VERSION 5.7 ;
BUSBITCHARS "[]" ;
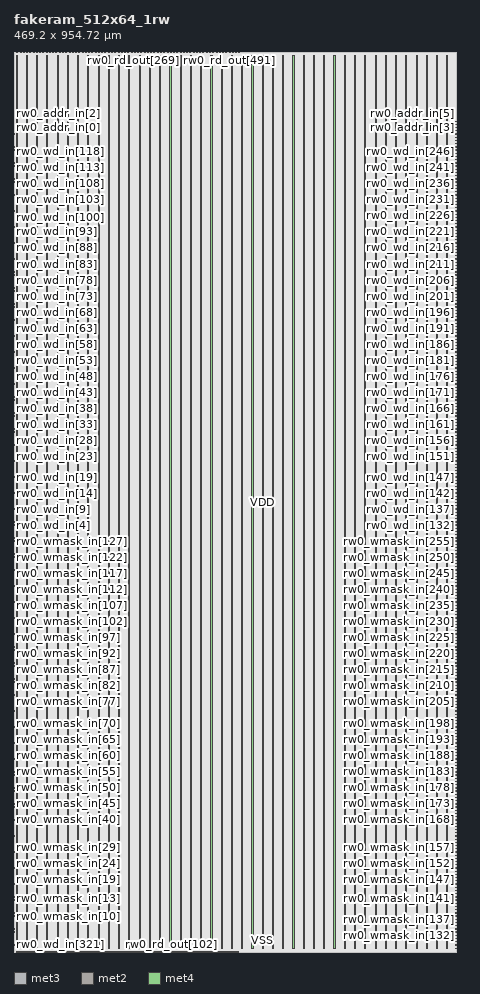
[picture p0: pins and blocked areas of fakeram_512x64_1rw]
MACRO fakeram_512x64_1rw
  FOREIGN fakeram_512x64_1rw 0 0 ;
  SYMMETRY X Y R90 ;
  SIZE 469.200 BY 954.720 ;
  CLASS BLOCK ;
  PIN rw0_wmask_in[0]
    DIRECTION INPUT ;
    USE SIGNAL ;
    SHAPE ABUTMENT ;
    PORT
      LAYER met3 ;
      RECT 0.000 3.930 0.900 4.230 ;
    END
  END rw0_wmask_in[0]
  PIN rw0_wmask_in[1]
    DIRECTION INPUT ;
    USE SIGNAL ;
    SHAPE ABUTMENT ;
    PORT
      LAYER met3 ;
      RECT 0.000 7.330 0.900 7.630 ;
    END
  END rw0_wmask_in[1]
  PIN rw0_wmask_in[2]
    DIRECTION INPUT ;
    USE SIGNAL ;
    SHAPE ABUTMENT ;
    PORT
      LAYER met3 ;
      RECT 0.000 10.730 0.900 11.030 ;
    END
  END rw0_wmask_in[2]
  PIN rw0_wmask_in[3]
    DIRECTION INPUT ;
    USE SIGNAL ;
    SHAPE ABUTMENT ;
    PORT
      LAYER met3 ;
      RECT 0.000 14.130 0.900 14.430 ;
    END
  END rw0_wmask_in[3]
  PIN rw0_wmask_in[4]
    DIRECTION INPUT ;
    USE SIGNAL ;
    SHAPE ABUTMENT ;
    PORT
      LAYER met3 ;
      RECT 0.000 17.530 0.900 17.830 ;
    END
  END rw0_wmask_in[4]
  PIN rw0_wmask_in[5]
    DIRECTION INPUT ;
    USE SIGNAL ;
    SHAPE ABUTMENT ;
    PORT
      LAYER met3 ;
      RECT 0.000 20.930 0.900 21.230 ;
    END
  END rw0_wmask_in[5]
  PIN rw0_wmask_in[6]
    DIRECTION INPUT ;
    USE SIGNAL ;
    SHAPE ABUTMENT ;
    PORT
      LAYER met3 ;
      RECT 0.000 24.330 0.900 24.630 ;
    END
  END rw0_wmask_in[6]
  PIN rw0_wmask_in[7]
    DIRECTION INPUT ;
    USE SIGNAL ;
    SHAPE ABUTMENT ;
    PORT
      LAYER met3 ;
      RECT 0.000 27.730 0.900 28.030 ;
    END
  END rw0_wmask_in[7]
  PIN rw0_wmask_in[8]
    DIRECTION INPUT ;
    USE SIGNAL ;
    SHAPE ABUTMENT ;
    PORT
      LAYER met3 ;
      RECT 0.000 31.130 0.900 31.430 ;
    END
  END rw0_wmask_in[8]
  PIN rw0_wmask_in[9]
    DIRECTION INPUT ;
    USE SIGNAL ;
    SHAPE ABUTMENT ;
    PORT
      LAYER met3 ;
      RECT 0.000 34.530 0.900 34.830 ;
    END
  END rw0_wmask_in[9]
  PIN rw0_wmask_in[10]
    DIRECTION INPUT ;
    USE SIGNAL ;
    SHAPE ABUTMENT ;
    PORT
      LAYER met3 ;
      RECT 0.000 37.930 0.900 38.230 ;
    END
  END rw0_wmask_in[10]
  PIN rw0_wmask_in[11]
    DIRECTION INPUT ;
    USE SIGNAL ;
    SHAPE ABUTMENT ;
    PORT
      LAYER met3 ;
      RECT 0.000 41.330 0.900 41.630 ;
    END
  END rw0_wmask_in[11]
  PIN rw0_wmask_in[12]
    DIRECTION INPUT ;
    USE SIGNAL ;
    SHAPE ABUTMENT ;
    PORT
      LAYER met3 ;
      RECT 0.000 44.730 0.900 45.030 ;
    END
  END rw0_wmask_in[12]
  PIN rw0_wmask_in[13]
    DIRECTION INPUT ;
    USE SIGNAL ;
    SHAPE ABUTMENT ;
    PORT
      LAYER met3 ;
      RECT 0.000 48.130 0.900 48.430 ;
    END
  END rw0_wmask_in[13]
  PIN rw0_wmask_in[14]
    DIRECTION INPUT ;
    USE SIGNAL ;
    SHAPE ABUTMENT ;
    PORT
      LAYER met3 ;
      RECT 0.000 51.530 0.900 51.830 ;
    END
  END rw0_wmask_in[14]
  PIN rw0_wmask_in[15]
    DIRECTION INPUT ;
    USE SIGNAL ;
    SHAPE ABUTMENT ;
    PORT
      LAYER met3 ;
      RECT 0.000 54.930 0.900 55.230 ;
    END
  END rw0_wmask_in[15]
  PIN rw0_wmask_in[16]
    DIRECTION INPUT ;
    USE SIGNAL ;
    SHAPE ABUTMENT ;
    PORT
      LAYER met3 ;
      RECT 0.000 58.330 0.900 58.630 ;
    END
  END rw0_wmask_in[16]
  PIN rw0_wmask_in[17]
    DIRECTION INPUT ;
    USE SIGNAL ;
    SHAPE ABUTMENT ;
    PORT
      LAYER met3 ;
      RECT 0.000 61.730 0.900 62.030 ;
    END
  END rw0_wmask_in[17]
  PIN rw0_wmask_in[18]
    DIRECTION INPUT ;
    USE SIGNAL ;
    SHAPE ABUTMENT ;
    PORT
      LAYER met3 ;
      RECT 0.000 65.130 0.900 65.430 ;
    END
  END rw0_wmask_in[18]
  PIN rw0_wmask_in[19]
    DIRECTION INPUT ;
    USE SIGNAL ;
    SHAPE ABUTMENT ;
    PORT
      LAYER met3 ;
      RECT 0.000 68.530 0.900 68.830 ;
    END
  END rw0_wmask_in[19]
  PIN rw0_wmask_in[20]
    DIRECTION INPUT ;
    USE SIGNAL ;
    SHAPE ABUTMENT ;
    PORT
      LAYER met3 ;
      RECT 0.000 71.930 0.900 72.230 ;
    END
  END rw0_wmask_in[20]
  PIN rw0_wmask_in[21]
    DIRECTION INPUT ;
    USE SIGNAL ;
    SHAPE ABUTMENT ;
    PORT
      LAYER met3 ;
      RECT 0.000 75.330 0.900 75.630 ;
    END
  END rw0_wmask_in[21]
  PIN rw0_wmask_in[22]
    DIRECTION INPUT ;
    USE SIGNAL ;
    SHAPE ABUTMENT ;
    PORT
      LAYER met3 ;
      RECT 0.000 78.730 0.900 79.030 ;
    END
  END rw0_wmask_in[22]
  PIN rw0_wmask_in[23]
    DIRECTION INPUT ;
    USE SIGNAL ;
    SHAPE ABUTMENT ;
    PORT
      LAYER met3 ;
      RECT 0.000 82.130 0.900 82.430 ;
    END
  END rw0_wmask_in[23]
  PIN rw0_wmask_in[24]
    DIRECTION INPUT ;
    USE SIGNAL ;
    SHAPE ABUTMENT ;
    PORT
      LAYER met3 ;
      RECT 0.000 85.530 0.900 85.830 ;
    END
  END rw0_wmask_in[24]
  PIN rw0_wmask_in[25]
    DIRECTION INPUT ;
    USE SIGNAL ;
    SHAPE ABUTMENT ;
    PORT
      LAYER met3 ;
      RECT 0.000 88.930 0.900 89.230 ;
    END
  END rw0_wmask_in[25]
  PIN rw0_wmask_in[26]
    DIRECTION INPUT ;
    USE SIGNAL ;
    SHAPE ABUTMENT ;
    PORT
      LAYER met3 ;
      RECT 0.000 92.330 0.900 92.630 ;
    END
  END rw0_wmask_in[26]
  PIN rw0_wmask_in[27]
    DIRECTION INPUT ;
    USE SIGNAL ;
    SHAPE ABUTMENT ;
    PORT
      LAYER met3 ;
      RECT 0.000 95.730 0.900 96.030 ;
    END
  END rw0_wmask_in[27]
  PIN rw0_wmask_in[28]
    DIRECTION INPUT ;
    USE SIGNAL ;
    SHAPE ABUTMENT ;
    PORT
      LAYER met3 ;
      RECT 0.000 99.130 0.900 99.430 ;
    END
  END rw0_wmask_in[28]
  PIN rw0_wmask_in[29]
    DIRECTION INPUT ;
    USE SIGNAL ;
    SHAPE ABUTMENT ;
    PORT
      LAYER met3 ;
      RECT 0.000 102.530 0.900 102.830 ;
    END
  END rw0_wmask_in[29]
  PIN rw0_wmask_in[30]
    DIRECTION INPUT ;
    USE SIGNAL ;
    SHAPE ABUTMENT ;
    PORT
      LAYER met3 ;
      RECT 0.000 105.930 0.900 106.230 ;
    END
  END rw0_wmask_in[30]
  PIN rw0_wmask_in[31]
    DIRECTION INPUT ;
    USE SIGNAL ;
    SHAPE ABUTMENT ;
    PORT
      LAYER met3 ;
      RECT 0.000 109.330 0.900 109.630 ;
    END
  END rw0_wmask_in[31]
  PIN rw0_wmask_in[32]
    DIRECTION INPUT ;
    USE SIGNAL ;
    SHAPE ABUTMENT ;
    PORT
      LAYER met3 ;
      RECT 0.000 112.730 0.900 113.030 ;
    END
  END rw0_wmask_in[32]
  PIN rw0_wmask_in[33]
    DIRECTION INPUT ;
    USE SIGNAL ;
    SHAPE ABUTMENT ;
    PORT
      LAYER met3 ;
      RECT 0.000 116.130 0.900 116.430 ;
    END
  END rw0_wmask_in[33]
  PIN rw0_wmask_in[34]
    DIRECTION INPUT ;
    USE SIGNAL ;
    SHAPE ABUTMENT ;
    PORT
      LAYER met3 ;
      RECT 0.000 119.530 0.900 119.830 ;
    END
  END rw0_wmask_in[34]
  PIN rw0_wmask_in[35]
    DIRECTION INPUT ;
    USE SIGNAL ;
    SHAPE ABUTMENT ;
    PORT
      LAYER met3 ;
      RECT 0.000 122.930 0.900 123.230 ;
    END
  END rw0_wmask_in[35]
  PIN rw0_wmask_in[36]
    DIRECTION INPUT ;
    USE SIGNAL ;
    SHAPE ABUTMENT ;
    PORT
      LAYER met3 ;
      RECT 0.000 126.330 0.900 126.630 ;
    END
  END rw0_wmask_in[36]
  PIN rw0_wmask_in[37]
    DIRECTION INPUT ;
    USE SIGNAL ;
    SHAPE ABUTMENT ;
    PORT
      LAYER met3 ;
      RECT 0.000 129.730 0.900 130.030 ;
    END
  END rw0_wmask_in[37]
  PIN rw0_wmask_in[38]
    DIRECTION INPUT ;
    USE SIGNAL ;
    SHAPE ABUTMENT ;
    PORT
      LAYER met3 ;
      RECT 0.000 133.130 0.900 133.430 ;
    END
  END rw0_wmask_in[38]
  PIN rw0_wmask_in[39]
    DIRECTION INPUT ;
    USE SIGNAL ;
    SHAPE ABUTMENT ;
    PORT
      LAYER met3 ;
      RECT 0.000 136.530 0.900 136.830 ;
    END
  END rw0_wmask_in[39]
  PIN rw0_wmask_in[40]
    DIRECTION INPUT ;
    USE SIGNAL ;
    SHAPE ABUTMENT ;
    PORT
      LAYER met3 ;
      RECT 0.000 139.930 0.900 140.230 ;
    END
  END rw0_wmask_in[40]
  PIN rw0_wmask_in[41]
    DIRECTION INPUT ;
    USE SIGNAL ;
    SHAPE ABUTMENT ;
    PORT
      LAYER met3 ;
      RECT 0.000 143.330 0.900 143.630 ;
    END
  END rw0_wmask_in[41]
  PIN rw0_wmask_in[42]
    DIRECTION INPUT ;
    USE SIGNAL ;
    SHAPE ABUTMENT ;
    PORT
      LAYER met3 ;
      RECT 0.000 146.730 0.900 147.030 ;
    END
  END rw0_wmask_in[42]
  PIN rw0_wmask_in[43]
    DIRECTION INPUT ;
    USE SIGNAL ;
    SHAPE ABUTMENT ;
    PORT
      LAYER met3 ;
      RECT 0.000 150.130 0.900 150.430 ;
    END
  END rw0_wmask_in[43]
  PIN rw0_wmask_in[44]
    DIRECTION INPUT ;
    USE SIGNAL ;
    SHAPE ABUTMENT ;
    PORT
      LAYER met3 ;
      RECT 0.000 153.530 0.900 153.830 ;
    END
  END rw0_wmask_in[44]
  PIN rw0_wmask_in[45]
    DIRECTION INPUT ;
    USE SIGNAL ;
    SHAPE ABUTMENT ;
    PORT
      LAYER met3 ;
      RECT 0.000 156.930 0.900 157.230 ;
    END
  END rw0_wmask_in[45]
  PIN rw0_wmask_in[46]
    DIRECTION INPUT ;
    USE SIGNAL ;
    SHAPE ABUTMENT ;
    PORT
      LAYER met3 ;
      RECT 0.000 160.330 0.900 160.630 ;
    END
  END rw0_wmask_in[46]
  PIN rw0_wmask_in[47]
    DIRECTION INPUT ;
    USE SIGNAL ;
    SHAPE ABUTMENT ;
    PORT
      LAYER met3 ;
      RECT 0.000 163.730 0.900 164.030 ;
    END
  END rw0_wmask_in[47]
  PIN rw0_wmask_in[48]
    DIRECTION INPUT ;
    USE SIGNAL ;
    SHAPE ABUTMENT ;
    PORT
      LAYER met3 ;
      RECT 0.000 167.130 0.900 167.430 ;
    END
  END rw0_wmask_in[48]
  PIN rw0_wmask_in[49]
    DIRECTION INPUT ;
    USE SIGNAL ;
    SHAPE ABUTMENT ;
    PORT
      LAYER met3 ;
      RECT 0.000 170.530 0.900 170.830 ;
    END
  END rw0_wmask_in[49]
  PIN rw0_wmask_in[50]
    DIRECTION INPUT ;
    USE SIGNAL ;
    SHAPE ABUTMENT ;
    PORT
      LAYER met3 ;
      RECT 0.000 173.930 0.900 174.230 ;
    END
  END rw0_wmask_in[50]
  PIN rw0_wmask_in[51]
    DIRECTION INPUT ;
    USE SIGNAL ;
    SHAPE ABUTMENT ;
    PORT
      LAYER met3 ;
      RECT 0.000 177.330 0.900 177.630 ;
    END
  END rw0_wmask_in[51]
  PIN rw0_wmask_in[52]
    DIRECTION INPUT ;
    USE SIGNAL ;
    SHAPE ABUTMENT ;
    PORT
      LAYER met3 ;
      RECT 0.000 180.730 0.900 181.030 ;
    END
  END rw0_wmask_in[52]
  PIN rw0_wmask_in[53]
    DIRECTION INPUT ;
    USE SIGNAL ;
    SHAPE ABUTMENT ;
    PORT
      LAYER met3 ;
      RECT 0.000 184.130 0.900 184.430 ;
    END
  END rw0_wmask_in[53]
  PIN rw0_wmask_in[54]
    DIRECTION INPUT ;
    USE SIGNAL ;
    SHAPE ABUTMENT ;
    PORT
      LAYER met3 ;
      RECT 0.000 187.530 0.900 187.830 ;
    END
  END rw0_wmask_in[54]
  PIN rw0_wmask_in[55]
    DIRECTION INPUT ;
    USE SIGNAL ;
    SHAPE ABUTMENT ;
    PORT
      LAYER met3 ;
      RECT 0.000 190.930 0.900 191.230 ;
    END
  END rw0_wmask_in[55]
  PIN rw0_wmask_in[56]
    DIRECTION INPUT ;
    USE SIGNAL ;
    SHAPE ABUTMENT ;
    PORT
      LAYER met3 ;
      RECT 0.000 194.330 0.900 194.630 ;
    END
  END rw0_wmask_in[56]
  PIN rw0_wmask_in[57]
    DIRECTION INPUT ;
    USE SIGNAL ;
    SHAPE ABUTMENT ;
    PORT
      LAYER met3 ;
      RECT 0.000 197.730 0.900 198.030 ;
    END
  END rw0_wmask_in[57]
  PIN rw0_wmask_in[58]
    DIRECTION INPUT ;
    USE SIGNAL ;
    SHAPE ABUTMENT ;
    PORT
      LAYER met3 ;
      RECT 0.000 201.130 0.900 201.430 ;
    END
  END rw0_wmask_in[58]
  PIN rw0_wmask_in[59]
    DIRECTION INPUT ;
    USE SIGNAL ;
    SHAPE ABUTMENT ;
    PORT
      LAYER met3 ;
      RECT 0.000 204.530 0.900 204.830 ;
    END
  END rw0_wmask_in[59]
  PIN rw0_wmask_in[60]
    DIRECTION INPUT ;
    USE SIGNAL ;
    SHAPE ABUTMENT ;
    PORT
      LAYER met3 ;
      RECT 0.000 207.930 0.900 208.230 ;
    END
  END rw0_wmask_in[60]
  PIN rw0_wmask_in[61]
    DIRECTION INPUT ;
    USE SIGNAL ;
    SHAPE ABUTMENT ;
    PORT
      LAYER met3 ;
      RECT 0.000 211.330 0.900 211.630 ;
    END
  END rw0_wmask_in[61]
  PIN rw0_wmask_in[62]
    DIRECTION INPUT ;
    USE SIGNAL ;
    SHAPE ABUTMENT ;
    PORT
      LAYER met3 ;
      RECT 0.000 214.730 0.900 215.030 ;
    END
  END rw0_wmask_in[62]
  PIN rw0_wmask_in[63]
    DIRECTION INPUT ;
    USE SIGNAL ;
    SHAPE ABUTMENT ;
    PORT
      LAYER met3 ;
      RECT 0.000 218.130 0.900 218.430 ;
    END
  END rw0_wmask_in[63]
  PIN rw0_wmask_in[64]
    DIRECTION INPUT ;
    USE SIGNAL ;
    SHAPE ABUTMENT ;
    PORT
      LAYER met3 ;
      RECT 0.000 221.530 0.900 221.830 ;
    END
  END rw0_wmask_in[64]
  PIN rw0_wmask_in[65]
    DIRECTION INPUT ;
    USE SIGNAL ;
    SHAPE ABUTMENT ;
    PORT
      LAYER met3 ;
      RECT 0.000 224.930 0.900 225.230 ;
    END
  END rw0_wmask_in[65]
  PIN rw0_wmask_in[66]
    DIRECTION INPUT ;
    USE SIGNAL ;
    SHAPE ABUTMENT ;
    PORT
      LAYER met3 ;
      RECT 0.000 228.330 0.900 228.630 ;
    END
  END rw0_wmask_in[66]
  PIN rw0_wmask_in[67]
    DIRECTION INPUT ;
    USE SIGNAL ;
    SHAPE ABUTMENT ;
    PORT
      LAYER met3 ;
      RECT 0.000 231.730 0.900 232.030 ;
    END
  END rw0_wmask_in[67]
  PIN rw0_wmask_in[68]
    DIRECTION INPUT ;
    USE SIGNAL ;
    SHAPE ABUTMENT ;
    PORT
      LAYER met3 ;
      RECT 0.000 235.130 0.900 235.430 ;
    END
  END rw0_wmask_in[68]
  PIN rw0_wmask_in[69]
    DIRECTION INPUT ;
    USE SIGNAL ;
    SHAPE ABUTMENT ;
    PORT
      LAYER met3 ;
      RECT 0.000 238.530 0.900 238.830 ;
    END
  END rw0_wmask_in[69]
  PIN rw0_wmask_in[70]
    DIRECTION INPUT ;
    USE SIGNAL ;
    SHAPE ABUTMENT ;
    PORT
      LAYER met3 ;
      RECT 0.000 241.930 0.900 242.230 ;
    END
  END rw0_wmask_in[70]
  PIN rw0_wmask_in[71]
    DIRECTION INPUT ;
    USE SIGNAL ;
    SHAPE ABUTMENT ;
    PORT
      LAYER met3 ;
      RECT 0.000 245.330 0.900 245.630 ;
    END
  END rw0_wmask_in[71]
  PIN rw0_wmask_in[72]
    DIRECTION INPUT ;
    USE SIGNAL ;
    SHAPE ABUTMENT ;
    PORT
      LAYER met3 ;
      RECT 0.000 248.730 0.900 249.030 ;
    END
  END rw0_wmask_in[72]
  PIN rw0_wmask_in[73]
    DIRECTION INPUT ;
    USE SIGNAL ;
    SHAPE ABUTMENT ;
    PORT
      LAYER met3 ;
      RECT 0.000 252.130 0.900 252.430 ;
    END
  END rw0_wmask_in[73]
  PIN rw0_wmask_in[74]
    DIRECTION INPUT ;
    USE SIGNAL ;
    SHAPE ABUTMENT ;
    PORT
      LAYER met3 ;
      RECT 0.000 255.530 0.900 255.830 ;
    END
  END rw0_wmask_in[74]
  PIN rw0_wmask_in[75]
    DIRECTION INPUT ;
    USE SIGNAL ;
    SHAPE ABUTMENT ;
    PORT
      LAYER met3 ;
      RECT 0.000 258.930 0.900 259.230 ;
    END
  END rw0_wmask_in[75]
  PIN rw0_wmask_in[76]
    DIRECTION INPUT ;
    USE SIGNAL ;
    SHAPE ABUTMENT ;
    PORT
      LAYER met3 ;
      RECT 0.000 262.330 0.900 262.630 ;
    END
  END rw0_wmask_in[76]
  PIN rw0_wmask_in[77]
    DIRECTION INPUT ;
    USE SIGNAL ;
    SHAPE ABUTMENT ;
    PORT
      LAYER met3 ;
      RECT 0.000 265.730 0.900 266.030 ;
    END
  END rw0_wmask_in[77]
  PIN rw0_wmask_in[78]
    DIRECTION INPUT ;
    USE SIGNAL ;
    SHAPE ABUTMENT ;
    PORT
      LAYER met3 ;
      RECT 0.000 269.130 0.900 269.430 ;
    END
  END rw0_wmask_in[78]
  PIN rw0_wmask_in[79]
    DIRECTION INPUT ;
    USE SIGNAL ;
    SHAPE ABUTMENT ;
    PORT
      LAYER met3 ;
      RECT 0.000 272.530 0.900 272.830 ;
    END
  END rw0_wmask_in[79]
  PIN rw0_wmask_in[80]
    DIRECTION INPUT ;
    USE SIGNAL ;
    SHAPE ABUTMENT ;
    PORT
      LAYER met3 ;
      RECT 0.000 275.930 0.900 276.230 ;
    END
  END rw0_wmask_in[80]
  PIN rw0_wmask_in[81]
    DIRECTION INPUT ;
    USE SIGNAL ;
    SHAPE ABUTMENT ;
    PORT
      LAYER met3 ;
      RECT 0.000 279.330 0.900 279.630 ;
    END
  END rw0_wmask_in[81]
  PIN rw0_wmask_in[82]
    DIRECTION INPUT ;
    USE SIGNAL ;
    SHAPE ABUTMENT ;
    PORT
      LAYER met3 ;
      RECT 0.000 282.730 0.900 283.030 ;
    END
  END rw0_wmask_in[82]
  PIN rw0_wmask_in[83]
    DIRECTION INPUT ;
    USE SIGNAL ;
    SHAPE ABUTMENT ;
    PORT
      LAYER met3 ;
      RECT 0.000 286.130 0.900 286.430 ;
    END
  END rw0_wmask_in[83]
  PIN rw0_wmask_in[84]
    DIRECTION INPUT ;
    USE SIGNAL ;
    SHAPE ABUTMENT ;
    PORT
      LAYER met3 ;
      RECT 0.000 289.530 0.900 289.830 ;
    END
  END rw0_wmask_in[84]
  PIN rw0_wmask_in[85]
    DIRECTION INPUT ;
    USE SIGNAL ;
    SHAPE ABUTMENT ;
    PORT
      LAYER met3 ;
      RECT 0.000 292.930 0.900 293.230 ;
    END
  END rw0_wmask_in[85]
  PIN rw0_wmask_in[86]
    DIRECTION INPUT ;
    USE SIGNAL ;
    SHAPE ABUTMENT ;
    PORT
      LAYER met3 ;
      RECT 0.000 296.330 0.900 296.630 ;
    END
  END rw0_wmask_in[86]
  PIN rw0_wmask_in[87]
    DIRECTION INPUT ;
    USE SIGNAL ;
    SHAPE ABUTMENT ;
    PORT
      LAYER met3 ;
      RECT 0.000 299.730 0.900 300.030 ;
    END
  END rw0_wmask_in[87]
  PIN rw0_wmask_in[88]
    DIRECTION INPUT ;
    USE SIGNAL ;
    SHAPE ABUTMENT ;
    PORT
      LAYER met3 ;
      RECT 0.000 303.130 0.900 303.430 ;
    END
  END rw0_wmask_in[88]
  PIN rw0_wmask_in[89]
    DIRECTION INPUT ;
    USE SIGNAL ;
    SHAPE ABUTMENT ;
    PORT
      LAYER met3 ;
      RECT 0.000 306.530 0.900 306.830 ;
    END
  END rw0_wmask_in[89]
  PIN rw0_wmask_in[90]
    DIRECTION INPUT ;
    USE SIGNAL ;
    SHAPE ABUTMENT ;
    PORT
      LAYER met3 ;
      RECT 0.000 309.930 0.900 310.230 ;
    END
  END rw0_wmask_in[90]
  PIN rw0_wmask_in[91]
    DIRECTION INPUT ;
    USE SIGNAL ;
    SHAPE ABUTMENT ;
    PORT
      LAYER met3 ;
      RECT 0.000 313.330 0.900 313.630 ;
    END
  END rw0_wmask_in[91]
  PIN rw0_wmask_in[92]
    DIRECTION INPUT ;
    USE SIGNAL ;
    SHAPE ABUTMENT ;
    PORT
      LAYER met3 ;
      RECT 0.000 316.730 0.900 317.030 ;
    END
  END rw0_wmask_in[92]
  PIN rw0_wmask_in[93]
    DIRECTION INPUT ;
    USE SIGNAL ;
    SHAPE ABUTMENT ;
    PORT
      LAYER met3 ;
      RECT 0.000 320.130 0.900 320.430 ;
    END
  END rw0_wmask_in[93]
  PIN rw0_wmask_in[94]
    DIRECTION INPUT ;
    USE SIGNAL ;
    SHAPE ABUTMENT ;
    PORT
      LAYER met3 ;
      RECT 0.000 323.530 0.900 323.830 ;
    END
  END rw0_wmask_in[94]
  PIN rw0_wmask_in[95]
    DIRECTION INPUT ;
    USE SIGNAL ;
    SHAPE ABUTMENT ;
    PORT
      LAYER met3 ;
      RECT 0.000 326.930 0.900 327.230 ;
    END
  END rw0_wmask_in[95]
  PIN rw0_wmask_in[96]
    DIRECTION INPUT ;
    USE SIGNAL ;
    SHAPE ABUTMENT ;
    PORT
      LAYER met3 ;
      RECT 0.000 330.330 0.900 330.630 ;
    END
  END rw0_wmask_in[96]
  PIN rw0_wmask_in[97]
    DIRECTION INPUT ;
    USE SIGNAL ;
    SHAPE ABUTMENT ;
    PORT
      LAYER met3 ;
      RECT 0.000 333.730 0.900 334.030 ;
    END
  END rw0_wmask_in[97]
  PIN rw0_wmask_in[98]
    DIRECTION INPUT ;
    USE SIGNAL ;
    SHAPE ABUTMENT ;
    PORT
      LAYER met3 ;
      RECT 0.000 337.130 0.900 337.430 ;
    END
  END rw0_wmask_in[98]
  PIN rw0_wmask_in[99]
    DIRECTION INPUT ;
    USE SIGNAL ;
    SHAPE ABUTMENT ;
    PORT
      LAYER met3 ;
      RECT 0.000 340.530 0.900 340.830 ;
    END
  END rw0_wmask_in[99]
  PIN rw0_wmask_in[100]
    DIRECTION INPUT ;
    USE SIGNAL ;
    SHAPE ABUTMENT ;
    PORT
      LAYER met3 ;
      RECT 0.000 343.930 0.900 344.230 ;
    END
  END rw0_wmask_in[100]
  PIN rw0_wmask_in[101]
    DIRECTION INPUT ;
    USE SIGNAL ;
    SHAPE ABUTMENT ;
    PORT
      LAYER met3 ;
      RECT 0.000 347.330 0.900 347.630 ;
    END
  END rw0_wmask_in[101]
  PIN rw0_wmask_in[102]
    DIRECTION INPUT ;
    USE SIGNAL ;
    SHAPE ABUTMENT ;
    PORT
      LAYER met3 ;
      RECT 0.000 350.730 0.900 351.030 ;
    END
  END rw0_wmask_in[102]
  PIN rw0_wmask_in[103]
    DIRECTION INPUT ;
    USE SIGNAL ;
    SHAPE ABUTMENT ;
    PORT
      LAYER met3 ;
      RECT 0.000 354.130 0.900 354.430 ;
    END
  END rw0_wmask_in[103]
  PIN rw0_wmask_in[104]
    DIRECTION INPUT ;
    USE SIGNAL ;
    SHAPE ABUTMENT ;
    PORT
      LAYER met3 ;
      RECT 0.000 357.530 0.900 357.830 ;
    END
  END rw0_wmask_in[104]
  PIN rw0_wmask_in[105]
    DIRECTION INPUT ;
    USE SIGNAL ;
    SHAPE ABUTMENT ;
    PORT
      LAYER met3 ;
      RECT 0.000 360.930 0.900 361.230 ;
    END
  END rw0_wmask_in[105]
  PIN rw0_wmask_in[106]
    DIRECTION INPUT ;
    USE SIGNAL ;
    SHAPE ABUTMENT ;
    PORT
      LAYER met3 ;
      RECT 0.000 364.330 0.900 364.630 ;
    END
  END rw0_wmask_in[106]
  PIN rw0_wmask_in[107]
    DIRECTION INPUT ;
    USE SIGNAL ;
    SHAPE ABUTMENT ;
    PORT
      LAYER met3 ;
      RECT 0.000 367.730 0.900 368.030 ;
    END
  END rw0_wmask_in[107]
  PIN rw0_wmask_in[108]
    DIRECTION INPUT ;
    USE SIGNAL ;
    SHAPE ABUTMENT ;
    PORT
      LAYER met3 ;
      RECT 0.000 371.130 0.900 371.430 ;
    END
  END rw0_wmask_in[108]
  PIN rw0_wmask_in[109]
    DIRECTION INPUT ;
    USE SIGNAL ;
    SHAPE ABUTMENT ;
    PORT
      LAYER met3 ;
      RECT 0.000 374.530 0.900 374.830 ;
    END
  END rw0_wmask_in[109]
  PIN rw0_wmask_in[110]
    DIRECTION INPUT ;
    USE SIGNAL ;
    SHAPE ABUTMENT ;
    PORT
      LAYER met3 ;
      RECT 0.000 377.930 0.900 378.230 ;
    END
  END rw0_wmask_in[110]
  PIN rw0_wmask_in[111]
    DIRECTION INPUT ;
    USE SIGNAL ;
    SHAPE ABUTMENT ;
    PORT
      LAYER met3 ;
      RECT 0.000 381.330 0.900 381.630 ;
    END
  END rw0_wmask_in[111]
  PIN rw0_wmask_in[112]
    DIRECTION INPUT ;
    USE SIGNAL ;
    SHAPE ABUTMENT ;
    PORT
      LAYER met3 ;
      RECT 0.000 384.730 0.900 385.030 ;
    END
  END rw0_wmask_in[112]
  PIN rw0_wmask_in[113]
    DIRECTION INPUT ;
    USE SIGNAL ;
    SHAPE ABUTMENT ;
    PORT
      LAYER met3 ;
      RECT 0.000 388.130 0.900 388.430 ;
    END
  END rw0_wmask_in[113]
  PIN rw0_wmask_in[114]
    DIRECTION INPUT ;
    USE SIGNAL ;
    SHAPE ABUTMENT ;
    PORT
      LAYER met3 ;
      RECT 0.000 391.530 0.900 391.830 ;
    END
  END rw0_wmask_in[114]
  PIN rw0_wmask_in[115]
    DIRECTION INPUT ;
    USE SIGNAL ;
    SHAPE ABUTMENT ;
    PORT
      LAYER met3 ;
      RECT 0.000 394.930 0.900 395.230 ;
    END
  END rw0_wmask_in[115]
  PIN rw0_wmask_in[116]
    DIRECTION INPUT ;
    USE SIGNAL ;
    SHAPE ABUTMENT ;
    PORT
      LAYER met3 ;
      RECT 0.000 398.330 0.900 398.630 ;
    END
  END rw0_wmask_in[116]
  PIN rw0_wmask_in[117]
    DIRECTION INPUT ;
    USE SIGNAL ;
    SHAPE ABUTMENT ;
    PORT
      LAYER met3 ;
      RECT 0.000 401.730 0.900 402.030 ;
    END
  END rw0_wmask_in[117]
  PIN rw0_wmask_in[118]
    DIRECTION INPUT ;
    USE SIGNAL ;
    SHAPE ABUTMENT ;
    PORT
      LAYER met3 ;
      RECT 0.000 405.130 0.900 405.430 ;
    END
  END rw0_wmask_in[118]
  PIN rw0_wmask_in[119]
    DIRECTION INPUT ;
    USE SIGNAL ;
    SHAPE ABUTMENT ;
    PORT
      LAYER met3 ;
      RECT 0.000 408.530 0.900 408.830 ;
    END
  END rw0_wmask_in[119]
  PIN rw0_wmask_in[120]
    DIRECTION INPUT ;
    USE SIGNAL ;
    SHAPE ABUTMENT ;
    PORT
      LAYER met3 ;
      RECT 0.000 411.930 0.900 412.230 ;
    END
  END rw0_wmask_in[120]
  PIN rw0_wmask_in[121]
    DIRECTION INPUT ;
    USE SIGNAL ;
    SHAPE ABUTMENT ;
    PORT
      LAYER met3 ;
      RECT 0.000 415.330 0.900 415.630 ;
    END
  END rw0_wmask_in[121]
  PIN rw0_wmask_in[122]
    DIRECTION INPUT ;
    USE SIGNAL ;
    SHAPE ABUTMENT ;
    PORT
      LAYER met3 ;
      RECT 0.000 418.730 0.900 419.030 ;
    END
  END rw0_wmask_in[122]
  PIN rw0_wmask_in[123]
    DIRECTION INPUT ;
    USE SIGNAL ;
    SHAPE ABUTMENT ;
    PORT
      LAYER met3 ;
      RECT 0.000 422.130 0.900 422.430 ;
    END
  END rw0_wmask_in[123]
  PIN rw0_wmask_in[124]
    DIRECTION INPUT ;
    USE SIGNAL ;
    SHAPE ABUTMENT ;
    PORT
      LAYER met3 ;
      RECT 0.000 425.530 0.900 425.830 ;
    END
  END rw0_wmask_in[124]
  PIN rw0_wmask_in[125]
    DIRECTION INPUT ;
    USE SIGNAL ;
    SHAPE ABUTMENT ;
    PORT
      LAYER met3 ;
      RECT 0.000 428.930 0.900 429.230 ;
    END
  END rw0_wmask_in[125]
  PIN rw0_wmask_in[126]
    DIRECTION INPUT ;
    USE SIGNAL ;
    SHAPE ABUTMENT ;
    PORT
      LAYER met3 ;
      RECT 0.000 432.330 0.900 432.630 ;
    END
  END rw0_wmask_in[126]
  PIN rw0_wmask_in[127]
    DIRECTION INPUT ;
    USE SIGNAL ;
    SHAPE ABUTMENT ;
    PORT
      LAYER met3 ;
      RECT 0.000 435.730 0.900 436.030 ;
    END
  END rw0_wmask_in[127]
  PIN rw0_wmask_in[128]
    DIRECTION INPUT ;
    USE SIGNAL ;
    SHAPE ABUTMENT ;
    PORT
      LAYER met3 ;
      RECT 468.300 3.930 469.200 4.230 ;
    END
  END rw0_wmask_in[128]
  PIN rw0_wmask_in[129]
    DIRECTION INPUT ;
    USE SIGNAL ;
    SHAPE ABUTMENT ;
    PORT
      LAYER met3 ;
      RECT 468.300 7.330 469.200 7.630 ;
    END
  END rw0_wmask_in[129]
  PIN rw0_wmask_in[130]
    DIRECTION INPUT ;
    USE SIGNAL ;
    SHAPE ABUTMENT ;
    PORT
      LAYER met3 ;
      RECT 468.300 10.730 469.200 11.030 ;
    END
  END rw0_wmask_in[130]
  PIN rw0_wmask_in[131]
    DIRECTION INPUT ;
    USE SIGNAL ;
    SHAPE ABUTMENT ;
    PORT
      LAYER met3 ;
      RECT 468.300 14.130 469.200 14.430 ;
    END
  END rw0_wmask_in[131]
  PIN rw0_wmask_in[132]
    DIRECTION INPUT ;
    USE SIGNAL ;
    SHAPE ABUTMENT ;
    PORT
      LAYER met3 ;
      RECT 468.300 17.530 469.200 17.830 ;
    END
  END rw0_wmask_in[132]
  PIN rw0_wmask_in[133]
    DIRECTION INPUT ;
    USE SIGNAL ;
    SHAPE ABUTMENT ;
    PORT
      LAYER met3 ;
      RECT 468.300 20.930 469.200 21.230 ;
    END
  END rw0_wmask_in[133]
  PIN rw0_wmask_in[134]
    DIRECTION INPUT ;
    USE SIGNAL ;
    SHAPE ABUTMENT ;
    PORT
      LAYER met3 ;
      RECT 468.300 24.330 469.200 24.630 ;
    END
  END rw0_wmask_in[134]
  PIN rw0_wmask_in[135]
    DIRECTION INPUT ;
    USE SIGNAL ;
    SHAPE ABUTMENT ;
    PORT
      LAYER met3 ;
      RECT 468.300 27.730 469.200 28.030 ;
    END
  END rw0_wmask_in[135]
  PIN rw0_wmask_in[136]
    DIRECTION INPUT ;
    USE SIGNAL ;
    SHAPE ABUTMENT ;
    PORT
      LAYER met3 ;
      RECT 468.300 31.130 469.200 31.430 ;
    END
  END rw0_wmask_in[136]
  PIN rw0_wmask_in[137]
    DIRECTION INPUT ;
    USE SIGNAL ;
    SHAPE ABUTMENT ;
    PORT
      LAYER met3 ;
      RECT 468.300 34.530 469.200 34.830 ;
    END
  END rw0_wmask_in[137]
  PIN rw0_wmask_in[138]
    DIRECTION INPUT ;
    USE SIGNAL ;
    SHAPE ABUTMENT ;
    PORT
      LAYER met3 ;
      RECT 468.300 37.930 469.200 38.230 ;
    END
  END rw0_wmask_in[138]
  PIN rw0_wmask_in[139]
    DIRECTION INPUT ;
    USE SIGNAL ;
    SHAPE ABUTMENT ;
    PORT
      LAYER met3 ;
      RECT 468.300 41.330 469.200 41.630 ;
    END
  END rw0_wmask_in[139]
  PIN rw0_wmask_in[140]
    DIRECTION INPUT ;
    USE SIGNAL ;
    SHAPE ABUTMENT ;
    PORT
      LAYER met3 ;
      RECT 468.300 44.730 469.200 45.030 ;
    END
  END rw0_wmask_in[140]
  PIN rw0_wmask_in[141]
    DIRECTION INPUT ;
    USE SIGNAL ;
    SHAPE ABUTMENT ;
    PORT
      LAYER met3 ;
      RECT 468.300 48.130 469.200 48.430 ;
    END
  END rw0_wmask_in[141]
  PIN rw0_wmask_in[142]
    DIRECTION INPUT ;
    USE SIGNAL ;
    SHAPE ABUTMENT ;
    PORT
      LAYER met3 ;
      RECT 468.300 51.530 469.200 51.830 ;
    END
  END rw0_wmask_in[142]
  PIN rw0_wmask_in[143]
    DIRECTION INPUT ;
    USE SIGNAL ;
    SHAPE ABUTMENT ;
    PORT
      LAYER met3 ;
      RECT 468.300 54.930 469.200 55.230 ;
    END
  END rw0_wmask_in[143]
  PIN rw0_wmask_in[144]
    DIRECTION INPUT ;
    USE SIGNAL ;
    SHAPE ABUTMENT ;
    PORT
      LAYER met3 ;
      RECT 468.300 58.330 469.200 58.630 ;
    END
  END rw0_wmask_in[144]
  PIN rw0_wmask_in[145]
    DIRECTION INPUT ;
    USE SIGNAL ;
    SHAPE ABUTMENT ;
    PORT
      LAYER met3 ;
      RECT 468.300 61.730 469.200 62.030 ;
    END
  END rw0_wmask_in[145]
  PIN rw0_wmask_in[146]
    DIRECTION INPUT ;
    USE SIGNAL ;
    SHAPE ABUTMENT ;
    PORT
      LAYER met3 ;
      RECT 468.300 65.130 469.200 65.430 ;
    END
  END rw0_wmask_in[146]
  PIN rw0_wmask_in[147]
    DIRECTION INPUT ;
    USE SIGNAL ;
    SHAPE ABUTMENT ;
    PORT
      LAYER met3 ;
      RECT 468.300 68.530 469.200 68.830 ;
    END
  END rw0_wmask_in[147]
  PIN rw0_wmask_in[148]
    DIRECTION INPUT ;
    USE SIGNAL ;
    SHAPE ABUTMENT ;
    PORT
      LAYER met3 ;
      RECT 468.300 71.930 469.200 72.230 ;
    END
  END rw0_wmask_in[148]
  PIN rw0_wmask_in[149]
    DIRECTION INPUT ;
    USE SIGNAL ;
    SHAPE ABUTMENT ;
    PORT
      LAYER met3 ;
      RECT 468.300 75.330 469.200 75.630 ;
    END
  END rw0_wmask_in[149]
  PIN rw0_wmask_in[150]
    DIRECTION INPUT ;
    USE SIGNAL ;
    SHAPE ABUTMENT ;
    PORT
      LAYER met3 ;
      RECT 468.300 78.730 469.200 79.030 ;
    END
  END rw0_wmask_in[150]
  PIN rw0_wmask_in[151]
    DIRECTION INPUT ;
    USE SIGNAL ;
    SHAPE ABUTMENT ;
    PORT
      LAYER met3 ;
      RECT 468.300 82.130 469.200 82.430 ;
    END
  END rw0_wmask_in[151]
  PIN rw0_wmask_in[152]
    DIRECTION INPUT ;
    USE SIGNAL ;
    SHAPE ABUTMENT ;
    PORT
      LAYER met3 ;
      RECT 468.300 85.530 469.200 85.830 ;
    END
  END rw0_wmask_in[152]
  PIN rw0_wmask_in[153]
    DIRECTION INPUT ;
    USE SIGNAL ;
    SHAPE ABUTMENT ;
    PORT
      LAYER met3 ;
      RECT 468.300 88.930 469.200 89.230 ;
    END
  END rw0_wmask_in[153]
  PIN rw0_wmask_in[154]
    DIRECTION INPUT ;
    USE SIGNAL ;
    SHAPE ABUTMENT ;
    PORT
      LAYER met3 ;
      RECT 468.300 92.330 469.200 92.630 ;
    END
  END rw0_wmask_in[154]
  PIN rw0_wmask_in[155]
    DIRECTION INPUT ;
    USE SIGNAL ;
    SHAPE ABUTMENT ;
    PORT
      LAYER met3 ;
      RECT 468.300 95.730 469.200 96.030 ;
    END
  END rw0_wmask_in[155]
  PIN rw0_wmask_in[156]
    DIRECTION INPUT ;
    USE SIGNAL ;
    SHAPE ABUTMENT ;
    PORT
      LAYER met3 ;
      RECT 468.300 99.130 469.200 99.430 ;
    END
  END rw0_wmask_in[156]
  PIN rw0_wmask_in[157]
    DIRECTION INPUT ;
    USE SIGNAL ;
    SHAPE ABUTMENT ;
    PORT
      LAYER met3 ;
      RECT 468.300 102.530 469.200 102.830 ;
    END
  END rw0_wmask_in[157]
  PIN rw0_wmask_in[158]
    DIRECTION INPUT ;
    USE SIGNAL ;
    SHAPE ABUTMENT ;
    PORT
      LAYER met3 ;
      RECT 468.300 105.930 469.200 106.230 ;
    END
  END rw0_wmask_in[158]
  PIN rw0_wmask_in[159]
    DIRECTION INPUT ;
    USE SIGNAL ;
    SHAPE ABUTMENT ;
    PORT
      LAYER met3 ;
      RECT 468.300 109.330 469.200 109.630 ;
    END
  END rw0_wmask_in[159]
  PIN rw0_wmask_in[160]
    DIRECTION INPUT ;
    USE SIGNAL ;
    SHAPE ABUTMENT ;
    PORT
      LAYER met3 ;
      RECT 468.300 112.730 469.200 113.030 ;
    END
  END rw0_wmask_in[160]
  PIN rw0_wmask_in[161]
    DIRECTION INPUT ;
    USE SIGNAL ;
    SHAPE ABUTMENT ;
    PORT
      LAYER met3 ;
      RECT 468.300 116.130 469.200 116.430 ;
    END
  END rw0_wmask_in[161]
  PIN rw0_wmask_in[162]
    DIRECTION INPUT ;
    USE SIGNAL ;
    SHAPE ABUTMENT ;
    PORT
      LAYER met3 ;
      RECT 468.300 119.530 469.200 119.830 ;
    END
  END rw0_wmask_in[162]
  PIN rw0_wmask_in[163]
    DIRECTION INPUT ;
    USE SIGNAL ;
    SHAPE ABUTMENT ;
    PORT
      LAYER met3 ;
      RECT 468.300 122.930 469.200 123.230 ;
    END
  END rw0_wmask_in[163]
  PIN rw0_wmask_in[164]
    DIRECTION INPUT ;
    USE SIGNAL ;
    SHAPE ABUTMENT ;
    PORT
      LAYER met3 ;
      RECT 468.300 126.330 469.200 126.630 ;
    END
  END rw0_wmask_in[164]
  PIN rw0_wmask_in[165]
    DIRECTION INPUT ;
    USE SIGNAL ;
    SHAPE ABUTMENT ;
    PORT
      LAYER met3 ;
      RECT 468.300 129.730 469.200 130.030 ;
    END
  END rw0_wmask_in[165]
  PIN rw0_wmask_in[166]
    DIRECTION INPUT ;
    USE SIGNAL ;
    SHAPE ABUTMENT ;
    PORT
      LAYER met3 ;
      RECT 468.300 133.130 469.200 133.430 ;
    END
  END rw0_wmask_in[166]
  PIN rw0_wmask_in[167]
    DIRECTION INPUT ;
    USE SIGNAL ;
    SHAPE ABUTMENT ;
    PORT
      LAYER met3 ;
      RECT 468.300 136.530 469.200 136.830 ;
    END
  END rw0_wmask_in[167]
  PIN rw0_wmask_in[168]
    DIRECTION INPUT ;
    USE SIGNAL ;
    SHAPE ABUTMENT ;
    PORT
      LAYER met3 ;
      RECT 468.300 139.930 469.200 140.230 ;
    END
  END rw0_wmask_in[168]
  PIN rw0_wmask_in[169]
    DIRECTION INPUT ;
    USE SIGNAL ;
    SHAPE ABUTMENT ;
    PORT
      LAYER met3 ;
      RECT 468.300 143.330 469.200 143.630 ;
    END
  END rw0_wmask_in[169]
  PIN rw0_wmask_in[170]
    DIRECTION INPUT ;
    USE SIGNAL ;
    SHAPE ABUTMENT ;
    PORT
      LAYER met3 ;
      RECT 468.300 146.730 469.200 147.030 ;
    END
  END rw0_wmask_in[170]
  PIN rw0_wmask_in[171]
    DIRECTION INPUT ;
    USE SIGNAL ;
    SHAPE ABUTMENT ;
    PORT
      LAYER met3 ;
      RECT 468.300 150.130 469.200 150.430 ;
    END
  END rw0_wmask_in[171]
  PIN rw0_wmask_in[172]
    DIRECTION INPUT ;
    USE SIGNAL ;
    SHAPE ABUTMENT ;
    PORT
      LAYER met3 ;
      RECT 468.300 153.530 469.200 153.830 ;
    END
  END rw0_wmask_in[172]
  PIN rw0_wmask_in[173]
    DIRECTION INPUT ;
    USE SIGNAL ;
    SHAPE ABUTMENT ;
    PORT
      LAYER met3 ;
      RECT 468.300 156.930 469.200 157.230 ;
    END
  END rw0_wmask_in[173]
  PIN rw0_wmask_in[174]
    DIRECTION INPUT ;
    USE SIGNAL ;
    SHAPE ABUTMENT ;
    PORT
      LAYER met3 ;
      RECT 468.300 160.330 469.200 160.630 ;
    END
  END rw0_wmask_in[174]
  PIN rw0_wmask_in[175]
    DIRECTION INPUT ;
    USE SIGNAL ;
    SHAPE ABUTMENT ;
    PORT
      LAYER met3 ;
      RECT 468.300 163.730 469.200 164.030 ;
    END
  END rw0_wmask_in[175]
  PIN rw0_wmask_in[176]
    DIRECTION INPUT ;
    USE SIGNAL ;
    SHAPE ABUTMENT ;
    PORT
      LAYER met3 ;
      RECT 468.300 167.130 469.200 167.430 ;
    END
  END rw0_wmask_in[176]
  PIN rw0_wmask_in[177]
    DIRECTION INPUT ;
    USE SIGNAL ;
    SHAPE ABUTMENT ;
    PORT
      LAYER met3 ;
      RECT 468.300 170.530 469.200 170.830 ;
    END
  END rw0_wmask_in[177]
  PIN rw0_wmask_in[178]
    DIRECTION INPUT ;
    USE SIGNAL ;
    SHAPE ABUTMENT ;
    PORT
      LAYER met3 ;
      RECT 468.300 173.930 469.200 174.230 ;
    END
  END rw0_wmask_in[178]
  PIN rw0_wmask_in[179]
    DIRECTION INPUT ;
    USE SIGNAL ;
    SHAPE ABUTMENT ;
    PORT
      LAYER met3 ;
      RECT 468.300 177.330 469.200 177.630 ;
    END
  END rw0_wmask_in[179]
  PIN rw0_wmask_in[180]
    DIRECTION INPUT ;
    USE SIGNAL ;
    SHAPE ABUTMENT ;
    PORT
      LAYER met3 ;
      RECT 468.300 180.730 469.200 181.030 ;
    END
  END rw0_wmask_in[180]
  PIN rw0_wmask_in[181]
    DIRECTION INPUT ;
    USE SIGNAL ;
    SHAPE ABUTMENT ;
    PORT
      LAYER met3 ;
      RECT 468.300 184.130 469.200 184.430 ;
    END
  END rw0_wmask_in[181]
  PIN rw0_wmask_in[182]
    DIRECTION INPUT ;
    USE SIGNAL ;
    SHAPE ABUTMENT ;
    PORT
      LAYER met3 ;
      RECT 468.300 187.530 469.200 187.830 ;
    END
  END rw0_wmask_in[182]
  PIN rw0_wmask_in[183]
    DIRECTION INPUT ;
    USE SIGNAL ;
    SHAPE ABUTMENT ;
    PORT
      LAYER met3 ;
      RECT 468.300 190.930 469.200 191.230 ;
    END
  END rw0_wmask_in[183]
  PIN rw0_wmask_in[184]
    DIRECTION INPUT ;
    USE SIGNAL ;
    SHAPE ABUTMENT ;
    PORT
      LAYER met3 ;
      RECT 468.300 194.330 469.200 194.630 ;
    END
  END rw0_wmask_in[184]
  PIN rw0_wmask_in[185]
    DIRECTION INPUT ;
    USE SIGNAL ;
    SHAPE ABUTMENT ;
    PORT
      LAYER met3 ;
      RECT 468.300 197.730 469.200 198.030 ;
    END
  END rw0_wmask_in[185]
  PIN rw0_wmask_in[186]
    DIRECTION INPUT ;
    USE SIGNAL ;
    SHAPE ABUTMENT ;
    PORT
      LAYER met3 ;
      RECT 468.300 201.130 469.200 201.430 ;
    END
  END rw0_wmask_in[186]
  PIN rw0_wmask_in[187]
    DIRECTION INPUT ;
    USE SIGNAL ;
    SHAPE ABUTMENT ;
    PORT
      LAYER met3 ;
      RECT 468.300 204.530 469.200 204.830 ;
    END
  END rw0_wmask_in[187]
  PIN rw0_wmask_in[188]
    DIRECTION INPUT ;
    USE SIGNAL ;
    SHAPE ABUTMENT ;
    PORT
      LAYER met3 ;
      RECT 468.300 207.930 469.200 208.230 ;
    END
  END rw0_wmask_in[188]
  PIN rw0_wmask_in[189]
    DIRECTION INPUT ;
    USE SIGNAL ;
    SHAPE ABUTMENT ;
    PORT
      LAYER met3 ;
      RECT 468.300 211.330 469.200 211.630 ;
    END
  END rw0_wmask_in[189]
  PIN rw0_wmask_in[190]
    DIRECTION INPUT ;
    USE SIGNAL ;
    SHAPE ABUTMENT ;
    PORT
      LAYER met3 ;
      RECT 468.300 214.730 469.200 215.030 ;
    END
  END rw0_wmask_in[190]
  PIN rw0_wmask_in[191]
    DIRECTION INPUT ;
    USE SIGNAL ;
    SHAPE ABUTMENT ;
    PORT
      LAYER met3 ;
      RECT 468.300 218.130 469.200 218.430 ;
    END
  END rw0_wmask_in[191]
  PIN rw0_wmask_in[192]
    DIRECTION INPUT ;
    USE SIGNAL ;
    SHAPE ABUTMENT ;
    PORT
      LAYER met3 ;
      RECT 468.300 221.530 469.200 221.830 ;
    END
  END rw0_wmask_in[192]
  PIN rw0_wmask_in[193]
    DIRECTION INPUT ;
    USE SIGNAL ;
    SHAPE ABUTMENT ;
    PORT
      LAYER met3 ;
      RECT 468.300 224.930 469.200 225.230 ;
    END
  END rw0_wmask_in[193]
  PIN rw0_wmask_in[194]
    DIRECTION INPUT ;
    USE SIGNAL ;
    SHAPE ABUTMENT ;
    PORT
      LAYER met3 ;
      RECT 468.300 228.330 469.200 228.630 ;
    END
  END rw0_wmask_in[194]
  PIN rw0_wmask_in[195]
    DIRECTION INPUT ;
    USE SIGNAL ;
    SHAPE ABUTMENT ;
    PORT
      LAYER met3 ;
      RECT 468.300 231.730 469.200 232.030 ;
    END
  END rw0_wmask_in[195]
  PIN rw0_wmask_in[196]
    DIRECTION INPUT ;
    USE SIGNAL ;
    SHAPE ABUTMENT ;
    PORT
      LAYER met3 ;
      RECT 468.300 235.130 469.200 235.430 ;
    END
  END rw0_wmask_in[196]
  PIN rw0_wmask_in[197]
    DIRECTION INPUT ;
    USE SIGNAL ;
    SHAPE ABUTMENT ;
    PORT
      LAYER met3 ;
      RECT 468.300 238.530 469.200 238.830 ;
    END
  END rw0_wmask_in[197]
  PIN rw0_wmask_in[198]
    DIRECTION INPUT ;
    USE SIGNAL ;
    SHAPE ABUTMENT ;
    PORT
      LAYER met3 ;
      RECT 468.300 241.930 469.200 242.230 ;
    END
  END rw0_wmask_in[198]
  PIN rw0_wmask_in[199]
    DIRECTION INPUT ;
    USE SIGNAL ;
    SHAPE ABUTMENT ;
    PORT
      LAYER met3 ;
      RECT 468.300 245.330 469.200 245.630 ;
    END
  END rw0_wmask_in[199]
  PIN rw0_wmask_in[200]
    DIRECTION INPUT ;
    USE SIGNAL ;
    SHAPE ABUTMENT ;
    PORT
      LAYER met3 ;
      RECT 468.300 248.730 469.200 249.030 ;
    END
  END rw0_wmask_in[200]
  PIN rw0_wmask_in[201]
    DIRECTION INPUT ;
    USE SIGNAL ;
    SHAPE ABUTMENT ;
    PORT
      LAYER met3 ;
      RECT 468.300 252.130 469.200 252.430 ;
    END
  END rw0_wmask_in[201]
  PIN rw0_wmask_in[202]
    DIRECTION INPUT ;
    USE SIGNAL ;
    SHAPE ABUTMENT ;
    PORT
      LAYER met3 ;
      RECT 468.300 255.530 469.200 255.830 ;
    END
  END rw0_wmask_in[202]
  PIN rw0_wmask_in[203]
    DIRECTION INPUT ;
    USE SIGNAL ;
    SHAPE ABUTMENT ;
    PORT
      LAYER met3 ;
      RECT 468.300 258.930 469.200 259.230 ;
    END
  END rw0_wmask_in[203]
  PIN rw0_wmask_in[204]
    DIRECTION INPUT ;
    USE SIGNAL ;
    SHAPE ABUTMENT ;
    PORT
      LAYER met3 ;
      RECT 468.300 262.330 469.200 262.630 ;
    END
  END rw0_wmask_in[204]
  PIN rw0_wmask_in[205]
    DIRECTION INPUT ;
    USE SIGNAL ;
    SHAPE ABUTMENT ;
    PORT
      LAYER met3 ;
      RECT 468.300 265.730 469.200 266.030 ;
    END
  END rw0_wmask_in[205]
  PIN rw0_wmask_in[206]
    DIRECTION INPUT ;
    USE SIGNAL ;
    SHAPE ABUTMENT ;
    PORT
      LAYER met3 ;
      RECT 468.300 269.130 469.200 269.430 ;
    END
  END rw0_wmask_in[206]
  PIN rw0_wmask_in[207]
    DIRECTION INPUT ;
    USE SIGNAL ;
    SHAPE ABUTMENT ;
    PORT
      LAYER met3 ;
      RECT 468.300 272.530 469.200 272.830 ;
    END
  END rw0_wmask_in[207]
  PIN rw0_wmask_in[208]
    DIRECTION INPUT ;
    USE SIGNAL ;
    SHAPE ABUTMENT ;
    PORT
      LAYER met3 ;
      RECT 468.300 275.930 469.200 276.230 ;
    END
  END rw0_wmask_in[208]
  PIN rw0_wmask_in[209]
    DIRECTION INPUT ;
    USE SIGNAL ;
    SHAPE ABUTMENT ;
    PORT
      LAYER met3 ;
      RECT 468.300 279.330 469.200 279.630 ;
    END
  END rw0_wmask_in[209]
  PIN rw0_wmask_in[210]
    DIRECTION INPUT ;
    USE SIGNAL ;
    SHAPE ABUTMENT ;
    PORT
      LAYER met3 ;
      RECT 468.300 282.730 469.200 283.030 ;
    END
  END rw0_wmask_in[210]
  PIN rw0_wmask_in[211]
    DIRECTION INPUT ;
    USE SIGNAL ;
    SHAPE ABUTMENT ;
    PORT
      LAYER met3 ;
      RECT 468.300 286.130 469.200 286.430 ;
    END
  END rw0_wmask_in[211]
  PIN rw0_wmask_in[212]
    DIRECTION INPUT ;
    USE SIGNAL ;
    SHAPE ABUTMENT ;
    PORT
      LAYER met3 ;
      RECT 468.300 289.530 469.200 289.830 ;
    END
  END rw0_wmask_in[212]
  PIN rw0_wmask_in[213]
    DIRECTION INPUT ;
    USE SIGNAL ;
    SHAPE ABUTMENT ;
    PORT
      LAYER met3 ;
      RECT 468.300 292.930 469.200 293.230 ;
    END
  END rw0_wmask_in[213]
  PIN rw0_wmask_in[214]
    DIRECTION INPUT ;
    USE SIGNAL ;
    SHAPE ABUTMENT ;
    PORT
      LAYER met3 ;
      RECT 468.300 296.330 469.200 296.630 ;
    END
  END rw0_wmask_in[214]
  PIN rw0_wmask_in[215]
    DIRECTION INPUT ;
    USE SIGNAL ;
    SHAPE ABUTMENT ;
    PORT
      LAYER met3 ;
      RECT 468.300 299.730 469.200 300.030 ;
    END
  END rw0_wmask_in[215]
  PIN rw0_wmask_in[216]
    DIRECTION INPUT ;
    USE SIGNAL ;
    SHAPE ABUTMENT ;
    PORT
      LAYER met3 ;
      RECT 468.300 303.130 469.200 303.430 ;
    END
  END rw0_wmask_in[216]
  PIN rw0_wmask_in[217]
    DIRECTION INPUT ;
    USE SIGNAL ;
    SHAPE ABUTMENT ;
    PORT
      LAYER met3 ;
      RECT 468.300 306.530 469.200 306.830 ;
    END
  END rw0_wmask_in[217]
  PIN rw0_wmask_in[218]
    DIRECTION INPUT ;
    USE SIGNAL ;
    SHAPE ABUTMENT ;
    PORT
      LAYER met3 ;
      RECT 468.300 309.930 469.200 310.230 ;
    END
  END rw0_wmask_in[218]
  PIN rw0_wmask_in[219]
    DIRECTION INPUT ;
    USE SIGNAL ;
    SHAPE ABUTMENT ;
    PORT
      LAYER met3 ;
      RECT 468.300 313.330 469.200 313.630 ;
    END
  END rw0_wmask_in[219]
  PIN rw0_wmask_in[220]
    DIRECTION INPUT ;
    USE SIGNAL ;
    SHAPE ABUTMENT ;
    PORT
      LAYER met3 ;
      RECT 468.300 316.730 469.200 317.030 ;
    END
  END rw0_wmask_in[220]
  PIN rw0_wmask_in[221]
    DIRECTION INPUT ;
    USE SIGNAL ;
    SHAPE ABUTMENT ;
    PORT
      LAYER met3 ;
      RECT 468.300 320.130 469.200 320.430 ;
    END
  END rw0_wmask_in[221]
  PIN rw0_wmask_in[222]
    DIRECTION INPUT ;
    USE SIGNAL ;
    SHAPE ABUTMENT ;
    PORT
      LAYER met3 ;
      RECT 468.300 323.530 469.200 323.830 ;
    END
  END rw0_wmask_in[222]
  PIN rw0_wmask_in[223]
    DIRECTION INPUT ;
    USE SIGNAL ;
    SHAPE ABUTMENT ;
    PORT
      LAYER met3 ;
      RECT 468.300 326.930 469.200 327.230 ;
    END
  END rw0_wmask_in[223]
  PIN rw0_wmask_in[224]
    DIRECTION INPUT ;
    USE SIGNAL ;
    SHAPE ABUTMENT ;
    PORT
      LAYER met3 ;
      RECT 468.300 330.330 469.200 330.630 ;
    END
  END rw0_wmask_in[224]
  PIN rw0_wmask_in[225]
    DIRECTION INPUT ;
    USE SIGNAL ;
    SHAPE ABUTMENT ;
    PORT
      LAYER met3 ;
      RECT 468.300 333.730 469.200 334.030 ;
    END
  END rw0_wmask_in[225]
  PIN rw0_wmask_in[226]
    DIRECTION INPUT ;
    USE SIGNAL ;
    SHAPE ABUTMENT ;
    PORT
      LAYER met3 ;
      RECT 468.300 337.130 469.200 337.430 ;
    END
  END rw0_wmask_in[226]
  PIN rw0_wmask_in[227]
    DIRECTION INPUT ;
    USE SIGNAL ;
    SHAPE ABUTMENT ;
    PORT
      LAYER met3 ;
      RECT 468.300 340.530 469.200 340.830 ;
    END
  END rw0_wmask_in[227]
  PIN rw0_wmask_in[228]
    DIRECTION INPUT ;
    USE SIGNAL ;
    SHAPE ABUTMENT ;
    PORT
      LAYER met3 ;
      RECT 468.300 343.930 469.200 344.230 ;
    END
  END rw0_wmask_in[228]
  PIN rw0_wmask_in[229]
    DIRECTION INPUT ;
    USE SIGNAL ;
    SHAPE ABUTMENT ;
    PORT
      LAYER met3 ;
      RECT 468.300 347.330 469.200 347.630 ;
    END
  END rw0_wmask_in[229]
  PIN rw0_wmask_in[230]
    DIRECTION INPUT ;
    USE SIGNAL ;
    SHAPE ABUTMENT ;
    PORT
      LAYER met3 ;
      RECT 468.300 350.730 469.200 351.030 ;
    END
  END rw0_wmask_in[230]
  PIN rw0_wmask_in[231]
    DIRECTION INPUT ;
    USE SIGNAL ;
    SHAPE ABUTMENT ;
    PORT
      LAYER met3 ;
      RECT 468.300 354.130 469.200 354.430 ;
    END
  END rw0_wmask_in[231]
  PIN rw0_wmask_in[232]
    DIRECTION INPUT ;
    USE SIGNAL ;
    SHAPE ABUTMENT ;
    PORT
      LAYER met3 ;
      RECT 468.300 357.530 469.200 357.830 ;
    END
  END rw0_wmask_in[232]
  PIN rw0_wmask_in[233]
    DIRECTION INPUT ;
    USE SIGNAL ;
    SHAPE ABUTMENT ;
    PORT
      LAYER met3 ;
      RECT 468.300 360.930 469.200 361.230 ;
    END
  END rw0_wmask_in[233]
  PIN rw0_wmask_in[234]
    DIRECTION INPUT ;
    USE SIGNAL ;
    SHAPE ABUTMENT ;
    PORT
      LAYER met3 ;
      RECT 468.300 364.330 469.200 364.630 ;
    END
  END rw0_wmask_in[234]
  PIN rw0_wmask_in[235]
    DIRECTION INPUT ;
    USE SIGNAL ;
    SHAPE ABUTMENT ;
    PORT
      LAYER met3 ;
      RECT 468.300 367.730 469.200 368.030 ;
    END
  END rw0_wmask_in[235]
  PIN rw0_wmask_in[236]
    DIRECTION INPUT ;
    USE SIGNAL ;
    SHAPE ABUTMENT ;
    PORT
      LAYER met3 ;
      RECT 468.300 371.130 469.200 371.430 ;
    END
  END rw0_wmask_in[236]
  PIN rw0_wmask_in[237]
    DIRECTION INPUT ;
    USE SIGNAL ;
    SHAPE ABUTMENT ;
    PORT
      LAYER met3 ;
      RECT 468.300 374.530 469.200 374.830 ;
    END
  END rw0_wmask_in[237]
  PIN rw0_wmask_in[238]
    DIRECTION INPUT ;
    USE SIGNAL ;
    SHAPE ABUTMENT ;
    PORT
      LAYER met3 ;
      RECT 468.300 377.930 469.200 378.230 ;
    END
  END rw0_wmask_in[238]
  PIN rw0_wmask_in[239]
    DIRECTION INPUT ;
    USE SIGNAL ;
    SHAPE ABUTMENT ;
    PORT
      LAYER met3 ;
      RECT 468.300 381.330 469.200 381.630 ;
    END
  END rw0_wmask_in[239]
  PIN rw0_wmask_in[240]
    DIRECTION INPUT ;
    USE SIGNAL ;
    SHAPE ABUTMENT ;
    PORT
      LAYER met3 ;
      RECT 468.300 384.730 469.200 385.030 ;
    END
  END rw0_wmask_in[240]
  PIN rw0_wmask_in[241]
    DIRECTION INPUT ;
    USE SIGNAL ;
    SHAPE ABUTMENT ;
    PORT
      LAYER met3 ;
      RECT 468.300 388.130 469.200 388.430 ;
    END
  END rw0_wmask_in[241]
  PIN rw0_wmask_in[242]
    DIRECTION INPUT ;
    USE SIGNAL ;
    SHAPE ABUTMENT ;
    PORT
      LAYER met3 ;
      RECT 468.300 391.530 469.200 391.830 ;
    END
  END rw0_wmask_in[242]
  PIN rw0_wmask_in[243]
    DIRECTION INPUT ;
    USE SIGNAL ;
    SHAPE ABUTMENT ;
    PORT
      LAYER met3 ;
      RECT 468.300 394.930 469.200 395.230 ;
    END
  END rw0_wmask_in[243]
  PIN rw0_wmask_in[244]
    DIRECTION INPUT ;
    USE SIGNAL ;
    SHAPE ABUTMENT ;
    PORT
      LAYER met3 ;
      RECT 468.300 398.330 469.200 398.630 ;
    END
  END rw0_wmask_in[244]
  PIN rw0_wmask_in[245]
    DIRECTION INPUT ;
    USE SIGNAL ;
    SHAPE ABUTMENT ;
    PORT
      LAYER met3 ;
      RECT 468.300 401.730 469.200 402.030 ;
    END
  END rw0_wmask_in[245]
  PIN rw0_wmask_in[246]
    DIRECTION INPUT ;
    USE SIGNAL ;
    SHAPE ABUTMENT ;
    PORT
      LAYER met3 ;
      RECT 468.300 405.130 469.200 405.430 ;
    END
  END rw0_wmask_in[246]
  PIN rw0_wmask_in[247]
    DIRECTION INPUT ;
    USE SIGNAL ;
    SHAPE ABUTMENT ;
    PORT
      LAYER met3 ;
      RECT 468.300 408.530 469.200 408.830 ;
    END
  END rw0_wmask_in[247]
  PIN rw0_wmask_in[248]
    DIRECTION INPUT ;
    USE SIGNAL ;
    SHAPE ABUTMENT ;
    PORT
      LAYER met3 ;
      RECT 468.300 411.930 469.200 412.230 ;
    END
  END rw0_wmask_in[248]
  PIN rw0_wmask_in[249]
    DIRECTION INPUT ;
    USE SIGNAL ;
    SHAPE ABUTMENT ;
    PORT
      LAYER met3 ;
      RECT 468.300 415.330 469.200 415.630 ;
    END
  END rw0_wmask_in[249]
  PIN rw0_wmask_in[250]
    DIRECTION INPUT ;
    USE SIGNAL ;
    SHAPE ABUTMENT ;
    PORT
      LAYER met3 ;
      RECT 468.300 418.730 469.200 419.030 ;
    END
  END rw0_wmask_in[250]
  PIN rw0_wmask_in[251]
    DIRECTION INPUT ;
    USE SIGNAL ;
    SHAPE ABUTMENT ;
    PORT
      LAYER met3 ;
      RECT 468.300 422.130 469.200 422.430 ;
    END
  END rw0_wmask_in[251]
  PIN rw0_wmask_in[252]
    DIRECTION INPUT ;
    USE SIGNAL ;
    SHAPE ABUTMENT ;
    PORT
      LAYER met3 ;
      RECT 468.300 425.530 469.200 425.830 ;
    END
  END rw0_wmask_in[252]
  PIN rw0_wmask_in[253]
    DIRECTION INPUT ;
    USE SIGNAL ;
    SHAPE ABUTMENT ;
    PORT
      LAYER met3 ;
      RECT 468.300 428.930 469.200 429.230 ;
    END
  END rw0_wmask_in[253]
  PIN rw0_wmask_in[254]
    DIRECTION INPUT ;
    USE SIGNAL ;
    SHAPE ABUTMENT ;
    PORT
      LAYER met3 ;
      RECT 468.300 432.330 469.200 432.630 ;
    END
  END rw0_wmask_in[254]
  PIN rw0_wmask_in[255]
    DIRECTION INPUT ;
    USE SIGNAL ;
    SHAPE ABUTMENT ;
    PORT
      LAYER met3 ;
      RECT 468.300 435.730 469.200 436.030 ;
    END
  END rw0_wmask_in[255]
  PIN rw0_wmask_in[256]
    DIRECTION INPUT ;
    USE SIGNAL ;
    SHAPE ABUTMENT ;
    PORT
      LAYER met2 ;
      RECT 2.690 954.300 2.830 954.720 ;
    END
  END rw0_wmask_in[256]
  PIN rw0_wmask_in[257]
    DIRECTION INPUT ;
    USE SIGNAL ;
    SHAPE ABUTMENT ;
    PORT
      LAYER met2 ;
      RECT 3.150 954.300 3.290 954.720 ;
    END
  END rw0_wmask_in[257]
  PIN rw0_wmask_in[258]
    DIRECTION INPUT ;
    USE SIGNAL ;
    SHAPE ABUTMENT ;
    PORT
      LAYER met2 ;
      RECT 3.610 954.300 3.750 954.720 ;
    END
  END rw0_wmask_in[258]
  PIN rw0_wmask_in[259]
    DIRECTION INPUT ;
    USE SIGNAL ;
    SHAPE ABUTMENT ;
    PORT
      LAYER met2 ;
      RECT 4.070 954.300 4.210 954.720 ;
    END
  END rw0_wmask_in[259]
  PIN rw0_wmask_in[260]
    DIRECTION INPUT ;
    USE SIGNAL ;
    SHAPE ABUTMENT ;
    PORT
      LAYER met2 ;
      RECT 4.530 954.300 4.670 954.720 ;
    END
  END rw0_wmask_in[260]
  PIN rw0_wmask_in[261]
    DIRECTION INPUT ;
    USE SIGNAL ;
    SHAPE ABUTMENT ;
    PORT
      LAYER met2 ;
      RECT 4.990 954.300 5.130 954.720 ;
    END
  END rw0_wmask_in[261]
  PIN rw0_wmask_in[262]
    DIRECTION INPUT ;
    USE SIGNAL ;
    SHAPE ABUTMENT ;
    PORT
      LAYER met2 ;
      RECT 5.450 954.300 5.590 954.720 ;
    END
  END rw0_wmask_in[262]
  PIN rw0_wmask_in[263]
    DIRECTION INPUT ;
    USE SIGNAL ;
    SHAPE ABUTMENT ;
    PORT
      LAYER met2 ;
      RECT 5.910 954.300 6.050 954.720 ;
    END
  END rw0_wmask_in[263]
  PIN rw0_wmask_in[264]
    DIRECTION INPUT ;
    USE SIGNAL ;
    SHAPE ABUTMENT ;
    PORT
      LAYER met2 ;
      RECT 6.370 954.300 6.510 954.720 ;
    END
  END rw0_wmask_in[264]
  PIN rw0_wmask_in[265]
    DIRECTION INPUT ;
    USE SIGNAL ;
    SHAPE ABUTMENT ;
    PORT
      LAYER met2 ;
      RECT 6.830 954.300 6.970 954.720 ;
    END
  END rw0_wmask_in[265]
  PIN rw0_wmask_in[266]
    DIRECTION INPUT ;
    USE SIGNAL ;
    SHAPE ABUTMENT ;
    PORT
      LAYER met2 ;
      RECT 7.290 954.300 7.430 954.720 ;
    END
  END rw0_wmask_in[266]
  PIN rw0_wmask_in[267]
    DIRECTION INPUT ;
    USE SIGNAL ;
    SHAPE ABUTMENT ;
    PORT
      LAYER met2 ;
      RECT 7.750 954.300 7.890 954.720 ;
    END
  END rw0_wmask_in[267]
  PIN rw0_wmask_in[268]
    DIRECTION INPUT ;
    USE SIGNAL ;
    SHAPE ABUTMENT ;
    PORT
      LAYER met2 ;
      RECT 8.210 954.300 8.350 954.720 ;
    END
  END rw0_wmask_in[268]
  PIN rw0_wmask_in[269]
    DIRECTION INPUT ;
    USE SIGNAL ;
    SHAPE ABUTMENT ;
    PORT
      LAYER met2 ;
      RECT 8.670 954.300 8.810 954.720 ;
    END
  END rw0_wmask_in[269]
  PIN rw0_wmask_in[270]
    DIRECTION INPUT ;
    USE SIGNAL ;
    SHAPE ABUTMENT ;
    PORT
      LAYER met2 ;
      RECT 9.130 954.300 9.270 954.720 ;
    END
  END rw0_wmask_in[270]
  PIN rw0_wmask_in[271]
    DIRECTION INPUT ;
    USE SIGNAL ;
    SHAPE ABUTMENT ;
    PORT
      LAYER met2 ;
      RECT 9.590 954.300 9.730 954.720 ;
    END
  END rw0_wmask_in[271]
  PIN rw0_wmask_in[272]
    DIRECTION INPUT ;
    USE SIGNAL ;
    SHAPE ABUTMENT ;
    PORT
      LAYER met2 ;
      RECT 10.050 954.300 10.190 954.720 ;
    END
  END rw0_wmask_in[272]
  PIN rw0_wmask_in[273]
    DIRECTION INPUT ;
    USE SIGNAL ;
    SHAPE ABUTMENT ;
    PORT
      LAYER met2 ;
      RECT 10.510 954.300 10.650 954.720 ;
    END
  END rw0_wmask_in[273]
  PIN rw0_wmask_in[274]
    DIRECTION INPUT ;
    USE SIGNAL ;
    SHAPE ABUTMENT ;
    PORT
      LAYER met2 ;
      RECT 10.970 954.300 11.110 954.720 ;
    END
  END rw0_wmask_in[274]
  PIN rw0_wmask_in[275]
    DIRECTION INPUT ;
    USE SIGNAL ;
    SHAPE ABUTMENT ;
    PORT
      LAYER met2 ;
      RECT 11.430 954.300 11.570 954.720 ;
    END
  END rw0_wmask_in[275]
  PIN rw0_wmask_in[276]
    DIRECTION INPUT ;
    USE SIGNAL ;
    SHAPE ABUTMENT ;
    PORT
      LAYER met2 ;
      RECT 11.890 954.300 12.030 954.720 ;
    END
  END rw0_wmask_in[276]
  PIN rw0_wmask_in[277]
    DIRECTION INPUT ;
    USE SIGNAL ;
    SHAPE ABUTMENT ;
    PORT
      LAYER met2 ;
      RECT 12.350 954.300 12.490 954.720 ;
    END
  END rw0_wmask_in[277]
  PIN rw0_wmask_in[278]
    DIRECTION INPUT ;
    USE SIGNAL ;
    SHAPE ABUTMENT ;
    PORT
      LAYER met2 ;
      RECT 12.810 954.300 12.950 954.720 ;
    END
  END rw0_wmask_in[278]
  PIN rw0_wmask_in[279]
    DIRECTION INPUT ;
    USE SIGNAL ;
    SHAPE ABUTMENT ;
    PORT
      LAYER met2 ;
      RECT 13.270 954.300 13.410 954.720 ;
    END
  END rw0_wmask_in[279]
  PIN rw0_wmask_in[280]
    DIRECTION INPUT ;
    USE SIGNAL ;
    SHAPE ABUTMENT ;
    PORT
      LAYER met2 ;
      RECT 13.730 954.300 13.870 954.720 ;
    END
  END rw0_wmask_in[280]
  PIN rw0_wmask_in[281]
    DIRECTION INPUT ;
    USE SIGNAL ;
    SHAPE ABUTMENT ;
    PORT
      LAYER met2 ;
      RECT 14.190 954.300 14.330 954.720 ;
    END
  END rw0_wmask_in[281]
  PIN rw0_wmask_in[282]
    DIRECTION INPUT ;
    USE SIGNAL ;
    SHAPE ABUTMENT ;
    PORT
      LAYER met2 ;
      RECT 14.650 954.300 14.790 954.720 ;
    END
  END rw0_wmask_in[282]
  PIN rw0_wmask_in[283]
    DIRECTION INPUT ;
    USE SIGNAL ;
    SHAPE ABUTMENT ;
    PORT
      LAYER met2 ;
      RECT 15.110 954.300 15.250 954.720 ;
    END
  END rw0_wmask_in[283]
  PIN rw0_wmask_in[284]
    DIRECTION INPUT ;
    USE SIGNAL ;
    SHAPE ABUTMENT ;
    PORT
      LAYER met2 ;
      RECT 15.570 954.300 15.710 954.720 ;
    END
  END rw0_wmask_in[284]
  PIN rw0_wmask_in[285]
    DIRECTION INPUT ;
    USE SIGNAL ;
    SHAPE ABUTMENT ;
    PORT
      LAYER met2 ;
      RECT 16.030 954.300 16.170 954.720 ;
    END
  END rw0_wmask_in[285]
  PIN rw0_wmask_in[286]
    DIRECTION INPUT ;
    USE SIGNAL ;
    SHAPE ABUTMENT ;
    PORT
      LAYER met2 ;
      RECT 16.490 954.300 16.630 954.720 ;
    END
  END rw0_wmask_in[286]
  PIN rw0_wmask_in[287]
    DIRECTION INPUT ;
    USE SIGNAL ;
    SHAPE ABUTMENT ;
    PORT
      LAYER met2 ;
      RECT 16.950 954.300 17.090 954.720 ;
    END
  END rw0_wmask_in[287]
  PIN rw0_wmask_in[288]
    DIRECTION INPUT ;
    USE SIGNAL ;
    SHAPE ABUTMENT ;
    PORT
      LAYER met2 ;
      RECT 17.410 954.300 17.550 954.720 ;
    END
  END rw0_wmask_in[288]
  PIN rw0_wmask_in[289]
    DIRECTION INPUT ;
    USE SIGNAL ;
    SHAPE ABUTMENT ;
    PORT
      LAYER met2 ;
      RECT 17.870 954.300 18.010 954.720 ;
    END
  END rw0_wmask_in[289]
  PIN rw0_wmask_in[290]
    DIRECTION INPUT ;
    USE SIGNAL ;
    SHAPE ABUTMENT ;
    PORT
      LAYER met2 ;
      RECT 18.330 954.300 18.470 954.720 ;
    END
  END rw0_wmask_in[290]
  PIN rw0_wmask_in[291]
    DIRECTION INPUT ;
    USE SIGNAL ;
    SHAPE ABUTMENT ;
    PORT
      LAYER met2 ;
      RECT 18.790 954.300 18.930 954.720 ;
    END
  END rw0_wmask_in[291]
  PIN rw0_wmask_in[292]
    DIRECTION INPUT ;
    USE SIGNAL ;
    SHAPE ABUTMENT ;
    PORT
      LAYER met2 ;
      RECT 19.250 954.300 19.390 954.720 ;
    END
  END rw0_wmask_in[292]
  PIN rw0_wmask_in[293]
    DIRECTION INPUT ;
    USE SIGNAL ;
    SHAPE ABUTMENT ;
    PORT
      LAYER met2 ;
      RECT 19.710 954.300 19.850 954.720 ;
    END
  END rw0_wmask_in[293]
  PIN rw0_wmask_in[294]
    DIRECTION INPUT ;
    USE SIGNAL ;
    SHAPE ABUTMENT ;
    PORT
      LAYER met2 ;
      RECT 20.170 954.300 20.310 954.720 ;
    END
  END rw0_wmask_in[294]
  PIN rw0_wmask_in[295]
    DIRECTION INPUT ;
    USE SIGNAL ;
    SHAPE ABUTMENT ;
    PORT
      LAYER met2 ;
      RECT 20.630 954.300 20.770 954.720 ;
    END
  END rw0_wmask_in[295]
  PIN rw0_wmask_in[296]
    DIRECTION INPUT ;
    USE SIGNAL ;
    SHAPE ABUTMENT ;
    PORT
      LAYER met2 ;
      RECT 21.090 954.300 21.230 954.720 ;
    END
  END rw0_wmask_in[296]
  PIN rw0_wmask_in[297]
    DIRECTION INPUT ;
    USE SIGNAL ;
    SHAPE ABUTMENT ;
    PORT
      LAYER met2 ;
      RECT 21.550 954.300 21.690 954.720 ;
    END
  END rw0_wmask_in[297]
  PIN rw0_wmask_in[298]
    DIRECTION INPUT ;
    USE SIGNAL ;
    SHAPE ABUTMENT ;
    PORT
      LAYER met2 ;
      RECT 22.010 954.300 22.150 954.720 ;
    END
  END rw0_wmask_in[298]
  PIN rw0_wmask_in[299]
    DIRECTION INPUT ;
    USE SIGNAL ;
    SHAPE ABUTMENT ;
    PORT
      LAYER met2 ;
      RECT 22.470 954.300 22.610 954.720 ;
    END
  END rw0_wmask_in[299]
  PIN rw0_wmask_in[300]
    DIRECTION INPUT ;
    USE SIGNAL ;
    SHAPE ABUTMENT ;
    PORT
      LAYER met2 ;
      RECT 22.930 954.300 23.070 954.720 ;
    END
  END rw0_wmask_in[300]
  PIN rw0_wmask_in[301]
    DIRECTION INPUT ;
    USE SIGNAL ;
    SHAPE ABUTMENT ;
    PORT
      LAYER met2 ;
      RECT 23.390 954.300 23.530 954.720 ;
    END
  END rw0_wmask_in[301]
  PIN rw0_wmask_in[302]
    DIRECTION INPUT ;
    USE SIGNAL ;
    SHAPE ABUTMENT ;
    PORT
      LAYER met2 ;
      RECT 23.850 954.300 23.990 954.720 ;
    END
  END rw0_wmask_in[302]
  PIN rw0_wmask_in[303]
    DIRECTION INPUT ;
    USE SIGNAL ;
    SHAPE ABUTMENT ;
    PORT
      LAYER met2 ;
      RECT 24.310 954.300 24.450 954.720 ;
    END
  END rw0_wmask_in[303]
  PIN rw0_wmask_in[304]
    DIRECTION INPUT ;
    USE SIGNAL ;
    SHAPE ABUTMENT ;
    PORT
      LAYER met2 ;
      RECT 24.770 954.300 24.910 954.720 ;
    END
  END rw0_wmask_in[304]
  PIN rw0_wmask_in[305]
    DIRECTION INPUT ;
    USE SIGNAL ;
    SHAPE ABUTMENT ;
    PORT
      LAYER met2 ;
      RECT 25.230 954.300 25.370 954.720 ;
    END
  END rw0_wmask_in[305]
  PIN rw0_wmask_in[306]
    DIRECTION INPUT ;
    USE SIGNAL ;
    SHAPE ABUTMENT ;
    PORT
      LAYER met2 ;
      RECT 25.690 954.300 25.830 954.720 ;
    END
  END rw0_wmask_in[306]
  PIN rw0_wmask_in[307]
    DIRECTION INPUT ;
    USE SIGNAL ;
    SHAPE ABUTMENT ;
    PORT
      LAYER met2 ;
      RECT 26.150 954.300 26.290 954.720 ;
    END
  END rw0_wmask_in[307]
  PIN rw0_wmask_in[308]
    DIRECTION INPUT ;
    USE SIGNAL ;
    SHAPE ABUTMENT ;
    PORT
      LAYER met2 ;
      RECT 26.610 954.300 26.750 954.720 ;
    END
  END rw0_wmask_in[308]
  PIN rw0_wmask_in[309]
    DIRECTION INPUT ;
    USE SIGNAL ;
    SHAPE ABUTMENT ;
    PORT
      LAYER met2 ;
      RECT 27.070 954.300 27.210 954.720 ;
    END
  END rw0_wmask_in[309]
  PIN rw0_wmask_in[310]
    DIRECTION INPUT ;
    USE SIGNAL ;
    SHAPE ABUTMENT ;
    PORT
      LAYER met2 ;
      RECT 27.530 954.300 27.670 954.720 ;
    END
  END rw0_wmask_in[310]
  PIN rw0_wmask_in[311]
    DIRECTION INPUT ;
    USE SIGNAL ;
    SHAPE ABUTMENT ;
    PORT
      LAYER met2 ;
      RECT 27.990 954.300 28.130 954.720 ;
    END
  END rw0_wmask_in[311]
  PIN rw0_wmask_in[312]
    DIRECTION INPUT ;
    USE SIGNAL ;
    SHAPE ABUTMENT ;
    PORT
      LAYER met2 ;
      RECT 28.450 954.300 28.590 954.720 ;
    END
  END rw0_wmask_in[312]
  PIN rw0_wmask_in[313]
    DIRECTION INPUT ;
    USE SIGNAL ;
    SHAPE ABUTMENT ;
    PORT
      LAYER met2 ;
      RECT 28.910 954.300 29.050 954.720 ;
    END
  END rw0_wmask_in[313]
  PIN rw0_wmask_in[314]
    DIRECTION INPUT ;
    USE SIGNAL ;
    SHAPE ABUTMENT ;
    PORT
      LAYER met2 ;
      RECT 29.370 954.300 29.510 954.720 ;
    END
  END rw0_wmask_in[314]
  PIN rw0_wmask_in[315]
    DIRECTION INPUT ;
    USE SIGNAL ;
    SHAPE ABUTMENT ;
    PORT
      LAYER met2 ;
      RECT 29.830 954.300 29.970 954.720 ;
    END
  END rw0_wmask_in[315]
  PIN rw0_wmask_in[316]
    DIRECTION INPUT ;
    USE SIGNAL ;
    SHAPE ABUTMENT ;
    PORT
      LAYER met2 ;
      RECT 30.290 954.300 30.430 954.720 ;
    END
  END rw0_wmask_in[316]
  PIN rw0_wmask_in[317]
    DIRECTION INPUT ;
    USE SIGNAL ;
    SHAPE ABUTMENT ;
    PORT
      LAYER met2 ;
      RECT 30.750 954.300 30.890 954.720 ;
    END
  END rw0_wmask_in[317]
  PIN rw0_wmask_in[318]
    DIRECTION INPUT ;
    USE SIGNAL ;
    SHAPE ABUTMENT ;
    PORT
      LAYER met2 ;
      RECT 31.210 954.300 31.350 954.720 ;
    END
  END rw0_wmask_in[318]
  PIN rw0_wmask_in[319]
    DIRECTION INPUT ;
    USE SIGNAL ;
    SHAPE ABUTMENT ;
    PORT
      LAYER met2 ;
      RECT 31.670 954.300 31.810 954.720 ;
    END
  END rw0_wmask_in[319]
  PIN rw0_wmask_in[320]
    DIRECTION INPUT ;
    USE SIGNAL ;
    SHAPE ABUTMENT ;
    PORT
      LAYER met2 ;
      RECT 32.130 954.300 32.270 954.720 ;
    END
  END rw0_wmask_in[320]
  PIN rw0_wmask_in[321]
    DIRECTION INPUT ;
    USE SIGNAL ;
    SHAPE ABUTMENT ;
    PORT
      LAYER met2 ;
      RECT 32.590 954.300 32.730 954.720 ;
    END
  END rw0_wmask_in[321]
  PIN rw0_wmask_in[322]
    DIRECTION INPUT ;
    USE SIGNAL ;
    SHAPE ABUTMENT ;
    PORT
      LAYER met2 ;
      RECT 33.050 954.300 33.190 954.720 ;
    END
  END rw0_wmask_in[322]
  PIN rw0_wmask_in[323]
    DIRECTION INPUT ;
    USE SIGNAL ;
    SHAPE ABUTMENT ;
    PORT
      LAYER met2 ;
      RECT 33.510 954.300 33.650 954.720 ;
    END
  END rw0_wmask_in[323]
  PIN rw0_wmask_in[324]
    DIRECTION INPUT ;
    USE SIGNAL ;
    SHAPE ABUTMENT ;
    PORT
      LAYER met2 ;
      RECT 33.970 954.300 34.110 954.720 ;
    END
  END rw0_wmask_in[324]
  PIN rw0_wmask_in[325]
    DIRECTION INPUT ;
    USE SIGNAL ;
    SHAPE ABUTMENT ;
    PORT
      LAYER met2 ;
      RECT 34.430 954.300 34.570 954.720 ;
    END
  END rw0_wmask_in[325]
  PIN rw0_wmask_in[326]
    DIRECTION INPUT ;
    USE SIGNAL ;
    SHAPE ABUTMENT ;
    PORT
      LAYER met2 ;
      RECT 34.890 954.300 35.030 954.720 ;
    END
  END rw0_wmask_in[326]
  PIN rw0_wmask_in[327]
    DIRECTION INPUT ;
    USE SIGNAL ;
    SHAPE ABUTMENT ;
    PORT
      LAYER met2 ;
      RECT 35.350 954.300 35.490 954.720 ;
    END
  END rw0_wmask_in[327]
  PIN rw0_wmask_in[328]
    DIRECTION INPUT ;
    USE SIGNAL ;
    SHAPE ABUTMENT ;
    PORT
      LAYER met2 ;
      RECT 35.810 954.300 35.950 954.720 ;
    END
  END rw0_wmask_in[328]
  PIN rw0_wmask_in[329]
    DIRECTION INPUT ;
    USE SIGNAL ;
    SHAPE ABUTMENT ;
    PORT
      LAYER met2 ;
      RECT 36.270 954.300 36.410 954.720 ;
    END
  END rw0_wmask_in[329]
  PIN rw0_wmask_in[330]
    DIRECTION INPUT ;
    USE SIGNAL ;
    SHAPE ABUTMENT ;
    PORT
      LAYER met2 ;
      RECT 36.730 954.300 36.870 954.720 ;
    END
  END rw0_wmask_in[330]
  PIN rw0_wmask_in[331]
    DIRECTION INPUT ;
    USE SIGNAL ;
    SHAPE ABUTMENT ;
    PORT
      LAYER met2 ;
      RECT 37.190 954.300 37.330 954.720 ;
    END
  END rw0_wmask_in[331]
  PIN rw0_wmask_in[332]
    DIRECTION INPUT ;
    USE SIGNAL ;
    SHAPE ABUTMENT ;
    PORT
      LAYER met2 ;
      RECT 37.650 954.300 37.790 954.720 ;
    END
  END rw0_wmask_in[332]
  PIN rw0_wmask_in[333]
    DIRECTION INPUT ;
    USE SIGNAL ;
    SHAPE ABUTMENT ;
    PORT
      LAYER met2 ;
      RECT 38.110 954.300 38.250 954.720 ;
    END
  END rw0_wmask_in[333]
  PIN rw0_wmask_in[334]
    DIRECTION INPUT ;
    USE SIGNAL ;
    SHAPE ABUTMENT ;
    PORT
      LAYER met2 ;
      RECT 38.570 954.300 38.710 954.720 ;
    END
  END rw0_wmask_in[334]
  PIN rw0_wmask_in[335]
    DIRECTION INPUT ;
    USE SIGNAL ;
    SHAPE ABUTMENT ;
    PORT
      LAYER met2 ;
      RECT 39.030 954.300 39.170 954.720 ;
    END
  END rw0_wmask_in[335]
  PIN rw0_wmask_in[336]
    DIRECTION INPUT ;
    USE SIGNAL ;
    SHAPE ABUTMENT ;
    PORT
      LAYER met2 ;
      RECT 39.490 954.300 39.630 954.720 ;
    END
  END rw0_wmask_in[336]
  PIN rw0_wmask_in[337]
    DIRECTION INPUT ;
    USE SIGNAL ;
    SHAPE ABUTMENT ;
    PORT
      LAYER met2 ;
      RECT 39.950 954.300 40.090 954.720 ;
    END
  END rw0_wmask_in[337]
  PIN rw0_wmask_in[338]
    DIRECTION INPUT ;
    USE SIGNAL ;
    SHAPE ABUTMENT ;
    PORT
      LAYER met2 ;
      RECT 40.410 954.300 40.550 954.720 ;
    END
  END rw0_wmask_in[338]
  PIN rw0_wmask_in[339]
    DIRECTION INPUT ;
    USE SIGNAL ;
    SHAPE ABUTMENT ;
    PORT
      LAYER met2 ;
      RECT 40.870 954.300 41.010 954.720 ;
    END
  END rw0_wmask_in[339]
  PIN rw0_wmask_in[340]
    DIRECTION INPUT ;
    USE SIGNAL ;
    SHAPE ABUTMENT ;
    PORT
      LAYER met2 ;
      RECT 41.330 954.300 41.470 954.720 ;
    END
  END rw0_wmask_in[340]
  PIN rw0_wmask_in[341]
    DIRECTION INPUT ;
    USE SIGNAL ;
    SHAPE ABUTMENT ;
    PORT
      LAYER met2 ;
      RECT 41.790 954.300 41.930 954.720 ;
    END
  END rw0_wmask_in[341]
  PIN rw0_wmask_in[342]
    DIRECTION INPUT ;
    USE SIGNAL ;
    SHAPE ABUTMENT ;
    PORT
      LAYER met2 ;
      RECT 42.250 954.300 42.390 954.720 ;
    END
  END rw0_wmask_in[342]
  PIN rw0_wmask_in[343]
    DIRECTION INPUT ;
    USE SIGNAL ;
    SHAPE ABUTMENT ;
    PORT
      LAYER met2 ;
      RECT 42.710 954.300 42.850 954.720 ;
    END
  END rw0_wmask_in[343]
  PIN rw0_wmask_in[344]
    DIRECTION INPUT ;
    USE SIGNAL ;
    SHAPE ABUTMENT ;
    PORT
      LAYER met2 ;
      RECT 43.170 954.300 43.310 954.720 ;
    END
  END rw0_wmask_in[344]
  PIN rw0_wmask_in[345]
    DIRECTION INPUT ;
    USE SIGNAL ;
    SHAPE ABUTMENT ;
    PORT
      LAYER met2 ;
      RECT 43.630 954.300 43.770 954.720 ;
    END
  END rw0_wmask_in[345]
  PIN rw0_wmask_in[346]
    DIRECTION INPUT ;
    USE SIGNAL ;
    SHAPE ABUTMENT ;
    PORT
      LAYER met2 ;
      RECT 44.090 954.300 44.230 954.720 ;
    END
  END rw0_wmask_in[346]
  PIN rw0_wmask_in[347]
    DIRECTION INPUT ;
    USE SIGNAL ;
    SHAPE ABUTMENT ;
    PORT
      LAYER met2 ;
      RECT 44.550 954.300 44.690 954.720 ;
    END
  END rw0_wmask_in[347]
  PIN rw0_wmask_in[348]
    DIRECTION INPUT ;
    USE SIGNAL ;
    SHAPE ABUTMENT ;
    PORT
      LAYER met2 ;
      RECT 45.010 954.300 45.150 954.720 ;
    END
  END rw0_wmask_in[348]
  PIN rw0_wmask_in[349]
    DIRECTION INPUT ;
    USE SIGNAL ;
    SHAPE ABUTMENT ;
    PORT
      LAYER met2 ;
      RECT 45.470 954.300 45.610 954.720 ;
    END
  END rw0_wmask_in[349]
  PIN rw0_wmask_in[350]
    DIRECTION INPUT ;
    USE SIGNAL ;
    SHAPE ABUTMENT ;
    PORT
      LAYER met2 ;
      RECT 45.930 954.300 46.070 954.720 ;
    END
  END rw0_wmask_in[350]
  PIN rw0_wmask_in[351]
    DIRECTION INPUT ;
    USE SIGNAL ;
    SHAPE ABUTMENT ;
    PORT
      LAYER met2 ;
      RECT 46.390 954.300 46.530 954.720 ;
    END
  END rw0_wmask_in[351]
  PIN rw0_wmask_in[352]
    DIRECTION INPUT ;
    USE SIGNAL ;
    SHAPE ABUTMENT ;
    PORT
      LAYER met2 ;
      RECT 46.850 954.300 46.990 954.720 ;
    END
  END rw0_wmask_in[352]
  PIN rw0_wmask_in[353]
    DIRECTION INPUT ;
    USE SIGNAL ;
    SHAPE ABUTMENT ;
    PORT
      LAYER met2 ;
      RECT 47.310 954.300 47.450 954.720 ;
    END
  END rw0_wmask_in[353]
  PIN rw0_wmask_in[354]
    DIRECTION INPUT ;
    USE SIGNAL ;
    SHAPE ABUTMENT ;
    PORT
      LAYER met2 ;
      RECT 47.770 954.300 47.910 954.720 ;
    END
  END rw0_wmask_in[354]
  PIN rw0_wmask_in[355]
    DIRECTION INPUT ;
    USE SIGNAL ;
    SHAPE ABUTMENT ;
    PORT
      LAYER met2 ;
      RECT 48.230 954.300 48.370 954.720 ;
    END
  END rw0_wmask_in[355]
  PIN rw0_wmask_in[356]
    DIRECTION INPUT ;
    USE SIGNAL ;
    SHAPE ABUTMENT ;
    PORT
      LAYER met2 ;
      RECT 48.690 954.300 48.830 954.720 ;
    END
  END rw0_wmask_in[356]
  PIN rw0_wmask_in[357]
    DIRECTION INPUT ;
    USE SIGNAL ;
    SHAPE ABUTMENT ;
    PORT
      LAYER met2 ;
      RECT 49.150 954.300 49.290 954.720 ;
    END
  END rw0_wmask_in[357]
  PIN rw0_wmask_in[358]
    DIRECTION INPUT ;
    USE SIGNAL ;
    SHAPE ABUTMENT ;
    PORT
      LAYER met2 ;
      RECT 49.610 954.300 49.750 954.720 ;
    END
  END rw0_wmask_in[358]
  PIN rw0_wmask_in[359]
    DIRECTION INPUT ;
    USE SIGNAL ;
    SHAPE ABUTMENT ;
    PORT
      LAYER met2 ;
      RECT 50.070 954.300 50.210 954.720 ;
    END
  END rw0_wmask_in[359]
  PIN rw0_wmask_in[360]
    DIRECTION INPUT ;
    USE SIGNAL ;
    SHAPE ABUTMENT ;
    PORT
      LAYER met2 ;
      RECT 50.530 954.300 50.670 954.720 ;
    END
  END rw0_wmask_in[360]
  PIN rw0_wmask_in[361]
    DIRECTION INPUT ;
    USE SIGNAL ;
    SHAPE ABUTMENT ;
    PORT
      LAYER met2 ;
      RECT 50.990 954.300 51.130 954.720 ;
    END
  END rw0_wmask_in[361]
  PIN rw0_wmask_in[362]
    DIRECTION INPUT ;
    USE SIGNAL ;
    SHAPE ABUTMENT ;
    PORT
      LAYER met2 ;
      RECT 51.450 954.300 51.590 954.720 ;
    END
  END rw0_wmask_in[362]
  PIN rw0_wmask_in[363]
    DIRECTION INPUT ;
    USE SIGNAL ;
    SHAPE ABUTMENT ;
    PORT
      LAYER met2 ;
      RECT 51.910 954.300 52.050 954.720 ;
    END
  END rw0_wmask_in[363]
  PIN rw0_wmask_in[364]
    DIRECTION INPUT ;
    USE SIGNAL ;
    SHAPE ABUTMENT ;
    PORT
      LAYER met2 ;
      RECT 52.370 954.300 52.510 954.720 ;
    END
  END rw0_wmask_in[364]
  PIN rw0_wmask_in[365]
    DIRECTION INPUT ;
    USE SIGNAL ;
    SHAPE ABUTMENT ;
    PORT
      LAYER met2 ;
      RECT 52.830 954.300 52.970 954.720 ;
    END
  END rw0_wmask_in[365]
  PIN rw0_wmask_in[366]
    DIRECTION INPUT ;
    USE SIGNAL ;
    SHAPE ABUTMENT ;
    PORT
      LAYER met2 ;
      RECT 53.290 954.300 53.430 954.720 ;
    END
  END rw0_wmask_in[366]
  PIN rw0_wmask_in[367]
    DIRECTION INPUT ;
    USE SIGNAL ;
    SHAPE ABUTMENT ;
    PORT
      LAYER met2 ;
      RECT 53.750 954.300 53.890 954.720 ;
    END
  END rw0_wmask_in[367]
  PIN rw0_wmask_in[368]
    DIRECTION INPUT ;
    USE SIGNAL ;
    SHAPE ABUTMENT ;
    PORT
      LAYER met2 ;
      RECT 54.210 954.300 54.350 954.720 ;
    END
  END rw0_wmask_in[368]
  PIN rw0_wmask_in[369]
    DIRECTION INPUT ;
    USE SIGNAL ;
    SHAPE ABUTMENT ;
    PORT
      LAYER met2 ;
      RECT 54.670 954.300 54.810 954.720 ;
    END
  END rw0_wmask_in[369]
  PIN rw0_wmask_in[370]
    DIRECTION INPUT ;
    USE SIGNAL ;
    SHAPE ABUTMENT ;
    PORT
      LAYER met2 ;
      RECT 55.130 954.300 55.270 954.720 ;
    END
  END rw0_wmask_in[370]
  PIN rw0_wmask_in[371]
    DIRECTION INPUT ;
    USE SIGNAL ;
    SHAPE ABUTMENT ;
    PORT
      LAYER met2 ;
      RECT 55.590 954.300 55.730 954.720 ;
    END
  END rw0_wmask_in[371]
  PIN rw0_wmask_in[372]
    DIRECTION INPUT ;
    USE SIGNAL ;
    SHAPE ABUTMENT ;
    PORT
      LAYER met2 ;
      RECT 56.050 954.300 56.190 954.720 ;
    END
  END rw0_wmask_in[372]
  PIN rw0_wmask_in[373]
    DIRECTION INPUT ;
    USE SIGNAL ;
    SHAPE ABUTMENT ;
    PORT
      LAYER met2 ;
      RECT 56.510 954.300 56.650 954.720 ;
    END
  END rw0_wmask_in[373]
  PIN rw0_wmask_in[374]
    DIRECTION INPUT ;
    USE SIGNAL ;
    SHAPE ABUTMENT ;
    PORT
      LAYER met2 ;
      RECT 56.970 954.300 57.110 954.720 ;
    END
  END rw0_wmask_in[374]
  PIN rw0_wmask_in[375]
    DIRECTION INPUT ;
    USE SIGNAL ;
    SHAPE ABUTMENT ;
    PORT
      LAYER met2 ;
      RECT 57.430 954.300 57.570 954.720 ;
    END
  END rw0_wmask_in[375]
  PIN rw0_wmask_in[376]
    DIRECTION INPUT ;
    USE SIGNAL ;
    SHAPE ABUTMENT ;
    PORT
      LAYER met2 ;
      RECT 57.890 954.300 58.030 954.720 ;
    END
  END rw0_wmask_in[376]
  PIN rw0_wmask_in[377]
    DIRECTION INPUT ;
    USE SIGNAL ;
    SHAPE ABUTMENT ;
    PORT
      LAYER met2 ;
      RECT 58.350 954.300 58.490 954.720 ;
    END
  END rw0_wmask_in[377]
  PIN rw0_wmask_in[378]
    DIRECTION INPUT ;
    USE SIGNAL ;
    SHAPE ABUTMENT ;
    PORT
      LAYER met2 ;
      RECT 58.810 954.300 58.950 954.720 ;
    END
  END rw0_wmask_in[378]
  PIN rw0_wmask_in[379]
    DIRECTION INPUT ;
    USE SIGNAL ;
    SHAPE ABUTMENT ;
    PORT
      LAYER met2 ;
      RECT 59.270 954.300 59.410 954.720 ;
    END
  END rw0_wmask_in[379]
  PIN rw0_wmask_in[380]
    DIRECTION INPUT ;
    USE SIGNAL ;
    SHAPE ABUTMENT ;
    PORT
      LAYER met2 ;
      RECT 59.730 954.300 59.870 954.720 ;
    END
  END rw0_wmask_in[380]
  PIN rw0_wmask_in[381]
    DIRECTION INPUT ;
    USE SIGNAL ;
    SHAPE ABUTMENT ;
    PORT
      LAYER met2 ;
      RECT 60.190 954.300 60.330 954.720 ;
    END
  END rw0_wmask_in[381]
  PIN rw0_wmask_in[382]
    DIRECTION INPUT ;
    USE SIGNAL ;
    SHAPE ABUTMENT ;
    PORT
      LAYER met2 ;
      RECT 60.650 954.300 60.790 954.720 ;
    END
  END rw0_wmask_in[382]
  PIN rw0_wmask_in[383]
    DIRECTION INPUT ;
    USE SIGNAL ;
    SHAPE ABUTMENT ;
    PORT
      LAYER met2 ;
      RECT 61.110 954.300 61.250 954.720 ;
    END
  END rw0_wmask_in[383]
  PIN rw0_wmask_in[384]
    DIRECTION INPUT ;
    USE SIGNAL ;
    SHAPE ABUTMENT ;
    PORT
      LAYER met2 ;
      RECT 61.570 954.300 61.710 954.720 ;
    END
  END rw0_wmask_in[384]
  PIN rw0_wmask_in[385]
    DIRECTION INPUT ;
    USE SIGNAL ;
    SHAPE ABUTMENT ;
    PORT
      LAYER met2 ;
      RECT 62.030 954.300 62.170 954.720 ;
    END
  END rw0_wmask_in[385]
  PIN rw0_wmask_in[386]
    DIRECTION INPUT ;
    USE SIGNAL ;
    SHAPE ABUTMENT ;
    PORT
      LAYER met2 ;
      RECT 62.490 954.300 62.630 954.720 ;
    END
  END rw0_wmask_in[386]
  PIN rw0_wmask_in[387]
    DIRECTION INPUT ;
    USE SIGNAL ;
    SHAPE ABUTMENT ;
    PORT
      LAYER met2 ;
      RECT 62.950 954.300 63.090 954.720 ;
    END
  END rw0_wmask_in[387]
  PIN rw0_wmask_in[388]
    DIRECTION INPUT ;
    USE SIGNAL ;
    SHAPE ABUTMENT ;
    PORT
      LAYER met2 ;
      RECT 63.410 954.300 63.550 954.720 ;
    END
  END rw0_wmask_in[388]
  PIN rw0_wmask_in[389]
    DIRECTION INPUT ;
    USE SIGNAL ;
    SHAPE ABUTMENT ;
    PORT
      LAYER met2 ;
      RECT 63.870 954.300 64.010 954.720 ;
    END
  END rw0_wmask_in[389]
  PIN rw0_wmask_in[390]
    DIRECTION INPUT ;
    USE SIGNAL ;
    SHAPE ABUTMENT ;
    PORT
      LAYER met2 ;
      RECT 64.330 954.300 64.470 954.720 ;
    END
  END rw0_wmask_in[390]
  PIN rw0_wmask_in[391]
    DIRECTION INPUT ;
    USE SIGNAL ;
    SHAPE ABUTMENT ;
    PORT
      LAYER met2 ;
      RECT 64.790 954.300 64.930 954.720 ;
    END
  END rw0_wmask_in[391]
  PIN rw0_wmask_in[392]
    DIRECTION INPUT ;
    USE SIGNAL ;
    SHAPE ABUTMENT ;
    PORT
      LAYER met2 ;
      RECT 65.250 954.300 65.390 954.720 ;
    END
  END rw0_wmask_in[392]
  PIN rw0_wmask_in[393]
    DIRECTION INPUT ;
    USE SIGNAL ;
    SHAPE ABUTMENT ;
    PORT
      LAYER met2 ;
      RECT 65.710 954.300 65.850 954.720 ;
    END
  END rw0_wmask_in[393]
  PIN rw0_wmask_in[394]
    DIRECTION INPUT ;
    USE SIGNAL ;
    SHAPE ABUTMENT ;
    PORT
      LAYER met2 ;
      RECT 66.170 954.300 66.310 954.720 ;
    END
  END rw0_wmask_in[394]
  PIN rw0_wmask_in[395]
    DIRECTION INPUT ;
    USE SIGNAL ;
    SHAPE ABUTMENT ;
    PORT
      LAYER met2 ;
      RECT 66.630 954.300 66.770 954.720 ;
    END
  END rw0_wmask_in[395]
  PIN rw0_wmask_in[396]
    DIRECTION INPUT ;
    USE SIGNAL ;
    SHAPE ABUTMENT ;
    PORT
      LAYER met2 ;
      RECT 67.090 954.300 67.230 954.720 ;
    END
  END rw0_wmask_in[396]
  PIN rw0_wmask_in[397]
    DIRECTION INPUT ;
    USE SIGNAL ;
    SHAPE ABUTMENT ;
    PORT
      LAYER met2 ;
      RECT 67.550 954.300 67.690 954.720 ;
    END
  END rw0_wmask_in[397]
  PIN rw0_wmask_in[398]
    DIRECTION INPUT ;
    USE SIGNAL ;
    SHAPE ABUTMENT ;
    PORT
      LAYER met2 ;
      RECT 68.010 954.300 68.150 954.720 ;
    END
  END rw0_wmask_in[398]
  PIN rw0_wmask_in[399]
    DIRECTION INPUT ;
    USE SIGNAL ;
    SHAPE ABUTMENT ;
    PORT
      LAYER met2 ;
      RECT 68.470 954.300 68.610 954.720 ;
    END
  END rw0_wmask_in[399]
  PIN rw0_wmask_in[400]
    DIRECTION INPUT ;
    USE SIGNAL ;
    SHAPE ABUTMENT ;
    PORT
      LAYER met2 ;
      RECT 68.930 954.300 69.070 954.720 ;
    END
  END rw0_wmask_in[400]
  PIN rw0_wmask_in[401]
    DIRECTION INPUT ;
    USE SIGNAL ;
    SHAPE ABUTMENT ;
    PORT
      LAYER met2 ;
      RECT 69.390 954.300 69.530 954.720 ;
    END
  END rw0_wmask_in[401]
  PIN rw0_wmask_in[402]
    DIRECTION INPUT ;
    USE SIGNAL ;
    SHAPE ABUTMENT ;
    PORT
      LAYER met2 ;
      RECT 69.850 954.300 69.990 954.720 ;
    END
  END rw0_wmask_in[402]
  PIN rw0_wmask_in[403]
    DIRECTION INPUT ;
    USE SIGNAL ;
    SHAPE ABUTMENT ;
    PORT
      LAYER met2 ;
      RECT 70.310 954.300 70.450 954.720 ;
    END
  END rw0_wmask_in[403]
  PIN rw0_wmask_in[404]
    DIRECTION INPUT ;
    USE SIGNAL ;
    SHAPE ABUTMENT ;
    PORT
      LAYER met2 ;
      RECT 70.770 954.300 70.910 954.720 ;
    END
  END rw0_wmask_in[404]
  PIN rw0_wmask_in[405]
    DIRECTION INPUT ;
    USE SIGNAL ;
    SHAPE ABUTMENT ;
    PORT
      LAYER met2 ;
      RECT 71.230 954.300 71.370 954.720 ;
    END
  END rw0_wmask_in[405]
  PIN rw0_wmask_in[406]
    DIRECTION INPUT ;
    USE SIGNAL ;
    SHAPE ABUTMENT ;
    PORT
      LAYER met2 ;
      RECT 71.690 954.300 71.830 954.720 ;
    END
  END rw0_wmask_in[406]
  PIN rw0_wmask_in[407]
    DIRECTION INPUT ;
    USE SIGNAL ;
    SHAPE ABUTMENT ;
    PORT
      LAYER met2 ;
      RECT 72.150 954.300 72.290 954.720 ;
    END
  END rw0_wmask_in[407]
  PIN rw0_wmask_in[408]
    DIRECTION INPUT ;
    USE SIGNAL ;
    SHAPE ABUTMENT ;
    PORT
      LAYER met2 ;
      RECT 72.610 954.300 72.750 954.720 ;
    END
  END rw0_wmask_in[408]
  PIN rw0_wmask_in[409]
    DIRECTION INPUT ;
    USE SIGNAL ;
    SHAPE ABUTMENT ;
    PORT
      LAYER met2 ;
      RECT 73.070 954.300 73.210 954.720 ;
    END
  END rw0_wmask_in[409]
  PIN rw0_wmask_in[410]
    DIRECTION INPUT ;
    USE SIGNAL ;
    SHAPE ABUTMENT ;
    PORT
      LAYER met2 ;
      RECT 73.530 954.300 73.670 954.720 ;
    END
  END rw0_wmask_in[410]
  PIN rw0_wmask_in[411]
    DIRECTION INPUT ;
    USE SIGNAL ;
    SHAPE ABUTMENT ;
    PORT
      LAYER met2 ;
      RECT 73.990 954.300 74.130 954.720 ;
    END
  END rw0_wmask_in[411]
  PIN rw0_wmask_in[412]
    DIRECTION INPUT ;
    USE SIGNAL ;
    SHAPE ABUTMENT ;
    PORT
      LAYER met2 ;
      RECT 74.450 954.300 74.590 954.720 ;
    END
  END rw0_wmask_in[412]
  PIN rw0_wmask_in[413]
    DIRECTION INPUT ;
    USE SIGNAL ;
    SHAPE ABUTMENT ;
    PORT
      LAYER met2 ;
      RECT 74.910 954.300 75.050 954.720 ;
    END
  END rw0_wmask_in[413]
  PIN rw0_wmask_in[414]
    DIRECTION INPUT ;
    USE SIGNAL ;
    SHAPE ABUTMENT ;
    PORT
      LAYER met2 ;
      RECT 75.370 954.300 75.510 954.720 ;
    END
  END rw0_wmask_in[414]
  PIN rw0_wmask_in[415]
    DIRECTION INPUT ;
    USE SIGNAL ;
    SHAPE ABUTMENT ;
    PORT
      LAYER met2 ;
      RECT 75.830 954.300 75.970 954.720 ;
    END
  END rw0_wmask_in[415]
  PIN rw0_wmask_in[416]
    DIRECTION INPUT ;
    USE SIGNAL ;
    SHAPE ABUTMENT ;
    PORT
      LAYER met2 ;
      RECT 76.290 954.300 76.430 954.720 ;
    END
  END rw0_wmask_in[416]
  PIN rw0_wmask_in[417]
    DIRECTION INPUT ;
    USE SIGNAL ;
    SHAPE ABUTMENT ;
    PORT
      LAYER met2 ;
      RECT 76.750 954.300 76.890 954.720 ;
    END
  END rw0_wmask_in[417]
  PIN rw0_wmask_in[418]
    DIRECTION INPUT ;
    USE SIGNAL ;
    SHAPE ABUTMENT ;
    PORT
      LAYER met2 ;
      RECT 77.210 954.300 77.350 954.720 ;
    END
  END rw0_wmask_in[418]
  PIN rw0_wmask_in[419]
    DIRECTION INPUT ;
    USE SIGNAL ;
    SHAPE ABUTMENT ;
    PORT
      LAYER met2 ;
      RECT 77.670 954.300 77.810 954.720 ;
    END
  END rw0_wmask_in[419]
  PIN rw0_wmask_in[420]
    DIRECTION INPUT ;
    USE SIGNAL ;
    SHAPE ABUTMENT ;
    PORT
      LAYER met2 ;
      RECT 78.130 954.300 78.270 954.720 ;
    END
  END rw0_wmask_in[420]
  PIN rw0_wmask_in[421]
    DIRECTION INPUT ;
    USE SIGNAL ;
    SHAPE ABUTMENT ;
    PORT
      LAYER met2 ;
      RECT 78.590 954.300 78.730 954.720 ;
    END
  END rw0_wmask_in[421]
  PIN rw0_wmask_in[422]
    DIRECTION INPUT ;
    USE SIGNAL ;
    SHAPE ABUTMENT ;
    PORT
      LAYER met2 ;
      RECT 79.050 954.300 79.190 954.720 ;
    END
  END rw0_wmask_in[422]
  PIN rw0_wmask_in[423]
    DIRECTION INPUT ;
    USE SIGNAL ;
    SHAPE ABUTMENT ;
    PORT
      LAYER met2 ;
      RECT 79.510 954.300 79.650 954.720 ;
    END
  END rw0_wmask_in[423]
  PIN rw0_wmask_in[424]
    DIRECTION INPUT ;
    USE SIGNAL ;
    SHAPE ABUTMENT ;
    PORT
      LAYER met2 ;
      RECT 79.970 954.300 80.110 954.720 ;
    END
  END rw0_wmask_in[424]
  PIN rw0_wmask_in[425]
    DIRECTION INPUT ;
    USE SIGNAL ;
    SHAPE ABUTMENT ;
    PORT
      LAYER met2 ;
      RECT 80.430 954.300 80.570 954.720 ;
    END
  END rw0_wmask_in[425]
  PIN rw0_wmask_in[426]
    DIRECTION INPUT ;
    USE SIGNAL ;
    SHAPE ABUTMENT ;
    PORT
      LAYER met2 ;
      RECT 80.890 954.300 81.030 954.720 ;
    END
  END rw0_wmask_in[426]
  PIN rw0_wmask_in[427]
    DIRECTION INPUT ;
    USE SIGNAL ;
    SHAPE ABUTMENT ;
    PORT
      LAYER met2 ;
      RECT 81.350 954.300 81.490 954.720 ;
    END
  END rw0_wmask_in[427]
  PIN rw0_wmask_in[428]
    DIRECTION INPUT ;
    USE SIGNAL ;
    SHAPE ABUTMENT ;
    PORT
      LAYER met2 ;
      RECT 81.810 954.300 81.950 954.720 ;
    END
  END rw0_wmask_in[428]
  PIN rw0_wmask_in[429]
    DIRECTION INPUT ;
    USE SIGNAL ;
    SHAPE ABUTMENT ;
    PORT
      LAYER met2 ;
      RECT 82.270 954.300 82.410 954.720 ;
    END
  END rw0_wmask_in[429]
  PIN rw0_wmask_in[430]
    DIRECTION INPUT ;
    USE SIGNAL ;
    SHAPE ABUTMENT ;
    PORT
      LAYER met2 ;
      RECT 82.730 954.300 82.870 954.720 ;
    END
  END rw0_wmask_in[430]
  PIN rw0_wmask_in[431]
    DIRECTION INPUT ;
    USE SIGNAL ;
    SHAPE ABUTMENT ;
    PORT
      LAYER met2 ;
      RECT 83.190 954.300 83.330 954.720 ;
    END
  END rw0_wmask_in[431]
  PIN rw0_wmask_in[432]
    DIRECTION INPUT ;
    USE SIGNAL ;
    SHAPE ABUTMENT ;
    PORT
      LAYER met2 ;
      RECT 83.650 954.300 83.790 954.720 ;
    END
  END rw0_wmask_in[432]
  PIN rw0_wmask_in[433]
    DIRECTION INPUT ;
    USE SIGNAL ;
    SHAPE ABUTMENT ;
    PORT
      LAYER met2 ;
      RECT 84.110 954.300 84.250 954.720 ;
    END
  END rw0_wmask_in[433]
  PIN rw0_wmask_in[434]
    DIRECTION INPUT ;
    USE SIGNAL ;
    SHAPE ABUTMENT ;
    PORT
      LAYER met2 ;
      RECT 84.570 954.300 84.710 954.720 ;
    END
  END rw0_wmask_in[434]
  PIN rw0_wmask_in[435]
    DIRECTION INPUT ;
    USE SIGNAL ;
    SHAPE ABUTMENT ;
    PORT
      LAYER met2 ;
      RECT 85.030 954.300 85.170 954.720 ;
    END
  END rw0_wmask_in[435]
  PIN rw0_wmask_in[436]
    DIRECTION INPUT ;
    USE SIGNAL ;
    SHAPE ABUTMENT ;
    PORT
      LAYER met2 ;
      RECT 85.490 954.300 85.630 954.720 ;
    END
  END rw0_wmask_in[436]
  PIN rw0_wmask_in[437]
    DIRECTION INPUT ;
    USE SIGNAL ;
    SHAPE ABUTMENT ;
    PORT
      LAYER met2 ;
      RECT 85.950 954.300 86.090 954.720 ;
    END
  END rw0_wmask_in[437]
  PIN rw0_wmask_in[438]
    DIRECTION INPUT ;
    USE SIGNAL ;
    SHAPE ABUTMENT ;
    PORT
      LAYER met2 ;
      RECT 86.410 954.300 86.550 954.720 ;
    END
  END rw0_wmask_in[438]
  PIN rw0_wmask_in[439]
    DIRECTION INPUT ;
    USE SIGNAL ;
    SHAPE ABUTMENT ;
    PORT
      LAYER met2 ;
      RECT 86.870 954.300 87.010 954.720 ;
    END
  END rw0_wmask_in[439]
  PIN rw0_wmask_in[440]
    DIRECTION INPUT ;
    USE SIGNAL ;
    SHAPE ABUTMENT ;
    PORT
      LAYER met2 ;
      RECT 87.330 954.300 87.470 954.720 ;
    END
  END rw0_wmask_in[440]
  PIN rw0_wmask_in[441]
    DIRECTION INPUT ;
    USE SIGNAL ;
    SHAPE ABUTMENT ;
    PORT
      LAYER met2 ;
      RECT 87.790 954.300 87.930 954.720 ;
    END
  END rw0_wmask_in[441]
  PIN rw0_wmask_in[442]
    DIRECTION INPUT ;
    USE SIGNAL ;
    SHAPE ABUTMENT ;
    PORT
      LAYER met2 ;
      RECT 88.250 954.300 88.390 954.720 ;
    END
  END rw0_wmask_in[442]
  PIN rw0_wmask_in[443]
    DIRECTION INPUT ;
    USE SIGNAL ;
    SHAPE ABUTMENT ;
    PORT
      LAYER met2 ;
      RECT 88.710 954.300 88.850 954.720 ;
    END
  END rw0_wmask_in[443]
  PIN rw0_wmask_in[444]
    DIRECTION INPUT ;
    USE SIGNAL ;
    SHAPE ABUTMENT ;
    PORT
      LAYER met2 ;
      RECT 89.170 954.300 89.310 954.720 ;
    END
  END rw0_wmask_in[444]
  PIN rw0_wmask_in[445]
    DIRECTION INPUT ;
    USE SIGNAL ;
    SHAPE ABUTMENT ;
    PORT
      LAYER met2 ;
      RECT 89.630 954.300 89.770 954.720 ;
    END
  END rw0_wmask_in[445]
  PIN rw0_wmask_in[446]
    DIRECTION INPUT ;
    USE SIGNAL ;
    SHAPE ABUTMENT ;
    PORT
      LAYER met2 ;
      RECT 90.090 954.300 90.230 954.720 ;
    END
  END rw0_wmask_in[446]
  PIN rw0_wmask_in[447]
    DIRECTION INPUT ;
    USE SIGNAL ;
    SHAPE ABUTMENT ;
    PORT
      LAYER met2 ;
      RECT 90.550 954.300 90.690 954.720 ;
    END
  END rw0_wmask_in[447]
  PIN rw0_wmask_in[448]
    DIRECTION INPUT ;
    USE SIGNAL ;
    SHAPE ABUTMENT ;
    PORT
      LAYER met2 ;
      RECT 91.010 954.300 91.150 954.720 ;
    END
  END rw0_wmask_in[448]
  PIN rw0_wmask_in[449]
    DIRECTION INPUT ;
    USE SIGNAL ;
    SHAPE ABUTMENT ;
    PORT
      LAYER met2 ;
      RECT 91.470 954.300 91.610 954.720 ;
    END
  END rw0_wmask_in[449]
  PIN rw0_wmask_in[450]
    DIRECTION INPUT ;
    USE SIGNAL ;
    SHAPE ABUTMENT ;
    PORT
      LAYER met2 ;
      RECT 91.930 954.300 92.070 954.720 ;
    END
  END rw0_wmask_in[450]
  PIN rw0_wmask_in[451]
    DIRECTION INPUT ;
    USE SIGNAL ;
    SHAPE ABUTMENT ;
    PORT
      LAYER met2 ;
      RECT 92.390 954.300 92.530 954.720 ;
    END
  END rw0_wmask_in[451]
  PIN rw0_wmask_in[452]
    DIRECTION INPUT ;
    USE SIGNAL ;
    SHAPE ABUTMENT ;
    PORT
      LAYER met2 ;
      RECT 92.850 954.300 92.990 954.720 ;
    END
  END rw0_wmask_in[452]
  PIN rw0_wmask_in[453]
    DIRECTION INPUT ;
    USE SIGNAL ;
    SHAPE ABUTMENT ;
    PORT
      LAYER met2 ;
      RECT 93.310 954.300 93.450 954.720 ;
    END
  END rw0_wmask_in[453]
  PIN rw0_wmask_in[454]
    DIRECTION INPUT ;
    USE SIGNAL ;
    SHAPE ABUTMENT ;
    PORT
      LAYER met2 ;
      RECT 93.770 954.300 93.910 954.720 ;
    END
  END rw0_wmask_in[454]
  PIN rw0_wmask_in[455]
    DIRECTION INPUT ;
    USE SIGNAL ;
    SHAPE ABUTMENT ;
    PORT
      LAYER met2 ;
      RECT 94.230 954.300 94.370 954.720 ;
    END
  END rw0_wmask_in[455]
  PIN rw0_wmask_in[456]
    DIRECTION INPUT ;
    USE SIGNAL ;
    SHAPE ABUTMENT ;
    PORT
      LAYER met2 ;
      RECT 94.690 954.300 94.830 954.720 ;
    END
  END rw0_wmask_in[456]
  PIN rw0_wmask_in[457]
    DIRECTION INPUT ;
    USE SIGNAL ;
    SHAPE ABUTMENT ;
    PORT
      LAYER met2 ;
      RECT 95.150 954.300 95.290 954.720 ;
    END
  END rw0_wmask_in[457]
  PIN rw0_wmask_in[458]
    DIRECTION INPUT ;
    USE SIGNAL ;
    SHAPE ABUTMENT ;
    PORT
      LAYER met2 ;
      RECT 95.610 954.300 95.750 954.720 ;
    END
  END rw0_wmask_in[458]
  PIN rw0_wmask_in[459]
    DIRECTION INPUT ;
    USE SIGNAL ;
    SHAPE ABUTMENT ;
    PORT
      LAYER met2 ;
      RECT 96.070 954.300 96.210 954.720 ;
    END
  END rw0_wmask_in[459]
  PIN rw0_wmask_in[460]
    DIRECTION INPUT ;
    USE SIGNAL ;
    SHAPE ABUTMENT ;
    PORT
      LAYER met2 ;
      RECT 96.530 954.300 96.670 954.720 ;
    END
  END rw0_wmask_in[460]
  PIN rw0_wmask_in[461]
    DIRECTION INPUT ;
    USE SIGNAL ;
    SHAPE ABUTMENT ;
    PORT
      LAYER met2 ;
      RECT 96.990 954.300 97.130 954.720 ;
    END
  END rw0_wmask_in[461]
  PIN rw0_wmask_in[462]
    DIRECTION INPUT ;
    USE SIGNAL ;
    SHAPE ABUTMENT ;
    PORT
      LAYER met2 ;
      RECT 97.450 954.300 97.590 954.720 ;
    END
  END rw0_wmask_in[462]
  PIN rw0_wmask_in[463]
    DIRECTION INPUT ;
    USE SIGNAL ;
    SHAPE ABUTMENT ;
    PORT
      LAYER met2 ;
      RECT 97.910 954.300 98.050 954.720 ;
    END
  END rw0_wmask_in[463]
  PIN rw0_wmask_in[464]
    DIRECTION INPUT ;
    USE SIGNAL ;
    SHAPE ABUTMENT ;
    PORT
      LAYER met2 ;
      RECT 98.370 954.300 98.510 954.720 ;
    END
  END rw0_wmask_in[464]
  PIN rw0_wmask_in[465]
    DIRECTION INPUT ;
    USE SIGNAL ;
    SHAPE ABUTMENT ;
    PORT
      LAYER met2 ;
      RECT 98.830 954.300 98.970 954.720 ;
    END
  END rw0_wmask_in[465]
  PIN rw0_wmask_in[466]
    DIRECTION INPUT ;
    USE SIGNAL ;
    SHAPE ABUTMENT ;
    PORT
      LAYER met2 ;
      RECT 99.290 954.300 99.430 954.720 ;
    END
  END rw0_wmask_in[466]
  PIN rw0_wmask_in[467]
    DIRECTION INPUT ;
    USE SIGNAL ;
    SHAPE ABUTMENT ;
    PORT
      LAYER met2 ;
      RECT 99.750 954.300 99.890 954.720 ;
    END
  END rw0_wmask_in[467]
  PIN rw0_wmask_in[468]
    DIRECTION INPUT ;
    USE SIGNAL ;
    SHAPE ABUTMENT ;
    PORT
      LAYER met2 ;
      RECT 100.210 954.300 100.350 954.720 ;
    END
  END rw0_wmask_in[468]
  PIN rw0_wmask_in[469]
    DIRECTION INPUT ;
    USE SIGNAL ;
    SHAPE ABUTMENT ;
    PORT
      LAYER met2 ;
      RECT 100.670 954.300 100.810 954.720 ;
    END
  END rw0_wmask_in[469]
  PIN rw0_wmask_in[470]
    DIRECTION INPUT ;
    USE SIGNAL ;
    SHAPE ABUTMENT ;
    PORT
      LAYER met2 ;
      RECT 101.130 954.300 101.270 954.720 ;
    END
  END rw0_wmask_in[470]
  PIN rw0_wmask_in[471]
    DIRECTION INPUT ;
    USE SIGNAL ;
    SHAPE ABUTMENT ;
    PORT
      LAYER met2 ;
      RECT 101.590 954.300 101.730 954.720 ;
    END
  END rw0_wmask_in[471]
  PIN rw0_wmask_in[472]
    DIRECTION INPUT ;
    USE SIGNAL ;
    SHAPE ABUTMENT ;
    PORT
      LAYER met2 ;
      RECT 102.050 954.300 102.190 954.720 ;
    END
  END rw0_wmask_in[472]
  PIN rw0_wmask_in[473]
    DIRECTION INPUT ;
    USE SIGNAL ;
    SHAPE ABUTMENT ;
    PORT
      LAYER met2 ;
      RECT 102.510 954.300 102.650 954.720 ;
    END
  END rw0_wmask_in[473]
  PIN rw0_wmask_in[474]
    DIRECTION INPUT ;
    USE SIGNAL ;
    SHAPE ABUTMENT ;
    PORT
      LAYER met2 ;
      RECT 102.970 954.300 103.110 954.720 ;
    END
  END rw0_wmask_in[474]
  PIN rw0_wmask_in[475]
    DIRECTION INPUT ;
    USE SIGNAL ;
    SHAPE ABUTMENT ;
    PORT
      LAYER met2 ;
      RECT 103.430 954.300 103.570 954.720 ;
    END
  END rw0_wmask_in[475]
  PIN rw0_wmask_in[476]
    DIRECTION INPUT ;
    USE SIGNAL ;
    SHAPE ABUTMENT ;
    PORT
      LAYER met2 ;
      RECT 103.890 954.300 104.030 954.720 ;
    END
  END rw0_wmask_in[476]
  PIN rw0_wmask_in[477]
    DIRECTION INPUT ;
    USE SIGNAL ;
    SHAPE ABUTMENT ;
    PORT
      LAYER met2 ;
      RECT 104.350 954.300 104.490 954.720 ;
    END
  END rw0_wmask_in[477]
  PIN rw0_wmask_in[478]
    DIRECTION INPUT ;
    USE SIGNAL ;
    SHAPE ABUTMENT ;
    PORT
      LAYER met2 ;
      RECT 104.810 954.300 104.950 954.720 ;
    END
  END rw0_wmask_in[478]
  PIN rw0_wmask_in[479]
    DIRECTION INPUT ;
    USE SIGNAL ;
    SHAPE ABUTMENT ;
    PORT
      LAYER met2 ;
      RECT 105.270 954.300 105.410 954.720 ;
    END
  END rw0_wmask_in[479]
  PIN rw0_wmask_in[480]
    DIRECTION INPUT ;
    USE SIGNAL ;
    SHAPE ABUTMENT ;
    PORT
      LAYER met2 ;
      RECT 105.730 954.300 105.870 954.720 ;
    END
  END rw0_wmask_in[480]
  PIN rw0_wmask_in[481]
    DIRECTION INPUT ;
    USE SIGNAL ;
    SHAPE ABUTMENT ;
    PORT
      LAYER met2 ;
      RECT 106.190 954.300 106.330 954.720 ;
    END
  END rw0_wmask_in[481]
  PIN rw0_wmask_in[482]
    DIRECTION INPUT ;
    USE SIGNAL ;
    SHAPE ABUTMENT ;
    PORT
      LAYER met2 ;
      RECT 106.650 954.300 106.790 954.720 ;
    END
  END rw0_wmask_in[482]
  PIN rw0_wmask_in[483]
    DIRECTION INPUT ;
    USE SIGNAL ;
    SHAPE ABUTMENT ;
    PORT
      LAYER met2 ;
      RECT 107.110 954.300 107.250 954.720 ;
    END
  END rw0_wmask_in[483]
  PIN rw0_wmask_in[484]
    DIRECTION INPUT ;
    USE SIGNAL ;
    SHAPE ABUTMENT ;
    PORT
      LAYER met2 ;
      RECT 107.570 954.300 107.710 954.720 ;
    END
  END rw0_wmask_in[484]
  PIN rw0_wmask_in[485]
    DIRECTION INPUT ;
    USE SIGNAL ;
    SHAPE ABUTMENT ;
    PORT
      LAYER met2 ;
      RECT 108.030 954.300 108.170 954.720 ;
    END
  END rw0_wmask_in[485]
  PIN rw0_wmask_in[486]
    DIRECTION INPUT ;
    USE SIGNAL ;
    SHAPE ABUTMENT ;
    PORT
      LAYER met2 ;
      RECT 108.490 954.300 108.630 954.720 ;
    END
  END rw0_wmask_in[486]
  PIN rw0_wmask_in[487]
    DIRECTION INPUT ;
    USE SIGNAL ;
    SHAPE ABUTMENT ;
    PORT
      LAYER met2 ;
      RECT 108.950 954.300 109.090 954.720 ;
    END
  END rw0_wmask_in[487]
  PIN rw0_wmask_in[488]
    DIRECTION INPUT ;
    USE SIGNAL ;
    SHAPE ABUTMENT ;
    PORT
      LAYER met2 ;
      RECT 109.410 954.300 109.550 954.720 ;
    END
  END rw0_wmask_in[488]
  PIN rw0_wmask_in[489]
    DIRECTION INPUT ;
    USE SIGNAL ;
    SHAPE ABUTMENT ;
    PORT
      LAYER met2 ;
      RECT 109.870 954.300 110.010 954.720 ;
    END
  END rw0_wmask_in[489]
  PIN rw0_wmask_in[490]
    DIRECTION INPUT ;
    USE SIGNAL ;
    SHAPE ABUTMENT ;
    PORT
      LAYER met2 ;
      RECT 110.330 954.300 110.470 954.720 ;
    END
  END rw0_wmask_in[490]
  PIN rw0_wmask_in[491]
    DIRECTION INPUT ;
    USE SIGNAL ;
    SHAPE ABUTMENT ;
    PORT
      LAYER met2 ;
      RECT 110.790 954.300 110.930 954.720 ;
    END
  END rw0_wmask_in[491]
  PIN rw0_wmask_in[492]
    DIRECTION INPUT ;
    USE SIGNAL ;
    SHAPE ABUTMENT ;
    PORT
      LAYER met2 ;
      RECT 111.250 954.300 111.390 954.720 ;
    END
  END rw0_wmask_in[492]
  PIN rw0_wmask_in[493]
    DIRECTION INPUT ;
    USE SIGNAL ;
    SHAPE ABUTMENT ;
    PORT
      LAYER met2 ;
      RECT 111.710 954.300 111.850 954.720 ;
    END
  END rw0_wmask_in[493]
  PIN rw0_wmask_in[494]
    DIRECTION INPUT ;
    USE SIGNAL ;
    SHAPE ABUTMENT ;
    PORT
      LAYER met2 ;
      RECT 112.170 954.300 112.310 954.720 ;
    END
  END rw0_wmask_in[494]
  PIN rw0_wmask_in[495]
    DIRECTION INPUT ;
    USE SIGNAL ;
    SHAPE ABUTMENT ;
    PORT
      LAYER met2 ;
      RECT 112.630 954.300 112.770 954.720 ;
    END
  END rw0_wmask_in[495]
  PIN rw0_wmask_in[496]
    DIRECTION INPUT ;
    USE SIGNAL ;
    SHAPE ABUTMENT ;
    PORT
      LAYER met2 ;
      RECT 113.090 954.300 113.230 954.720 ;
    END
  END rw0_wmask_in[496]
  PIN rw0_wmask_in[497]
    DIRECTION INPUT ;
    USE SIGNAL ;
    SHAPE ABUTMENT ;
    PORT
      LAYER met2 ;
      RECT 113.550 954.300 113.690 954.720 ;
    END
  END rw0_wmask_in[497]
  PIN rw0_wmask_in[498]
    DIRECTION INPUT ;
    USE SIGNAL ;
    SHAPE ABUTMENT ;
    PORT
      LAYER met2 ;
      RECT 114.010 954.300 114.150 954.720 ;
    END
  END rw0_wmask_in[498]
  PIN rw0_wmask_in[499]
    DIRECTION INPUT ;
    USE SIGNAL ;
    SHAPE ABUTMENT ;
    PORT
      LAYER met2 ;
      RECT 114.470 954.300 114.610 954.720 ;
    END
  END rw0_wmask_in[499]
  PIN rw0_wmask_in[500]
    DIRECTION INPUT ;
    USE SIGNAL ;
    SHAPE ABUTMENT ;
    PORT
      LAYER met2 ;
      RECT 114.930 954.300 115.070 954.720 ;
    END
  END rw0_wmask_in[500]
  PIN rw0_wmask_in[501]
    DIRECTION INPUT ;
    USE SIGNAL ;
    SHAPE ABUTMENT ;
    PORT
      LAYER met2 ;
      RECT 115.390 954.300 115.530 954.720 ;
    END
  END rw0_wmask_in[501]
  PIN rw0_wmask_in[502]
    DIRECTION INPUT ;
    USE SIGNAL ;
    SHAPE ABUTMENT ;
    PORT
      LAYER met2 ;
      RECT 115.850 954.300 115.990 954.720 ;
    END
  END rw0_wmask_in[502]
  PIN rw0_wmask_in[503]
    DIRECTION INPUT ;
    USE SIGNAL ;
    SHAPE ABUTMENT ;
    PORT
      LAYER met2 ;
      RECT 116.310 954.300 116.450 954.720 ;
    END
  END rw0_wmask_in[503]
  PIN rw0_wmask_in[504]
    DIRECTION INPUT ;
    USE SIGNAL ;
    SHAPE ABUTMENT ;
    PORT
      LAYER met2 ;
      RECT 116.770 954.300 116.910 954.720 ;
    END
  END rw0_wmask_in[504]
  PIN rw0_wmask_in[505]
    DIRECTION INPUT ;
    USE SIGNAL ;
    SHAPE ABUTMENT ;
    PORT
      LAYER met2 ;
      RECT 117.230 954.300 117.370 954.720 ;
    END
  END rw0_wmask_in[505]
  PIN rw0_wmask_in[506]
    DIRECTION INPUT ;
    USE SIGNAL ;
    SHAPE ABUTMENT ;
    PORT
      LAYER met2 ;
      RECT 117.690 954.300 117.830 954.720 ;
    END
  END rw0_wmask_in[506]
  PIN rw0_wmask_in[507]
    DIRECTION INPUT ;
    USE SIGNAL ;
    SHAPE ABUTMENT ;
    PORT
      LAYER met2 ;
      RECT 118.150 954.300 118.290 954.720 ;
    END
  END rw0_wmask_in[507]
  PIN rw0_wmask_in[508]
    DIRECTION INPUT ;
    USE SIGNAL ;
    SHAPE ABUTMENT ;
    PORT
      LAYER met2 ;
      RECT 118.610 954.300 118.750 954.720 ;
    END
  END rw0_wmask_in[508]
  PIN rw0_wmask_in[509]
    DIRECTION INPUT ;
    USE SIGNAL ;
    SHAPE ABUTMENT ;
    PORT
      LAYER met2 ;
      RECT 119.070 954.300 119.210 954.720 ;
    END
  END rw0_wmask_in[509]
  PIN rw0_wmask_in[510]
    DIRECTION INPUT ;
    USE SIGNAL ;
    SHAPE ABUTMENT ;
    PORT
      LAYER met2 ;
      RECT 119.530 954.300 119.670 954.720 ;
    END
  END rw0_wmask_in[510]
  PIN rw0_wmask_in[511]
    DIRECTION INPUT ;
    USE SIGNAL ;
    SHAPE ABUTMENT ;
    PORT
      LAYER met2 ;
      RECT 119.990 954.300 120.130 954.720 ;
    END
  END rw0_wmask_in[511]
  PIN rw0_wd_in[0]
    DIRECTION INPUT ;
    USE SIGNAL ;
    SHAPE ABUTMENT ;
    PORT
      LAYER met3 ;
      RECT 0.000 439.130 0.900 439.430 ;
    END
  END rw0_wd_in[0]
  PIN rw0_wd_in[1]
    DIRECTION INPUT ;
    USE SIGNAL ;
    SHAPE ABUTMENT ;
    PORT
      LAYER met3 ;
      RECT 0.000 442.530 0.900 442.830 ;
    END
  END rw0_wd_in[1]
  PIN rw0_wd_in[2]
    DIRECTION INPUT ;
    USE SIGNAL ;
    SHAPE ABUTMENT ;
    PORT
      LAYER met3 ;
      RECT 0.000 445.930 0.900 446.230 ;
    END
  END rw0_wd_in[2]
  PIN rw0_wd_in[3]
    DIRECTION INPUT ;
    USE SIGNAL ;
    SHAPE ABUTMENT ;
    PORT
      LAYER met3 ;
      RECT 0.000 449.330 0.900 449.630 ;
    END
  END rw0_wd_in[3]
  PIN rw0_wd_in[4]
    DIRECTION INPUT ;
    USE SIGNAL ;
    SHAPE ABUTMENT ;
    PORT
      LAYER met3 ;
      RECT 0.000 452.730 0.900 453.030 ;
    END
  END rw0_wd_in[4]
  PIN rw0_wd_in[5]
    DIRECTION INPUT ;
    USE SIGNAL ;
    SHAPE ABUTMENT ;
    PORT
      LAYER met3 ;
      RECT 0.000 456.130 0.900 456.430 ;
    END
  END rw0_wd_in[5]
  PIN rw0_wd_in[6]
    DIRECTION INPUT ;
    USE SIGNAL ;
    SHAPE ABUTMENT ;
    PORT
      LAYER met3 ;
      RECT 0.000 459.530 0.900 459.830 ;
    END
  END rw0_wd_in[6]
  PIN rw0_wd_in[7]
    DIRECTION INPUT ;
    USE SIGNAL ;
    SHAPE ABUTMENT ;
    PORT
      LAYER met3 ;
      RECT 0.000 462.930 0.900 463.230 ;
    END
  END rw0_wd_in[7]
  PIN rw0_wd_in[8]
    DIRECTION INPUT ;
    USE SIGNAL ;
    SHAPE ABUTMENT ;
    PORT
      LAYER met3 ;
      RECT 0.000 466.330 0.900 466.630 ;
    END
  END rw0_wd_in[8]
  PIN rw0_wd_in[9]
    DIRECTION INPUT ;
    USE SIGNAL ;
    SHAPE ABUTMENT ;
    PORT
      LAYER met3 ;
      RECT 0.000 469.730 0.900 470.030 ;
    END
  END rw0_wd_in[9]
  PIN rw0_wd_in[10]
    DIRECTION INPUT ;
    USE SIGNAL ;
    SHAPE ABUTMENT ;
    PORT
      LAYER met3 ;
      RECT 0.000 473.130 0.900 473.430 ;
    END
  END rw0_wd_in[10]
  PIN rw0_wd_in[11]
    DIRECTION INPUT ;
    USE SIGNAL ;
    SHAPE ABUTMENT ;
    PORT
      LAYER met3 ;
      RECT 0.000 476.530 0.900 476.830 ;
    END
  END rw0_wd_in[11]
  PIN rw0_wd_in[12]
    DIRECTION INPUT ;
    USE SIGNAL ;
    SHAPE ABUTMENT ;
    PORT
      LAYER met3 ;
      RECT 0.000 479.930 0.900 480.230 ;
    END
  END rw0_wd_in[12]
  PIN rw0_wd_in[13]
    DIRECTION INPUT ;
    USE SIGNAL ;
    SHAPE ABUTMENT ;
    PORT
      LAYER met3 ;
      RECT 0.000 483.330 0.900 483.630 ;
    END
  END rw0_wd_in[13]
  PIN rw0_wd_in[14]
    DIRECTION INPUT ;
    USE SIGNAL ;
    SHAPE ABUTMENT ;
    PORT
      LAYER met3 ;
      RECT 0.000 486.730 0.900 487.030 ;
    END
  END rw0_wd_in[14]
  PIN rw0_wd_in[15]
    DIRECTION INPUT ;
    USE SIGNAL ;
    SHAPE ABUTMENT ;
    PORT
      LAYER met3 ;
      RECT 0.000 490.130 0.900 490.430 ;
    END
  END rw0_wd_in[15]
  PIN rw0_wd_in[16]
    DIRECTION INPUT ;
    USE SIGNAL ;
    SHAPE ABUTMENT ;
    PORT
      LAYER met3 ;
      RECT 0.000 493.530 0.900 493.830 ;
    END
  END rw0_wd_in[16]
  PIN rw0_wd_in[17]
    DIRECTION INPUT ;
    USE SIGNAL ;
    SHAPE ABUTMENT ;
    PORT
      LAYER met3 ;
      RECT 0.000 496.930 0.900 497.230 ;
    END
  END rw0_wd_in[17]
  PIN rw0_wd_in[18]
    DIRECTION INPUT ;
    USE SIGNAL ;
    SHAPE ABUTMENT ;
    PORT
      LAYER met3 ;
      RECT 0.000 500.330 0.900 500.630 ;
    END
  END rw0_wd_in[18]
  PIN rw0_wd_in[19]
    DIRECTION INPUT ;
    USE SIGNAL ;
    SHAPE ABUTMENT ;
    PORT
      LAYER met3 ;
      RECT 0.000 503.730 0.900 504.030 ;
    END
  END rw0_wd_in[19]
  PIN rw0_wd_in[20]
    DIRECTION INPUT ;
    USE SIGNAL ;
    SHAPE ABUTMENT ;
    PORT
      LAYER met3 ;
      RECT 0.000 507.130 0.900 507.430 ;
    END
  END rw0_wd_in[20]
  PIN rw0_wd_in[21]
    DIRECTION INPUT ;
    USE SIGNAL ;
    SHAPE ABUTMENT ;
    PORT
      LAYER met3 ;
      RECT 0.000 510.530 0.900 510.830 ;
    END
  END rw0_wd_in[21]
  PIN rw0_wd_in[22]
    DIRECTION INPUT ;
    USE SIGNAL ;
    SHAPE ABUTMENT ;
    PORT
      LAYER met3 ;
      RECT 0.000 513.930 0.900 514.230 ;
    END
  END rw0_wd_in[22]
  PIN rw0_wd_in[23]
    DIRECTION INPUT ;
    USE SIGNAL ;
    SHAPE ABUTMENT ;
    PORT
      LAYER met3 ;
      RECT 0.000 517.330 0.900 517.630 ;
    END
  END rw0_wd_in[23]
  PIN rw0_wd_in[24]
    DIRECTION INPUT ;
    USE SIGNAL ;
    SHAPE ABUTMENT ;
    PORT
      LAYER met3 ;
      RECT 0.000 520.730 0.900 521.030 ;
    END
  END rw0_wd_in[24]
  PIN rw0_wd_in[25]
    DIRECTION INPUT ;
    USE SIGNAL ;
    SHAPE ABUTMENT ;
    PORT
      LAYER met3 ;
      RECT 0.000 524.130 0.900 524.430 ;
    END
  END rw0_wd_in[25]
  PIN rw0_wd_in[26]
    DIRECTION INPUT ;
    USE SIGNAL ;
    SHAPE ABUTMENT ;
    PORT
      LAYER met3 ;
      RECT 0.000 527.530 0.900 527.830 ;
    END
  END rw0_wd_in[26]
  PIN rw0_wd_in[27]
    DIRECTION INPUT ;
    USE SIGNAL ;
    SHAPE ABUTMENT ;
    PORT
      LAYER met3 ;
      RECT 0.000 530.930 0.900 531.230 ;
    END
  END rw0_wd_in[27]
  PIN rw0_wd_in[28]
    DIRECTION INPUT ;
    USE SIGNAL ;
    SHAPE ABUTMENT ;
    PORT
      LAYER met3 ;
      RECT 0.000 534.330 0.900 534.630 ;
    END
  END rw0_wd_in[28]
  PIN rw0_wd_in[29]
    DIRECTION INPUT ;
    USE SIGNAL ;
    SHAPE ABUTMENT ;
    PORT
      LAYER met3 ;
      RECT 0.000 537.730 0.900 538.030 ;
    END
  END rw0_wd_in[29]
  PIN rw0_wd_in[30]
    DIRECTION INPUT ;
    USE SIGNAL ;
    SHAPE ABUTMENT ;
    PORT
      LAYER met3 ;
      RECT 0.000 541.130 0.900 541.430 ;
    END
  END rw0_wd_in[30]
  PIN rw0_wd_in[31]
    DIRECTION INPUT ;
    USE SIGNAL ;
    SHAPE ABUTMENT ;
    PORT
      LAYER met3 ;
      RECT 0.000 544.530 0.900 544.830 ;
    END
  END rw0_wd_in[31]
  PIN rw0_wd_in[32]
    DIRECTION INPUT ;
    USE SIGNAL ;
    SHAPE ABUTMENT ;
    PORT
      LAYER met3 ;
      RECT 0.000 547.930 0.900 548.230 ;
    END
  END rw0_wd_in[32]
  PIN rw0_wd_in[33]
    DIRECTION INPUT ;
    USE SIGNAL ;
    SHAPE ABUTMENT ;
    PORT
      LAYER met3 ;
      RECT 0.000 551.330 0.900 551.630 ;
    END
  END rw0_wd_in[33]
  PIN rw0_wd_in[34]
    DIRECTION INPUT ;
    USE SIGNAL ;
    SHAPE ABUTMENT ;
    PORT
      LAYER met3 ;
      RECT 0.000 554.730 0.900 555.030 ;
    END
  END rw0_wd_in[34]
  PIN rw0_wd_in[35]
    DIRECTION INPUT ;
    USE SIGNAL ;
    SHAPE ABUTMENT ;
    PORT
      LAYER met3 ;
      RECT 0.000 558.130 0.900 558.430 ;
    END
  END rw0_wd_in[35]
  PIN rw0_wd_in[36]
    DIRECTION INPUT ;
    USE SIGNAL ;
    SHAPE ABUTMENT ;
    PORT
      LAYER met3 ;
      RECT 0.000 561.530 0.900 561.830 ;
    END
  END rw0_wd_in[36]
  PIN rw0_wd_in[37]
    DIRECTION INPUT ;
    USE SIGNAL ;
    SHAPE ABUTMENT ;
    PORT
      LAYER met3 ;
      RECT 0.000 564.930 0.900 565.230 ;
    END
  END rw0_wd_in[37]
  PIN rw0_wd_in[38]
    DIRECTION INPUT ;
    USE SIGNAL ;
    SHAPE ABUTMENT ;
    PORT
      LAYER met3 ;
      RECT 0.000 568.330 0.900 568.630 ;
    END
  END rw0_wd_in[38]
  PIN rw0_wd_in[39]
    DIRECTION INPUT ;
    USE SIGNAL ;
    SHAPE ABUTMENT ;
    PORT
      LAYER met3 ;
      RECT 0.000 571.730 0.900 572.030 ;
    END
  END rw0_wd_in[39]
  PIN rw0_wd_in[40]
    DIRECTION INPUT ;
    USE SIGNAL ;
    SHAPE ABUTMENT ;
    PORT
      LAYER met3 ;
      RECT 0.000 575.130 0.900 575.430 ;
    END
  END rw0_wd_in[40]
  PIN rw0_wd_in[41]
    DIRECTION INPUT ;
    USE SIGNAL ;
    SHAPE ABUTMENT ;
    PORT
      LAYER met3 ;
      RECT 0.000 578.530 0.900 578.830 ;
    END
  END rw0_wd_in[41]
  PIN rw0_wd_in[42]
    DIRECTION INPUT ;
    USE SIGNAL ;
    SHAPE ABUTMENT ;
    PORT
      LAYER met3 ;
      RECT 0.000 581.930 0.900 582.230 ;
    END
  END rw0_wd_in[42]
  PIN rw0_wd_in[43]
    DIRECTION INPUT ;
    USE SIGNAL ;
    SHAPE ABUTMENT ;
    PORT
      LAYER met3 ;
      RECT 0.000 585.330 0.900 585.630 ;
    END
  END rw0_wd_in[43]
  PIN rw0_wd_in[44]
    DIRECTION INPUT ;
    USE SIGNAL ;
    SHAPE ABUTMENT ;
    PORT
      LAYER met3 ;
      RECT 0.000 588.730 0.900 589.030 ;
    END
  END rw0_wd_in[44]
  PIN rw0_wd_in[45]
    DIRECTION INPUT ;
    USE SIGNAL ;
    SHAPE ABUTMENT ;
    PORT
      LAYER met3 ;
      RECT 0.000 592.130 0.900 592.430 ;
    END
  END rw0_wd_in[45]
  PIN rw0_wd_in[46]
    DIRECTION INPUT ;
    USE SIGNAL ;
    SHAPE ABUTMENT ;
    PORT
      LAYER met3 ;
      RECT 0.000 595.530 0.900 595.830 ;
    END
  END rw0_wd_in[46]
  PIN rw0_wd_in[47]
    DIRECTION INPUT ;
    USE SIGNAL ;
    SHAPE ABUTMENT ;
    PORT
      LAYER met3 ;
      RECT 0.000 598.930 0.900 599.230 ;
    END
  END rw0_wd_in[47]
  PIN rw0_wd_in[48]
    DIRECTION INPUT ;
    USE SIGNAL ;
    SHAPE ABUTMENT ;
    PORT
      LAYER met3 ;
      RECT 0.000 602.330 0.900 602.630 ;
    END
  END rw0_wd_in[48]
  PIN rw0_wd_in[49]
    DIRECTION INPUT ;
    USE SIGNAL ;
    SHAPE ABUTMENT ;
    PORT
      LAYER met3 ;
      RECT 0.000 605.730 0.900 606.030 ;
    END
  END rw0_wd_in[49]
  PIN rw0_wd_in[50]
    DIRECTION INPUT ;
    USE SIGNAL ;
    SHAPE ABUTMENT ;
    PORT
      LAYER met3 ;
      RECT 0.000 609.130 0.900 609.430 ;
    END
  END rw0_wd_in[50]
  PIN rw0_wd_in[51]
    DIRECTION INPUT ;
    USE SIGNAL ;
    SHAPE ABUTMENT ;
    PORT
      LAYER met3 ;
      RECT 0.000 612.530 0.900 612.830 ;
    END
  END rw0_wd_in[51]
  PIN rw0_wd_in[52]
    DIRECTION INPUT ;
    USE SIGNAL ;
    SHAPE ABUTMENT ;
    PORT
      LAYER met3 ;
      RECT 0.000 615.930 0.900 616.230 ;
    END
  END rw0_wd_in[52]
  PIN rw0_wd_in[53]
    DIRECTION INPUT ;
    USE SIGNAL ;
    SHAPE ABUTMENT ;
    PORT
      LAYER met3 ;
      RECT 0.000 619.330 0.900 619.630 ;
    END
  END rw0_wd_in[53]
  PIN rw0_wd_in[54]
    DIRECTION INPUT ;
    USE SIGNAL ;
    SHAPE ABUTMENT ;
    PORT
      LAYER met3 ;
      RECT 0.000 622.730 0.900 623.030 ;
    END
  END rw0_wd_in[54]
  PIN rw0_wd_in[55]
    DIRECTION INPUT ;
    USE SIGNAL ;
    SHAPE ABUTMENT ;
    PORT
      LAYER met3 ;
      RECT 0.000 626.130 0.900 626.430 ;
    END
  END rw0_wd_in[55]
  PIN rw0_wd_in[56]
    DIRECTION INPUT ;
    USE SIGNAL ;
    SHAPE ABUTMENT ;
    PORT
      LAYER met3 ;
      RECT 0.000 629.530 0.900 629.830 ;
    END
  END rw0_wd_in[56]
  PIN rw0_wd_in[57]
    DIRECTION INPUT ;
    USE SIGNAL ;
    SHAPE ABUTMENT ;
    PORT
      LAYER met3 ;
      RECT 0.000 632.930 0.900 633.230 ;
    END
  END rw0_wd_in[57]
  PIN rw0_wd_in[58]
    DIRECTION INPUT ;
    USE SIGNAL ;
    SHAPE ABUTMENT ;
    PORT
      LAYER met3 ;
      RECT 0.000 636.330 0.900 636.630 ;
    END
  END rw0_wd_in[58]
  PIN rw0_wd_in[59]
    DIRECTION INPUT ;
    USE SIGNAL ;
    SHAPE ABUTMENT ;
    PORT
      LAYER met3 ;
      RECT 0.000 639.730 0.900 640.030 ;
    END
  END rw0_wd_in[59]
  PIN rw0_wd_in[60]
    DIRECTION INPUT ;
    USE SIGNAL ;
    SHAPE ABUTMENT ;
    PORT
      LAYER met3 ;
      RECT 0.000 643.130 0.900 643.430 ;
    END
  END rw0_wd_in[60]
  PIN rw0_wd_in[61]
    DIRECTION INPUT ;
    USE SIGNAL ;
    SHAPE ABUTMENT ;
    PORT
      LAYER met3 ;
      RECT 0.000 646.530 0.900 646.830 ;
    END
  END rw0_wd_in[61]
  PIN rw0_wd_in[62]
    DIRECTION INPUT ;
    USE SIGNAL ;
    SHAPE ABUTMENT ;
    PORT
      LAYER met3 ;
      RECT 0.000 649.930 0.900 650.230 ;
    END
  END rw0_wd_in[62]
  PIN rw0_wd_in[63]
    DIRECTION INPUT ;
    USE SIGNAL ;
    SHAPE ABUTMENT ;
    PORT
      LAYER met3 ;
      RECT 0.000 653.330 0.900 653.630 ;
    END
  END rw0_wd_in[63]
  PIN rw0_wd_in[64]
    DIRECTION INPUT ;
    USE SIGNAL ;
    SHAPE ABUTMENT ;
    PORT
      LAYER met3 ;
      RECT 0.000 656.730 0.900 657.030 ;
    END
  END rw0_wd_in[64]
  PIN rw0_wd_in[65]
    DIRECTION INPUT ;
    USE SIGNAL ;
    SHAPE ABUTMENT ;
    PORT
      LAYER met3 ;
      RECT 0.000 660.130 0.900 660.430 ;
    END
  END rw0_wd_in[65]
  PIN rw0_wd_in[66]
    DIRECTION INPUT ;
    USE SIGNAL ;
    SHAPE ABUTMENT ;
    PORT
      LAYER met3 ;
      RECT 0.000 663.530 0.900 663.830 ;
    END
  END rw0_wd_in[66]
  PIN rw0_wd_in[67]
    DIRECTION INPUT ;
    USE SIGNAL ;
    SHAPE ABUTMENT ;
    PORT
      LAYER met3 ;
      RECT 0.000 666.930 0.900 667.230 ;
    END
  END rw0_wd_in[67]
  PIN rw0_wd_in[68]
    DIRECTION INPUT ;
    USE SIGNAL ;
    SHAPE ABUTMENT ;
    PORT
      LAYER met3 ;
      RECT 0.000 670.330 0.900 670.630 ;
    END
  END rw0_wd_in[68]
  PIN rw0_wd_in[69]
    DIRECTION INPUT ;
    USE SIGNAL ;
    SHAPE ABUTMENT ;
    PORT
      LAYER met3 ;
      RECT 0.000 673.730 0.900 674.030 ;
    END
  END rw0_wd_in[69]
  PIN rw0_wd_in[70]
    DIRECTION INPUT ;
    USE SIGNAL ;
    SHAPE ABUTMENT ;
    PORT
      LAYER met3 ;
      RECT 0.000 677.130 0.900 677.430 ;
    END
  END rw0_wd_in[70]
  PIN rw0_wd_in[71]
    DIRECTION INPUT ;
    USE SIGNAL ;
    SHAPE ABUTMENT ;
    PORT
      LAYER met3 ;
      RECT 0.000 680.530 0.900 680.830 ;
    END
  END rw0_wd_in[71]
  PIN rw0_wd_in[72]
    DIRECTION INPUT ;
    USE SIGNAL ;
    SHAPE ABUTMENT ;
    PORT
      LAYER met3 ;
      RECT 0.000 683.930 0.900 684.230 ;
    END
  END rw0_wd_in[72]
  PIN rw0_wd_in[73]
    DIRECTION INPUT ;
    USE SIGNAL ;
    SHAPE ABUTMENT ;
    PORT
      LAYER met3 ;
      RECT 0.000 687.330 0.900 687.630 ;
    END
  END rw0_wd_in[73]
  PIN rw0_wd_in[74]
    DIRECTION INPUT ;
    USE SIGNAL ;
    SHAPE ABUTMENT ;
    PORT
      LAYER met3 ;
      RECT 0.000 690.730 0.900 691.030 ;
    END
  END rw0_wd_in[74]
  PIN rw0_wd_in[75]
    DIRECTION INPUT ;
    USE SIGNAL ;
    SHAPE ABUTMENT ;
    PORT
      LAYER met3 ;
      RECT 0.000 694.130 0.900 694.430 ;
    END
  END rw0_wd_in[75]
  PIN rw0_wd_in[76]
    DIRECTION INPUT ;
    USE SIGNAL ;
    SHAPE ABUTMENT ;
    PORT
      LAYER met3 ;
      RECT 0.000 697.530 0.900 697.830 ;
    END
  END rw0_wd_in[76]
  PIN rw0_wd_in[77]
    DIRECTION INPUT ;
    USE SIGNAL ;
    SHAPE ABUTMENT ;
    PORT
      LAYER met3 ;
      RECT 0.000 700.930 0.900 701.230 ;
    END
  END rw0_wd_in[77]
  PIN rw0_wd_in[78]
    DIRECTION INPUT ;
    USE SIGNAL ;
    SHAPE ABUTMENT ;
    PORT
      LAYER met3 ;
      RECT 0.000 704.330 0.900 704.630 ;
    END
  END rw0_wd_in[78]
  PIN rw0_wd_in[79]
    DIRECTION INPUT ;
    USE SIGNAL ;
    SHAPE ABUTMENT ;
    PORT
      LAYER met3 ;
      RECT 0.000 707.730 0.900 708.030 ;
    END
  END rw0_wd_in[79]
  PIN rw0_wd_in[80]
    DIRECTION INPUT ;
    USE SIGNAL ;
    SHAPE ABUTMENT ;
    PORT
      LAYER met3 ;
      RECT 0.000 711.130 0.900 711.430 ;
    END
  END rw0_wd_in[80]
  PIN rw0_wd_in[81]
    DIRECTION INPUT ;
    USE SIGNAL ;
    SHAPE ABUTMENT ;
    PORT
      LAYER met3 ;
      RECT 0.000 714.530 0.900 714.830 ;
    END
  END rw0_wd_in[81]
  PIN rw0_wd_in[82]
    DIRECTION INPUT ;
    USE SIGNAL ;
    SHAPE ABUTMENT ;
    PORT
      LAYER met3 ;
      RECT 0.000 717.930 0.900 718.230 ;
    END
  END rw0_wd_in[82]
  PIN rw0_wd_in[83]
    DIRECTION INPUT ;
    USE SIGNAL ;
    SHAPE ABUTMENT ;
    PORT
      LAYER met3 ;
      RECT 0.000 721.330 0.900 721.630 ;
    END
  END rw0_wd_in[83]
  PIN rw0_wd_in[84]
    DIRECTION INPUT ;
    USE SIGNAL ;
    SHAPE ABUTMENT ;
    PORT
      LAYER met3 ;
      RECT 0.000 724.730 0.900 725.030 ;
    END
  END rw0_wd_in[84]
  PIN rw0_wd_in[85]
    DIRECTION INPUT ;
    USE SIGNAL ;
    SHAPE ABUTMENT ;
    PORT
      LAYER met3 ;
      RECT 0.000 728.130 0.900 728.430 ;
    END
  END rw0_wd_in[85]
  PIN rw0_wd_in[86]
    DIRECTION INPUT ;
    USE SIGNAL ;
    SHAPE ABUTMENT ;
    PORT
      LAYER met3 ;
      RECT 0.000 731.530 0.900 731.830 ;
    END
  END rw0_wd_in[86]
  PIN rw0_wd_in[87]
    DIRECTION INPUT ;
    USE SIGNAL ;
    SHAPE ABUTMENT ;
    PORT
      LAYER met3 ;
      RECT 0.000 734.930 0.900 735.230 ;
    END
  END rw0_wd_in[87]
  PIN rw0_wd_in[88]
    DIRECTION INPUT ;
    USE SIGNAL ;
    SHAPE ABUTMENT ;
    PORT
      LAYER met3 ;
      RECT 0.000 738.330 0.900 738.630 ;
    END
  END rw0_wd_in[88]
  PIN rw0_wd_in[89]
    DIRECTION INPUT ;
    USE SIGNAL ;
    SHAPE ABUTMENT ;
    PORT
      LAYER met3 ;
      RECT 0.000 741.730 0.900 742.030 ;
    END
  END rw0_wd_in[89]
  PIN rw0_wd_in[90]
    DIRECTION INPUT ;
    USE SIGNAL ;
    SHAPE ABUTMENT ;
    PORT
      LAYER met3 ;
      RECT 0.000 745.130 0.900 745.430 ;
    END
  END rw0_wd_in[90]
  PIN rw0_wd_in[91]
    DIRECTION INPUT ;
    USE SIGNAL ;
    SHAPE ABUTMENT ;
    PORT
      LAYER met3 ;
      RECT 0.000 748.530 0.900 748.830 ;
    END
  END rw0_wd_in[91]
  PIN rw0_wd_in[92]
    DIRECTION INPUT ;
    USE SIGNAL ;
    SHAPE ABUTMENT ;
    PORT
      LAYER met3 ;
      RECT 0.000 751.930 0.900 752.230 ;
    END
  END rw0_wd_in[92]
  PIN rw0_wd_in[93]
    DIRECTION INPUT ;
    USE SIGNAL ;
    SHAPE ABUTMENT ;
    PORT
      LAYER met3 ;
      RECT 0.000 755.330 0.900 755.630 ;
    END
  END rw0_wd_in[93]
  PIN rw0_wd_in[94]
    DIRECTION INPUT ;
    USE SIGNAL ;
    SHAPE ABUTMENT ;
    PORT
      LAYER met3 ;
      RECT 0.000 758.730 0.900 759.030 ;
    END
  END rw0_wd_in[94]
  PIN rw0_wd_in[95]
    DIRECTION INPUT ;
    USE SIGNAL ;
    SHAPE ABUTMENT ;
    PORT
      LAYER met3 ;
      RECT 0.000 762.130 0.900 762.430 ;
    END
  END rw0_wd_in[95]
  PIN rw0_wd_in[96]
    DIRECTION INPUT ;
    USE SIGNAL ;
    SHAPE ABUTMENT ;
    PORT
      LAYER met3 ;
      RECT 0.000 765.530 0.900 765.830 ;
    END
  END rw0_wd_in[96]
  PIN rw0_wd_in[97]
    DIRECTION INPUT ;
    USE SIGNAL ;
    SHAPE ABUTMENT ;
    PORT
      LAYER met3 ;
      RECT 0.000 768.930 0.900 769.230 ;
    END
  END rw0_wd_in[97]
  PIN rw0_wd_in[98]
    DIRECTION INPUT ;
    USE SIGNAL ;
    SHAPE ABUTMENT ;
    PORT
      LAYER met3 ;
      RECT 0.000 772.330 0.900 772.630 ;
    END
  END rw0_wd_in[98]
  PIN rw0_wd_in[99]
    DIRECTION INPUT ;
    USE SIGNAL ;
    SHAPE ABUTMENT ;
    PORT
      LAYER met3 ;
      RECT 0.000 775.730 0.900 776.030 ;
    END
  END rw0_wd_in[99]
  PIN rw0_wd_in[100]
    DIRECTION INPUT ;
    USE SIGNAL ;
    SHAPE ABUTMENT ;
    PORT
      LAYER met3 ;
      RECT 0.000 779.130 0.900 779.430 ;
    END
  END rw0_wd_in[100]
  PIN rw0_wd_in[101]
    DIRECTION INPUT ;
    USE SIGNAL ;
    SHAPE ABUTMENT ;
    PORT
      LAYER met3 ;
      RECT 0.000 782.530 0.900 782.830 ;
    END
  END rw0_wd_in[101]
  PIN rw0_wd_in[102]
    DIRECTION INPUT ;
    USE SIGNAL ;
    SHAPE ABUTMENT ;
    PORT
      LAYER met3 ;
      RECT 0.000 785.930 0.900 786.230 ;
    END
  END rw0_wd_in[102]
  PIN rw0_wd_in[103]
    DIRECTION INPUT ;
    USE SIGNAL ;
    SHAPE ABUTMENT ;
    PORT
      LAYER met3 ;
      RECT 0.000 789.330 0.900 789.630 ;
    END
  END rw0_wd_in[103]
  PIN rw0_wd_in[104]
    DIRECTION INPUT ;
    USE SIGNAL ;
    SHAPE ABUTMENT ;
    PORT
      LAYER met3 ;
      RECT 0.000 792.730 0.900 793.030 ;
    END
  END rw0_wd_in[104]
  PIN rw0_wd_in[105]
    DIRECTION INPUT ;
    USE SIGNAL ;
    SHAPE ABUTMENT ;
    PORT
      LAYER met3 ;
      RECT 0.000 796.130 0.900 796.430 ;
    END
  END rw0_wd_in[105]
  PIN rw0_wd_in[106]
    DIRECTION INPUT ;
    USE SIGNAL ;
    SHAPE ABUTMENT ;
    PORT
      LAYER met3 ;
      RECT 0.000 799.530 0.900 799.830 ;
    END
  END rw0_wd_in[106]
  PIN rw0_wd_in[107]
    DIRECTION INPUT ;
    USE SIGNAL ;
    SHAPE ABUTMENT ;
    PORT
      LAYER met3 ;
      RECT 0.000 802.930 0.900 803.230 ;
    END
  END rw0_wd_in[107]
  PIN rw0_wd_in[108]
    DIRECTION INPUT ;
    USE SIGNAL ;
    SHAPE ABUTMENT ;
    PORT
      LAYER met3 ;
      RECT 0.000 806.330 0.900 806.630 ;
    END
  END rw0_wd_in[108]
  PIN rw0_wd_in[109]
    DIRECTION INPUT ;
    USE SIGNAL ;
    SHAPE ABUTMENT ;
    PORT
      LAYER met3 ;
      RECT 0.000 809.730 0.900 810.030 ;
    END
  END rw0_wd_in[109]
  PIN rw0_wd_in[110]
    DIRECTION INPUT ;
    USE SIGNAL ;
    SHAPE ABUTMENT ;
    PORT
      LAYER met3 ;
      RECT 0.000 813.130 0.900 813.430 ;
    END
  END rw0_wd_in[110]
  PIN rw0_wd_in[111]
    DIRECTION INPUT ;
    USE SIGNAL ;
    SHAPE ABUTMENT ;
    PORT
      LAYER met3 ;
      RECT 0.000 816.530 0.900 816.830 ;
    END
  END rw0_wd_in[111]
  PIN rw0_wd_in[112]
    DIRECTION INPUT ;
    USE SIGNAL ;
    SHAPE ABUTMENT ;
    PORT
      LAYER met3 ;
      RECT 0.000 819.930 0.900 820.230 ;
    END
  END rw0_wd_in[112]
  PIN rw0_wd_in[113]
    DIRECTION INPUT ;
    USE SIGNAL ;
    SHAPE ABUTMENT ;
    PORT
      LAYER met3 ;
      RECT 0.000 823.330 0.900 823.630 ;
    END
  END rw0_wd_in[113]
  PIN rw0_wd_in[114]
    DIRECTION INPUT ;
    USE SIGNAL ;
    SHAPE ABUTMENT ;
    PORT
      LAYER met3 ;
      RECT 0.000 826.730 0.900 827.030 ;
    END
  END rw0_wd_in[114]
  PIN rw0_wd_in[115]
    DIRECTION INPUT ;
    USE SIGNAL ;
    SHAPE ABUTMENT ;
    PORT
      LAYER met3 ;
      RECT 0.000 830.130 0.900 830.430 ;
    END
  END rw0_wd_in[115]
  PIN rw0_wd_in[116]
    DIRECTION INPUT ;
    USE SIGNAL ;
    SHAPE ABUTMENT ;
    PORT
      LAYER met3 ;
      RECT 0.000 833.530 0.900 833.830 ;
    END
  END rw0_wd_in[116]
  PIN rw0_wd_in[117]
    DIRECTION INPUT ;
    USE SIGNAL ;
    SHAPE ABUTMENT ;
    PORT
      LAYER met3 ;
      RECT 0.000 836.930 0.900 837.230 ;
    END
  END rw0_wd_in[117]
  PIN rw0_wd_in[118]
    DIRECTION INPUT ;
    USE SIGNAL ;
    SHAPE ABUTMENT ;
    PORT
      LAYER met3 ;
      RECT 0.000 840.330 0.900 840.630 ;
    END
  END rw0_wd_in[118]
  PIN rw0_wd_in[119]
    DIRECTION INPUT ;
    USE SIGNAL ;
    SHAPE ABUTMENT ;
    PORT
      LAYER met3 ;
      RECT 0.000 843.730 0.900 844.030 ;
    END
  END rw0_wd_in[119]
  PIN rw0_wd_in[120]
    DIRECTION INPUT ;
    USE SIGNAL ;
    SHAPE ABUTMENT ;
    PORT
      LAYER met3 ;
      RECT 0.000 847.130 0.900 847.430 ;
    END
  END rw0_wd_in[120]
  PIN rw0_wd_in[121]
    DIRECTION INPUT ;
    USE SIGNAL ;
    SHAPE ABUTMENT ;
    PORT
      LAYER met3 ;
      RECT 0.000 850.530 0.900 850.830 ;
    END
  END rw0_wd_in[121]
  PIN rw0_wd_in[122]
    DIRECTION INPUT ;
    USE SIGNAL ;
    SHAPE ABUTMENT ;
    PORT
      LAYER met3 ;
      RECT 0.000 853.930 0.900 854.230 ;
    END
  END rw0_wd_in[122]
  PIN rw0_wd_in[123]
    DIRECTION INPUT ;
    USE SIGNAL ;
    SHAPE ABUTMENT ;
    PORT
      LAYER met3 ;
      RECT 0.000 857.330 0.900 857.630 ;
    END
  END rw0_wd_in[123]
  PIN rw0_wd_in[124]
    DIRECTION INPUT ;
    USE SIGNAL ;
    SHAPE ABUTMENT ;
    PORT
      LAYER met3 ;
      RECT 0.000 860.730 0.900 861.030 ;
    END
  END rw0_wd_in[124]
  PIN rw0_wd_in[125]
    DIRECTION INPUT ;
    USE SIGNAL ;
    SHAPE ABUTMENT ;
    PORT
      LAYER met3 ;
      RECT 0.000 864.130 0.900 864.430 ;
    END
  END rw0_wd_in[125]
  PIN rw0_wd_in[126]
    DIRECTION INPUT ;
    USE SIGNAL ;
    SHAPE ABUTMENT ;
    PORT
      LAYER met3 ;
      RECT 0.000 867.530 0.900 867.830 ;
    END
  END rw0_wd_in[126]
  PIN rw0_wd_in[127]
    DIRECTION INPUT ;
    USE SIGNAL ;
    SHAPE ABUTMENT ;
    PORT
      LAYER met3 ;
      RECT 0.000 870.930 0.900 871.230 ;
    END
  END rw0_wd_in[127]
  PIN rw0_wd_in[128]
    DIRECTION INPUT ;
    USE SIGNAL ;
    SHAPE ABUTMENT ;
    PORT
      LAYER met3 ;
      RECT 468.300 439.130 469.200 439.430 ;
    END
  END rw0_wd_in[128]
  PIN rw0_wd_in[129]
    DIRECTION INPUT ;
    USE SIGNAL ;
    SHAPE ABUTMENT ;
    PORT
      LAYER met3 ;
      RECT 468.300 442.530 469.200 442.830 ;
    END
  END rw0_wd_in[129]
  PIN rw0_wd_in[130]
    DIRECTION INPUT ;
    USE SIGNAL ;
    SHAPE ABUTMENT ;
    PORT
      LAYER met3 ;
      RECT 468.300 445.930 469.200 446.230 ;
    END
  END rw0_wd_in[130]
  PIN rw0_wd_in[131]
    DIRECTION INPUT ;
    USE SIGNAL ;
    SHAPE ABUTMENT ;
    PORT
      LAYER met3 ;
      RECT 468.300 449.330 469.200 449.630 ;
    END
  END rw0_wd_in[131]
  PIN rw0_wd_in[132]
    DIRECTION INPUT ;
    USE SIGNAL ;
    SHAPE ABUTMENT ;
    PORT
      LAYER met3 ;
      RECT 468.300 452.730 469.200 453.030 ;
    END
  END rw0_wd_in[132]
  PIN rw0_wd_in[133]
    DIRECTION INPUT ;
    USE SIGNAL ;
    SHAPE ABUTMENT ;
    PORT
      LAYER met3 ;
      RECT 468.300 456.130 469.200 456.430 ;
    END
  END rw0_wd_in[133]
  PIN rw0_wd_in[134]
    DIRECTION INPUT ;
    USE SIGNAL ;
    SHAPE ABUTMENT ;
    PORT
      LAYER met3 ;
      RECT 468.300 459.530 469.200 459.830 ;
    END
  END rw0_wd_in[134]
  PIN rw0_wd_in[135]
    DIRECTION INPUT ;
    USE SIGNAL ;
    SHAPE ABUTMENT ;
    PORT
      LAYER met3 ;
      RECT 468.300 462.930 469.200 463.230 ;
    END
  END rw0_wd_in[135]
  PIN rw0_wd_in[136]
    DIRECTION INPUT ;
    USE SIGNAL ;
    SHAPE ABUTMENT ;
    PORT
      LAYER met3 ;
      RECT 468.300 466.330 469.200 466.630 ;
    END
  END rw0_wd_in[136]
  PIN rw0_wd_in[137]
    DIRECTION INPUT ;
    USE SIGNAL ;
    SHAPE ABUTMENT ;
    PORT
      LAYER met3 ;
      RECT 468.300 469.730 469.200 470.030 ;
    END
  END rw0_wd_in[137]
  PIN rw0_wd_in[138]
    DIRECTION INPUT ;
    USE SIGNAL ;
    SHAPE ABUTMENT ;
    PORT
      LAYER met3 ;
      RECT 468.300 473.130 469.200 473.430 ;
    END
  END rw0_wd_in[138]
  PIN rw0_wd_in[139]
    DIRECTION INPUT ;
    USE SIGNAL ;
    SHAPE ABUTMENT ;
    PORT
      LAYER met3 ;
      RECT 468.300 476.530 469.200 476.830 ;
    END
  END rw0_wd_in[139]
  PIN rw0_wd_in[140]
    DIRECTION INPUT ;
    USE SIGNAL ;
    SHAPE ABUTMENT ;
    PORT
      LAYER met3 ;
      RECT 468.300 479.930 469.200 480.230 ;
    END
  END rw0_wd_in[140]
  PIN rw0_wd_in[141]
    DIRECTION INPUT ;
    USE SIGNAL ;
    SHAPE ABUTMENT ;
    PORT
      LAYER met3 ;
      RECT 468.300 483.330 469.200 483.630 ;
    END
  END rw0_wd_in[141]
  PIN rw0_wd_in[142]
    DIRECTION INPUT ;
    USE SIGNAL ;
    SHAPE ABUTMENT ;
    PORT
      LAYER met3 ;
      RECT 468.300 486.730 469.200 487.030 ;
    END
  END rw0_wd_in[142]
  PIN rw0_wd_in[143]
    DIRECTION INPUT ;
    USE SIGNAL ;
    SHAPE ABUTMENT ;
    PORT
      LAYER met3 ;
      RECT 468.300 490.130 469.200 490.430 ;
    END
  END rw0_wd_in[143]
  PIN rw0_wd_in[144]
    DIRECTION INPUT ;
    USE SIGNAL ;
    SHAPE ABUTMENT ;
    PORT
      LAYER met3 ;
      RECT 468.300 493.530 469.200 493.830 ;
    END
  END rw0_wd_in[144]
  PIN rw0_wd_in[145]
    DIRECTION INPUT ;
    USE SIGNAL ;
    SHAPE ABUTMENT ;
    PORT
      LAYER met3 ;
      RECT 468.300 496.930 469.200 497.230 ;
    END
  END rw0_wd_in[145]
  PIN rw0_wd_in[146]
    DIRECTION INPUT ;
    USE SIGNAL ;
    SHAPE ABUTMENT ;
    PORT
      LAYER met3 ;
      RECT 468.300 500.330 469.200 500.630 ;
    END
  END rw0_wd_in[146]
  PIN rw0_wd_in[147]
    DIRECTION INPUT ;
    USE SIGNAL ;
    SHAPE ABUTMENT ;
    PORT
      LAYER met3 ;
      RECT 468.300 503.730 469.200 504.030 ;
    END
  END rw0_wd_in[147]
  PIN rw0_wd_in[148]
    DIRECTION INPUT ;
    USE SIGNAL ;
    SHAPE ABUTMENT ;
    PORT
      LAYER met3 ;
      RECT 468.300 507.130 469.200 507.430 ;
    END
  END rw0_wd_in[148]
  PIN rw0_wd_in[149]
    DIRECTION INPUT ;
    USE SIGNAL ;
    SHAPE ABUTMENT ;
    PORT
      LAYER met3 ;
      RECT 468.300 510.530 469.200 510.830 ;
    END
  END rw0_wd_in[149]
  PIN rw0_wd_in[150]
    DIRECTION INPUT ;
    USE SIGNAL ;
    SHAPE ABUTMENT ;
    PORT
      LAYER met3 ;
      RECT 468.300 513.930 469.200 514.230 ;
    END
  END rw0_wd_in[150]
  PIN rw0_wd_in[151]
    DIRECTION INPUT ;
    USE SIGNAL ;
    SHAPE ABUTMENT ;
    PORT
      LAYER met3 ;
      RECT 468.300 517.330 469.200 517.630 ;
    END
  END rw0_wd_in[151]
  PIN rw0_wd_in[152]
    DIRECTION INPUT ;
    USE SIGNAL ;
    SHAPE ABUTMENT ;
    PORT
      LAYER met3 ;
      RECT 468.300 520.730 469.200 521.030 ;
    END
  END rw0_wd_in[152]
  PIN rw0_wd_in[153]
    DIRECTION INPUT ;
    USE SIGNAL ;
    SHAPE ABUTMENT ;
    PORT
      LAYER met3 ;
      RECT 468.300 524.130 469.200 524.430 ;
    END
  END rw0_wd_in[153]
  PIN rw0_wd_in[154]
    DIRECTION INPUT ;
    USE SIGNAL ;
    SHAPE ABUTMENT ;
    PORT
      LAYER met3 ;
      RECT 468.300 527.530 469.200 527.830 ;
    END
  END rw0_wd_in[154]
  PIN rw0_wd_in[155]
    DIRECTION INPUT ;
    USE SIGNAL ;
    SHAPE ABUTMENT ;
    PORT
      LAYER met3 ;
      RECT 468.300 530.930 469.200 531.230 ;
    END
  END rw0_wd_in[155]
  PIN rw0_wd_in[156]
    DIRECTION INPUT ;
    USE SIGNAL ;
    SHAPE ABUTMENT ;
    PORT
      LAYER met3 ;
      RECT 468.300 534.330 469.200 534.630 ;
    END
  END rw0_wd_in[156]
  PIN rw0_wd_in[157]
    DIRECTION INPUT ;
    USE SIGNAL ;
    SHAPE ABUTMENT ;
    PORT
      LAYER met3 ;
      RECT 468.300 537.730 469.200 538.030 ;
    END
  END rw0_wd_in[157]
  PIN rw0_wd_in[158]
    DIRECTION INPUT ;
    USE SIGNAL ;
    SHAPE ABUTMENT ;
    PORT
      LAYER met3 ;
      RECT 468.300 541.130 469.200 541.430 ;
    END
  END rw0_wd_in[158]
  PIN rw0_wd_in[159]
    DIRECTION INPUT ;
    USE SIGNAL ;
    SHAPE ABUTMENT ;
    PORT
      LAYER met3 ;
      RECT 468.300 544.530 469.200 544.830 ;
    END
  END rw0_wd_in[159]
  PIN rw0_wd_in[160]
    DIRECTION INPUT ;
    USE SIGNAL ;
    SHAPE ABUTMENT ;
    PORT
      LAYER met3 ;
      RECT 468.300 547.930 469.200 548.230 ;
    END
  END rw0_wd_in[160]
  PIN rw0_wd_in[161]
    DIRECTION INPUT ;
    USE SIGNAL ;
    SHAPE ABUTMENT ;
    PORT
      LAYER met3 ;
      RECT 468.300 551.330 469.200 551.630 ;
    END
  END rw0_wd_in[161]
  PIN rw0_wd_in[162]
    DIRECTION INPUT ;
    USE SIGNAL ;
    SHAPE ABUTMENT ;
    PORT
      LAYER met3 ;
      RECT 468.300 554.730 469.200 555.030 ;
    END
  END rw0_wd_in[162]
  PIN rw0_wd_in[163]
    DIRECTION INPUT ;
    USE SIGNAL ;
    SHAPE ABUTMENT ;
    PORT
      LAYER met3 ;
      RECT 468.300 558.130 469.200 558.430 ;
    END
  END rw0_wd_in[163]
  PIN rw0_wd_in[164]
    DIRECTION INPUT ;
    USE SIGNAL ;
    SHAPE ABUTMENT ;
    PORT
      LAYER met3 ;
      RECT 468.300 561.530 469.200 561.830 ;
    END
  END rw0_wd_in[164]
  PIN rw0_wd_in[165]
    DIRECTION INPUT ;
    USE SIGNAL ;
    SHAPE ABUTMENT ;
    PORT
      LAYER met3 ;
      RECT 468.300 564.930 469.200 565.230 ;
    END
  END rw0_wd_in[165]
  PIN rw0_wd_in[166]
    DIRECTION INPUT ;
    USE SIGNAL ;
    SHAPE ABUTMENT ;
    PORT
      LAYER met3 ;
      RECT 468.300 568.330 469.200 568.630 ;
    END
  END rw0_wd_in[166]
  PIN rw0_wd_in[167]
    DIRECTION INPUT ;
    USE SIGNAL ;
    SHAPE ABUTMENT ;
    PORT
      LAYER met3 ;
      RECT 468.300 571.730 469.200 572.030 ;
    END
  END rw0_wd_in[167]
  PIN rw0_wd_in[168]
    DIRECTION INPUT ;
    USE SIGNAL ;
    SHAPE ABUTMENT ;
    PORT
      LAYER met3 ;
      RECT 468.300 575.130 469.200 575.430 ;
    END
  END rw0_wd_in[168]
  PIN rw0_wd_in[169]
    DIRECTION INPUT ;
    USE SIGNAL ;
    SHAPE ABUTMENT ;
    PORT
      LAYER met3 ;
      RECT 468.300 578.530 469.200 578.830 ;
    END
  END rw0_wd_in[169]
  PIN rw0_wd_in[170]
    DIRECTION INPUT ;
    USE SIGNAL ;
    SHAPE ABUTMENT ;
    PORT
      LAYER met3 ;
      RECT 468.300 581.930 469.200 582.230 ;
    END
  END rw0_wd_in[170]
  PIN rw0_wd_in[171]
    DIRECTION INPUT ;
    USE SIGNAL ;
    SHAPE ABUTMENT ;
    PORT
      LAYER met3 ;
      RECT 468.300 585.330 469.200 585.630 ;
    END
  END rw0_wd_in[171]
  PIN rw0_wd_in[172]
    DIRECTION INPUT ;
    USE SIGNAL ;
    SHAPE ABUTMENT ;
    PORT
      LAYER met3 ;
      RECT 468.300 588.730 469.200 589.030 ;
    END
  END rw0_wd_in[172]
  PIN rw0_wd_in[173]
    DIRECTION INPUT ;
    USE SIGNAL ;
    SHAPE ABUTMENT ;
    PORT
      LAYER met3 ;
      RECT 468.300 592.130 469.200 592.430 ;
    END
  END rw0_wd_in[173]
  PIN rw0_wd_in[174]
    DIRECTION INPUT ;
    USE SIGNAL ;
    SHAPE ABUTMENT ;
    PORT
      LAYER met3 ;
      RECT 468.300 595.530 469.200 595.830 ;
    END
  END rw0_wd_in[174]
  PIN rw0_wd_in[175]
    DIRECTION INPUT ;
    USE SIGNAL ;
    SHAPE ABUTMENT ;
    PORT
      LAYER met3 ;
      RECT 468.300 598.930 469.200 599.230 ;
    END
  END rw0_wd_in[175]
  PIN rw0_wd_in[176]
    DIRECTION INPUT ;
    USE SIGNAL ;
    SHAPE ABUTMENT ;
    PORT
      LAYER met3 ;
      RECT 468.300 602.330 469.200 602.630 ;
    END
  END rw0_wd_in[176]
  PIN rw0_wd_in[177]
    DIRECTION INPUT ;
    USE SIGNAL ;
    SHAPE ABUTMENT ;
    PORT
      LAYER met3 ;
      RECT 468.300 605.730 469.200 606.030 ;
    END
  END rw0_wd_in[177]
  PIN rw0_wd_in[178]
    DIRECTION INPUT ;
    USE SIGNAL ;
    SHAPE ABUTMENT ;
    PORT
      LAYER met3 ;
      RECT 468.300 609.130 469.200 609.430 ;
    END
  END rw0_wd_in[178]
  PIN rw0_wd_in[179]
    DIRECTION INPUT ;
    USE SIGNAL ;
    SHAPE ABUTMENT ;
    PORT
      LAYER met3 ;
      RECT 468.300 612.530 469.200 612.830 ;
    END
  END rw0_wd_in[179]
  PIN rw0_wd_in[180]
    DIRECTION INPUT ;
    USE SIGNAL ;
    SHAPE ABUTMENT ;
    PORT
      LAYER met3 ;
      RECT 468.300 615.930 469.200 616.230 ;
    END
  END rw0_wd_in[180]
  PIN rw0_wd_in[181]
    DIRECTION INPUT ;
    USE SIGNAL ;
    SHAPE ABUTMENT ;
    PORT
      LAYER met3 ;
      RECT 468.300 619.330 469.200 619.630 ;
    END
  END rw0_wd_in[181]
  PIN rw0_wd_in[182]
    DIRECTION INPUT ;
    USE SIGNAL ;
    SHAPE ABUTMENT ;
    PORT
      LAYER met3 ;
      RECT 468.300 622.730 469.200 623.030 ;
    END
  END rw0_wd_in[182]
  PIN rw0_wd_in[183]
    DIRECTION INPUT ;
    USE SIGNAL ;
    SHAPE ABUTMENT ;
    PORT
      LAYER met3 ;
      RECT 468.300 626.130 469.200 626.430 ;
    END
  END rw0_wd_in[183]
  PIN rw0_wd_in[184]
    DIRECTION INPUT ;
    USE SIGNAL ;
    SHAPE ABUTMENT ;
    PORT
      LAYER met3 ;
      RECT 468.300 629.530 469.200 629.830 ;
    END
  END rw0_wd_in[184]
  PIN rw0_wd_in[185]
    DIRECTION INPUT ;
    USE SIGNAL ;
    SHAPE ABUTMENT ;
    PORT
      LAYER met3 ;
      RECT 468.300 632.930 469.200 633.230 ;
    END
  END rw0_wd_in[185]
  PIN rw0_wd_in[186]
    DIRECTION INPUT ;
    USE SIGNAL ;
    SHAPE ABUTMENT ;
    PORT
      LAYER met3 ;
      RECT 468.300 636.330 469.200 636.630 ;
    END
  END rw0_wd_in[186]
  PIN rw0_wd_in[187]
    DIRECTION INPUT ;
    USE SIGNAL ;
    SHAPE ABUTMENT ;
    PORT
      LAYER met3 ;
      RECT 468.300 639.730 469.200 640.030 ;
    END
  END rw0_wd_in[187]
  PIN rw0_wd_in[188]
    DIRECTION INPUT ;
    USE SIGNAL ;
    SHAPE ABUTMENT ;
    PORT
      LAYER met3 ;
      RECT 468.300 643.130 469.200 643.430 ;
    END
  END rw0_wd_in[188]
  PIN rw0_wd_in[189]
    DIRECTION INPUT ;
    USE SIGNAL ;
    SHAPE ABUTMENT ;
    PORT
      LAYER met3 ;
      RECT 468.300 646.530 469.200 646.830 ;
    END
  END rw0_wd_in[189]
  PIN rw0_wd_in[190]
    DIRECTION INPUT ;
    USE SIGNAL ;
    SHAPE ABUTMENT ;
    PORT
      LAYER met3 ;
      RECT 468.300 649.930 469.200 650.230 ;
    END
  END rw0_wd_in[190]
  PIN rw0_wd_in[191]
    DIRECTION INPUT ;
    USE SIGNAL ;
    SHAPE ABUTMENT ;
    PORT
      LAYER met3 ;
      RECT 468.300 653.330 469.200 653.630 ;
    END
  END rw0_wd_in[191]
  PIN rw0_wd_in[192]
    DIRECTION INPUT ;
    USE SIGNAL ;
    SHAPE ABUTMENT ;
    PORT
      LAYER met3 ;
      RECT 468.300 656.730 469.200 657.030 ;
    END
  END rw0_wd_in[192]
  PIN rw0_wd_in[193]
    DIRECTION INPUT ;
    USE SIGNAL ;
    SHAPE ABUTMENT ;
    PORT
      LAYER met3 ;
      RECT 468.300 660.130 469.200 660.430 ;
    END
  END rw0_wd_in[193]
  PIN rw0_wd_in[194]
    DIRECTION INPUT ;
    USE SIGNAL ;
    SHAPE ABUTMENT ;
    PORT
      LAYER met3 ;
      RECT 468.300 663.530 469.200 663.830 ;
    END
  END rw0_wd_in[194]
  PIN rw0_wd_in[195]
    DIRECTION INPUT ;
    USE SIGNAL ;
    SHAPE ABUTMENT ;
    PORT
      LAYER met3 ;
      RECT 468.300 666.930 469.200 667.230 ;
    END
  END rw0_wd_in[195]
  PIN rw0_wd_in[196]
    DIRECTION INPUT ;
    USE SIGNAL ;
    SHAPE ABUTMENT ;
    PORT
      LAYER met3 ;
      RECT 468.300 670.330 469.200 670.630 ;
    END
  END rw0_wd_in[196]
  PIN rw0_wd_in[197]
    DIRECTION INPUT ;
    USE SIGNAL ;
    SHAPE ABUTMENT ;
    PORT
      LAYER met3 ;
      RECT 468.300 673.730 469.200 674.030 ;
    END
  END rw0_wd_in[197]
  PIN rw0_wd_in[198]
    DIRECTION INPUT ;
    USE SIGNAL ;
    SHAPE ABUTMENT ;
    PORT
      LAYER met3 ;
      RECT 468.300 677.130 469.200 677.430 ;
    END
  END rw0_wd_in[198]
  PIN rw0_wd_in[199]
    DIRECTION INPUT ;
    USE SIGNAL ;
    SHAPE ABUTMENT ;
    PORT
      LAYER met3 ;
      RECT 468.300 680.530 469.200 680.830 ;
    END
  END rw0_wd_in[199]
  PIN rw0_wd_in[200]
    DIRECTION INPUT ;
    USE SIGNAL ;
    SHAPE ABUTMENT ;
    PORT
      LAYER met3 ;
      RECT 468.300 683.930 469.200 684.230 ;
    END
  END rw0_wd_in[200]
  PIN rw0_wd_in[201]
    DIRECTION INPUT ;
    USE SIGNAL ;
    SHAPE ABUTMENT ;
    PORT
      LAYER met3 ;
      RECT 468.300 687.330 469.200 687.630 ;
    END
  END rw0_wd_in[201]
  PIN rw0_wd_in[202]
    DIRECTION INPUT ;
    USE SIGNAL ;
    SHAPE ABUTMENT ;
    PORT
      LAYER met3 ;
      RECT 468.300 690.730 469.200 691.030 ;
    END
  END rw0_wd_in[202]
  PIN rw0_wd_in[203]
    DIRECTION INPUT ;
    USE SIGNAL ;
    SHAPE ABUTMENT ;
    PORT
      LAYER met3 ;
      RECT 468.300 694.130 469.200 694.430 ;
    END
  END rw0_wd_in[203]
  PIN rw0_wd_in[204]
    DIRECTION INPUT ;
    USE SIGNAL ;
    SHAPE ABUTMENT ;
    PORT
      LAYER met3 ;
      RECT 468.300 697.530 469.200 697.830 ;
    END
  END rw0_wd_in[204]
  PIN rw0_wd_in[205]
    DIRECTION INPUT ;
    USE SIGNAL ;
    SHAPE ABUTMENT ;
    PORT
      LAYER met3 ;
      RECT 468.300 700.930 469.200 701.230 ;
    END
  END rw0_wd_in[205]
  PIN rw0_wd_in[206]
    DIRECTION INPUT ;
    USE SIGNAL ;
    SHAPE ABUTMENT ;
    PORT
      LAYER met3 ;
      RECT 468.300 704.330 469.200 704.630 ;
    END
  END rw0_wd_in[206]
  PIN rw0_wd_in[207]
    DIRECTION INPUT ;
    USE SIGNAL ;
    SHAPE ABUTMENT ;
    PORT
      LAYER met3 ;
      RECT 468.300 707.730 469.200 708.030 ;
    END
  END rw0_wd_in[207]
  PIN rw0_wd_in[208]
    DIRECTION INPUT ;
    USE SIGNAL ;
    SHAPE ABUTMENT ;
    PORT
      LAYER met3 ;
      RECT 468.300 711.130 469.200 711.430 ;
    END
  END rw0_wd_in[208]
  PIN rw0_wd_in[209]
    DIRECTION INPUT ;
    USE SIGNAL ;
    SHAPE ABUTMENT ;
    PORT
      LAYER met3 ;
      RECT 468.300 714.530 469.200 714.830 ;
    END
  END rw0_wd_in[209]
  PIN rw0_wd_in[210]
    DIRECTION INPUT ;
    USE SIGNAL ;
    SHAPE ABUTMENT ;
    PORT
      LAYER met3 ;
      RECT 468.300 717.930 469.200 718.230 ;
    END
  END rw0_wd_in[210]
  PIN rw0_wd_in[211]
    DIRECTION INPUT ;
    USE SIGNAL ;
    SHAPE ABUTMENT ;
    PORT
      LAYER met3 ;
      RECT 468.300 721.330 469.200 721.630 ;
    END
  END rw0_wd_in[211]
  PIN rw0_wd_in[212]
    DIRECTION INPUT ;
    USE SIGNAL ;
    SHAPE ABUTMENT ;
    PORT
      LAYER met3 ;
      RECT 468.300 724.730 469.200 725.030 ;
    END
  END rw0_wd_in[212]
  PIN rw0_wd_in[213]
    DIRECTION INPUT ;
    USE SIGNAL ;
    SHAPE ABUTMENT ;
    PORT
      LAYER met3 ;
      RECT 468.300 728.130 469.200 728.430 ;
    END
  END rw0_wd_in[213]
  PIN rw0_wd_in[214]
    DIRECTION INPUT ;
    USE SIGNAL ;
    SHAPE ABUTMENT ;
    PORT
      LAYER met3 ;
      RECT 468.300 731.530 469.200 731.830 ;
    END
  END rw0_wd_in[214]
  PIN rw0_wd_in[215]
    DIRECTION INPUT ;
    USE SIGNAL ;
    SHAPE ABUTMENT ;
    PORT
      LAYER met3 ;
      RECT 468.300 734.930 469.200 735.230 ;
    END
  END rw0_wd_in[215]
  PIN rw0_wd_in[216]
    DIRECTION INPUT ;
    USE SIGNAL ;
    SHAPE ABUTMENT ;
    PORT
      LAYER met3 ;
      RECT 468.300 738.330 469.200 738.630 ;
    END
  END rw0_wd_in[216]
  PIN rw0_wd_in[217]
    DIRECTION INPUT ;
    USE SIGNAL ;
    SHAPE ABUTMENT ;
    PORT
      LAYER met3 ;
      RECT 468.300 741.730 469.200 742.030 ;
    END
  END rw0_wd_in[217]
  PIN rw0_wd_in[218]
    DIRECTION INPUT ;
    USE SIGNAL ;
    SHAPE ABUTMENT ;
    PORT
      LAYER met3 ;
      RECT 468.300 745.130 469.200 745.430 ;
    END
  END rw0_wd_in[218]
  PIN rw0_wd_in[219]
    DIRECTION INPUT ;
    USE SIGNAL ;
    SHAPE ABUTMENT ;
    PORT
      LAYER met3 ;
      RECT 468.300 748.530 469.200 748.830 ;
    END
  END rw0_wd_in[219]
  PIN rw0_wd_in[220]
    DIRECTION INPUT ;
    USE SIGNAL ;
    SHAPE ABUTMENT ;
    PORT
      LAYER met3 ;
      RECT 468.300 751.930 469.200 752.230 ;
    END
  END rw0_wd_in[220]
  PIN rw0_wd_in[221]
    DIRECTION INPUT ;
    USE SIGNAL ;
    SHAPE ABUTMENT ;
    PORT
      LAYER met3 ;
      RECT 468.300 755.330 469.200 755.630 ;
    END
  END rw0_wd_in[221]
  PIN rw0_wd_in[222]
    DIRECTION INPUT ;
    USE SIGNAL ;
    SHAPE ABUTMENT ;
    PORT
      LAYER met3 ;
      RECT 468.300 758.730 469.200 759.030 ;
    END
  END rw0_wd_in[222]
  PIN rw0_wd_in[223]
    DIRECTION INPUT ;
    USE SIGNAL ;
    SHAPE ABUTMENT ;
    PORT
      LAYER met3 ;
      RECT 468.300 762.130 469.200 762.430 ;
    END
  END rw0_wd_in[223]
  PIN rw0_wd_in[224]
    DIRECTION INPUT ;
    USE SIGNAL ;
    SHAPE ABUTMENT ;
    PORT
      LAYER met3 ;
      RECT 468.300 765.530 469.200 765.830 ;
    END
  END rw0_wd_in[224]
  PIN rw0_wd_in[225]
    DIRECTION INPUT ;
    USE SIGNAL ;
    SHAPE ABUTMENT ;
    PORT
      LAYER met3 ;
      RECT 468.300 768.930 469.200 769.230 ;
    END
  END rw0_wd_in[225]
  PIN rw0_wd_in[226]
    DIRECTION INPUT ;
    USE SIGNAL ;
    SHAPE ABUTMENT ;
    PORT
      LAYER met3 ;
      RECT 468.300 772.330 469.200 772.630 ;
    END
  END rw0_wd_in[226]
  PIN rw0_wd_in[227]
    DIRECTION INPUT ;
    USE SIGNAL ;
    SHAPE ABUTMENT ;
    PORT
      LAYER met3 ;
      RECT 468.300 775.730 469.200 776.030 ;
    END
  END rw0_wd_in[227]
  PIN rw0_wd_in[228]
    DIRECTION INPUT ;
    USE SIGNAL ;
    SHAPE ABUTMENT ;
    PORT
      LAYER met3 ;
      RECT 468.300 779.130 469.200 779.430 ;
    END
  END rw0_wd_in[228]
  PIN rw0_wd_in[229]
    DIRECTION INPUT ;
    USE SIGNAL ;
    SHAPE ABUTMENT ;
    PORT
      LAYER met3 ;
      RECT 468.300 782.530 469.200 782.830 ;
    END
  END rw0_wd_in[229]
  PIN rw0_wd_in[230]
    DIRECTION INPUT ;
    USE SIGNAL ;
    SHAPE ABUTMENT ;
    PORT
      LAYER met3 ;
      RECT 468.300 785.930 469.200 786.230 ;
    END
  END rw0_wd_in[230]
  PIN rw0_wd_in[231]
    DIRECTION INPUT ;
    USE SIGNAL ;
    SHAPE ABUTMENT ;
    PORT
      LAYER met3 ;
      RECT 468.300 789.330 469.200 789.630 ;
    END
  END rw0_wd_in[231]
  PIN rw0_wd_in[232]
    DIRECTION INPUT ;
    USE SIGNAL ;
    SHAPE ABUTMENT ;
    PORT
      LAYER met3 ;
      RECT 468.300 792.730 469.200 793.030 ;
    END
  END rw0_wd_in[232]
  PIN rw0_wd_in[233]
    DIRECTION INPUT ;
    USE SIGNAL ;
    SHAPE ABUTMENT ;
    PORT
      LAYER met3 ;
      RECT 468.300 796.130 469.200 796.430 ;
    END
  END rw0_wd_in[233]
  PIN rw0_wd_in[234]
    DIRECTION INPUT ;
    USE SIGNAL ;
    SHAPE ABUTMENT ;
    PORT
      LAYER met3 ;
      RECT 468.300 799.530 469.200 799.830 ;
    END
  END rw0_wd_in[234]
  PIN rw0_wd_in[235]
    DIRECTION INPUT ;
    USE SIGNAL ;
    SHAPE ABUTMENT ;
    PORT
      LAYER met3 ;
      RECT 468.300 802.930 469.200 803.230 ;
    END
  END rw0_wd_in[235]
  PIN rw0_wd_in[236]
    DIRECTION INPUT ;
    USE SIGNAL ;
    SHAPE ABUTMENT ;
    PORT
      LAYER met3 ;
      RECT 468.300 806.330 469.200 806.630 ;
    END
  END rw0_wd_in[236]
  PIN rw0_wd_in[237]
    DIRECTION INPUT ;
    USE SIGNAL ;
    SHAPE ABUTMENT ;
    PORT
      LAYER met3 ;
      RECT 468.300 809.730 469.200 810.030 ;
    END
  END rw0_wd_in[237]
  PIN rw0_wd_in[238]
    DIRECTION INPUT ;
    USE SIGNAL ;
    SHAPE ABUTMENT ;
    PORT
      LAYER met3 ;
      RECT 468.300 813.130 469.200 813.430 ;
    END
  END rw0_wd_in[238]
  PIN rw0_wd_in[239]
    DIRECTION INPUT ;
    USE SIGNAL ;
    SHAPE ABUTMENT ;
    PORT
      LAYER met3 ;
      RECT 468.300 816.530 469.200 816.830 ;
    END
  END rw0_wd_in[239]
  PIN rw0_wd_in[240]
    DIRECTION INPUT ;
    USE SIGNAL ;
    SHAPE ABUTMENT ;
    PORT
      LAYER met3 ;
      RECT 468.300 819.930 469.200 820.230 ;
    END
  END rw0_wd_in[240]
  PIN rw0_wd_in[241]
    DIRECTION INPUT ;
    USE SIGNAL ;
    SHAPE ABUTMENT ;
    PORT
      LAYER met3 ;
      RECT 468.300 823.330 469.200 823.630 ;
    END
  END rw0_wd_in[241]
  PIN rw0_wd_in[242]
    DIRECTION INPUT ;
    USE SIGNAL ;
    SHAPE ABUTMENT ;
    PORT
      LAYER met3 ;
      RECT 468.300 826.730 469.200 827.030 ;
    END
  END rw0_wd_in[242]
  PIN rw0_wd_in[243]
    DIRECTION INPUT ;
    USE SIGNAL ;
    SHAPE ABUTMENT ;
    PORT
      LAYER met3 ;
      RECT 468.300 830.130 469.200 830.430 ;
    END
  END rw0_wd_in[243]
  PIN rw0_wd_in[244]
    DIRECTION INPUT ;
    USE SIGNAL ;
    SHAPE ABUTMENT ;
    PORT
      LAYER met3 ;
      RECT 468.300 833.530 469.200 833.830 ;
    END
  END rw0_wd_in[244]
  PIN rw0_wd_in[245]
    DIRECTION INPUT ;
    USE SIGNAL ;
    SHAPE ABUTMENT ;
    PORT
      LAYER met3 ;
      RECT 468.300 836.930 469.200 837.230 ;
    END
  END rw0_wd_in[245]
  PIN rw0_wd_in[246]
    DIRECTION INPUT ;
    USE SIGNAL ;
    SHAPE ABUTMENT ;
    PORT
      LAYER met3 ;
      RECT 468.300 840.330 469.200 840.630 ;
    END
  END rw0_wd_in[246]
  PIN rw0_wd_in[247]
    DIRECTION INPUT ;
    USE SIGNAL ;
    SHAPE ABUTMENT ;
    PORT
      LAYER met3 ;
      RECT 468.300 843.730 469.200 844.030 ;
    END
  END rw0_wd_in[247]
  PIN rw0_wd_in[248]
    DIRECTION INPUT ;
    USE SIGNAL ;
    SHAPE ABUTMENT ;
    PORT
      LAYER met3 ;
      RECT 468.300 847.130 469.200 847.430 ;
    END
  END rw0_wd_in[248]
  PIN rw0_wd_in[249]
    DIRECTION INPUT ;
    USE SIGNAL ;
    SHAPE ABUTMENT ;
    PORT
      LAYER met3 ;
      RECT 468.300 850.530 469.200 850.830 ;
    END
  END rw0_wd_in[249]
  PIN rw0_wd_in[250]
    DIRECTION INPUT ;
    USE SIGNAL ;
    SHAPE ABUTMENT ;
    PORT
      LAYER met3 ;
      RECT 468.300 853.930 469.200 854.230 ;
    END
  END rw0_wd_in[250]
  PIN rw0_wd_in[251]
    DIRECTION INPUT ;
    USE SIGNAL ;
    SHAPE ABUTMENT ;
    PORT
      LAYER met3 ;
      RECT 468.300 857.330 469.200 857.630 ;
    END
  END rw0_wd_in[251]
  PIN rw0_wd_in[252]
    DIRECTION INPUT ;
    USE SIGNAL ;
    SHAPE ABUTMENT ;
    PORT
      LAYER met3 ;
      RECT 468.300 860.730 469.200 861.030 ;
    END
  END rw0_wd_in[252]
  PIN rw0_wd_in[253]
    DIRECTION INPUT ;
    USE SIGNAL ;
    SHAPE ABUTMENT ;
    PORT
      LAYER met3 ;
      RECT 468.300 864.130 469.200 864.430 ;
    END
  END rw0_wd_in[253]
  PIN rw0_wd_in[254]
    DIRECTION INPUT ;
    USE SIGNAL ;
    SHAPE ABUTMENT ;
    PORT
      LAYER met3 ;
      RECT 468.300 867.530 469.200 867.830 ;
    END
  END rw0_wd_in[254]
  PIN rw0_wd_in[255]
    DIRECTION INPUT ;
    USE SIGNAL ;
    SHAPE ABUTMENT ;
    PORT
      LAYER met3 ;
      RECT 468.300 870.930 469.200 871.230 ;
    END
  END rw0_wd_in[255]
  PIN rw0_wd_in[256]
    DIRECTION OUTPUT ;
    USE SIGNAL ;
    SHAPE ABUTMENT ;
    PORT
      LAYER met2 ;
      RECT 2.690 0.000 2.830 0.420 ;
    END
  END rw0_wd_in[256]
  PIN rw0_wd_in[257]
    DIRECTION OUTPUT ;
    USE SIGNAL ;
    SHAPE ABUTMENT ;
    PORT
      LAYER met2 ;
      RECT 3.150 0.000 3.290 0.420 ;
    END
  END rw0_wd_in[257]
  PIN rw0_wd_in[258]
    DIRECTION OUTPUT ;
    USE SIGNAL ;
    SHAPE ABUTMENT ;
    PORT
      LAYER met2 ;
      RECT 3.610 0.000 3.750 0.420 ;
    END
  END rw0_wd_in[258]
  PIN rw0_wd_in[259]
    DIRECTION OUTPUT ;
    USE SIGNAL ;
    SHAPE ABUTMENT ;
    PORT
      LAYER met2 ;
      RECT 4.070 0.000 4.210 0.420 ;
    END
  END rw0_wd_in[259]
  PIN rw0_wd_in[260]
    DIRECTION OUTPUT ;
    USE SIGNAL ;
    SHAPE ABUTMENT ;
    PORT
      LAYER met2 ;
      RECT 4.530 0.000 4.670 0.420 ;
    END
  END rw0_wd_in[260]
  PIN rw0_wd_in[261]
    DIRECTION OUTPUT ;
    USE SIGNAL ;
    SHAPE ABUTMENT ;
    PORT
      LAYER met2 ;
      RECT 4.990 0.000 5.130 0.420 ;
    END
  END rw0_wd_in[261]
  PIN rw0_wd_in[262]
    DIRECTION OUTPUT ;
    USE SIGNAL ;
    SHAPE ABUTMENT ;
    PORT
      LAYER met2 ;
      RECT 5.450 0.000 5.590 0.420 ;
    END
  END rw0_wd_in[262]
  PIN rw0_wd_in[263]
    DIRECTION OUTPUT ;
    USE SIGNAL ;
    SHAPE ABUTMENT ;
    PORT
      LAYER met2 ;
      RECT 5.910 0.000 6.050 0.420 ;
    END
  END rw0_wd_in[263]
  PIN rw0_wd_in[264]
    DIRECTION OUTPUT ;
    USE SIGNAL ;
    SHAPE ABUTMENT ;
    PORT
      LAYER met2 ;
      RECT 6.370 0.000 6.510 0.420 ;
    END
  END rw0_wd_in[264]
  PIN rw0_wd_in[265]
    DIRECTION OUTPUT ;
    USE SIGNAL ;
    SHAPE ABUTMENT ;
    PORT
      LAYER met2 ;
      RECT 6.830 0.000 6.970 0.420 ;
    END
  END rw0_wd_in[265]
  PIN rw0_wd_in[266]
    DIRECTION OUTPUT ;
    USE SIGNAL ;
    SHAPE ABUTMENT ;
    PORT
      LAYER met2 ;
      RECT 7.290 0.000 7.430 0.420 ;
    END
  END rw0_wd_in[266]
  PIN rw0_wd_in[267]
    DIRECTION OUTPUT ;
    USE SIGNAL ;
    SHAPE ABUTMENT ;
    PORT
      LAYER met2 ;
      RECT 7.750 0.000 7.890 0.420 ;
    END
  END rw0_wd_in[267]
  PIN rw0_wd_in[268]
    DIRECTION OUTPUT ;
    USE SIGNAL ;
    SHAPE ABUTMENT ;
    PORT
      LAYER met2 ;
      RECT 8.210 0.000 8.350 0.420 ;
    END
  END rw0_wd_in[268]
  PIN rw0_wd_in[269]
    DIRECTION OUTPUT ;
    USE SIGNAL ;
    SHAPE ABUTMENT ;
    PORT
      LAYER met2 ;
      RECT 8.670 0.000 8.810 0.420 ;
    END
  END rw0_wd_in[269]
  PIN rw0_wd_in[270]
    DIRECTION OUTPUT ;
    USE SIGNAL ;
    SHAPE ABUTMENT ;
    PORT
      LAYER met2 ;
      RECT 9.130 0.000 9.270 0.420 ;
    END
  END rw0_wd_in[270]
  PIN rw0_wd_in[271]
    DIRECTION OUTPUT ;
    USE SIGNAL ;
    SHAPE ABUTMENT ;
    PORT
      LAYER met2 ;
      RECT 9.590 0.000 9.730 0.420 ;
    END
  END rw0_wd_in[271]
  PIN rw0_wd_in[272]
    DIRECTION OUTPUT ;
    USE SIGNAL ;
    SHAPE ABUTMENT ;
    PORT
      LAYER met2 ;
      RECT 10.050 0.000 10.190 0.420 ;
    END
  END rw0_wd_in[272]
  PIN rw0_wd_in[273]
    DIRECTION OUTPUT ;
    USE SIGNAL ;
    SHAPE ABUTMENT ;
    PORT
      LAYER met2 ;
      RECT 10.510 0.000 10.650 0.420 ;
    END
  END rw0_wd_in[273]
  PIN rw0_wd_in[274]
    DIRECTION OUTPUT ;
    USE SIGNAL ;
    SHAPE ABUTMENT ;
    PORT
      LAYER met2 ;
      RECT 10.970 0.000 11.110 0.420 ;
    END
  END rw0_wd_in[274]
  PIN rw0_wd_in[275]
    DIRECTION OUTPUT ;
    USE SIGNAL ;
    SHAPE ABUTMENT ;
    PORT
      LAYER met2 ;
      RECT 11.430 0.000 11.570 0.420 ;
    END
  END rw0_wd_in[275]
  PIN rw0_wd_in[276]
    DIRECTION OUTPUT ;
    USE SIGNAL ;
    SHAPE ABUTMENT ;
    PORT
      LAYER met2 ;
      RECT 11.890 0.000 12.030 0.420 ;
    END
  END rw0_wd_in[276]
  PIN rw0_wd_in[277]
    DIRECTION OUTPUT ;
    USE SIGNAL ;
    SHAPE ABUTMENT ;
    PORT
      LAYER met2 ;
      RECT 12.350 0.000 12.490 0.420 ;
    END
  END rw0_wd_in[277]
  PIN rw0_wd_in[278]
    DIRECTION OUTPUT ;
    USE SIGNAL ;
    SHAPE ABUTMENT ;
    PORT
      LAYER met2 ;
      RECT 12.810 0.000 12.950 0.420 ;
    END
  END rw0_wd_in[278]
  PIN rw0_wd_in[279]
    DIRECTION OUTPUT ;
    USE SIGNAL ;
    SHAPE ABUTMENT ;
    PORT
      LAYER met2 ;
      RECT 13.270 0.000 13.410 0.420 ;
    END
  END rw0_wd_in[279]
  PIN rw0_wd_in[280]
    DIRECTION OUTPUT ;
    USE SIGNAL ;
    SHAPE ABUTMENT ;
    PORT
      LAYER met2 ;
      RECT 13.730 0.000 13.870 0.420 ;
    END
  END rw0_wd_in[280]
  PIN rw0_wd_in[281]
    DIRECTION OUTPUT ;
    USE SIGNAL ;
    SHAPE ABUTMENT ;
    PORT
      LAYER met2 ;
      RECT 14.190 0.000 14.330 0.420 ;
    END
  END rw0_wd_in[281]
  PIN rw0_wd_in[282]
    DIRECTION OUTPUT ;
    USE SIGNAL ;
    SHAPE ABUTMENT ;
    PORT
      LAYER met2 ;
      RECT 14.650 0.000 14.790 0.420 ;
    END
  END rw0_wd_in[282]
  PIN rw0_wd_in[283]
    DIRECTION OUTPUT ;
    USE SIGNAL ;
    SHAPE ABUTMENT ;
    PORT
      LAYER met2 ;
      RECT 15.110 0.000 15.250 0.420 ;
    END
  END rw0_wd_in[283]
  PIN rw0_wd_in[284]
    DIRECTION OUTPUT ;
    USE SIGNAL ;
    SHAPE ABUTMENT ;
    PORT
      LAYER met2 ;
      RECT 15.570 0.000 15.710 0.420 ;
    END
  END rw0_wd_in[284]
  PIN rw0_wd_in[285]
    DIRECTION OUTPUT ;
    USE SIGNAL ;
    SHAPE ABUTMENT ;
    PORT
      LAYER met2 ;
      RECT 16.030 0.000 16.170 0.420 ;
    END
  END rw0_wd_in[285]
  PIN rw0_wd_in[286]
    DIRECTION OUTPUT ;
    USE SIGNAL ;
    SHAPE ABUTMENT ;
    PORT
      LAYER met2 ;
      RECT 16.490 0.000 16.630 0.420 ;
    END
  END rw0_wd_in[286]
  PIN rw0_wd_in[287]
    DIRECTION OUTPUT ;
    USE SIGNAL ;
    SHAPE ABUTMENT ;
    PORT
      LAYER met2 ;
      RECT 16.950 0.000 17.090 0.420 ;
    END
  END rw0_wd_in[287]
  PIN rw0_wd_in[288]
    DIRECTION OUTPUT ;
    USE SIGNAL ;
    SHAPE ABUTMENT ;
    PORT
      LAYER met2 ;
      RECT 17.410 0.000 17.550 0.420 ;
    END
  END rw0_wd_in[288]
  PIN rw0_wd_in[289]
    DIRECTION OUTPUT ;
    USE SIGNAL ;
    SHAPE ABUTMENT ;
    PORT
      LAYER met2 ;
      RECT 17.870 0.000 18.010 0.420 ;
    END
  END rw0_wd_in[289]
  PIN rw0_wd_in[290]
    DIRECTION OUTPUT ;
    USE SIGNAL ;
    SHAPE ABUTMENT ;
    PORT
      LAYER met2 ;
      RECT 18.330 0.000 18.470 0.420 ;
    END
  END rw0_wd_in[290]
  PIN rw0_wd_in[291]
    DIRECTION OUTPUT ;
    USE SIGNAL ;
    SHAPE ABUTMENT ;
    PORT
      LAYER met2 ;
      RECT 18.790 0.000 18.930 0.420 ;
    END
  END rw0_wd_in[291]
  PIN rw0_wd_in[292]
    DIRECTION OUTPUT ;
    USE SIGNAL ;
    SHAPE ABUTMENT ;
    PORT
      LAYER met2 ;
      RECT 19.250 0.000 19.390 0.420 ;
    END
  END rw0_wd_in[292]
  PIN rw0_wd_in[293]
    DIRECTION OUTPUT ;
    USE SIGNAL ;
    SHAPE ABUTMENT ;
    PORT
      LAYER met2 ;
      RECT 19.710 0.000 19.850 0.420 ;
    END
  END rw0_wd_in[293]
  PIN rw0_wd_in[294]
    DIRECTION OUTPUT ;
    USE SIGNAL ;
    SHAPE ABUTMENT ;
    PORT
      LAYER met2 ;
      RECT 20.170 0.000 20.310 0.420 ;
    END
  END rw0_wd_in[294]
  PIN rw0_wd_in[295]
    DIRECTION OUTPUT ;
    USE SIGNAL ;
    SHAPE ABUTMENT ;
    PORT
      LAYER met2 ;
      RECT 20.630 0.000 20.770 0.420 ;
    END
  END rw0_wd_in[295]
  PIN rw0_wd_in[296]
    DIRECTION OUTPUT ;
    USE SIGNAL ;
    SHAPE ABUTMENT ;
    PORT
      LAYER met2 ;
      RECT 21.090 0.000 21.230 0.420 ;
    END
  END rw0_wd_in[296]
  PIN rw0_wd_in[297]
    DIRECTION OUTPUT ;
    USE SIGNAL ;
    SHAPE ABUTMENT ;
    PORT
      LAYER met2 ;
      RECT 21.550 0.000 21.690 0.420 ;
    END
  END rw0_wd_in[297]
  PIN rw0_wd_in[298]
    DIRECTION OUTPUT ;
    USE SIGNAL ;
    SHAPE ABUTMENT ;
    PORT
      LAYER met2 ;
      RECT 22.010 0.000 22.150 0.420 ;
    END
  END rw0_wd_in[298]
  PIN rw0_wd_in[299]
    DIRECTION OUTPUT ;
    USE SIGNAL ;
    SHAPE ABUTMENT ;
    PORT
      LAYER met2 ;
      RECT 22.470 0.000 22.610 0.420 ;
    END
  END rw0_wd_in[299]
  PIN rw0_wd_in[300]
    DIRECTION OUTPUT ;
    USE SIGNAL ;
    SHAPE ABUTMENT ;
    PORT
      LAYER met2 ;
      RECT 22.930 0.000 23.070 0.420 ;
    END
  END rw0_wd_in[300]
  PIN rw0_wd_in[301]
    DIRECTION OUTPUT ;
    USE SIGNAL ;
    SHAPE ABUTMENT ;
    PORT
      LAYER met2 ;
      RECT 23.390 0.000 23.530 0.420 ;
    END
  END rw0_wd_in[301]
  PIN rw0_wd_in[302]
    DIRECTION OUTPUT ;
    USE SIGNAL ;
    SHAPE ABUTMENT ;
    PORT
      LAYER met2 ;
      RECT 23.850 0.000 23.990 0.420 ;
    END
  END rw0_wd_in[302]
  PIN rw0_wd_in[303]
    DIRECTION OUTPUT ;
    USE SIGNAL ;
    SHAPE ABUTMENT ;
    PORT
      LAYER met2 ;
      RECT 24.310 0.000 24.450 0.420 ;
    END
  END rw0_wd_in[303]
  PIN rw0_wd_in[304]
    DIRECTION OUTPUT ;
    USE SIGNAL ;
    SHAPE ABUTMENT ;
    PORT
      LAYER met2 ;
      RECT 24.770 0.000 24.910 0.420 ;
    END
  END rw0_wd_in[304]
  PIN rw0_wd_in[305]
    DIRECTION OUTPUT ;
    USE SIGNAL ;
    SHAPE ABUTMENT ;
    PORT
      LAYER met2 ;
      RECT 25.230 0.000 25.370 0.420 ;
    END
  END rw0_wd_in[305]
  PIN rw0_wd_in[306]
    DIRECTION OUTPUT ;
    USE SIGNAL ;
    SHAPE ABUTMENT ;
    PORT
      LAYER met2 ;
      RECT 25.690 0.000 25.830 0.420 ;
    END
  END rw0_wd_in[306]
  PIN rw0_wd_in[307]
    DIRECTION OUTPUT ;
    USE SIGNAL ;
    SHAPE ABUTMENT ;
    PORT
      LAYER met2 ;
      RECT 26.150 0.000 26.290 0.420 ;
    END
  END rw0_wd_in[307]
  PIN rw0_wd_in[308]
    DIRECTION OUTPUT ;
    USE SIGNAL ;
    SHAPE ABUTMENT ;
    PORT
      LAYER met2 ;
      RECT 26.610 0.000 26.750 0.420 ;
    END
  END rw0_wd_in[308]
  PIN rw0_wd_in[309]
    DIRECTION OUTPUT ;
    USE SIGNAL ;
    SHAPE ABUTMENT ;
    PORT
      LAYER met2 ;
      RECT 27.070 0.000 27.210 0.420 ;
    END
  END rw0_wd_in[309]
  PIN rw0_wd_in[310]
    DIRECTION OUTPUT ;
    USE SIGNAL ;
    SHAPE ABUTMENT ;
    PORT
      LAYER met2 ;
      RECT 27.530 0.000 27.670 0.420 ;
    END
  END rw0_wd_in[310]
  PIN rw0_wd_in[311]
    DIRECTION OUTPUT ;
    USE SIGNAL ;
    SHAPE ABUTMENT ;
    PORT
      LAYER met2 ;
      RECT 27.990 0.000 28.130 0.420 ;
    END
  END rw0_wd_in[311]
  PIN rw0_wd_in[312]
    DIRECTION OUTPUT ;
    USE SIGNAL ;
    SHAPE ABUTMENT ;
    PORT
      LAYER met2 ;
      RECT 28.450 0.000 28.590 0.420 ;
    END
  END rw0_wd_in[312]
  PIN rw0_wd_in[313]
    DIRECTION OUTPUT ;
    USE SIGNAL ;
    SHAPE ABUTMENT ;
    PORT
      LAYER met2 ;
      RECT 28.910 0.000 29.050 0.420 ;
    END
  END rw0_wd_in[313]
  PIN rw0_wd_in[314]
    DIRECTION OUTPUT ;
    USE SIGNAL ;
    SHAPE ABUTMENT ;
    PORT
      LAYER met2 ;
      RECT 29.370 0.000 29.510 0.420 ;
    END
  END rw0_wd_in[314]
  PIN rw0_wd_in[315]
    DIRECTION OUTPUT ;
    USE SIGNAL ;
    SHAPE ABUTMENT ;
    PORT
      LAYER met2 ;
      RECT 29.830 0.000 29.970 0.420 ;
    END
  END rw0_wd_in[315]
  PIN rw0_wd_in[316]
    DIRECTION OUTPUT ;
    USE SIGNAL ;
    SHAPE ABUTMENT ;
    PORT
      LAYER met2 ;
      RECT 30.290 0.000 30.430 0.420 ;
    END
  END rw0_wd_in[316]
  PIN rw0_wd_in[317]
    DIRECTION OUTPUT ;
    USE SIGNAL ;
    SHAPE ABUTMENT ;
    PORT
      LAYER met2 ;
      RECT 30.750 0.000 30.890 0.420 ;
    END
  END rw0_wd_in[317]
  PIN rw0_wd_in[318]
    DIRECTION OUTPUT ;
    USE SIGNAL ;
    SHAPE ABUTMENT ;
    PORT
      LAYER met2 ;
      RECT 31.210 0.000 31.350 0.420 ;
    END
  END rw0_wd_in[318]
  PIN rw0_wd_in[319]
    DIRECTION OUTPUT ;
    USE SIGNAL ;
    SHAPE ABUTMENT ;
    PORT
      LAYER met2 ;
      RECT 31.670 0.000 31.810 0.420 ;
    END
  END rw0_wd_in[319]
  PIN rw0_wd_in[320]
    DIRECTION OUTPUT ;
    USE SIGNAL ;
    SHAPE ABUTMENT ;
    PORT
      LAYER met2 ;
      RECT 32.130 0.000 32.270 0.420 ;
    END
  END rw0_wd_in[320]
  PIN rw0_wd_in[321]
    DIRECTION OUTPUT ;
    USE SIGNAL ;
    SHAPE ABUTMENT ;
    PORT
      LAYER met2 ;
      RECT 32.590 0.000 32.730 0.420 ;
    END
  END rw0_wd_in[321]
  PIN rw0_wd_in[322]
    DIRECTION OUTPUT ;
    USE SIGNAL ;
    SHAPE ABUTMENT ;
    PORT
      LAYER met2 ;
      RECT 33.050 0.000 33.190 0.420 ;
    END
  END rw0_wd_in[322]
  PIN rw0_wd_in[323]
    DIRECTION OUTPUT ;
    USE SIGNAL ;
    SHAPE ABUTMENT ;
    PORT
      LAYER met2 ;
      RECT 33.510 0.000 33.650 0.420 ;
    END
  END rw0_wd_in[323]
  PIN rw0_wd_in[324]
    DIRECTION OUTPUT ;
    USE SIGNAL ;
    SHAPE ABUTMENT ;
    PORT
      LAYER met2 ;
      RECT 33.970 0.000 34.110 0.420 ;
    END
  END rw0_wd_in[324]
  PIN rw0_wd_in[325]
    DIRECTION OUTPUT ;
    USE SIGNAL ;
    SHAPE ABUTMENT ;
    PORT
      LAYER met2 ;
      RECT 34.430 0.000 34.570 0.420 ;
    END
  END rw0_wd_in[325]
  PIN rw0_wd_in[326]
    DIRECTION OUTPUT ;
    USE SIGNAL ;
    SHAPE ABUTMENT ;
    PORT
      LAYER met2 ;
      RECT 34.890 0.000 35.030 0.420 ;
    END
  END rw0_wd_in[326]
  PIN rw0_wd_in[327]
    DIRECTION OUTPUT ;
    USE SIGNAL ;
    SHAPE ABUTMENT ;
    PORT
      LAYER met2 ;
      RECT 35.350 0.000 35.490 0.420 ;
    END
  END rw0_wd_in[327]
  PIN rw0_wd_in[328]
    DIRECTION OUTPUT ;
    USE SIGNAL ;
    SHAPE ABUTMENT ;
    PORT
      LAYER met2 ;
      RECT 35.810 0.000 35.950 0.420 ;
    END
  END rw0_wd_in[328]
  PIN rw0_wd_in[329]
    DIRECTION OUTPUT ;
    USE SIGNAL ;
    SHAPE ABUTMENT ;
    PORT
      LAYER met2 ;
      RECT 36.270 0.000 36.410 0.420 ;
    END
  END rw0_wd_in[329]
  PIN rw0_wd_in[330]
    DIRECTION OUTPUT ;
    USE SIGNAL ;
    SHAPE ABUTMENT ;
    PORT
      LAYER met2 ;
      RECT 36.730 0.000 36.870 0.420 ;
    END
  END rw0_wd_in[330]
  PIN rw0_wd_in[331]
    DIRECTION OUTPUT ;
    USE SIGNAL ;
    SHAPE ABUTMENT ;
    PORT
      LAYER met2 ;
      RECT 37.190 0.000 37.330 0.420 ;
    END
  END rw0_wd_in[331]
  PIN rw0_wd_in[332]
    DIRECTION OUTPUT ;
    USE SIGNAL ;
    SHAPE ABUTMENT ;
    PORT
      LAYER met2 ;
      RECT 37.650 0.000 37.790 0.420 ;
    END
  END rw0_wd_in[332]
  PIN rw0_wd_in[333]
    DIRECTION OUTPUT ;
    USE SIGNAL ;
    SHAPE ABUTMENT ;
    PORT
      LAYER met2 ;
      RECT 38.110 0.000 38.250 0.420 ;
    END
  END rw0_wd_in[333]
  PIN rw0_wd_in[334]
    DIRECTION OUTPUT ;
    USE SIGNAL ;
    SHAPE ABUTMENT ;
    PORT
      LAYER met2 ;
      RECT 38.570 0.000 38.710 0.420 ;
    END
  END rw0_wd_in[334]
  PIN rw0_wd_in[335]
    DIRECTION OUTPUT ;
    USE SIGNAL ;
    SHAPE ABUTMENT ;
    PORT
      LAYER met2 ;
      RECT 39.030 0.000 39.170 0.420 ;
    END
  END rw0_wd_in[335]
  PIN rw0_wd_in[336]
    DIRECTION OUTPUT ;
    USE SIGNAL ;
    SHAPE ABUTMENT ;
    PORT
      LAYER met2 ;
      RECT 39.490 0.000 39.630 0.420 ;
    END
  END rw0_wd_in[336]
  PIN rw0_wd_in[337]
    DIRECTION OUTPUT ;
    USE SIGNAL ;
    SHAPE ABUTMENT ;
    PORT
      LAYER met2 ;
      RECT 39.950 0.000 40.090 0.420 ;
    END
  END rw0_wd_in[337]
  PIN rw0_wd_in[338]
    DIRECTION OUTPUT ;
    USE SIGNAL ;
    SHAPE ABUTMENT ;
    PORT
      LAYER met2 ;
      RECT 40.410 0.000 40.550 0.420 ;
    END
  END rw0_wd_in[338]
  PIN rw0_wd_in[339]
    DIRECTION OUTPUT ;
    USE SIGNAL ;
    SHAPE ABUTMENT ;
    PORT
      LAYER met2 ;
      RECT 40.870 0.000 41.010 0.420 ;
    END
  END rw0_wd_in[339]
  PIN rw0_wd_in[340]
    DIRECTION OUTPUT ;
    USE SIGNAL ;
    SHAPE ABUTMENT ;
    PORT
      LAYER met2 ;
      RECT 41.330 0.000 41.470 0.420 ;
    END
  END rw0_wd_in[340]
  PIN rw0_wd_in[341]
    DIRECTION OUTPUT ;
    USE SIGNAL ;
    SHAPE ABUTMENT ;
    PORT
      LAYER met2 ;
      RECT 41.790 0.000 41.930 0.420 ;
    END
  END rw0_wd_in[341]
  PIN rw0_wd_in[342]
    DIRECTION OUTPUT ;
    USE SIGNAL ;
    SHAPE ABUTMENT ;
    PORT
      LAYER met2 ;
      RECT 42.250 0.000 42.390 0.420 ;
    END
  END rw0_wd_in[342]
  PIN rw0_wd_in[343]
    DIRECTION OUTPUT ;
    USE SIGNAL ;
    SHAPE ABUTMENT ;
    PORT
      LAYER met2 ;
      RECT 42.710 0.000 42.850 0.420 ;
    END
  END rw0_wd_in[343]
  PIN rw0_wd_in[344]
    DIRECTION OUTPUT ;
    USE SIGNAL ;
    SHAPE ABUTMENT ;
    PORT
      LAYER met2 ;
      RECT 43.170 0.000 43.310 0.420 ;
    END
  END rw0_wd_in[344]
  PIN rw0_wd_in[345]
    DIRECTION OUTPUT ;
    USE SIGNAL ;
    SHAPE ABUTMENT ;
    PORT
      LAYER met2 ;
      RECT 43.630 0.000 43.770 0.420 ;
    END
  END rw0_wd_in[345]
  PIN rw0_wd_in[346]
    DIRECTION OUTPUT ;
    USE SIGNAL ;
    SHAPE ABUTMENT ;
    PORT
      LAYER met2 ;
      RECT 44.090 0.000 44.230 0.420 ;
    END
  END rw0_wd_in[346]
  PIN rw0_wd_in[347]
    DIRECTION OUTPUT ;
    USE SIGNAL ;
    SHAPE ABUTMENT ;
    PORT
      LAYER met2 ;
      RECT 44.550 0.000 44.690 0.420 ;
    END
  END rw0_wd_in[347]
  PIN rw0_wd_in[348]
    DIRECTION OUTPUT ;
    USE SIGNAL ;
    SHAPE ABUTMENT ;
    PORT
      LAYER met2 ;
      RECT 45.010 0.000 45.150 0.420 ;
    END
  END rw0_wd_in[348]
  PIN rw0_wd_in[349]
    DIRECTION OUTPUT ;
    USE SIGNAL ;
    SHAPE ABUTMENT ;
    PORT
      LAYER met2 ;
      RECT 45.470 0.000 45.610 0.420 ;
    END
  END rw0_wd_in[349]
  PIN rw0_wd_in[350]
    DIRECTION OUTPUT ;
    USE SIGNAL ;
    SHAPE ABUTMENT ;
    PORT
      LAYER met2 ;
      RECT 45.930 0.000 46.070 0.420 ;
    END
  END rw0_wd_in[350]
  PIN rw0_wd_in[351]
    DIRECTION OUTPUT ;
    USE SIGNAL ;
    SHAPE ABUTMENT ;
    PORT
      LAYER met2 ;
      RECT 46.390 0.000 46.530 0.420 ;
    END
  END rw0_wd_in[351]
  PIN rw0_wd_in[352]
    DIRECTION OUTPUT ;
    USE SIGNAL ;
    SHAPE ABUTMENT ;
    PORT
      LAYER met2 ;
      RECT 46.850 0.000 46.990 0.420 ;
    END
  END rw0_wd_in[352]
  PIN rw0_wd_in[353]
    DIRECTION OUTPUT ;
    USE SIGNAL ;
    SHAPE ABUTMENT ;
    PORT
      LAYER met2 ;
      RECT 47.310 0.000 47.450 0.420 ;
    END
  END rw0_wd_in[353]
  PIN rw0_wd_in[354]
    DIRECTION OUTPUT ;
    USE SIGNAL ;
    SHAPE ABUTMENT ;
    PORT
      LAYER met2 ;
      RECT 47.770 0.000 47.910 0.420 ;
    END
  END rw0_wd_in[354]
  PIN rw0_wd_in[355]
    DIRECTION OUTPUT ;
    USE SIGNAL ;
    SHAPE ABUTMENT ;
    PORT
      LAYER met2 ;
      RECT 48.230 0.000 48.370 0.420 ;
    END
  END rw0_wd_in[355]
  PIN rw0_wd_in[356]
    DIRECTION OUTPUT ;
    USE SIGNAL ;
    SHAPE ABUTMENT ;
    PORT
      LAYER met2 ;
      RECT 48.690 0.000 48.830 0.420 ;
    END
  END rw0_wd_in[356]
  PIN rw0_wd_in[357]
    DIRECTION OUTPUT ;
    USE SIGNAL ;
    SHAPE ABUTMENT ;
    PORT
      LAYER met2 ;
      RECT 49.150 0.000 49.290 0.420 ;
    END
  END rw0_wd_in[357]
  PIN rw0_wd_in[358]
    DIRECTION OUTPUT ;
    USE SIGNAL ;
    SHAPE ABUTMENT ;
    PORT
      LAYER met2 ;
      RECT 49.610 0.000 49.750 0.420 ;
    END
  END rw0_wd_in[358]
  PIN rw0_wd_in[359]
    DIRECTION OUTPUT ;
    USE SIGNAL ;
    SHAPE ABUTMENT ;
    PORT
      LAYER met2 ;
      RECT 50.070 0.000 50.210 0.420 ;
    END
  END rw0_wd_in[359]
  PIN rw0_wd_in[360]
    DIRECTION OUTPUT ;
    USE SIGNAL ;
    SHAPE ABUTMENT ;
    PORT
      LAYER met2 ;
      RECT 50.530 0.000 50.670 0.420 ;
    END
  END rw0_wd_in[360]
  PIN rw0_wd_in[361]
    DIRECTION OUTPUT ;
    USE SIGNAL ;
    SHAPE ABUTMENT ;
    PORT
      LAYER met2 ;
      RECT 50.990 0.000 51.130 0.420 ;
    END
  END rw0_wd_in[361]
  PIN rw0_wd_in[362]
    DIRECTION OUTPUT ;
    USE SIGNAL ;
    SHAPE ABUTMENT ;
    PORT
      LAYER met2 ;
      RECT 51.450 0.000 51.590 0.420 ;
    END
  END rw0_wd_in[362]
  PIN rw0_wd_in[363]
    DIRECTION OUTPUT ;
    USE SIGNAL ;
    SHAPE ABUTMENT ;
    PORT
      LAYER met2 ;
      RECT 51.910 0.000 52.050 0.420 ;
    END
  END rw0_wd_in[363]
  PIN rw0_wd_in[364]
    DIRECTION OUTPUT ;
    USE SIGNAL ;
    SHAPE ABUTMENT ;
    PORT
      LAYER met2 ;
      RECT 52.370 0.000 52.510 0.420 ;
    END
  END rw0_wd_in[364]
  PIN rw0_wd_in[365]
    DIRECTION OUTPUT ;
    USE SIGNAL ;
    SHAPE ABUTMENT ;
    PORT
      LAYER met2 ;
      RECT 52.830 0.000 52.970 0.420 ;
    END
  END rw0_wd_in[365]
  PIN rw0_wd_in[366]
    DIRECTION OUTPUT ;
    USE SIGNAL ;
    SHAPE ABUTMENT ;
    PORT
      LAYER met2 ;
      RECT 53.290 0.000 53.430 0.420 ;
    END
  END rw0_wd_in[366]
  PIN rw0_wd_in[367]
    DIRECTION OUTPUT ;
    USE SIGNAL ;
    SHAPE ABUTMENT ;
    PORT
      LAYER met2 ;
      RECT 53.750 0.000 53.890 0.420 ;
    END
  END rw0_wd_in[367]
  PIN rw0_wd_in[368]
    DIRECTION OUTPUT ;
    USE SIGNAL ;
    SHAPE ABUTMENT ;
    PORT
      LAYER met2 ;
      RECT 54.210 0.000 54.350 0.420 ;
    END
  END rw0_wd_in[368]
  PIN rw0_wd_in[369]
    DIRECTION OUTPUT ;
    USE SIGNAL ;
    SHAPE ABUTMENT ;
    PORT
      LAYER met2 ;
      RECT 54.670 0.000 54.810 0.420 ;
    END
  END rw0_wd_in[369]
  PIN rw0_wd_in[370]
    DIRECTION OUTPUT ;
    USE SIGNAL ;
    SHAPE ABUTMENT ;
    PORT
      LAYER met2 ;
      RECT 55.130 0.000 55.270 0.420 ;
    END
  END rw0_wd_in[370]
  PIN rw0_wd_in[371]
    DIRECTION OUTPUT ;
    USE SIGNAL ;
    SHAPE ABUTMENT ;
    PORT
      LAYER met2 ;
      RECT 55.590 0.000 55.730 0.420 ;
    END
  END rw0_wd_in[371]
  PIN rw0_wd_in[372]
    DIRECTION OUTPUT ;
    USE SIGNAL ;
    SHAPE ABUTMENT ;
    PORT
      LAYER met2 ;
      RECT 56.050 0.000 56.190 0.420 ;
    END
  END rw0_wd_in[372]
  PIN rw0_wd_in[373]
    DIRECTION OUTPUT ;
    USE SIGNAL ;
    SHAPE ABUTMENT ;
    PORT
      LAYER met2 ;
      RECT 56.510 0.000 56.650 0.420 ;
    END
  END rw0_wd_in[373]
  PIN rw0_wd_in[374]
    DIRECTION OUTPUT ;
    USE SIGNAL ;
    SHAPE ABUTMENT ;
    PORT
      LAYER met2 ;
      RECT 56.970 0.000 57.110 0.420 ;
    END
  END rw0_wd_in[374]
  PIN rw0_wd_in[375]
    DIRECTION OUTPUT ;
    USE SIGNAL ;
    SHAPE ABUTMENT ;
    PORT
      LAYER met2 ;
      RECT 57.430 0.000 57.570 0.420 ;
    END
  END rw0_wd_in[375]
  PIN rw0_wd_in[376]
    DIRECTION OUTPUT ;
    USE SIGNAL ;
    SHAPE ABUTMENT ;
    PORT
      LAYER met2 ;
      RECT 57.890 0.000 58.030 0.420 ;
    END
  END rw0_wd_in[376]
  PIN rw0_wd_in[377]
    DIRECTION OUTPUT ;
    USE SIGNAL ;
    SHAPE ABUTMENT ;
    PORT
      LAYER met2 ;
      RECT 58.350 0.000 58.490 0.420 ;
    END
  END rw0_wd_in[377]
  PIN rw0_wd_in[378]
    DIRECTION OUTPUT ;
    USE SIGNAL ;
    SHAPE ABUTMENT ;
    PORT
      LAYER met2 ;
      RECT 58.810 0.000 58.950 0.420 ;
    END
  END rw0_wd_in[378]
  PIN rw0_wd_in[379]
    DIRECTION OUTPUT ;
    USE SIGNAL ;
    SHAPE ABUTMENT ;
    PORT
      LAYER met2 ;
      RECT 59.270 0.000 59.410 0.420 ;
    END
  END rw0_wd_in[379]
  PIN rw0_wd_in[380]
    DIRECTION OUTPUT ;
    USE SIGNAL ;
    SHAPE ABUTMENT ;
    PORT
      LAYER met2 ;
      RECT 59.730 0.000 59.870 0.420 ;
    END
  END rw0_wd_in[380]
  PIN rw0_wd_in[381]
    DIRECTION OUTPUT ;
    USE SIGNAL ;
    SHAPE ABUTMENT ;
    PORT
      LAYER met2 ;
      RECT 60.190 0.000 60.330 0.420 ;
    END
  END rw0_wd_in[381]
  PIN rw0_wd_in[382]
    DIRECTION OUTPUT ;
    USE SIGNAL ;
    SHAPE ABUTMENT ;
    PORT
      LAYER met2 ;
      RECT 60.650 0.000 60.790 0.420 ;
    END
  END rw0_wd_in[382]
  PIN rw0_wd_in[383]
    DIRECTION OUTPUT ;
    USE SIGNAL ;
    SHAPE ABUTMENT ;
    PORT
      LAYER met2 ;
      RECT 61.110 0.000 61.250 0.420 ;
    END
  END rw0_wd_in[383]
  PIN rw0_wd_in[384]
    DIRECTION OUTPUT ;
    USE SIGNAL ;
    SHAPE ABUTMENT ;
    PORT
      LAYER met2 ;
      RECT 61.570 0.000 61.710 0.420 ;
    END
  END rw0_wd_in[384]
  PIN rw0_wd_in[385]
    DIRECTION OUTPUT ;
    USE SIGNAL ;
    SHAPE ABUTMENT ;
    PORT
      LAYER met2 ;
      RECT 62.030 0.000 62.170 0.420 ;
    END
  END rw0_wd_in[385]
  PIN rw0_wd_in[386]
    DIRECTION OUTPUT ;
    USE SIGNAL ;
    SHAPE ABUTMENT ;
    PORT
      LAYER met2 ;
      RECT 62.490 0.000 62.630 0.420 ;
    END
  END rw0_wd_in[386]
  PIN rw0_wd_in[387]
    DIRECTION OUTPUT ;
    USE SIGNAL ;
    SHAPE ABUTMENT ;
    PORT
      LAYER met2 ;
      RECT 62.950 0.000 63.090 0.420 ;
    END
  END rw0_wd_in[387]
  PIN rw0_wd_in[388]
    DIRECTION OUTPUT ;
    USE SIGNAL ;
    SHAPE ABUTMENT ;
    PORT
      LAYER met2 ;
      RECT 63.410 0.000 63.550 0.420 ;
    END
  END rw0_wd_in[388]
  PIN rw0_wd_in[389]
    DIRECTION OUTPUT ;
    USE SIGNAL ;
    SHAPE ABUTMENT ;
    PORT
      LAYER met2 ;
      RECT 63.870 0.000 64.010 0.420 ;
    END
  END rw0_wd_in[389]
  PIN rw0_wd_in[390]
    DIRECTION OUTPUT ;
    USE SIGNAL ;
    SHAPE ABUTMENT ;
    PORT
      LAYER met2 ;
      RECT 64.330 0.000 64.470 0.420 ;
    END
  END rw0_wd_in[390]
  PIN rw0_wd_in[391]
    DIRECTION OUTPUT ;
    USE SIGNAL ;
    SHAPE ABUTMENT ;
    PORT
      LAYER met2 ;
      RECT 64.790 0.000 64.930 0.420 ;
    END
  END rw0_wd_in[391]
  PIN rw0_wd_in[392]
    DIRECTION OUTPUT ;
    USE SIGNAL ;
    SHAPE ABUTMENT ;
    PORT
      LAYER met2 ;
      RECT 65.250 0.000 65.390 0.420 ;
    END
  END rw0_wd_in[392]
  PIN rw0_wd_in[393]
    DIRECTION OUTPUT ;
    USE SIGNAL ;
    SHAPE ABUTMENT ;
    PORT
      LAYER met2 ;
      RECT 65.710 0.000 65.850 0.420 ;
    END
  END rw0_wd_in[393]
  PIN rw0_wd_in[394]
    DIRECTION OUTPUT ;
    USE SIGNAL ;
    SHAPE ABUTMENT ;
    PORT
      LAYER met2 ;
      RECT 66.170 0.000 66.310 0.420 ;
    END
  END rw0_wd_in[394]
  PIN rw0_wd_in[395]
    DIRECTION OUTPUT ;
    USE SIGNAL ;
    SHAPE ABUTMENT ;
    PORT
      LAYER met2 ;
      RECT 66.630 0.000 66.770 0.420 ;
    END
  END rw0_wd_in[395]
  PIN rw0_wd_in[396]
    DIRECTION OUTPUT ;
    USE SIGNAL ;
    SHAPE ABUTMENT ;
    PORT
      LAYER met2 ;
      RECT 67.090 0.000 67.230 0.420 ;
    END
  END rw0_wd_in[396]
  PIN rw0_wd_in[397]
    DIRECTION OUTPUT ;
    USE SIGNAL ;
    SHAPE ABUTMENT ;
    PORT
      LAYER met2 ;
      RECT 67.550 0.000 67.690 0.420 ;
    END
  END rw0_wd_in[397]
  PIN rw0_wd_in[398]
    DIRECTION OUTPUT ;
    USE SIGNAL ;
    SHAPE ABUTMENT ;
    PORT
      LAYER met2 ;
      RECT 68.010 0.000 68.150 0.420 ;
    END
  END rw0_wd_in[398]
  PIN rw0_wd_in[399]
    DIRECTION OUTPUT ;
    USE SIGNAL ;
    SHAPE ABUTMENT ;
    PORT
      LAYER met2 ;
      RECT 68.470 0.000 68.610 0.420 ;
    END
  END rw0_wd_in[399]
  PIN rw0_wd_in[400]
    DIRECTION OUTPUT ;
    USE SIGNAL ;
    SHAPE ABUTMENT ;
    PORT
      LAYER met2 ;
      RECT 68.930 0.000 69.070 0.420 ;
    END
  END rw0_wd_in[400]
  PIN rw0_wd_in[401]
    DIRECTION OUTPUT ;
    USE SIGNAL ;
    SHAPE ABUTMENT ;
    PORT
      LAYER met2 ;
      RECT 69.390 0.000 69.530 0.420 ;
    END
  END rw0_wd_in[401]
  PIN rw0_wd_in[402]
    DIRECTION OUTPUT ;
    USE SIGNAL ;
    SHAPE ABUTMENT ;
    PORT
      LAYER met2 ;
      RECT 69.850 0.000 69.990 0.420 ;
    END
  END rw0_wd_in[402]
  PIN rw0_wd_in[403]
    DIRECTION OUTPUT ;
    USE SIGNAL ;
    SHAPE ABUTMENT ;
    PORT
      LAYER met2 ;
      RECT 70.310 0.000 70.450 0.420 ;
    END
  END rw0_wd_in[403]
  PIN rw0_wd_in[404]
    DIRECTION OUTPUT ;
    USE SIGNAL ;
    SHAPE ABUTMENT ;
    PORT
      LAYER met2 ;
      RECT 70.770 0.000 70.910 0.420 ;
    END
  END rw0_wd_in[404]
  PIN rw0_wd_in[405]
    DIRECTION OUTPUT ;
    USE SIGNAL ;
    SHAPE ABUTMENT ;
    PORT
      LAYER met2 ;
      RECT 71.230 0.000 71.370 0.420 ;
    END
  END rw0_wd_in[405]
  PIN rw0_wd_in[406]
    DIRECTION OUTPUT ;
    USE SIGNAL ;
    SHAPE ABUTMENT ;
    PORT
      LAYER met2 ;
      RECT 71.690 0.000 71.830 0.420 ;
    END
  END rw0_wd_in[406]
  PIN rw0_wd_in[407]
    DIRECTION OUTPUT ;
    USE SIGNAL ;
    SHAPE ABUTMENT ;
    PORT
      LAYER met2 ;
      RECT 72.150 0.000 72.290 0.420 ;
    END
  END rw0_wd_in[407]
  PIN rw0_wd_in[408]
    DIRECTION OUTPUT ;
    USE SIGNAL ;
    SHAPE ABUTMENT ;
    PORT
      LAYER met2 ;
      RECT 72.610 0.000 72.750 0.420 ;
    END
  END rw0_wd_in[408]
  PIN rw0_wd_in[409]
    DIRECTION OUTPUT ;
    USE SIGNAL ;
    SHAPE ABUTMENT ;
    PORT
      LAYER met2 ;
      RECT 73.070 0.000 73.210 0.420 ;
    END
  END rw0_wd_in[409]
  PIN rw0_wd_in[410]
    DIRECTION OUTPUT ;
    USE SIGNAL ;
    SHAPE ABUTMENT ;
    PORT
      LAYER met2 ;
      RECT 73.530 0.000 73.670 0.420 ;
    END
  END rw0_wd_in[410]
  PIN rw0_wd_in[411]
    DIRECTION OUTPUT ;
    USE SIGNAL ;
    SHAPE ABUTMENT ;
    PORT
      LAYER met2 ;
      RECT 73.990 0.000 74.130 0.420 ;
    END
  END rw0_wd_in[411]
  PIN rw0_wd_in[412]
    DIRECTION OUTPUT ;
    USE SIGNAL ;
    SHAPE ABUTMENT ;
    PORT
      LAYER met2 ;
      RECT 74.450 0.000 74.590 0.420 ;
    END
  END rw0_wd_in[412]
  PIN rw0_wd_in[413]
    DIRECTION OUTPUT ;
    USE SIGNAL ;
    SHAPE ABUTMENT ;
    PORT
      LAYER met2 ;
      RECT 74.910 0.000 75.050 0.420 ;
    END
  END rw0_wd_in[413]
  PIN rw0_wd_in[414]
    DIRECTION OUTPUT ;
    USE SIGNAL ;
    SHAPE ABUTMENT ;
    PORT
      LAYER met2 ;
      RECT 75.370 0.000 75.510 0.420 ;
    END
  END rw0_wd_in[414]
  PIN rw0_wd_in[415]
    DIRECTION OUTPUT ;
    USE SIGNAL ;
    SHAPE ABUTMENT ;
    PORT
      LAYER met2 ;
      RECT 75.830 0.000 75.970 0.420 ;
    END
  END rw0_wd_in[415]
  PIN rw0_wd_in[416]
    DIRECTION OUTPUT ;
    USE SIGNAL ;
    SHAPE ABUTMENT ;
    PORT
      LAYER met2 ;
      RECT 76.290 0.000 76.430 0.420 ;
    END
  END rw0_wd_in[416]
  PIN rw0_wd_in[417]
    DIRECTION OUTPUT ;
    USE SIGNAL ;
    SHAPE ABUTMENT ;
    PORT
      LAYER met2 ;
      RECT 76.750 0.000 76.890 0.420 ;
    END
  END rw0_wd_in[417]
  PIN rw0_wd_in[418]
    DIRECTION OUTPUT ;
    USE SIGNAL ;
    SHAPE ABUTMENT ;
    PORT
      LAYER met2 ;
      RECT 77.210 0.000 77.350 0.420 ;
    END
  END rw0_wd_in[418]
  PIN rw0_wd_in[419]
    DIRECTION OUTPUT ;
    USE SIGNAL ;
    SHAPE ABUTMENT ;
    PORT
      LAYER met2 ;
      RECT 77.670 0.000 77.810 0.420 ;
    END
  END rw0_wd_in[419]
  PIN rw0_wd_in[420]
    DIRECTION OUTPUT ;
    USE SIGNAL ;
    SHAPE ABUTMENT ;
    PORT
      LAYER met2 ;
      RECT 78.130 0.000 78.270 0.420 ;
    END
  END rw0_wd_in[420]
  PIN rw0_wd_in[421]
    DIRECTION OUTPUT ;
    USE SIGNAL ;
    SHAPE ABUTMENT ;
    PORT
      LAYER met2 ;
      RECT 78.590 0.000 78.730 0.420 ;
    END
  END rw0_wd_in[421]
  PIN rw0_wd_in[422]
    DIRECTION OUTPUT ;
    USE SIGNAL ;
    SHAPE ABUTMENT ;
    PORT
      LAYER met2 ;
      RECT 79.050 0.000 79.190 0.420 ;
    END
  END rw0_wd_in[422]
  PIN rw0_wd_in[423]
    DIRECTION OUTPUT ;
    USE SIGNAL ;
    SHAPE ABUTMENT ;
    PORT
      LAYER met2 ;
      RECT 79.510 0.000 79.650 0.420 ;
    END
  END rw0_wd_in[423]
  PIN rw0_wd_in[424]
    DIRECTION OUTPUT ;
    USE SIGNAL ;
    SHAPE ABUTMENT ;
    PORT
      LAYER met2 ;
      RECT 79.970 0.000 80.110 0.420 ;
    END
  END rw0_wd_in[424]
  PIN rw0_wd_in[425]
    DIRECTION OUTPUT ;
    USE SIGNAL ;
    SHAPE ABUTMENT ;
    PORT
      LAYER met2 ;
      RECT 80.430 0.000 80.570 0.420 ;
    END
  END rw0_wd_in[425]
  PIN rw0_wd_in[426]
    DIRECTION OUTPUT ;
    USE SIGNAL ;
    SHAPE ABUTMENT ;
    PORT
      LAYER met2 ;
      RECT 80.890 0.000 81.030 0.420 ;
    END
  END rw0_wd_in[426]
  PIN rw0_wd_in[427]
    DIRECTION OUTPUT ;
    USE SIGNAL ;
    SHAPE ABUTMENT ;
    PORT
      LAYER met2 ;
      RECT 81.350 0.000 81.490 0.420 ;
    END
  END rw0_wd_in[427]
  PIN rw0_wd_in[428]
    DIRECTION OUTPUT ;
    USE SIGNAL ;
    SHAPE ABUTMENT ;
    PORT
      LAYER met2 ;
      RECT 81.810 0.000 81.950 0.420 ;
    END
  END rw0_wd_in[428]
  PIN rw0_wd_in[429]
    DIRECTION OUTPUT ;
    USE SIGNAL ;
    SHAPE ABUTMENT ;
    PORT
      LAYER met2 ;
      RECT 82.270 0.000 82.410 0.420 ;
    END
  END rw0_wd_in[429]
  PIN rw0_wd_in[430]
    DIRECTION OUTPUT ;
    USE SIGNAL ;
    SHAPE ABUTMENT ;
    PORT
      LAYER met2 ;
      RECT 82.730 0.000 82.870 0.420 ;
    END
  END rw0_wd_in[430]
  PIN rw0_wd_in[431]
    DIRECTION OUTPUT ;
    USE SIGNAL ;
    SHAPE ABUTMENT ;
    PORT
      LAYER met2 ;
      RECT 83.190 0.000 83.330 0.420 ;
    END
  END rw0_wd_in[431]
  PIN rw0_wd_in[432]
    DIRECTION OUTPUT ;
    USE SIGNAL ;
    SHAPE ABUTMENT ;
    PORT
      LAYER met2 ;
      RECT 83.650 0.000 83.790 0.420 ;
    END
  END rw0_wd_in[432]
  PIN rw0_wd_in[433]
    DIRECTION OUTPUT ;
    USE SIGNAL ;
    SHAPE ABUTMENT ;
    PORT
      LAYER met2 ;
      RECT 84.110 0.000 84.250 0.420 ;
    END
  END rw0_wd_in[433]
  PIN rw0_wd_in[434]
    DIRECTION OUTPUT ;
    USE SIGNAL ;
    SHAPE ABUTMENT ;
    PORT
      LAYER met2 ;
      RECT 84.570 0.000 84.710 0.420 ;
    END
  END rw0_wd_in[434]
  PIN rw0_wd_in[435]
    DIRECTION OUTPUT ;
    USE SIGNAL ;
    SHAPE ABUTMENT ;
    PORT
      LAYER met2 ;
      RECT 85.030 0.000 85.170 0.420 ;
    END
  END rw0_wd_in[435]
  PIN rw0_wd_in[436]
    DIRECTION OUTPUT ;
    USE SIGNAL ;
    SHAPE ABUTMENT ;
    PORT
      LAYER met2 ;
      RECT 85.490 0.000 85.630 0.420 ;
    END
  END rw0_wd_in[436]
  PIN rw0_wd_in[437]
    DIRECTION OUTPUT ;
    USE SIGNAL ;
    SHAPE ABUTMENT ;
    PORT
      LAYER met2 ;
      RECT 85.950 0.000 86.090 0.420 ;
    END
  END rw0_wd_in[437]
  PIN rw0_wd_in[438]
    DIRECTION OUTPUT ;
    USE SIGNAL ;
    SHAPE ABUTMENT ;
    PORT
      LAYER met2 ;
      RECT 86.410 0.000 86.550 0.420 ;
    END
  END rw0_wd_in[438]
  PIN rw0_wd_in[439]
    DIRECTION OUTPUT ;
    USE SIGNAL ;
    SHAPE ABUTMENT ;
    PORT
      LAYER met2 ;
      RECT 86.870 0.000 87.010 0.420 ;
    END
  END rw0_wd_in[439]
  PIN rw0_wd_in[440]
    DIRECTION OUTPUT ;
    USE SIGNAL ;
    SHAPE ABUTMENT ;
    PORT
      LAYER met2 ;
      RECT 87.330 0.000 87.470 0.420 ;
    END
  END rw0_wd_in[440]
  PIN rw0_wd_in[441]
    DIRECTION OUTPUT ;
    USE SIGNAL ;
    SHAPE ABUTMENT ;
    PORT
      LAYER met2 ;
      RECT 87.790 0.000 87.930 0.420 ;
    END
  END rw0_wd_in[441]
  PIN rw0_wd_in[442]
    DIRECTION OUTPUT ;
    USE SIGNAL ;
    SHAPE ABUTMENT ;
    PORT
      LAYER met2 ;
      RECT 88.250 0.000 88.390 0.420 ;
    END
  END rw0_wd_in[442]
  PIN rw0_wd_in[443]
    DIRECTION OUTPUT ;
    USE SIGNAL ;
    SHAPE ABUTMENT ;
    PORT
      LAYER met2 ;
      RECT 88.710 0.000 88.850 0.420 ;
    END
  END rw0_wd_in[443]
  PIN rw0_wd_in[444]
    DIRECTION OUTPUT ;
    USE SIGNAL ;
    SHAPE ABUTMENT ;
    PORT
      LAYER met2 ;
      RECT 89.170 0.000 89.310 0.420 ;
    END
  END rw0_wd_in[444]
  PIN rw0_wd_in[445]
    DIRECTION OUTPUT ;
    USE SIGNAL ;
    SHAPE ABUTMENT ;
    PORT
      LAYER met2 ;
      RECT 89.630 0.000 89.770 0.420 ;
    END
  END rw0_wd_in[445]
  PIN rw0_wd_in[446]
    DIRECTION OUTPUT ;
    USE SIGNAL ;
    SHAPE ABUTMENT ;
    PORT
      LAYER met2 ;
      RECT 90.090 0.000 90.230 0.420 ;
    END
  END rw0_wd_in[446]
  PIN rw0_wd_in[447]
    DIRECTION OUTPUT ;
    USE SIGNAL ;
    SHAPE ABUTMENT ;
    PORT
      LAYER met2 ;
      RECT 90.550 0.000 90.690 0.420 ;
    END
  END rw0_wd_in[447]
  PIN rw0_wd_in[448]
    DIRECTION OUTPUT ;
    USE SIGNAL ;
    SHAPE ABUTMENT ;
    PORT
      LAYER met2 ;
      RECT 91.010 0.000 91.150 0.420 ;
    END
  END rw0_wd_in[448]
  PIN rw0_wd_in[449]
    DIRECTION OUTPUT ;
    USE SIGNAL ;
    SHAPE ABUTMENT ;
    PORT
      LAYER met2 ;
      RECT 91.470 0.000 91.610 0.420 ;
    END
  END rw0_wd_in[449]
  PIN rw0_wd_in[450]
    DIRECTION OUTPUT ;
    USE SIGNAL ;
    SHAPE ABUTMENT ;
    PORT
      LAYER met2 ;
      RECT 91.930 0.000 92.070 0.420 ;
    END
  END rw0_wd_in[450]
  PIN rw0_wd_in[451]
    DIRECTION OUTPUT ;
    USE SIGNAL ;
    SHAPE ABUTMENT ;
    PORT
      LAYER met2 ;
      RECT 92.390 0.000 92.530 0.420 ;
    END
  END rw0_wd_in[451]
  PIN rw0_wd_in[452]
    DIRECTION OUTPUT ;
    USE SIGNAL ;
    SHAPE ABUTMENT ;
    PORT
      LAYER met2 ;
      RECT 92.850 0.000 92.990 0.420 ;
    END
  END rw0_wd_in[452]
  PIN rw0_wd_in[453]
    DIRECTION OUTPUT ;
    USE SIGNAL ;
    SHAPE ABUTMENT ;
    PORT
      LAYER met2 ;
      RECT 93.310 0.000 93.450 0.420 ;
    END
  END rw0_wd_in[453]
  PIN rw0_wd_in[454]
    DIRECTION OUTPUT ;
    USE SIGNAL ;
    SHAPE ABUTMENT ;
    PORT
      LAYER met2 ;
      RECT 93.770 0.000 93.910 0.420 ;
    END
  END rw0_wd_in[454]
  PIN rw0_wd_in[455]
    DIRECTION OUTPUT ;
    USE SIGNAL ;
    SHAPE ABUTMENT ;
    PORT
      LAYER met2 ;
      RECT 94.230 0.000 94.370 0.420 ;
    END
  END rw0_wd_in[455]
  PIN rw0_wd_in[456]
    DIRECTION OUTPUT ;
    USE SIGNAL ;
    SHAPE ABUTMENT ;
    PORT
      LAYER met2 ;
      RECT 94.690 0.000 94.830 0.420 ;
    END
  END rw0_wd_in[456]
  PIN rw0_wd_in[457]
    DIRECTION OUTPUT ;
    USE SIGNAL ;
    SHAPE ABUTMENT ;
    PORT
      LAYER met2 ;
      RECT 95.150 0.000 95.290 0.420 ;
    END
  END rw0_wd_in[457]
  PIN rw0_wd_in[458]
    DIRECTION OUTPUT ;
    USE SIGNAL ;
    SHAPE ABUTMENT ;
    PORT
      LAYER met2 ;
      RECT 95.610 0.000 95.750 0.420 ;
    END
  END rw0_wd_in[458]
  PIN rw0_wd_in[459]
    DIRECTION OUTPUT ;
    USE SIGNAL ;
    SHAPE ABUTMENT ;
    PORT
      LAYER met2 ;
      RECT 96.070 0.000 96.210 0.420 ;
    END
  END rw0_wd_in[459]
  PIN rw0_wd_in[460]
    DIRECTION OUTPUT ;
    USE SIGNAL ;
    SHAPE ABUTMENT ;
    PORT
      LAYER met2 ;
      RECT 96.530 0.000 96.670 0.420 ;
    END
  END rw0_wd_in[460]
  PIN rw0_wd_in[461]
    DIRECTION OUTPUT ;
    USE SIGNAL ;
    SHAPE ABUTMENT ;
    PORT
      LAYER met2 ;
      RECT 96.990 0.000 97.130 0.420 ;
    END
  END rw0_wd_in[461]
  PIN rw0_wd_in[462]
    DIRECTION OUTPUT ;
    USE SIGNAL ;
    SHAPE ABUTMENT ;
    PORT
      LAYER met2 ;
      RECT 97.450 0.000 97.590 0.420 ;
    END
  END rw0_wd_in[462]
  PIN rw0_wd_in[463]
    DIRECTION OUTPUT ;
    USE SIGNAL ;
    SHAPE ABUTMENT ;
    PORT
      LAYER met2 ;
      RECT 97.910 0.000 98.050 0.420 ;
    END
  END rw0_wd_in[463]
  PIN rw0_wd_in[464]
    DIRECTION OUTPUT ;
    USE SIGNAL ;
    SHAPE ABUTMENT ;
    PORT
      LAYER met2 ;
      RECT 98.370 0.000 98.510 0.420 ;
    END
  END rw0_wd_in[464]
  PIN rw0_wd_in[465]
    DIRECTION OUTPUT ;
    USE SIGNAL ;
    SHAPE ABUTMENT ;
    PORT
      LAYER met2 ;
      RECT 98.830 0.000 98.970 0.420 ;
    END
  END rw0_wd_in[465]
  PIN rw0_wd_in[466]
    DIRECTION OUTPUT ;
    USE SIGNAL ;
    SHAPE ABUTMENT ;
    PORT
      LAYER met2 ;
      RECT 99.290 0.000 99.430 0.420 ;
    END
  END rw0_wd_in[466]
  PIN rw0_wd_in[467]
    DIRECTION OUTPUT ;
    USE SIGNAL ;
    SHAPE ABUTMENT ;
    PORT
      LAYER met2 ;
      RECT 99.750 0.000 99.890 0.420 ;
    END
  END rw0_wd_in[467]
  PIN rw0_wd_in[468]
    DIRECTION OUTPUT ;
    USE SIGNAL ;
    SHAPE ABUTMENT ;
    PORT
      LAYER met2 ;
      RECT 100.210 0.000 100.350 0.420 ;
    END
  END rw0_wd_in[468]
  PIN rw0_wd_in[469]
    DIRECTION OUTPUT ;
    USE SIGNAL ;
    SHAPE ABUTMENT ;
    PORT
      LAYER met2 ;
      RECT 100.670 0.000 100.810 0.420 ;
    END
  END rw0_wd_in[469]
  PIN rw0_wd_in[470]
    DIRECTION OUTPUT ;
    USE SIGNAL ;
    SHAPE ABUTMENT ;
    PORT
      LAYER met2 ;
      RECT 101.130 0.000 101.270 0.420 ;
    END
  END rw0_wd_in[470]
  PIN rw0_wd_in[471]
    DIRECTION OUTPUT ;
    USE SIGNAL ;
    SHAPE ABUTMENT ;
    PORT
      LAYER met2 ;
      RECT 101.590 0.000 101.730 0.420 ;
    END
  END rw0_wd_in[471]
  PIN rw0_wd_in[472]
    DIRECTION OUTPUT ;
    USE SIGNAL ;
    SHAPE ABUTMENT ;
    PORT
      LAYER met2 ;
      RECT 102.050 0.000 102.190 0.420 ;
    END
  END rw0_wd_in[472]
  PIN rw0_wd_in[473]
    DIRECTION OUTPUT ;
    USE SIGNAL ;
    SHAPE ABUTMENT ;
    PORT
      LAYER met2 ;
      RECT 102.510 0.000 102.650 0.420 ;
    END
  END rw0_wd_in[473]
  PIN rw0_wd_in[474]
    DIRECTION OUTPUT ;
    USE SIGNAL ;
    SHAPE ABUTMENT ;
    PORT
      LAYER met2 ;
      RECT 102.970 0.000 103.110 0.420 ;
    END
  END rw0_wd_in[474]
  PIN rw0_wd_in[475]
    DIRECTION OUTPUT ;
    USE SIGNAL ;
    SHAPE ABUTMENT ;
    PORT
      LAYER met2 ;
      RECT 103.430 0.000 103.570 0.420 ;
    END
  END rw0_wd_in[475]
  PIN rw0_wd_in[476]
    DIRECTION OUTPUT ;
    USE SIGNAL ;
    SHAPE ABUTMENT ;
    PORT
      LAYER met2 ;
      RECT 103.890 0.000 104.030 0.420 ;
    END
  END rw0_wd_in[476]
  PIN rw0_wd_in[477]
    DIRECTION OUTPUT ;
    USE SIGNAL ;
    SHAPE ABUTMENT ;
    PORT
      LAYER met2 ;
      RECT 104.350 0.000 104.490 0.420 ;
    END
  END rw0_wd_in[477]
  PIN rw0_wd_in[478]
    DIRECTION OUTPUT ;
    USE SIGNAL ;
    SHAPE ABUTMENT ;
    PORT
      LAYER met2 ;
      RECT 104.810 0.000 104.950 0.420 ;
    END
  END rw0_wd_in[478]
  PIN rw0_wd_in[479]
    DIRECTION OUTPUT ;
    USE SIGNAL ;
    SHAPE ABUTMENT ;
    PORT
      LAYER met2 ;
      RECT 105.270 0.000 105.410 0.420 ;
    END
  END rw0_wd_in[479]
  PIN rw0_wd_in[480]
    DIRECTION OUTPUT ;
    USE SIGNAL ;
    SHAPE ABUTMENT ;
    PORT
      LAYER met2 ;
      RECT 105.730 0.000 105.870 0.420 ;
    END
  END rw0_wd_in[480]
  PIN rw0_wd_in[481]
    DIRECTION OUTPUT ;
    USE SIGNAL ;
    SHAPE ABUTMENT ;
    PORT
      LAYER met2 ;
      RECT 106.190 0.000 106.330 0.420 ;
    END
  END rw0_wd_in[481]
  PIN rw0_wd_in[482]
    DIRECTION OUTPUT ;
    USE SIGNAL ;
    SHAPE ABUTMENT ;
    PORT
      LAYER met2 ;
      RECT 106.650 0.000 106.790 0.420 ;
    END
  END rw0_wd_in[482]
  PIN rw0_wd_in[483]
    DIRECTION OUTPUT ;
    USE SIGNAL ;
    SHAPE ABUTMENT ;
    PORT
      LAYER met2 ;
      RECT 107.110 0.000 107.250 0.420 ;
    END
  END rw0_wd_in[483]
  PIN rw0_wd_in[484]
    DIRECTION OUTPUT ;
    USE SIGNAL ;
    SHAPE ABUTMENT ;
    PORT
      LAYER met2 ;
      RECT 107.570 0.000 107.710 0.420 ;
    END
  END rw0_wd_in[484]
  PIN rw0_wd_in[485]
    DIRECTION OUTPUT ;
    USE SIGNAL ;
    SHAPE ABUTMENT ;
    PORT
      LAYER met2 ;
      RECT 108.030 0.000 108.170 0.420 ;
    END
  END rw0_wd_in[485]
  PIN rw0_wd_in[486]
    DIRECTION OUTPUT ;
    USE SIGNAL ;
    SHAPE ABUTMENT ;
    PORT
      LAYER met2 ;
      RECT 108.490 0.000 108.630 0.420 ;
    END
  END rw0_wd_in[486]
  PIN rw0_wd_in[487]
    DIRECTION OUTPUT ;
    USE SIGNAL ;
    SHAPE ABUTMENT ;
    PORT
      LAYER met2 ;
      RECT 108.950 0.000 109.090 0.420 ;
    END
  END rw0_wd_in[487]
  PIN rw0_wd_in[488]
    DIRECTION OUTPUT ;
    USE SIGNAL ;
    SHAPE ABUTMENT ;
    PORT
      LAYER met2 ;
      RECT 109.410 0.000 109.550 0.420 ;
    END
  END rw0_wd_in[488]
  PIN rw0_wd_in[489]
    DIRECTION OUTPUT ;
    USE SIGNAL ;
    SHAPE ABUTMENT ;
    PORT
      LAYER met2 ;
      RECT 109.870 0.000 110.010 0.420 ;
    END
  END rw0_wd_in[489]
  PIN rw0_wd_in[490]
    DIRECTION OUTPUT ;
    USE SIGNAL ;
    SHAPE ABUTMENT ;
    PORT
      LAYER met2 ;
      RECT 110.330 0.000 110.470 0.420 ;
    END
  END rw0_wd_in[490]
  PIN rw0_wd_in[491]
    DIRECTION OUTPUT ;
    USE SIGNAL ;
    SHAPE ABUTMENT ;
    PORT
      LAYER met2 ;
      RECT 110.790 0.000 110.930 0.420 ;
    END
  END rw0_wd_in[491]
  PIN rw0_wd_in[492]
    DIRECTION OUTPUT ;
    USE SIGNAL ;
    SHAPE ABUTMENT ;
    PORT
      LAYER met2 ;
      RECT 111.250 0.000 111.390 0.420 ;
    END
  END rw0_wd_in[492]
  PIN rw0_wd_in[493]
    DIRECTION OUTPUT ;
    USE SIGNAL ;
    SHAPE ABUTMENT ;
    PORT
      LAYER met2 ;
      RECT 111.710 0.000 111.850 0.420 ;
    END
  END rw0_wd_in[493]
  PIN rw0_wd_in[494]
    DIRECTION OUTPUT ;
    USE SIGNAL ;
    SHAPE ABUTMENT ;
    PORT
      LAYER met2 ;
      RECT 112.170 0.000 112.310 0.420 ;
    END
  END rw0_wd_in[494]
  PIN rw0_wd_in[495]
    DIRECTION OUTPUT ;
    USE SIGNAL ;
    SHAPE ABUTMENT ;
    PORT
      LAYER met2 ;
      RECT 112.630 0.000 112.770 0.420 ;
    END
  END rw0_wd_in[495]
  PIN rw0_wd_in[496]
    DIRECTION OUTPUT ;
    USE SIGNAL ;
    SHAPE ABUTMENT ;
    PORT
      LAYER met2 ;
      RECT 113.090 0.000 113.230 0.420 ;
    END
  END rw0_wd_in[496]
  PIN rw0_wd_in[497]
    DIRECTION OUTPUT ;
    USE SIGNAL ;
    SHAPE ABUTMENT ;
    PORT
      LAYER met2 ;
      RECT 113.550 0.000 113.690 0.420 ;
    END
  END rw0_wd_in[497]
  PIN rw0_wd_in[498]
    DIRECTION OUTPUT ;
    USE SIGNAL ;
    SHAPE ABUTMENT ;
    PORT
      LAYER met2 ;
      RECT 114.010 0.000 114.150 0.420 ;
    END
  END rw0_wd_in[498]
  PIN rw0_wd_in[499]
    DIRECTION OUTPUT ;
    USE SIGNAL ;
    SHAPE ABUTMENT ;
    PORT
      LAYER met2 ;
      RECT 114.470 0.000 114.610 0.420 ;
    END
  END rw0_wd_in[499]
  PIN rw0_wd_in[500]
    DIRECTION OUTPUT ;
    USE SIGNAL ;
    SHAPE ABUTMENT ;
    PORT
      LAYER met2 ;
      RECT 114.930 0.000 115.070 0.420 ;
    END
  END rw0_wd_in[500]
  PIN rw0_wd_in[501]
    DIRECTION OUTPUT ;
    USE SIGNAL ;
    SHAPE ABUTMENT ;
    PORT
      LAYER met2 ;
      RECT 115.390 0.000 115.530 0.420 ;
    END
  END rw0_wd_in[501]
  PIN rw0_wd_in[502]
    DIRECTION OUTPUT ;
    USE SIGNAL ;
    SHAPE ABUTMENT ;
    PORT
      LAYER met2 ;
      RECT 115.850 0.000 115.990 0.420 ;
    END
  END rw0_wd_in[502]
  PIN rw0_wd_in[503]
    DIRECTION OUTPUT ;
    USE SIGNAL ;
    SHAPE ABUTMENT ;
    PORT
      LAYER met2 ;
      RECT 116.310 0.000 116.450 0.420 ;
    END
  END rw0_wd_in[503]
  PIN rw0_wd_in[504]
    DIRECTION OUTPUT ;
    USE SIGNAL ;
    SHAPE ABUTMENT ;
    PORT
      LAYER met2 ;
      RECT 116.770 0.000 116.910 0.420 ;
    END
  END rw0_wd_in[504]
  PIN rw0_wd_in[505]
    DIRECTION OUTPUT ;
    USE SIGNAL ;
    SHAPE ABUTMENT ;
    PORT
      LAYER met2 ;
      RECT 117.230 0.000 117.370 0.420 ;
    END
  END rw0_wd_in[505]
  PIN rw0_wd_in[506]
    DIRECTION OUTPUT ;
    USE SIGNAL ;
    SHAPE ABUTMENT ;
    PORT
      LAYER met2 ;
      RECT 117.690 0.000 117.830 0.420 ;
    END
  END rw0_wd_in[506]
  PIN rw0_wd_in[507]
    DIRECTION OUTPUT ;
    USE SIGNAL ;
    SHAPE ABUTMENT ;
    PORT
      LAYER met2 ;
      RECT 118.150 0.000 118.290 0.420 ;
    END
  END rw0_wd_in[507]
  PIN rw0_wd_in[508]
    DIRECTION OUTPUT ;
    USE SIGNAL ;
    SHAPE ABUTMENT ;
    PORT
      LAYER met2 ;
      RECT 118.610 0.000 118.750 0.420 ;
    END
  END rw0_wd_in[508]
  PIN rw0_wd_in[509]
    DIRECTION OUTPUT ;
    USE SIGNAL ;
    SHAPE ABUTMENT ;
    PORT
      LAYER met2 ;
      RECT 119.070 0.000 119.210 0.420 ;
    END
  END rw0_wd_in[509]
  PIN rw0_wd_in[510]
    DIRECTION OUTPUT ;
    USE SIGNAL ;
    SHAPE ABUTMENT ;
    PORT
      LAYER met2 ;
      RECT 119.530 0.000 119.670 0.420 ;
    END
  END rw0_wd_in[510]
  PIN rw0_wd_in[511]
    DIRECTION OUTPUT ;
    USE SIGNAL ;
    SHAPE ABUTMENT ;
    PORT
      LAYER met2 ;
      RECT 119.990 0.000 120.130 0.420 ;
    END
  END rw0_wd_in[511]
  PIN rw0_rd_out[0]
    DIRECTION OUTPUT ;
    USE SIGNAL ;
    SHAPE ABUTMENT ;
    PORT
      LAYER met2 ;
      RECT 120.450 0.000 120.590 0.420 ;
    END
  END rw0_rd_out[0]
  PIN rw0_rd_out[1]
    DIRECTION OUTPUT ;
    USE SIGNAL ;
    SHAPE ABUTMENT ;
    PORT
      LAYER met2 ;
      RECT 120.910 0.000 121.050 0.420 ;
    END
  END rw0_rd_out[1]
  PIN rw0_rd_out[2]
    DIRECTION OUTPUT ;
    USE SIGNAL ;
    SHAPE ABUTMENT ;
    PORT
      LAYER met2 ;
      RECT 121.370 0.000 121.510 0.420 ;
    END
  END rw0_rd_out[2]
  PIN rw0_rd_out[3]
    DIRECTION OUTPUT ;
    USE SIGNAL ;
    SHAPE ABUTMENT ;
    PORT
      LAYER met2 ;
      RECT 121.830 0.000 121.970 0.420 ;
    END
  END rw0_rd_out[3]
  PIN rw0_rd_out[4]
    DIRECTION OUTPUT ;
    USE SIGNAL ;
    SHAPE ABUTMENT ;
    PORT
      LAYER met2 ;
      RECT 122.290 0.000 122.430 0.420 ;
    END
  END rw0_rd_out[4]
  PIN rw0_rd_out[5]
    DIRECTION OUTPUT ;
    USE SIGNAL ;
    SHAPE ABUTMENT ;
    PORT
      LAYER met2 ;
      RECT 122.750 0.000 122.890 0.420 ;
    END
  END rw0_rd_out[5]
  PIN rw0_rd_out[6]
    DIRECTION OUTPUT ;
    USE SIGNAL ;
    SHAPE ABUTMENT ;
    PORT
      LAYER met2 ;
      RECT 123.210 0.000 123.350 0.420 ;
    END
  END rw0_rd_out[6]
  PIN rw0_rd_out[7]
    DIRECTION OUTPUT ;
    USE SIGNAL ;
    SHAPE ABUTMENT ;
    PORT
      LAYER met2 ;
      RECT 123.670 0.000 123.810 0.420 ;
    END
  END rw0_rd_out[7]
  PIN rw0_rd_out[8]
    DIRECTION OUTPUT ;
    USE SIGNAL ;
    SHAPE ABUTMENT ;
    PORT
      LAYER met2 ;
      RECT 124.130 0.000 124.270 0.420 ;
    END
  END rw0_rd_out[8]
  PIN rw0_rd_out[9]
    DIRECTION OUTPUT ;
    USE SIGNAL ;
    SHAPE ABUTMENT ;
    PORT
      LAYER met2 ;
      RECT 124.590 0.000 124.730 0.420 ;
    END
  END rw0_rd_out[9]
  PIN rw0_rd_out[10]
    DIRECTION OUTPUT ;
    USE SIGNAL ;
    SHAPE ABUTMENT ;
    PORT
      LAYER met2 ;
      RECT 125.050 0.000 125.190 0.420 ;
    END
  END rw0_rd_out[10]
  PIN rw0_rd_out[11]
    DIRECTION OUTPUT ;
    USE SIGNAL ;
    SHAPE ABUTMENT ;
    PORT
      LAYER met2 ;
      RECT 125.510 0.000 125.650 0.420 ;
    END
  END rw0_rd_out[11]
  PIN rw0_rd_out[12]
    DIRECTION OUTPUT ;
    USE SIGNAL ;
    SHAPE ABUTMENT ;
    PORT
      LAYER met2 ;
      RECT 125.970 0.000 126.110 0.420 ;
    END
  END rw0_rd_out[12]
  PIN rw0_rd_out[13]
    DIRECTION OUTPUT ;
    USE SIGNAL ;
    SHAPE ABUTMENT ;
    PORT
      LAYER met2 ;
      RECT 126.430 0.000 126.570 0.420 ;
    END
  END rw0_rd_out[13]
  PIN rw0_rd_out[14]
    DIRECTION OUTPUT ;
    USE SIGNAL ;
    SHAPE ABUTMENT ;
    PORT
      LAYER met2 ;
      RECT 126.890 0.000 127.030 0.420 ;
    END
  END rw0_rd_out[14]
  PIN rw0_rd_out[15]
    DIRECTION OUTPUT ;
    USE SIGNAL ;
    SHAPE ABUTMENT ;
    PORT
      LAYER met2 ;
      RECT 127.350 0.000 127.490 0.420 ;
    END
  END rw0_rd_out[15]
  PIN rw0_rd_out[16]
    DIRECTION OUTPUT ;
    USE SIGNAL ;
    SHAPE ABUTMENT ;
    PORT
      LAYER met2 ;
      RECT 127.810 0.000 127.950 0.420 ;
    END
  END rw0_rd_out[16]
  PIN rw0_rd_out[17]
    DIRECTION OUTPUT ;
    USE SIGNAL ;
    SHAPE ABUTMENT ;
    PORT
      LAYER met2 ;
      RECT 128.270 0.000 128.410 0.420 ;
    END
  END rw0_rd_out[17]
  PIN rw0_rd_out[18]
    DIRECTION OUTPUT ;
    USE SIGNAL ;
    SHAPE ABUTMENT ;
    PORT
      LAYER met2 ;
      RECT 128.730 0.000 128.870 0.420 ;
    END
  END rw0_rd_out[18]
  PIN rw0_rd_out[19]
    DIRECTION OUTPUT ;
    USE SIGNAL ;
    SHAPE ABUTMENT ;
    PORT
      LAYER met2 ;
      RECT 129.190 0.000 129.330 0.420 ;
    END
  END rw0_rd_out[19]
  PIN rw0_rd_out[20]
    DIRECTION OUTPUT ;
    USE SIGNAL ;
    SHAPE ABUTMENT ;
    PORT
      LAYER met2 ;
      RECT 129.650 0.000 129.790 0.420 ;
    END
  END rw0_rd_out[20]
  PIN rw0_rd_out[21]
    DIRECTION OUTPUT ;
    USE SIGNAL ;
    SHAPE ABUTMENT ;
    PORT
      LAYER met2 ;
      RECT 130.110 0.000 130.250 0.420 ;
    END
  END rw0_rd_out[21]
  PIN rw0_rd_out[22]
    DIRECTION OUTPUT ;
    USE SIGNAL ;
    SHAPE ABUTMENT ;
    PORT
      LAYER met2 ;
      RECT 130.570 0.000 130.710 0.420 ;
    END
  END rw0_rd_out[22]
  PIN rw0_rd_out[23]
    DIRECTION OUTPUT ;
    USE SIGNAL ;
    SHAPE ABUTMENT ;
    PORT
      LAYER met2 ;
      RECT 131.030 0.000 131.170 0.420 ;
    END
  END rw0_rd_out[23]
  PIN rw0_rd_out[24]
    DIRECTION OUTPUT ;
    USE SIGNAL ;
    SHAPE ABUTMENT ;
    PORT
      LAYER met2 ;
      RECT 131.490 0.000 131.630 0.420 ;
    END
  END rw0_rd_out[24]
  PIN rw0_rd_out[25]
    DIRECTION OUTPUT ;
    USE SIGNAL ;
    SHAPE ABUTMENT ;
    PORT
      LAYER met2 ;
      RECT 131.950 0.000 132.090 0.420 ;
    END
  END rw0_rd_out[25]
  PIN rw0_rd_out[26]
    DIRECTION OUTPUT ;
    USE SIGNAL ;
    SHAPE ABUTMENT ;
    PORT
      LAYER met2 ;
      RECT 132.410 0.000 132.550 0.420 ;
    END
  END rw0_rd_out[26]
  PIN rw0_rd_out[27]
    DIRECTION OUTPUT ;
    USE SIGNAL ;
    SHAPE ABUTMENT ;
    PORT
      LAYER met2 ;
      RECT 132.870 0.000 133.010 0.420 ;
    END
  END rw0_rd_out[27]
  PIN rw0_rd_out[28]
    DIRECTION OUTPUT ;
    USE SIGNAL ;
    SHAPE ABUTMENT ;
    PORT
      LAYER met2 ;
      RECT 133.330 0.000 133.470 0.420 ;
    END
  END rw0_rd_out[28]
  PIN rw0_rd_out[29]
    DIRECTION OUTPUT ;
    USE SIGNAL ;
    SHAPE ABUTMENT ;
    PORT
      LAYER met2 ;
      RECT 133.790 0.000 133.930 0.420 ;
    END
  END rw0_rd_out[29]
  PIN rw0_rd_out[30]
    DIRECTION OUTPUT ;
    USE SIGNAL ;
    SHAPE ABUTMENT ;
    PORT
      LAYER met2 ;
      RECT 134.250 0.000 134.390 0.420 ;
    END
  END rw0_rd_out[30]
  PIN rw0_rd_out[31]
    DIRECTION OUTPUT ;
    USE SIGNAL ;
    SHAPE ABUTMENT ;
    PORT
      LAYER met2 ;
      RECT 134.710 0.000 134.850 0.420 ;
    END
  END rw0_rd_out[31]
  PIN rw0_rd_out[32]
    DIRECTION OUTPUT ;
    USE SIGNAL ;
    SHAPE ABUTMENT ;
    PORT
      LAYER met2 ;
      RECT 135.170 0.000 135.310 0.420 ;
    END
  END rw0_rd_out[32]
  PIN rw0_rd_out[33]
    DIRECTION OUTPUT ;
    USE SIGNAL ;
    SHAPE ABUTMENT ;
    PORT
      LAYER met2 ;
      RECT 135.630 0.000 135.770 0.420 ;
    END
  END rw0_rd_out[33]
  PIN rw0_rd_out[34]
    DIRECTION OUTPUT ;
    USE SIGNAL ;
    SHAPE ABUTMENT ;
    PORT
      LAYER met2 ;
      RECT 136.090 0.000 136.230 0.420 ;
    END
  END rw0_rd_out[34]
  PIN rw0_rd_out[35]
    DIRECTION OUTPUT ;
    USE SIGNAL ;
    SHAPE ABUTMENT ;
    PORT
      LAYER met2 ;
      RECT 136.550 0.000 136.690 0.420 ;
    END
  END rw0_rd_out[35]
  PIN rw0_rd_out[36]
    DIRECTION OUTPUT ;
    USE SIGNAL ;
    SHAPE ABUTMENT ;
    PORT
      LAYER met2 ;
      RECT 137.010 0.000 137.150 0.420 ;
    END
  END rw0_rd_out[36]
  PIN rw0_rd_out[37]
    DIRECTION OUTPUT ;
    USE SIGNAL ;
    SHAPE ABUTMENT ;
    PORT
      LAYER met2 ;
      RECT 137.470 0.000 137.610 0.420 ;
    END
  END rw0_rd_out[37]
  PIN rw0_rd_out[38]
    DIRECTION OUTPUT ;
    USE SIGNAL ;
    SHAPE ABUTMENT ;
    PORT
      LAYER met2 ;
      RECT 137.930 0.000 138.070 0.420 ;
    END
  END rw0_rd_out[38]
  PIN rw0_rd_out[39]
    DIRECTION OUTPUT ;
    USE SIGNAL ;
    SHAPE ABUTMENT ;
    PORT
      LAYER met2 ;
      RECT 138.390 0.000 138.530 0.420 ;
    END
  END rw0_rd_out[39]
  PIN rw0_rd_out[40]
    DIRECTION OUTPUT ;
    USE SIGNAL ;
    SHAPE ABUTMENT ;
    PORT
      LAYER met2 ;
      RECT 138.850 0.000 138.990 0.420 ;
    END
  END rw0_rd_out[40]
  PIN rw0_rd_out[41]
    DIRECTION OUTPUT ;
    USE SIGNAL ;
    SHAPE ABUTMENT ;
    PORT
      LAYER met2 ;
      RECT 139.310 0.000 139.450 0.420 ;
    END
  END rw0_rd_out[41]
  PIN rw0_rd_out[42]
    DIRECTION OUTPUT ;
    USE SIGNAL ;
    SHAPE ABUTMENT ;
    PORT
      LAYER met2 ;
      RECT 139.770 0.000 139.910 0.420 ;
    END
  END rw0_rd_out[42]
  PIN rw0_rd_out[43]
    DIRECTION OUTPUT ;
    USE SIGNAL ;
    SHAPE ABUTMENT ;
    PORT
      LAYER met2 ;
      RECT 140.230 0.000 140.370 0.420 ;
    END
  END rw0_rd_out[43]
  PIN rw0_rd_out[44]
    DIRECTION OUTPUT ;
    USE SIGNAL ;
    SHAPE ABUTMENT ;
    PORT
      LAYER met2 ;
      RECT 140.690 0.000 140.830 0.420 ;
    END
  END rw0_rd_out[44]
  PIN rw0_rd_out[45]
    DIRECTION OUTPUT ;
    USE SIGNAL ;
    SHAPE ABUTMENT ;
    PORT
      LAYER met2 ;
      RECT 141.150 0.000 141.290 0.420 ;
    END
  END rw0_rd_out[45]
  PIN rw0_rd_out[46]
    DIRECTION OUTPUT ;
    USE SIGNAL ;
    SHAPE ABUTMENT ;
    PORT
      LAYER met2 ;
      RECT 141.610 0.000 141.750 0.420 ;
    END
  END rw0_rd_out[46]
  PIN rw0_rd_out[47]
    DIRECTION OUTPUT ;
    USE SIGNAL ;
    SHAPE ABUTMENT ;
    PORT
      LAYER met2 ;
      RECT 142.070 0.000 142.210 0.420 ;
    END
  END rw0_rd_out[47]
  PIN rw0_rd_out[48]
    DIRECTION OUTPUT ;
    USE SIGNAL ;
    SHAPE ABUTMENT ;
    PORT
      LAYER met2 ;
      RECT 142.530 0.000 142.670 0.420 ;
    END
  END rw0_rd_out[48]
  PIN rw0_rd_out[49]
    DIRECTION OUTPUT ;
    USE SIGNAL ;
    SHAPE ABUTMENT ;
    PORT
      LAYER met2 ;
      RECT 142.990 0.000 143.130 0.420 ;
    END
  END rw0_rd_out[49]
  PIN rw0_rd_out[50]
    DIRECTION OUTPUT ;
    USE SIGNAL ;
    SHAPE ABUTMENT ;
    PORT
      LAYER met2 ;
      RECT 143.450 0.000 143.590 0.420 ;
    END
  END rw0_rd_out[50]
  PIN rw0_rd_out[51]
    DIRECTION OUTPUT ;
    USE SIGNAL ;
    SHAPE ABUTMENT ;
    PORT
      LAYER met2 ;
      RECT 143.910 0.000 144.050 0.420 ;
    END
  END rw0_rd_out[51]
  PIN rw0_rd_out[52]
    DIRECTION OUTPUT ;
    USE SIGNAL ;
    SHAPE ABUTMENT ;
    PORT
      LAYER met2 ;
      RECT 144.370 0.000 144.510 0.420 ;
    END
  END rw0_rd_out[52]
  PIN rw0_rd_out[53]
    DIRECTION OUTPUT ;
    USE SIGNAL ;
    SHAPE ABUTMENT ;
    PORT
      LAYER met2 ;
      RECT 144.830 0.000 144.970 0.420 ;
    END
  END rw0_rd_out[53]
  PIN rw0_rd_out[54]
    DIRECTION OUTPUT ;
    USE SIGNAL ;
    SHAPE ABUTMENT ;
    PORT
      LAYER met2 ;
      RECT 145.290 0.000 145.430 0.420 ;
    END
  END rw0_rd_out[54]
  PIN rw0_rd_out[55]
    DIRECTION OUTPUT ;
    USE SIGNAL ;
    SHAPE ABUTMENT ;
    PORT
      LAYER met2 ;
      RECT 145.750 0.000 145.890 0.420 ;
    END
  END rw0_rd_out[55]
  PIN rw0_rd_out[56]
    DIRECTION OUTPUT ;
    USE SIGNAL ;
    SHAPE ABUTMENT ;
    PORT
      LAYER met2 ;
      RECT 146.210 0.000 146.350 0.420 ;
    END
  END rw0_rd_out[56]
  PIN rw0_rd_out[57]
    DIRECTION OUTPUT ;
    USE SIGNAL ;
    SHAPE ABUTMENT ;
    PORT
      LAYER met2 ;
      RECT 146.670 0.000 146.810 0.420 ;
    END
  END rw0_rd_out[57]
  PIN rw0_rd_out[58]
    DIRECTION OUTPUT ;
    USE SIGNAL ;
    SHAPE ABUTMENT ;
    PORT
      LAYER met2 ;
      RECT 147.130 0.000 147.270 0.420 ;
    END
  END rw0_rd_out[58]
  PIN rw0_rd_out[59]
    DIRECTION OUTPUT ;
    USE SIGNAL ;
    SHAPE ABUTMENT ;
    PORT
      LAYER met2 ;
      RECT 147.590 0.000 147.730 0.420 ;
    END
  END rw0_rd_out[59]
  PIN rw0_rd_out[60]
    DIRECTION OUTPUT ;
    USE SIGNAL ;
    SHAPE ABUTMENT ;
    PORT
      LAYER met2 ;
      RECT 148.050 0.000 148.190 0.420 ;
    END
  END rw0_rd_out[60]
  PIN rw0_rd_out[61]
    DIRECTION OUTPUT ;
    USE SIGNAL ;
    SHAPE ABUTMENT ;
    PORT
      LAYER met2 ;
      RECT 148.510 0.000 148.650 0.420 ;
    END
  END rw0_rd_out[61]
  PIN rw0_rd_out[62]
    DIRECTION OUTPUT ;
    USE SIGNAL ;
    SHAPE ABUTMENT ;
    PORT
      LAYER met2 ;
      RECT 148.970 0.000 149.110 0.420 ;
    END
  END rw0_rd_out[62]
  PIN rw0_rd_out[63]
    DIRECTION OUTPUT ;
    USE SIGNAL ;
    SHAPE ABUTMENT ;
    PORT
      LAYER met2 ;
      RECT 149.430 0.000 149.570 0.420 ;
    END
  END rw0_rd_out[63]
  PIN rw0_rd_out[64]
    DIRECTION OUTPUT ;
    USE SIGNAL ;
    SHAPE ABUTMENT ;
    PORT
      LAYER met2 ;
      RECT 149.890 0.000 150.030 0.420 ;
    END
  END rw0_rd_out[64]
  PIN rw0_rd_out[65]
    DIRECTION OUTPUT ;
    USE SIGNAL ;
    SHAPE ABUTMENT ;
    PORT
      LAYER met2 ;
      RECT 150.350 0.000 150.490 0.420 ;
    END
  END rw0_rd_out[65]
  PIN rw0_rd_out[66]
    DIRECTION OUTPUT ;
    USE SIGNAL ;
    SHAPE ABUTMENT ;
    PORT
      LAYER met2 ;
      RECT 150.810 0.000 150.950 0.420 ;
    END
  END rw0_rd_out[66]
  PIN rw0_rd_out[67]
    DIRECTION OUTPUT ;
    USE SIGNAL ;
    SHAPE ABUTMENT ;
    PORT
      LAYER met2 ;
      RECT 151.270 0.000 151.410 0.420 ;
    END
  END rw0_rd_out[67]
  PIN rw0_rd_out[68]
    DIRECTION OUTPUT ;
    USE SIGNAL ;
    SHAPE ABUTMENT ;
    PORT
      LAYER met2 ;
      RECT 151.730 0.000 151.870 0.420 ;
    END
  END rw0_rd_out[68]
  PIN rw0_rd_out[69]
    DIRECTION OUTPUT ;
    USE SIGNAL ;
    SHAPE ABUTMENT ;
    PORT
      LAYER met2 ;
      RECT 152.190 0.000 152.330 0.420 ;
    END
  END rw0_rd_out[69]
  PIN rw0_rd_out[70]
    DIRECTION OUTPUT ;
    USE SIGNAL ;
    SHAPE ABUTMENT ;
    PORT
      LAYER met2 ;
      RECT 152.650 0.000 152.790 0.420 ;
    END
  END rw0_rd_out[70]
  PIN rw0_rd_out[71]
    DIRECTION OUTPUT ;
    USE SIGNAL ;
    SHAPE ABUTMENT ;
    PORT
      LAYER met2 ;
      RECT 153.110 0.000 153.250 0.420 ;
    END
  END rw0_rd_out[71]
  PIN rw0_rd_out[72]
    DIRECTION OUTPUT ;
    USE SIGNAL ;
    SHAPE ABUTMENT ;
    PORT
      LAYER met2 ;
      RECT 153.570 0.000 153.710 0.420 ;
    END
  END rw0_rd_out[72]
  PIN rw0_rd_out[73]
    DIRECTION OUTPUT ;
    USE SIGNAL ;
    SHAPE ABUTMENT ;
    PORT
      LAYER met2 ;
      RECT 154.030 0.000 154.170 0.420 ;
    END
  END rw0_rd_out[73]
  PIN rw0_rd_out[74]
    DIRECTION OUTPUT ;
    USE SIGNAL ;
    SHAPE ABUTMENT ;
    PORT
      LAYER met2 ;
      RECT 154.490 0.000 154.630 0.420 ;
    END
  END rw0_rd_out[74]
  PIN rw0_rd_out[75]
    DIRECTION OUTPUT ;
    USE SIGNAL ;
    SHAPE ABUTMENT ;
    PORT
      LAYER met2 ;
      RECT 154.950 0.000 155.090 0.420 ;
    END
  END rw0_rd_out[75]
  PIN rw0_rd_out[76]
    DIRECTION OUTPUT ;
    USE SIGNAL ;
    SHAPE ABUTMENT ;
    PORT
      LAYER met2 ;
      RECT 155.410 0.000 155.550 0.420 ;
    END
  END rw0_rd_out[76]
  PIN rw0_rd_out[77]
    DIRECTION OUTPUT ;
    USE SIGNAL ;
    SHAPE ABUTMENT ;
    PORT
      LAYER met2 ;
      RECT 155.870 0.000 156.010 0.420 ;
    END
  END rw0_rd_out[77]
  PIN rw0_rd_out[78]
    DIRECTION OUTPUT ;
    USE SIGNAL ;
    SHAPE ABUTMENT ;
    PORT
      LAYER met2 ;
      RECT 156.330 0.000 156.470 0.420 ;
    END
  END rw0_rd_out[78]
  PIN rw0_rd_out[79]
    DIRECTION OUTPUT ;
    USE SIGNAL ;
    SHAPE ABUTMENT ;
    PORT
      LAYER met2 ;
      RECT 156.790 0.000 156.930 0.420 ;
    END
  END rw0_rd_out[79]
  PIN rw0_rd_out[80]
    DIRECTION OUTPUT ;
    USE SIGNAL ;
    SHAPE ABUTMENT ;
    PORT
      LAYER met2 ;
      RECT 157.250 0.000 157.390 0.420 ;
    END
  END rw0_rd_out[80]
  PIN rw0_rd_out[81]
    DIRECTION OUTPUT ;
    USE SIGNAL ;
    SHAPE ABUTMENT ;
    PORT
      LAYER met2 ;
      RECT 157.710 0.000 157.850 0.420 ;
    END
  END rw0_rd_out[81]
  PIN rw0_rd_out[82]
    DIRECTION OUTPUT ;
    USE SIGNAL ;
    SHAPE ABUTMENT ;
    PORT
      LAYER met2 ;
      RECT 158.170 0.000 158.310 0.420 ;
    END
  END rw0_rd_out[82]
  PIN rw0_rd_out[83]
    DIRECTION OUTPUT ;
    USE SIGNAL ;
    SHAPE ABUTMENT ;
    PORT
      LAYER met2 ;
      RECT 158.630 0.000 158.770 0.420 ;
    END
  END rw0_rd_out[83]
  PIN rw0_rd_out[84]
    DIRECTION OUTPUT ;
    USE SIGNAL ;
    SHAPE ABUTMENT ;
    PORT
      LAYER met2 ;
      RECT 159.090 0.000 159.230 0.420 ;
    END
  END rw0_rd_out[84]
  PIN rw0_rd_out[85]
    DIRECTION OUTPUT ;
    USE SIGNAL ;
    SHAPE ABUTMENT ;
    PORT
      LAYER met2 ;
      RECT 159.550 0.000 159.690 0.420 ;
    END
  END rw0_rd_out[85]
  PIN rw0_rd_out[86]
    DIRECTION OUTPUT ;
    USE SIGNAL ;
    SHAPE ABUTMENT ;
    PORT
      LAYER met2 ;
      RECT 160.010 0.000 160.150 0.420 ;
    END
  END rw0_rd_out[86]
  PIN rw0_rd_out[87]
    DIRECTION OUTPUT ;
    USE SIGNAL ;
    SHAPE ABUTMENT ;
    PORT
      LAYER met2 ;
      RECT 160.470 0.000 160.610 0.420 ;
    END
  END rw0_rd_out[87]
  PIN rw0_rd_out[88]
    DIRECTION OUTPUT ;
    USE SIGNAL ;
    SHAPE ABUTMENT ;
    PORT
      LAYER met2 ;
      RECT 160.930 0.000 161.070 0.420 ;
    END
  END rw0_rd_out[88]
  PIN rw0_rd_out[89]
    DIRECTION OUTPUT ;
    USE SIGNAL ;
    SHAPE ABUTMENT ;
    PORT
      LAYER met2 ;
      RECT 161.390 0.000 161.530 0.420 ;
    END
  END rw0_rd_out[89]
  PIN rw0_rd_out[90]
    DIRECTION OUTPUT ;
    USE SIGNAL ;
    SHAPE ABUTMENT ;
    PORT
      LAYER met2 ;
      RECT 161.850 0.000 161.990 0.420 ;
    END
  END rw0_rd_out[90]
  PIN rw0_rd_out[91]
    DIRECTION OUTPUT ;
    USE SIGNAL ;
    SHAPE ABUTMENT ;
    PORT
      LAYER met2 ;
      RECT 162.310 0.000 162.450 0.420 ;
    END
  END rw0_rd_out[91]
  PIN rw0_rd_out[92]
    DIRECTION OUTPUT ;
    USE SIGNAL ;
    SHAPE ABUTMENT ;
    PORT
      LAYER met2 ;
      RECT 162.770 0.000 162.910 0.420 ;
    END
  END rw0_rd_out[92]
  PIN rw0_rd_out[93]
    DIRECTION OUTPUT ;
    USE SIGNAL ;
    SHAPE ABUTMENT ;
    PORT
      LAYER met2 ;
      RECT 163.230 0.000 163.370 0.420 ;
    END
  END rw0_rd_out[93]
  PIN rw0_rd_out[94]
    DIRECTION OUTPUT ;
    USE SIGNAL ;
    SHAPE ABUTMENT ;
    PORT
      LAYER met2 ;
      RECT 163.690 0.000 163.830 0.420 ;
    END
  END rw0_rd_out[94]
  PIN rw0_rd_out[95]
    DIRECTION OUTPUT ;
    USE SIGNAL ;
    SHAPE ABUTMENT ;
    PORT
      LAYER met2 ;
      RECT 164.150 0.000 164.290 0.420 ;
    END
  END rw0_rd_out[95]
  PIN rw0_rd_out[96]
    DIRECTION OUTPUT ;
    USE SIGNAL ;
    SHAPE ABUTMENT ;
    PORT
      LAYER met2 ;
      RECT 164.610 0.000 164.750 0.420 ;
    END
  END rw0_rd_out[96]
  PIN rw0_rd_out[97]
    DIRECTION OUTPUT ;
    USE SIGNAL ;
    SHAPE ABUTMENT ;
    PORT
      LAYER met2 ;
      RECT 165.070 0.000 165.210 0.420 ;
    END
  END rw0_rd_out[97]
  PIN rw0_rd_out[98]
    DIRECTION OUTPUT ;
    USE SIGNAL ;
    SHAPE ABUTMENT ;
    PORT
      LAYER met2 ;
      RECT 165.530 0.000 165.670 0.420 ;
    END
  END rw0_rd_out[98]
  PIN rw0_rd_out[99]
    DIRECTION OUTPUT ;
    USE SIGNAL ;
    SHAPE ABUTMENT ;
    PORT
      LAYER met2 ;
      RECT 165.990 0.000 166.130 0.420 ;
    END
  END rw0_rd_out[99]
  PIN rw0_rd_out[100]
    DIRECTION OUTPUT ;
    USE SIGNAL ;
    SHAPE ABUTMENT ;
    PORT
      LAYER met2 ;
      RECT 166.450 0.000 166.590 0.420 ;
    END
  END rw0_rd_out[100]
  PIN rw0_rd_out[101]
    DIRECTION OUTPUT ;
    USE SIGNAL ;
    SHAPE ABUTMENT ;
    PORT
      LAYER met2 ;
      RECT 166.910 0.000 167.050 0.420 ;
    END
  END rw0_rd_out[101]
  PIN rw0_rd_out[102]
    DIRECTION OUTPUT ;
    USE SIGNAL ;
    SHAPE ABUTMENT ;
    PORT
      LAYER met2 ;
      RECT 167.370 0.000 167.510 0.420 ;
    END
  END rw0_rd_out[102]
  PIN rw0_rd_out[103]
    DIRECTION OUTPUT ;
    USE SIGNAL ;
    SHAPE ABUTMENT ;
    PORT
      LAYER met2 ;
      RECT 167.830 0.000 167.970 0.420 ;
    END
  END rw0_rd_out[103]
  PIN rw0_rd_out[104]
    DIRECTION OUTPUT ;
    USE SIGNAL ;
    SHAPE ABUTMENT ;
    PORT
      LAYER met2 ;
      RECT 168.290 0.000 168.430 0.420 ;
    END
  END rw0_rd_out[104]
  PIN rw0_rd_out[105]
    DIRECTION OUTPUT ;
    USE SIGNAL ;
    SHAPE ABUTMENT ;
    PORT
      LAYER met2 ;
      RECT 168.750 0.000 168.890 0.420 ;
    END
  END rw0_rd_out[105]
  PIN rw0_rd_out[106]
    DIRECTION OUTPUT ;
    USE SIGNAL ;
    SHAPE ABUTMENT ;
    PORT
      LAYER met2 ;
      RECT 169.210 0.000 169.350 0.420 ;
    END
  END rw0_rd_out[106]
  PIN rw0_rd_out[107]
    DIRECTION OUTPUT ;
    USE SIGNAL ;
    SHAPE ABUTMENT ;
    PORT
      LAYER met2 ;
      RECT 169.670 0.000 169.810 0.420 ;
    END
  END rw0_rd_out[107]
  PIN rw0_rd_out[108]
    DIRECTION OUTPUT ;
    USE SIGNAL ;
    SHAPE ABUTMENT ;
    PORT
      LAYER met2 ;
      RECT 170.130 0.000 170.270 0.420 ;
    END
  END rw0_rd_out[108]
  PIN rw0_rd_out[109]
    DIRECTION OUTPUT ;
    USE SIGNAL ;
    SHAPE ABUTMENT ;
    PORT
      LAYER met2 ;
      RECT 170.590 0.000 170.730 0.420 ;
    END
  END rw0_rd_out[109]
  PIN rw0_rd_out[110]
    DIRECTION OUTPUT ;
    USE SIGNAL ;
    SHAPE ABUTMENT ;
    PORT
      LAYER met2 ;
      RECT 171.050 0.000 171.190 0.420 ;
    END
  END rw0_rd_out[110]
  PIN rw0_rd_out[111]
    DIRECTION OUTPUT ;
    USE SIGNAL ;
    SHAPE ABUTMENT ;
    PORT
      LAYER met2 ;
      RECT 171.510 0.000 171.650 0.420 ;
    END
  END rw0_rd_out[111]
  PIN rw0_rd_out[112]
    DIRECTION OUTPUT ;
    USE SIGNAL ;
    SHAPE ABUTMENT ;
    PORT
      LAYER met2 ;
      RECT 171.970 0.000 172.110 0.420 ;
    END
  END rw0_rd_out[112]
  PIN rw0_rd_out[113]
    DIRECTION OUTPUT ;
    USE SIGNAL ;
    SHAPE ABUTMENT ;
    PORT
      LAYER met2 ;
      RECT 172.430 0.000 172.570 0.420 ;
    END
  END rw0_rd_out[113]
  PIN rw0_rd_out[114]
    DIRECTION OUTPUT ;
    USE SIGNAL ;
    SHAPE ABUTMENT ;
    PORT
      LAYER met2 ;
      RECT 172.890 0.000 173.030 0.420 ;
    END
  END rw0_rd_out[114]
  PIN rw0_rd_out[115]
    DIRECTION OUTPUT ;
    USE SIGNAL ;
    SHAPE ABUTMENT ;
    PORT
      LAYER met2 ;
      RECT 173.350 0.000 173.490 0.420 ;
    END
  END rw0_rd_out[115]
  PIN rw0_rd_out[116]
    DIRECTION OUTPUT ;
    USE SIGNAL ;
    SHAPE ABUTMENT ;
    PORT
      LAYER met2 ;
      RECT 173.810 0.000 173.950 0.420 ;
    END
  END rw0_rd_out[116]
  PIN rw0_rd_out[117]
    DIRECTION OUTPUT ;
    USE SIGNAL ;
    SHAPE ABUTMENT ;
    PORT
      LAYER met2 ;
      RECT 174.270 0.000 174.410 0.420 ;
    END
  END rw0_rd_out[117]
  PIN rw0_rd_out[118]
    DIRECTION OUTPUT ;
    USE SIGNAL ;
    SHAPE ABUTMENT ;
    PORT
      LAYER met2 ;
      RECT 174.730 0.000 174.870 0.420 ;
    END
  END rw0_rd_out[118]
  PIN rw0_rd_out[119]
    DIRECTION OUTPUT ;
    USE SIGNAL ;
    SHAPE ABUTMENT ;
    PORT
      LAYER met2 ;
      RECT 175.190 0.000 175.330 0.420 ;
    END
  END rw0_rd_out[119]
  PIN rw0_rd_out[120]
    DIRECTION OUTPUT ;
    USE SIGNAL ;
    SHAPE ABUTMENT ;
    PORT
      LAYER met2 ;
      RECT 175.650 0.000 175.790 0.420 ;
    END
  END rw0_rd_out[120]
  PIN rw0_rd_out[121]
    DIRECTION OUTPUT ;
    USE SIGNAL ;
    SHAPE ABUTMENT ;
    PORT
      LAYER met2 ;
      RECT 176.110 0.000 176.250 0.420 ;
    END
  END rw0_rd_out[121]
  PIN rw0_rd_out[122]
    DIRECTION OUTPUT ;
    USE SIGNAL ;
    SHAPE ABUTMENT ;
    PORT
      LAYER met2 ;
      RECT 176.570 0.000 176.710 0.420 ;
    END
  END rw0_rd_out[122]
  PIN rw0_rd_out[123]
    DIRECTION OUTPUT ;
    USE SIGNAL ;
    SHAPE ABUTMENT ;
    PORT
      LAYER met2 ;
      RECT 177.030 0.000 177.170 0.420 ;
    END
  END rw0_rd_out[123]
  PIN rw0_rd_out[124]
    DIRECTION OUTPUT ;
    USE SIGNAL ;
    SHAPE ABUTMENT ;
    PORT
      LAYER met2 ;
      RECT 177.490 0.000 177.630 0.420 ;
    END
  END rw0_rd_out[124]
  PIN rw0_rd_out[125]
    DIRECTION OUTPUT ;
    USE SIGNAL ;
    SHAPE ABUTMENT ;
    PORT
      LAYER met2 ;
      RECT 177.950 0.000 178.090 0.420 ;
    END
  END rw0_rd_out[125]
  PIN rw0_rd_out[126]
    DIRECTION OUTPUT ;
    USE SIGNAL ;
    SHAPE ABUTMENT ;
    PORT
      LAYER met2 ;
      RECT 178.410 0.000 178.550 0.420 ;
    END
  END rw0_rd_out[126]
  PIN rw0_rd_out[127]
    DIRECTION OUTPUT ;
    USE SIGNAL ;
    SHAPE ABUTMENT ;
    PORT
      LAYER met2 ;
      RECT 178.870 0.000 179.010 0.420 ;
    END
  END rw0_rd_out[127]
  PIN rw0_rd_out[128]
    DIRECTION OUTPUT ;
    USE SIGNAL ;
    SHAPE ABUTMENT ;
    PORT
      LAYER met2 ;
      RECT 179.330 0.000 179.470 0.420 ;
    END
  END rw0_rd_out[128]
  PIN rw0_rd_out[129]
    DIRECTION OUTPUT ;
    USE SIGNAL ;
    SHAPE ABUTMENT ;
    PORT
      LAYER met2 ;
      RECT 179.790 0.000 179.930 0.420 ;
    END
  END rw0_rd_out[129]
  PIN rw0_rd_out[130]
    DIRECTION OUTPUT ;
    USE SIGNAL ;
    SHAPE ABUTMENT ;
    PORT
      LAYER met2 ;
      RECT 180.250 0.000 180.390 0.420 ;
    END
  END rw0_rd_out[130]
  PIN rw0_rd_out[131]
    DIRECTION OUTPUT ;
    USE SIGNAL ;
    SHAPE ABUTMENT ;
    PORT
      LAYER met2 ;
      RECT 180.710 0.000 180.850 0.420 ;
    END
  END rw0_rd_out[131]
  PIN rw0_rd_out[132]
    DIRECTION OUTPUT ;
    USE SIGNAL ;
    SHAPE ABUTMENT ;
    PORT
      LAYER met2 ;
      RECT 181.170 0.000 181.310 0.420 ;
    END
  END rw0_rd_out[132]
  PIN rw0_rd_out[133]
    DIRECTION OUTPUT ;
    USE SIGNAL ;
    SHAPE ABUTMENT ;
    PORT
      LAYER met2 ;
      RECT 181.630 0.000 181.770 0.420 ;
    END
  END rw0_rd_out[133]
  PIN rw0_rd_out[134]
    DIRECTION OUTPUT ;
    USE SIGNAL ;
    SHAPE ABUTMENT ;
    PORT
      LAYER met2 ;
      RECT 182.090 0.000 182.230 0.420 ;
    END
  END rw0_rd_out[134]
  PIN rw0_rd_out[135]
    DIRECTION OUTPUT ;
    USE SIGNAL ;
    SHAPE ABUTMENT ;
    PORT
      LAYER met2 ;
      RECT 182.550 0.000 182.690 0.420 ;
    END
  END rw0_rd_out[135]
  PIN rw0_rd_out[136]
    DIRECTION OUTPUT ;
    USE SIGNAL ;
    SHAPE ABUTMENT ;
    PORT
      LAYER met2 ;
      RECT 183.010 0.000 183.150 0.420 ;
    END
  END rw0_rd_out[136]
  PIN rw0_rd_out[137]
    DIRECTION OUTPUT ;
    USE SIGNAL ;
    SHAPE ABUTMENT ;
    PORT
      LAYER met2 ;
      RECT 183.470 0.000 183.610 0.420 ;
    END
  END rw0_rd_out[137]
  PIN rw0_rd_out[138]
    DIRECTION OUTPUT ;
    USE SIGNAL ;
    SHAPE ABUTMENT ;
    PORT
      LAYER met2 ;
      RECT 183.930 0.000 184.070 0.420 ;
    END
  END rw0_rd_out[138]
  PIN rw0_rd_out[139]
    DIRECTION OUTPUT ;
    USE SIGNAL ;
    SHAPE ABUTMENT ;
    PORT
      LAYER met2 ;
      RECT 184.390 0.000 184.530 0.420 ;
    END
  END rw0_rd_out[139]
  PIN rw0_rd_out[140]
    DIRECTION OUTPUT ;
    USE SIGNAL ;
    SHAPE ABUTMENT ;
    PORT
      LAYER met2 ;
      RECT 184.850 0.000 184.990 0.420 ;
    END
  END rw0_rd_out[140]
  PIN rw0_rd_out[141]
    DIRECTION OUTPUT ;
    USE SIGNAL ;
    SHAPE ABUTMENT ;
    PORT
      LAYER met2 ;
      RECT 185.310 0.000 185.450 0.420 ;
    END
  END rw0_rd_out[141]
  PIN rw0_rd_out[142]
    DIRECTION OUTPUT ;
    USE SIGNAL ;
    SHAPE ABUTMENT ;
    PORT
      LAYER met2 ;
      RECT 185.770 0.000 185.910 0.420 ;
    END
  END rw0_rd_out[142]
  PIN rw0_rd_out[143]
    DIRECTION OUTPUT ;
    USE SIGNAL ;
    SHAPE ABUTMENT ;
    PORT
      LAYER met2 ;
      RECT 186.230 0.000 186.370 0.420 ;
    END
  END rw0_rd_out[143]
  PIN rw0_rd_out[144]
    DIRECTION OUTPUT ;
    USE SIGNAL ;
    SHAPE ABUTMENT ;
    PORT
      LAYER met2 ;
      RECT 186.690 0.000 186.830 0.420 ;
    END
  END rw0_rd_out[144]
  PIN rw0_rd_out[145]
    DIRECTION OUTPUT ;
    USE SIGNAL ;
    SHAPE ABUTMENT ;
    PORT
      LAYER met2 ;
      RECT 187.150 0.000 187.290 0.420 ;
    END
  END rw0_rd_out[145]
  PIN rw0_rd_out[146]
    DIRECTION OUTPUT ;
    USE SIGNAL ;
    SHAPE ABUTMENT ;
    PORT
      LAYER met2 ;
      RECT 187.610 0.000 187.750 0.420 ;
    END
  END rw0_rd_out[146]
  PIN rw0_rd_out[147]
    DIRECTION OUTPUT ;
    USE SIGNAL ;
    SHAPE ABUTMENT ;
    PORT
      LAYER met2 ;
      RECT 188.070 0.000 188.210 0.420 ;
    END
  END rw0_rd_out[147]
  PIN rw0_rd_out[148]
    DIRECTION OUTPUT ;
    USE SIGNAL ;
    SHAPE ABUTMENT ;
    PORT
      LAYER met2 ;
      RECT 188.530 0.000 188.670 0.420 ;
    END
  END rw0_rd_out[148]
  PIN rw0_rd_out[149]
    DIRECTION OUTPUT ;
    USE SIGNAL ;
    SHAPE ABUTMENT ;
    PORT
      LAYER met2 ;
      RECT 188.990 0.000 189.130 0.420 ;
    END
  END rw0_rd_out[149]
  PIN rw0_rd_out[150]
    DIRECTION OUTPUT ;
    USE SIGNAL ;
    SHAPE ABUTMENT ;
    PORT
      LAYER met2 ;
      RECT 189.450 0.000 189.590 0.420 ;
    END
  END rw0_rd_out[150]
  PIN rw0_rd_out[151]
    DIRECTION OUTPUT ;
    USE SIGNAL ;
    SHAPE ABUTMENT ;
    PORT
      LAYER met2 ;
      RECT 189.910 0.000 190.050 0.420 ;
    END
  END rw0_rd_out[151]
  PIN rw0_rd_out[152]
    DIRECTION OUTPUT ;
    USE SIGNAL ;
    SHAPE ABUTMENT ;
    PORT
      LAYER met2 ;
      RECT 190.370 0.000 190.510 0.420 ;
    END
  END rw0_rd_out[152]
  PIN rw0_rd_out[153]
    DIRECTION OUTPUT ;
    USE SIGNAL ;
    SHAPE ABUTMENT ;
    PORT
      LAYER met2 ;
      RECT 190.830 0.000 190.970 0.420 ;
    END
  END rw0_rd_out[153]
  PIN rw0_rd_out[154]
    DIRECTION OUTPUT ;
    USE SIGNAL ;
    SHAPE ABUTMENT ;
    PORT
      LAYER met2 ;
      RECT 191.290 0.000 191.430 0.420 ;
    END
  END rw0_rd_out[154]
  PIN rw0_rd_out[155]
    DIRECTION OUTPUT ;
    USE SIGNAL ;
    SHAPE ABUTMENT ;
    PORT
      LAYER met2 ;
      RECT 191.750 0.000 191.890 0.420 ;
    END
  END rw0_rd_out[155]
  PIN rw0_rd_out[156]
    DIRECTION OUTPUT ;
    USE SIGNAL ;
    SHAPE ABUTMENT ;
    PORT
      LAYER met2 ;
      RECT 192.210 0.000 192.350 0.420 ;
    END
  END rw0_rd_out[156]
  PIN rw0_rd_out[157]
    DIRECTION OUTPUT ;
    USE SIGNAL ;
    SHAPE ABUTMENT ;
    PORT
      LAYER met2 ;
      RECT 192.670 0.000 192.810 0.420 ;
    END
  END rw0_rd_out[157]
  PIN rw0_rd_out[158]
    DIRECTION OUTPUT ;
    USE SIGNAL ;
    SHAPE ABUTMENT ;
    PORT
      LAYER met2 ;
      RECT 193.130 0.000 193.270 0.420 ;
    END
  END rw0_rd_out[158]
  PIN rw0_rd_out[159]
    DIRECTION OUTPUT ;
    USE SIGNAL ;
    SHAPE ABUTMENT ;
    PORT
      LAYER met2 ;
      RECT 193.590 0.000 193.730 0.420 ;
    END
  END rw0_rd_out[159]
  PIN rw0_rd_out[160]
    DIRECTION OUTPUT ;
    USE SIGNAL ;
    SHAPE ABUTMENT ;
    PORT
      LAYER met2 ;
      RECT 194.050 0.000 194.190 0.420 ;
    END
  END rw0_rd_out[160]
  PIN rw0_rd_out[161]
    DIRECTION OUTPUT ;
    USE SIGNAL ;
    SHAPE ABUTMENT ;
    PORT
      LAYER met2 ;
      RECT 194.510 0.000 194.650 0.420 ;
    END
  END rw0_rd_out[161]
  PIN rw0_rd_out[162]
    DIRECTION OUTPUT ;
    USE SIGNAL ;
    SHAPE ABUTMENT ;
    PORT
      LAYER met2 ;
      RECT 194.970 0.000 195.110 0.420 ;
    END
  END rw0_rd_out[162]
  PIN rw0_rd_out[163]
    DIRECTION OUTPUT ;
    USE SIGNAL ;
    SHAPE ABUTMENT ;
    PORT
      LAYER met2 ;
      RECT 195.430 0.000 195.570 0.420 ;
    END
  END rw0_rd_out[163]
  PIN rw0_rd_out[164]
    DIRECTION OUTPUT ;
    USE SIGNAL ;
    SHAPE ABUTMENT ;
    PORT
      LAYER met2 ;
      RECT 195.890 0.000 196.030 0.420 ;
    END
  END rw0_rd_out[164]
  PIN rw0_rd_out[165]
    DIRECTION OUTPUT ;
    USE SIGNAL ;
    SHAPE ABUTMENT ;
    PORT
      LAYER met2 ;
      RECT 196.350 0.000 196.490 0.420 ;
    END
  END rw0_rd_out[165]
  PIN rw0_rd_out[166]
    DIRECTION OUTPUT ;
    USE SIGNAL ;
    SHAPE ABUTMENT ;
    PORT
      LAYER met2 ;
      RECT 196.810 0.000 196.950 0.420 ;
    END
  END rw0_rd_out[166]
  PIN rw0_rd_out[167]
    DIRECTION OUTPUT ;
    USE SIGNAL ;
    SHAPE ABUTMENT ;
    PORT
      LAYER met2 ;
      RECT 197.270 0.000 197.410 0.420 ;
    END
  END rw0_rd_out[167]
  PIN rw0_rd_out[168]
    DIRECTION OUTPUT ;
    USE SIGNAL ;
    SHAPE ABUTMENT ;
    PORT
      LAYER met2 ;
      RECT 197.730 0.000 197.870 0.420 ;
    END
  END rw0_rd_out[168]
  PIN rw0_rd_out[169]
    DIRECTION OUTPUT ;
    USE SIGNAL ;
    SHAPE ABUTMENT ;
    PORT
      LAYER met2 ;
      RECT 198.190 0.000 198.330 0.420 ;
    END
  END rw0_rd_out[169]
  PIN rw0_rd_out[170]
    DIRECTION OUTPUT ;
    USE SIGNAL ;
    SHAPE ABUTMENT ;
    PORT
      LAYER met2 ;
      RECT 198.650 0.000 198.790 0.420 ;
    END
  END rw0_rd_out[170]
  PIN rw0_rd_out[171]
    DIRECTION OUTPUT ;
    USE SIGNAL ;
    SHAPE ABUTMENT ;
    PORT
      LAYER met2 ;
      RECT 199.110 0.000 199.250 0.420 ;
    END
  END rw0_rd_out[171]
  PIN rw0_rd_out[172]
    DIRECTION OUTPUT ;
    USE SIGNAL ;
    SHAPE ABUTMENT ;
    PORT
      LAYER met2 ;
      RECT 199.570 0.000 199.710 0.420 ;
    END
  END rw0_rd_out[172]
  PIN rw0_rd_out[173]
    DIRECTION OUTPUT ;
    USE SIGNAL ;
    SHAPE ABUTMENT ;
    PORT
      LAYER met2 ;
      RECT 200.030 0.000 200.170 0.420 ;
    END
  END rw0_rd_out[173]
  PIN rw0_rd_out[174]
    DIRECTION OUTPUT ;
    USE SIGNAL ;
    SHAPE ABUTMENT ;
    PORT
      LAYER met2 ;
      RECT 200.490 0.000 200.630 0.420 ;
    END
  END rw0_rd_out[174]
  PIN rw0_rd_out[175]
    DIRECTION OUTPUT ;
    USE SIGNAL ;
    SHAPE ABUTMENT ;
    PORT
      LAYER met2 ;
      RECT 200.950 0.000 201.090 0.420 ;
    END
  END rw0_rd_out[175]
  PIN rw0_rd_out[176]
    DIRECTION OUTPUT ;
    USE SIGNAL ;
    SHAPE ABUTMENT ;
    PORT
      LAYER met2 ;
      RECT 201.410 0.000 201.550 0.420 ;
    END
  END rw0_rd_out[176]
  PIN rw0_rd_out[177]
    DIRECTION OUTPUT ;
    USE SIGNAL ;
    SHAPE ABUTMENT ;
    PORT
      LAYER met2 ;
      RECT 201.870 0.000 202.010 0.420 ;
    END
  END rw0_rd_out[177]
  PIN rw0_rd_out[178]
    DIRECTION OUTPUT ;
    USE SIGNAL ;
    SHAPE ABUTMENT ;
    PORT
      LAYER met2 ;
      RECT 202.330 0.000 202.470 0.420 ;
    END
  END rw0_rd_out[178]
  PIN rw0_rd_out[179]
    DIRECTION OUTPUT ;
    USE SIGNAL ;
    SHAPE ABUTMENT ;
    PORT
      LAYER met2 ;
      RECT 202.790 0.000 202.930 0.420 ;
    END
  END rw0_rd_out[179]
  PIN rw0_rd_out[180]
    DIRECTION OUTPUT ;
    USE SIGNAL ;
    SHAPE ABUTMENT ;
    PORT
      LAYER met2 ;
      RECT 203.250 0.000 203.390 0.420 ;
    END
  END rw0_rd_out[180]
  PIN rw0_rd_out[181]
    DIRECTION OUTPUT ;
    USE SIGNAL ;
    SHAPE ABUTMENT ;
    PORT
      LAYER met2 ;
      RECT 203.710 0.000 203.850 0.420 ;
    END
  END rw0_rd_out[181]
  PIN rw0_rd_out[182]
    DIRECTION OUTPUT ;
    USE SIGNAL ;
    SHAPE ABUTMENT ;
    PORT
      LAYER met2 ;
      RECT 204.170 0.000 204.310 0.420 ;
    END
  END rw0_rd_out[182]
  PIN rw0_rd_out[183]
    DIRECTION OUTPUT ;
    USE SIGNAL ;
    SHAPE ABUTMENT ;
    PORT
      LAYER met2 ;
      RECT 204.630 0.000 204.770 0.420 ;
    END
  END rw0_rd_out[183]
  PIN rw0_rd_out[184]
    DIRECTION OUTPUT ;
    USE SIGNAL ;
    SHAPE ABUTMENT ;
    PORT
      LAYER met2 ;
      RECT 205.090 0.000 205.230 0.420 ;
    END
  END rw0_rd_out[184]
  PIN rw0_rd_out[185]
    DIRECTION OUTPUT ;
    USE SIGNAL ;
    SHAPE ABUTMENT ;
    PORT
      LAYER met2 ;
      RECT 205.550 0.000 205.690 0.420 ;
    END
  END rw0_rd_out[185]
  PIN rw0_rd_out[186]
    DIRECTION OUTPUT ;
    USE SIGNAL ;
    SHAPE ABUTMENT ;
    PORT
      LAYER met2 ;
      RECT 206.010 0.000 206.150 0.420 ;
    END
  END rw0_rd_out[186]
  PIN rw0_rd_out[187]
    DIRECTION OUTPUT ;
    USE SIGNAL ;
    SHAPE ABUTMENT ;
    PORT
      LAYER met2 ;
      RECT 206.470 0.000 206.610 0.420 ;
    END
  END rw0_rd_out[187]
  PIN rw0_rd_out[188]
    DIRECTION OUTPUT ;
    USE SIGNAL ;
    SHAPE ABUTMENT ;
    PORT
      LAYER met2 ;
      RECT 206.930 0.000 207.070 0.420 ;
    END
  END rw0_rd_out[188]
  PIN rw0_rd_out[189]
    DIRECTION OUTPUT ;
    USE SIGNAL ;
    SHAPE ABUTMENT ;
    PORT
      LAYER met2 ;
      RECT 207.390 0.000 207.530 0.420 ;
    END
  END rw0_rd_out[189]
  PIN rw0_rd_out[190]
    DIRECTION OUTPUT ;
    USE SIGNAL ;
    SHAPE ABUTMENT ;
    PORT
      LAYER met2 ;
      RECT 207.850 0.000 207.990 0.420 ;
    END
  END rw0_rd_out[190]
  PIN rw0_rd_out[191]
    DIRECTION OUTPUT ;
    USE SIGNAL ;
    SHAPE ABUTMENT ;
    PORT
      LAYER met2 ;
      RECT 208.310 0.000 208.450 0.420 ;
    END
  END rw0_rd_out[191]
  PIN rw0_rd_out[192]
    DIRECTION OUTPUT ;
    USE SIGNAL ;
    SHAPE ABUTMENT ;
    PORT
      LAYER met2 ;
      RECT 208.770 0.000 208.910 0.420 ;
    END
  END rw0_rd_out[192]
  PIN rw0_rd_out[193]
    DIRECTION OUTPUT ;
    USE SIGNAL ;
    SHAPE ABUTMENT ;
    PORT
      LAYER met2 ;
      RECT 209.230 0.000 209.370 0.420 ;
    END
  END rw0_rd_out[193]
  PIN rw0_rd_out[194]
    DIRECTION OUTPUT ;
    USE SIGNAL ;
    SHAPE ABUTMENT ;
    PORT
      LAYER met2 ;
      RECT 209.690 0.000 209.830 0.420 ;
    END
  END rw0_rd_out[194]
  PIN rw0_rd_out[195]
    DIRECTION OUTPUT ;
    USE SIGNAL ;
    SHAPE ABUTMENT ;
    PORT
      LAYER met2 ;
      RECT 210.150 0.000 210.290 0.420 ;
    END
  END rw0_rd_out[195]
  PIN rw0_rd_out[196]
    DIRECTION OUTPUT ;
    USE SIGNAL ;
    SHAPE ABUTMENT ;
    PORT
      LAYER met2 ;
      RECT 210.610 0.000 210.750 0.420 ;
    END
  END rw0_rd_out[196]
  PIN rw0_rd_out[197]
    DIRECTION OUTPUT ;
    USE SIGNAL ;
    SHAPE ABUTMENT ;
    PORT
      LAYER met2 ;
      RECT 211.070 0.000 211.210 0.420 ;
    END
  END rw0_rd_out[197]
  PIN rw0_rd_out[198]
    DIRECTION OUTPUT ;
    USE SIGNAL ;
    SHAPE ABUTMENT ;
    PORT
      LAYER met2 ;
      RECT 211.530 0.000 211.670 0.420 ;
    END
  END rw0_rd_out[198]
  PIN rw0_rd_out[199]
    DIRECTION OUTPUT ;
    USE SIGNAL ;
    SHAPE ABUTMENT ;
    PORT
      LAYER met2 ;
      RECT 211.990 0.000 212.130 0.420 ;
    END
  END rw0_rd_out[199]
  PIN rw0_rd_out[200]
    DIRECTION OUTPUT ;
    USE SIGNAL ;
    SHAPE ABUTMENT ;
    PORT
      LAYER met2 ;
      RECT 212.450 0.000 212.590 0.420 ;
    END
  END rw0_rd_out[200]
  PIN rw0_rd_out[201]
    DIRECTION OUTPUT ;
    USE SIGNAL ;
    SHAPE ABUTMENT ;
    PORT
      LAYER met2 ;
      RECT 212.910 0.000 213.050 0.420 ;
    END
  END rw0_rd_out[201]
  PIN rw0_rd_out[202]
    DIRECTION OUTPUT ;
    USE SIGNAL ;
    SHAPE ABUTMENT ;
    PORT
      LAYER met2 ;
      RECT 213.370 0.000 213.510 0.420 ;
    END
  END rw0_rd_out[202]
  PIN rw0_rd_out[203]
    DIRECTION OUTPUT ;
    USE SIGNAL ;
    SHAPE ABUTMENT ;
    PORT
      LAYER met2 ;
      RECT 213.830 0.000 213.970 0.420 ;
    END
  END rw0_rd_out[203]
  PIN rw0_rd_out[204]
    DIRECTION OUTPUT ;
    USE SIGNAL ;
    SHAPE ABUTMENT ;
    PORT
      LAYER met2 ;
      RECT 214.290 0.000 214.430 0.420 ;
    END
  END rw0_rd_out[204]
  PIN rw0_rd_out[205]
    DIRECTION OUTPUT ;
    USE SIGNAL ;
    SHAPE ABUTMENT ;
    PORT
      LAYER met2 ;
      RECT 214.750 0.000 214.890 0.420 ;
    END
  END rw0_rd_out[205]
  PIN rw0_rd_out[206]
    DIRECTION OUTPUT ;
    USE SIGNAL ;
    SHAPE ABUTMENT ;
    PORT
      LAYER met2 ;
      RECT 215.210 0.000 215.350 0.420 ;
    END
  END rw0_rd_out[206]
  PIN rw0_rd_out[207]
    DIRECTION OUTPUT ;
    USE SIGNAL ;
    SHAPE ABUTMENT ;
    PORT
      LAYER met2 ;
      RECT 215.670 0.000 215.810 0.420 ;
    END
  END rw0_rd_out[207]
  PIN rw0_rd_out[208]
    DIRECTION OUTPUT ;
    USE SIGNAL ;
    SHAPE ABUTMENT ;
    PORT
      LAYER met2 ;
      RECT 216.130 0.000 216.270 0.420 ;
    END
  END rw0_rd_out[208]
  PIN rw0_rd_out[209]
    DIRECTION OUTPUT ;
    USE SIGNAL ;
    SHAPE ABUTMENT ;
    PORT
      LAYER met2 ;
      RECT 216.590 0.000 216.730 0.420 ;
    END
  END rw0_rd_out[209]
  PIN rw0_rd_out[210]
    DIRECTION OUTPUT ;
    USE SIGNAL ;
    SHAPE ABUTMENT ;
    PORT
      LAYER met2 ;
      RECT 217.050 0.000 217.190 0.420 ;
    END
  END rw0_rd_out[210]
  PIN rw0_rd_out[211]
    DIRECTION OUTPUT ;
    USE SIGNAL ;
    SHAPE ABUTMENT ;
    PORT
      LAYER met2 ;
      RECT 217.510 0.000 217.650 0.420 ;
    END
  END rw0_rd_out[211]
  PIN rw0_rd_out[212]
    DIRECTION OUTPUT ;
    USE SIGNAL ;
    SHAPE ABUTMENT ;
    PORT
      LAYER met2 ;
      RECT 217.970 0.000 218.110 0.420 ;
    END
  END rw0_rd_out[212]
  PIN rw0_rd_out[213]
    DIRECTION OUTPUT ;
    USE SIGNAL ;
    SHAPE ABUTMENT ;
    PORT
      LAYER met2 ;
      RECT 218.430 0.000 218.570 0.420 ;
    END
  END rw0_rd_out[213]
  PIN rw0_rd_out[214]
    DIRECTION OUTPUT ;
    USE SIGNAL ;
    SHAPE ABUTMENT ;
    PORT
      LAYER met2 ;
      RECT 218.890 0.000 219.030 0.420 ;
    END
  END rw0_rd_out[214]
  PIN rw0_rd_out[215]
    DIRECTION OUTPUT ;
    USE SIGNAL ;
    SHAPE ABUTMENT ;
    PORT
      LAYER met2 ;
      RECT 219.350 0.000 219.490 0.420 ;
    END
  END rw0_rd_out[215]
  PIN rw0_rd_out[216]
    DIRECTION OUTPUT ;
    USE SIGNAL ;
    SHAPE ABUTMENT ;
    PORT
      LAYER met2 ;
      RECT 219.810 0.000 219.950 0.420 ;
    END
  END rw0_rd_out[216]
  PIN rw0_rd_out[217]
    DIRECTION OUTPUT ;
    USE SIGNAL ;
    SHAPE ABUTMENT ;
    PORT
      LAYER met2 ;
      RECT 220.270 0.000 220.410 0.420 ;
    END
  END rw0_rd_out[217]
  PIN rw0_rd_out[218]
    DIRECTION OUTPUT ;
    USE SIGNAL ;
    SHAPE ABUTMENT ;
    PORT
      LAYER met2 ;
      RECT 220.730 0.000 220.870 0.420 ;
    END
  END rw0_rd_out[218]
  PIN rw0_rd_out[219]
    DIRECTION OUTPUT ;
    USE SIGNAL ;
    SHAPE ABUTMENT ;
    PORT
      LAYER met2 ;
      RECT 221.190 0.000 221.330 0.420 ;
    END
  END rw0_rd_out[219]
  PIN rw0_rd_out[220]
    DIRECTION OUTPUT ;
    USE SIGNAL ;
    SHAPE ABUTMENT ;
    PORT
      LAYER met2 ;
      RECT 221.650 0.000 221.790 0.420 ;
    END
  END rw0_rd_out[220]
  PIN rw0_rd_out[221]
    DIRECTION OUTPUT ;
    USE SIGNAL ;
    SHAPE ABUTMENT ;
    PORT
      LAYER met2 ;
      RECT 222.110 0.000 222.250 0.420 ;
    END
  END rw0_rd_out[221]
  PIN rw0_rd_out[222]
    DIRECTION OUTPUT ;
    USE SIGNAL ;
    SHAPE ABUTMENT ;
    PORT
      LAYER met2 ;
      RECT 222.570 0.000 222.710 0.420 ;
    END
  END rw0_rd_out[222]
  PIN rw0_rd_out[223]
    DIRECTION OUTPUT ;
    USE SIGNAL ;
    SHAPE ABUTMENT ;
    PORT
      LAYER met2 ;
      RECT 223.030 0.000 223.170 0.420 ;
    END
  END rw0_rd_out[223]
  PIN rw0_rd_out[224]
    DIRECTION OUTPUT ;
    USE SIGNAL ;
    SHAPE ABUTMENT ;
    PORT
      LAYER met2 ;
      RECT 223.490 0.000 223.630 0.420 ;
    END
  END rw0_rd_out[224]
  PIN rw0_rd_out[225]
    DIRECTION OUTPUT ;
    USE SIGNAL ;
    SHAPE ABUTMENT ;
    PORT
      LAYER met2 ;
      RECT 223.950 0.000 224.090 0.420 ;
    END
  END rw0_rd_out[225]
  PIN rw0_rd_out[226]
    DIRECTION OUTPUT ;
    USE SIGNAL ;
    SHAPE ABUTMENT ;
    PORT
      LAYER met2 ;
      RECT 224.410 0.000 224.550 0.420 ;
    END
  END rw0_rd_out[226]
  PIN rw0_rd_out[227]
    DIRECTION OUTPUT ;
    USE SIGNAL ;
    SHAPE ABUTMENT ;
    PORT
      LAYER met2 ;
      RECT 224.870 0.000 225.010 0.420 ;
    END
  END rw0_rd_out[227]
  PIN rw0_rd_out[228]
    DIRECTION OUTPUT ;
    USE SIGNAL ;
    SHAPE ABUTMENT ;
    PORT
      LAYER met2 ;
      RECT 225.330 0.000 225.470 0.420 ;
    END
  END rw0_rd_out[228]
  PIN rw0_rd_out[229]
    DIRECTION OUTPUT ;
    USE SIGNAL ;
    SHAPE ABUTMENT ;
    PORT
      LAYER met2 ;
      RECT 225.790 0.000 225.930 0.420 ;
    END
  END rw0_rd_out[229]
  PIN rw0_rd_out[230]
    DIRECTION OUTPUT ;
    USE SIGNAL ;
    SHAPE ABUTMENT ;
    PORT
      LAYER met2 ;
      RECT 226.250 0.000 226.390 0.420 ;
    END
  END rw0_rd_out[230]
  PIN rw0_rd_out[231]
    DIRECTION OUTPUT ;
    USE SIGNAL ;
    SHAPE ABUTMENT ;
    PORT
      LAYER met2 ;
      RECT 226.710 0.000 226.850 0.420 ;
    END
  END rw0_rd_out[231]
  PIN rw0_rd_out[232]
    DIRECTION OUTPUT ;
    USE SIGNAL ;
    SHAPE ABUTMENT ;
    PORT
      LAYER met2 ;
      RECT 227.170 0.000 227.310 0.420 ;
    END
  END rw0_rd_out[232]
  PIN rw0_rd_out[233]
    DIRECTION OUTPUT ;
    USE SIGNAL ;
    SHAPE ABUTMENT ;
    PORT
      LAYER met2 ;
      RECT 227.630 0.000 227.770 0.420 ;
    END
  END rw0_rd_out[233]
  PIN rw0_rd_out[234]
    DIRECTION OUTPUT ;
    USE SIGNAL ;
    SHAPE ABUTMENT ;
    PORT
      LAYER met2 ;
      RECT 228.090 0.000 228.230 0.420 ;
    END
  END rw0_rd_out[234]
  PIN rw0_rd_out[235]
    DIRECTION OUTPUT ;
    USE SIGNAL ;
    SHAPE ABUTMENT ;
    PORT
      LAYER met2 ;
      RECT 228.550 0.000 228.690 0.420 ;
    END
  END rw0_rd_out[235]
  PIN rw0_rd_out[236]
    DIRECTION OUTPUT ;
    USE SIGNAL ;
    SHAPE ABUTMENT ;
    PORT
      LAYER met2 ;
      RECT 229.010 0.000 229.150 0.420 ;
    END
  END rw0_rd_out[236]
  PIN rw0_rd_out[237]
    DIRECTION OUTPUT ;
    USE SIGNAL ;
    SHAPE ABUTMENT ;
    PORT
      LAYER met2 ;
      RECT 229.470 0.000 229.610 0.420 ;
    END
  END rw0_rd_out[237]
  PIN rw0_rd_out[238]
    DIRECTION OUTPUT ;
    USE SIGNAL ;
    SHAPE ABUTMENT ;
    PORT
      LAYER met2 ;
      RECT 229.930 0.000 230.070 0.420 ;
    END
  END rw0_rd_out[238]
  PIN rw0_rd_out[239]
    DIRECTION OUTPUT ;
    USE SIGNAL ;
    SHAPE ABUTMENT ;
    PORT
      LAYER met2 ;
      RECT 230.390 0.000 230.530 0.420 ;
    END
  END rw0_rd_out[239]
  PIN rw0_rd_out[240]
    DIRECTION OUTPUT ;
    USE SIGNAL ;
    SHAPE ABUTMENT ;
    PORT
      LAYER met2 ;
      RECT 230.850 0.000 230.990 0.420 ;
    END
  END rw0_rd_out[240]
  PIN rw0_rd_out[241]
    DIRECTION OUTPUT ;
    USE SIGNAL ;
    SHAPE ABUTMENT ;
    PORT
      LAYER met2 ;
      RECT 231.310 0.000 231.450 0.420 ;
    END
  END rw0_rd_out[241]
  PIN rw0_rd_out[242]
    DIRECTION OUTPUT ;
    USE SIGNAL ;
    SHAPE ABUTMENT ;
    PORT
      LAYER met2 ;
      RECT 231.770 0.000 231.910 0.420 ;
    END
  END rw0_rd_out[242]
  PIN rw0_rd_out[243]
    DIRECTION OUTPUT ;
    USE SIGNAL ;
    SHAPE ABUTMENT ;
    PORT
      LAYER met2 ;
      RECT 232.230 0.000 232.370 0.420 ;
    END
  END rw0_rd_out[243]
  PIN rw0_rd_out[244]
    DIRECTION OUTPUT ;
    USE SIGNAL ;
    SHAPE ABUTMENT ;
    PORT
      LAYER met2 ;
      RECT 232.690 0.000 232.830 0.420 ;
    END
  END rw0_rd_out[244]
  PIN rw0_rd_out[245]
    DIRECTION OUTPUT ;
    USE SIGNAL ;
    SHAPE ABUTMENT ;
    PORT
      LAYER met2 ;
      RECT 233.150 0.000 233.290 0.420 ;
    END
  END rw0_rd_out[245]
  PIN rw0_rd_out[246]
    DIRECTION OUTPUT ;
    USE SIGNAL ;
    SHAPE ABUTMENT ;
    PORT
      LAYER met2 ;
      RECT 233.610 0.000 233.750 0.420 ;
    END
  END rw0_rd_out[246]
  PIN rw0_rd_out[247]
    DIRECTION OUTPUT ;
    USE SIGNAL ;
    SHAPE ABUTMENT ;
    PORT
      LAYER met2 ;
      RECT 234.070 0.000 234.210 0.420 ;
    END
  END rw0_rd_out[247]
  PIN rw0_rd_out[248]
    DIRECTION OUTPUT ;
    USE SIGNAL ;
    SHAPE ABUTMENT ;
    PORT
      LAYER met2 ;
      RECT 234.530 0.000 234.670 0.420 ;
    END
  END rw0_rd_out[248]
  PIN rw0_rd_out[249]
    DIRECTION OUTPUT ;
    USE SIGNAL ;
    SHAPE ABUTMENT ;
    PORT
      LAYER met2 ;
      RECT 234.990 0.000 235.130 0.420 ;
    END
  END rw0_rd_out[249]
  PIN rw0_rd_out[250]
    DIRECTION OUTPUT ;
    USE SIGNAL ;
    SHAPE ABUTMENT ;
    PORT
      LAYER met2 ;
      RECT 235.450 0.000 235.590 0.420 ;
    END
  END rw0_rd_out[250]
  PIN rw0_rd_out[251]
    DIRECTION OUTPUT ;
    USE SIGNAL ;
    SHAPE ABUTMENT ;
    PORT
      LAYER met2 ;
      RECT 235.910 0.000 236.050 0.420 ;
    END
  END rw0_rd_out[251]
  PIN rw0_rd_out[252]
    DIRECTION OUTPUT ;
    USE SIGNAL ;
    SHAPE ABUTMENT ;
    PORT
      LAYER met2 ;
      RECT 236.370 0.000 236.510 0.420 ;
    END
  END rw0_rd_out[252]
  PIN rw0_rd_out[253]
    DIRECTION OUTPUT ;
    USE SIGNAL ;
    SHAPE ABUTMENT ;
    PORT
      LAYER met2 ;
      RECT 236.830 0.000 236.970 0.420 ;
    END
  END rw0_rd_out[253]
  PIN rw0_rd_out[254]
    DIRECTION OUTPUT ;
    USE SIGNAL ;
    SHAPE ABUTMENT ;
    PORT
      LAYER met2 ;
      RECT 237.290 0.000 237.430 0.420 ;
    END
  END rw0_rd_out[254]
  PIN rw0_rd_out[255]
    DIRECTION OUTPUT ;
    USE SIGNAL ;
    SHAPE ABUTMENT ;
    PORT
      LAYER met2 ;
      RECT 237.750 0.000 237.890 0.420 ;
    END
  END rw0_rd_out[255]
  PIN rw0_rd_out[256]
    DIRECTION OUTPUT ;
    USE SIGNAL ;
    SHAPE ABUTMENT ;
    PORT
      LAYER met2 ;
      RECT 120.450 954.300 120.590 954.720 ;
    END
  END rw0_rd_out[256]
  PIN rw0_rd_out[257]
    DIRECTION OUTPUT ;
    USE SIGNAL ;
    SHAPE ABUTMENT ;
    PORT
      LAYER met2 ;
      RECT 120.910 954.300 121.050 954.720 ;
    END
  END rw0_rd_out[257]
  PIN rw0_rd_out[258]
    DIRECTION OUTPUT ;
    USE SIGNAL ;
    SHAPE ABUTMENT ;
    PORT
      LAYER met2 ;
      RECT 121.370 954.300 121.510 954.720 ;
    END
  END rw0_rd_out[258]
  PIN rw0_rd_out[259]
    DIRECTION OUTPUT ;
    USE SIGNAL ;
    SHAPE ABUTMENT ;
    PORT
      LAYER met2 ;
      RECT 121.830 954.300 121.970 954.720 ;
    END
  END rw0_rd_out[259]
  PIN rw0_rd_out[260]
    DIRECTION OUTPUT ;
    USE SIGNAL ;
    SHAPE ABUTMENT ;
    PORT
      LAYER met2 ;
      RECT 122.290 954.300 122.430 954.720 ;
    END
  END rw0_rd_out[260]
  PIN rw0_rd_out[261]
    DIRECTION OUTPUT ;
    USE SIGNAL ;
    SHAPE ABUTMENT ;
    PORT
      LAYER met2 ;
      RECT 122.750 954.300 122.890 954.720 ;
    END
  END rw0_rd_out[261]
  PIN rw0_rd_out[262]
    DIRECTION OUTPUT ;
    USE SIGNAL ;
    SHAPE ABUTMENT ;
    PORT
      LAYER met2 ;
      RECT 123.210 954.300 123.350 954.720 ;
    END
  END rw0_rd_out[262]
  PIN rw0_rd_out[263]
    DIRECTION OUTPUT ;
    USE SIGNAL ;
    SHAPE ABUTMENT ;
    PORT
      LAYER met2 ;
      RECT 123.670 954.300 123.810 954.720 ;
    END
  END rw0_rd_out[263]
  PIN rw0_rd_out[264]
    DIRECTION OUTPUT ;
    USE SIGNAL ;
    SHAPE ABUTMENT ;
    PORT
      LAYER met2 ;
      RECT 124.130 954.300 124.270 954.720 ;
    END
  END rw0_rd_out[264]
  PIN rw0_rd_out[265]
    DIRECTION OUTPUT ;
    USE SIGNAL ;
    SHAPE ABUTMENT ;
    PORT
      LAYER met2 ;
      RECT 124.590 954.300 124.730 954.720 ;
    END
  END rw0_rd_out[265]
  PIN rw0_rd_out[266]
    DIRECTION OUTPUT ;
    USE SIGNAL ;
    SHAPE ABUTMENT ;
    PORT
      LAYER met2 ;
      RECT 125.050 954.300 125.190 954.720 ;
    END
  END rw0_rd_out[266]
  PIN rw0_rd_out[267]
    DIRECTION OUTPUT ;
    USE SIGNAL ;
    SHAPE ABUTMENT ;
    PORT
      LAYER met2 ;
      RECT 125.510 954.300 125.650 954.720 ;
    END
  END rw0_rd_out[267]
  PIN rw0_rd_out[268]
    DIRECTION OUTPUT ;
    USE SIGNAL ;
    SHAPE ABUTMENT ;
    PORT
      LAYER met2 ;
      RECT 125.970 954.300 126.110 954.720 ;
    END
  END rw0_rd_out[268]
  PIN rw0_rd_out[269]
    DIRECTION OUTPUT ;
    USE SIGNAL ;
    SHAPE ABUTMENT ;
    PORT
      LAYER met2 ;
      RECT 126.430 954.300 126.570 954.720 ;
    END
  END rw0_rd_out[269]
  PIN rw0_rd_out[270]
    DIRECTION OUTPUT ;
    USE SIGNAL ;
    SHAPE ABUTMENT ;
    PORT
      LAYER met2 ;
      RECT 126.890 954.300 127.030 954.720 ;
    END
  END rw0_rd_out[270]
  PIN rw0_rd_out[271]
    DIRECTION OUTPUT ;
    USE SIGNAL ;
    SHAPE ABUTMENT ;
    PORT
      LAYER met2 ;
      RECT 127.350 954.300 127.490 954.720 ;
    END
  END rw0_rd_out[271]
  PIN rw0_rd_out[272]
    DIRECTION OUTPUT ;
    USE SIGNAL ;
    SHAPE ABUTMENT ;
    PORT
      LAYER met2 ;
      RECT 127.810 954.300 127.950 954.720 ;
    END
  END rw0_rd_out[272]
  PIN rw0_rd_out[273]
    DIRECTION OUTPUT ;
    USE SIGNAL ;
    SHAPE ABUTMENT ;
    PORT
      LAYER met2 ;
      RECT 128.270 954.300 128.410 954.720 ;
    END
  END rw0_rd_out[273]
  PIN rw0_rd_out[274]
    DIRECTION OUTPUT ;
    USE SIGNAL ;
    SHAPE ABUTMENT ;
    PORT
      LAYER met2 ;
      RECT 128.730 954.300 128.870 954.720 ;
    END
  END rw0_rd_out[274]
  PIN rw0_rd_out[275]
    DIRECTION OUTPUT ;
    USE SIGNAL ;
    SHAPE ABUTMENT ;
    PORT
      LAYER met2 ;
      RECT 129.190 954.300 129.330 954.720 ;
    END
  END rw0_rd_out[275]
  PIN rw0_rd_out[276]
    DIRECTION OUTPUT ;
    USE SIGNAL ;
    SHAPE ABUTMENT ;
    PORT
      LAYER met2 ;
      RECT 129.650 954.300 129.790 954.720 ;
    END
  END rw0_rd_out[276]
  PIN rw0_rd_out[277]
    DIRECTION OUTPUT ;
    USE SIGNAL ;
    SHAPE ABUTMENT ;
    PORT
      LAYER met2 ;
      RECT 130.110 954.300 130.250 954.720 ;
    END
  END rw0_rd_out[277]
  PIN rw0_rd_out[278]
    DIRECTION OUTPUT ;
    USE SIGNAL ;
    SHAPE ABUTMENT ;
    PORT
      LAYER met2 ;
      RECT 130.570 954.300 130.710 954.720 ;
    END
  END rw0_rd_out[278]
  PIN rw0_rd_out[279]
    DIRECTION OUTPUT ;
    USE SIGNAL ;
    SHAPE ABUTMENT ;
    PORT
      LAYER met2 ;
      RECT 131.030 954.300 131.170 954.720 ;
    END
  END rw0_rd_out[279]
  PIN rw0_rd_out[280]
    DIRECTION OUTPUT ;
    USE SIGNAL ;
    SHAPE ABUTMENT ;
    PORT
      LAYER met2 ;
      RECT 131.490 954.300 131.630 954.720 ;
    END
  END rw0_rd_out[280]
  PIN rw0_rd_out[281]
    DIRECTION OUTPUT ;
    USE SIGNAL ;
    SHAPE ABUTMENT ;
    PORT
      LAYER met2 ;
      RECT 131.950 954.300 132.090 954.720 ;
    END
  END rw0_rd_out[281]
  PIN rw0_rd_out[282]
    DIRECTION OUTPUT ;
    USE SIGNAL ;
    SHAPE ABUTMENT ;
    PORT
      LAYER met2 ;
      RECT 132.410 954.300 132.550 954.720 ;
    END
  END rw0_rd_out[282]
  PIN rw0_rd_out[283]
    DIRECTION OUTPUT ;
    USE SIGNAL ;
    SHAPE ABUTMENT ;
    PORT
      LAYER met2 ;
      RECT 132.870 954.300 133.010 954.720 ;
    END
  END rw0_rd_out[283]
  PIN rw0_rd_out[284]
    DIRECTION OUTPUT ;
    USE SIGNAL ;
    SHAPE ABUTMENT ;
    PORT
      LAYER met2 ;
      RECT 133.330 954.300 133.470 954.720 ;
    END
  END rw0_rd_out[284]
  PIN rw0_rd_out[285]
    DIRECTION OUTPUT ;
    USE SIGNAL ;
    SHAPE ABUTMENT ;
    PORT
      LAYER met2 ;
      RECT 133.790 954.300 133.930 954.720 ;
    END
  END rw0_rd_out[285]
  PIN rw0_rd_out[286]
    DIRECTION OUTPUT ;
    USE SIGNAL ;
    SHAPE ABUTMENT ;
    PORT
      LAYER met2 ;
      RECT 134.250 954.300 134.390 954.720 ;
    END
  END rw0_rd_out[286]
  PIN rw0_rd_out[287]
    DIRECTION OUTPUT ;
    USE SIGNAL ;
    SHAPE ABUTMENT ;
    PORT
      LAYER met2 ;
      RECT 134.710 954.300 134.850 954.720 ;
    END
  END rw0_rd_out[287]
  PIN rw0_rd_out[288]
    DIRECTION OUTPUT ;
    USE SIGNAL ;
    SHAPE ABUTMENT ;
    PORT
      LAYER met2 ;
      RECT 135.170 954.300 135.310 954.720 ;
    END
  END rw0_rd_out[288]
  PIN rw0_rd_out[289]
    DIRECTION OUTPUT ;
    USE SIGNAL ;
    SHAPE ABUTMENT ;
    PORT
      LAYER met2 ;
      RECT 135.630 954.300 135.770 954.720 ;
    END
  END rw0_rd_out[289]
  PIN rw0_rd_out[290]
    DIRECTION OUTPUT ;
    USE SIGNAL ;
    SHAPE ABUTMENT ;
    PORT
      LAYER met2 ;
      RECT 136.090 954.300 136.230 954.720 ;
    END
  END rw0_rd_out[290]
  PIN rw0_rd_out[291]
    DIRECTION OUTPUT ;
    USE SIGNAL ;
    SHAPE ABUTMENT ;
    PORT
      LAYER met2 ;
      RECT 136.550 954.300 136.690 954.720 ;
    END
  END rw0_rd_out[291]
  PIN rw0_rd_out[292]
    DIRECTION OUTPUT ;
    USE SIGNAL ;
    SHAPE ABUTMENT ;
    PORT
      LAYER met2 ;
      RECT 137.010 954.300 137.150 954.720 ;
    END
  END rw0_rd_out[292]
  PIN rw0_rd_out[293]
    DIRECTION OUTPUT ;
    USE SIGNAL ;
    SHAPE ABUTMENT ;
    PORT
      LAYER met2 ;
      RECT 137.470 954.300 137.610 954.720 ;
    END
  END rw0_rd_out[293]
  PIN rw0_rd_out[294]
    DIRECTION OUTPUT ;
    USE SIGNAL ;
    SHAPE ABUTMENT ;
    PORT
      LAYER met2 ;
      RECT 137.930 954.300 138.070 954.720 ;
    END
  END rw0_rd_out[294]
  PIN rw0_rd_out[295]
    DIRECTION OUTPUT ;
    USE SIGNAL ;
    SHAPE ABUTMENT ;
    PORT
      LAYER met2 ;
      RECT 138.390 954.300 138.530 954.720 ;
    END
  END rw0_rd_out[295]
  PIN rw0_rd_out[296]
    DIRECTION OUTPUT ;
    USE SIGNAL ;
    SHAPE ABUTMENT ;
    PORT
      LAYER met2 ;
      RECT 138.850 954.300 138.990 954.720 ;
    END
  END rw0_rd_out[296]
  PIN rw0_rd_out[297]
    DIRECTION OUTPUT ;
    USE SIGNAL ;
    SHAPE ABUTMENT ;
    PORT
      LAYER met2 ;
      RECT 139.310 954.300 139.450 954.720 ;
    END
  END rw0_rd_out[297]
  PIN rw0_rd_out[298]
    DIRECTION OUTPUT ;
    USE SIGNAL ;
    SHAPE ABUTMENT ;
    PORT
      LAYER met2 ;
      RECT 139.770 954.300 139.910 954.720 ;
    END
  END rw0_rd_out[298]
  PIN rw0_rd_out[299]
    DIRECTION OUTPUT ;
    USE SIGNAL ;
    SHAPE ABUTMENT ;
    PORT
      LAYER met2 ;
      RECT 140.230 954.300 140.370 954.720 ;
    END
  END rw0_rd_out[299]
  PIN rw0_rd_out[300]
    DIRECTION OUTPUT ;
    USE SIGNAL ;
    SHAPE ABUTMENT ;
    PORT
      LAYER met2 ;
      RECT 140.690 954.300 140.830 954.720 ;
    END
  END rw0_rd_out[300]
  PIN rw0_rd_out[301]
    DIRECTION OUTPUT ;
    USE SIGNAL ;
    SHAPE ABUTMENT ;
    PORT
      LAYER met2 ;
      RECT 141.150 954.300 141.290 954.720 ;
    END
  END rw0_rd_out[301]
  PIN rw0_rd_out[302]
    DIRECTION OUTPUT ;
    USE SIGNAL ;
    SHAPE ABUTMENT ;
    PORT
      LAYER met2 ;
      RECT 141.610 954.300 141.750 954.720 ;
    END
  END rw0_rd_out[302]
  PIN rw0_rd_out[303]
    DIRECTION OUTPUT ;
    USE SIGNAL ;
    SHAPE ABUTMENT ;
    PORT
      LAYER met2 ;
      RECT 142.070 954.300 142.210 954.720 ;
    END
  END rw0_rd_out[303]
  PIN rw0_rd_out[304]
    DIRECTION OUTPUT ;
    USE SIGNAL ;
    SHAPE ABUTMENT ;
    PORT
      LAYER met2 ;
      RECT 142.530 954.300 142.670 954.720 ;
    END
  END rw0_rd_out[304]
  PIN rw0_rd_out[305]
    DIRECTION OUTPUT ;
    USE SIGNAL ;
    SHAPE ABUTMENT ;
    PORT
      LAYER met2 ;
      RECT 142.990 954.300 143.130 954.720 ;
    END
  END rw0_rd_out[305]
  PIN rw0_rd_out[306]
    DIRECTION OUTPUT ;
    USE SIGNAL ;
    SHAPE ABUTMENT ;
    PORT
      LAYER met2 ;
      RECT 143.450 954.300 143.590 954.720 ;
    END
  END rw0_rd_out[306]
  PIN rw0_rd_out[307]
    DIRECTION OUTPUT ;
    USE SIGNAL ;
    SHAPE ABUTMENT ;
    PORT
      LAYER met2 ;
      RECT 143.910 954.300 144.050 954.720 ;
    END
  END rw0_rd_out[307]
  PIN rw0_rd_out[308]
    DIRECTION OUTPUT ;
    USE SIGNAL ;
    SHAPE ABUTMENT ;
    PORT
      LAYER met2 ;
      RECT 144.370 954.300 144.510 954.720 ;
    END
  END rw0_rd_out[308]
  PIN rw0_rd_out[309]
    DIRECTION OUTPUT ;
    USE SIGNAL ;
    SHAPE ABUTMENT ;
    PORT
      LAYER met2 ;
      RECT 144.830 954.300 144.970 954.720 ;
    END
  END rw0_rd_out[309]
  PIN rw0_rd_out[310]
    DIRECTION OUTPUT ;
    USE SIGNAL ;
    SHAPE ABUTMENT ;
    PORT
      LAYER met2 ;
      RECT 145.290 954.300 145.430 954.720 ;
    END
  END rw0_rd_out[310]
  PIN rw0_rd_out[311]
    DIRECTION OUTPUT ;
    USE SIGNAL ;
    SHAPE ABUTMENT ;
    PORT
      LAYER met2 ;
      RECT 145.750 954.300 145.890 954.720 ;
    END
  END rw0_rd_out[311]
  PIN rw0_rd_out[312]
    DIRECTION OUTPUT ;
    USE SIGNAL ;
    SHAPE ABUTMENT ;
    PORT
      LAYER met2 ;
      RECT 146.210 954.300 146.350 954.720 ;
    END
  END rw0_rd_out[312]
  PIN rw0_rd_out[313]
    DIRECTION OUTPUT ;
    USE SIGNAL ;
    SHAPE ABUTMENT ;
    PORT
      LAYER met2 ;
      RECT 146.670 954.300 146.810 954.720 ;
    END
  END rw0_rd_out[313]
  PIN rw0_rd_out[314]
    DIRECTION OUTPUT ;
    USE SIGNAL ;
    SHAPE ABUTMENT ;
    PORT
      LAYER met2 ;
      RECT 147.130 954.300 147.270 954.720 ;
    END
  END rw0_rd_out[314]
  PIN rw0_rd_out[315]
    DIRECTION OUTPUT ;
    USE SIGNAL ;
    SHAPE ABUTMENT ;
    PORT
      LAYER met2 ;
      RECT 147.590 954.300 147.730 954.720 ;
    END
  END rw0_rd_out[315]
  PIN rw0_rd_out[316]
    DIRECTION OUTPUT ;
    USE SIGNAL ;
    SHAPE ABUTMENT ;
    PORT
      LAYER met2 ;
      RECT 148.050 954.300 148.190 954.720 ;
    END
  END rw0_rd_out[316]
  PIN rw0_rd_out[317]
    DIRECTION OUTPUT ;
    USE SIGNAL ;
    SHAPE ABUTMENT ;
    PORT
      LAYER met2 ;
      RECT 148.510 954.300 148.650 954.720 ;
    END
  END rw0_rd_out[317]
  PIN rw0_rd_out[318]
    DIRECTION OUTPUT ;
    USE SIGNAL ;
    SHAPE ABUTMENT ;
    PORT
      LAYER met2 ;
      RECT 148.970 954.300 149.110 954.720 ;
    END
  END rw0_rd_out[318]
  PIN rw0_rd_out[319]
    DIRECTION OUTPUT ;
    USE SIGNAL ;
    SHAPE ABUTMENT ;
    PORT
      LAYER met2 ;
      RECT 149.430 954.300 149.570 954.720 ;
    END
  END rw0_rd_out[319]
  PIN rw0_rd_out[320]
    DIRECTION OUTPUT ;
    USE SIGNAL ;
    SHAPE ABUTMENT ;
    PORT
      LAYER met2 ;
      RECT 149.890 954.300 150.030 954.720 ;
    END
  END rw0_rd_out[320]
  PIN rw0_rd_out[321]
    DIRECTION OUTPUT ;
    USE SIGNAL ;
    SHAPE ABUTMENT ;
    PORT
      LAYER met2 ;
      RECT 150.350 954.300 150.490 954.720 ;
    END
  END rw0_rd_out[321]
  PIN rw0_rd_out[322]
    DIRECTION OUTPUT ;
    USE SIGNAL ;
    SHAPE ABUTMENT ;
    PORT
      LAYER met2 ;
      RECT 150.810 954.300 150.950 954.720 ;
    END
  END rw0_rd_out[322]
  PIN rw0_rd_out[323]
    DIRECTION OUTPUT ;
    USE SIGNAL ;
    SHAPE ABUTMENT ;
    PORT
      LAYER met2 ;
      RECT 151.270 954.300 151.410 954.720 ;
    END
  END rw0_rd_out[323]
  PIN rw0_rd_out[324]
    DIRECTION OUTPUT ;
    USE SIGNAL ;
    SHAPE ABUTMENT ;
    PORT
      LAYER met2 ;
      RECT 151.730 954.300 151.870 954.720 ;
    END
  END rw0_rd_out[324]
  PIN rw0_rd_out[325]
    DIRECTION OUTPUT ;
    USE SIGNAL ;
    SHAPE ABUTMENT ;
    PORT
      LAYER met2 ;
      RECT 152.190 954.300 152.330 954.720 ;
    END
  END rw0_rd_out[325]
  PIN rw0_rd_out[326]
    DIRECTION OUTPUT ;
    USE SIGNAL ;
    SHAPE ABUTMENT ;
    PORT
      LAYER met2 ;
      RECT 152.650 954.300 152.790 954.720 ;
    END
  END rw0_rd_out[326]
  PIN rw0_rd_out[327]
    DIRECTION OUTPUT ;
    USE SIGNAL ;
    SHAPE ABUTMENT ;
    PORT
      LAYER met2 ;
      RECT 153.110 954.300 153.250 954.720 ;
    END
  END rw0_rd_out[327]
  PIN rw0_rd_out[328]
    DIRECTION OUTPUT ;
    USE SIGNAL ;
    SHAPE ABUTMENT ;
    PORT
      LAYER met2 ;
      RECT 153.570 954.300 153.710 954.720 ;
    END
  END rw0_rd_out[328]
  PIN rw0_rd_out[329]
    DIRECTION OUTPUT ;
    USE SIGNAL ;
    SHAPE ABUTMENT ;
    PORT
      LAYER met2 ;
      RECT 154.030 954.300 154.170 954.720 ;
    END
  END rw0_rd_out[329]
  PIN rw0_rd_out[330]
    DIRECTION OUTPUT ;
    USE SIGNAL ;
    SHAPE ABUTMENT ;
    PORT
      LAYER met2 ;
      RECT 154.490 954.300 154.630 954.720 ;
    END
  END rw0_rd_out[330]
  PIN rw0_rd_out[331]
    DIRECTION OUTPUT ;
    USE SIGNAL ;
    SHAPE ABUTMENT ;
    PORT
      LAYER met2 ;
      RECT 154.950 954.300 155.090 954.720 ;
    END
  END rw0_rd_out[331]
  PIN rw0_rd_out[332]
    DIRECTION OUTPUT ;
    USE SIGNAL ;
    SHAPE ABUTMENT ;
    PORT
      LAYER met2 ;
      RECT 155.410 954.300 155.550 954.720 ;
    END
  END rw0_rd_out[332]
  PIN rw0_rd_out[333]
    DIRECTION OUTPUT ;
    USE SIGNAL ;
    SHAPE ABUTMENT ;
    PORT
      LAYER met2 ;
      RECT 155.870 954.300 156.010 954.720 ;
    END
  END rw0_rd_out[333]
  PIN rw0_rd_out[334]
    DIRECTION OUTPUT ;
    USE SIGNAL ;
    SHAPE ABUTMENT ;
    PORT
      LAYER met2 ;
      RECT 156.330 954.300 156.470 954.720 ;
    END
  END rw0_rd_out[334]
  PIN rw0_rd_out[335]
    DIRECTION OUTPUT ;
    USE SIGNAL ;
    SHAPE ABUTMENT ;
    PORT
      LAYER met2 ;
      RECT 156.790 954.300 156.930 954.720 ;
    END
  END rw0_rd_out[335]
  PIN rw0_rd_out[336]
    DIRECTION OUTPUT ;
    USE SIGNAL ;
    SHAPE ABUTMENT ;
    PORT
      LAYER met2 ;
      RECT 157.250 954.300 157.390 954.720 ;
    END
  END rw0_rd_out[336]
  PIN rw0_rd_out[337]
    DIRECTION OUTPUT ;
    USE SIGNAL ;
    SHAPE ABUTMENT ;
    PORT
      LAYER met2 ;
      RECT 157.710 954.300 157.850 954.720 ;
    END
  END rw0_rd_out[337]
  PIN rw0_rd_out[338]
    DIRECTION OUTPUT ;
    USE SIGNAL ;
    SHAPE ABUTMENT ;
    PORT
      LAYER met2 ;
      RECT 158.170 954.300 158.310 954.720 ;
    END
  END rw0_rd_out[338]
  PIN rw0_rd_out[339]
    DIRECTION OUTPUT ;
    USE SIGNAL ;
    SHAPE ABUTMENT ;
    PORT
      LAYER met2 ;
      RECT 158.630 954.300 158.770 954.720 ;
    END
  END rw0_rd_out[339]
  PIN rw0_rd_out[340]
    DIRECTION OUTPUT ;
    USE SIGNAL ;
    SHAPE ABUTMENT ;
    PORT
      LAYER met2 ;
      RECT 159.090 954.300 159.230 954.720 ;
    END
  END rw0_rd_out[340]
  PIN rw0_rd_out[341]
    DIRECTION OUTPUT ;
    USE SIGNAL ;
    SHAPE ABUTMENT ;
    PORT
      LAYER met2 ;
      RECT 159.550 954.300 159.690 954.720 ;
    END
  END rw0_rd_out[341]
  PIN rw0_rd_out[342]
    DIRECTION OUTPUT ;
    USE SIGNAL ;
    SHAPE ABUTMENT ;
    PORT
      LAYER met2 ;
      RECT 160.010 954.300 160.150 954.720 ;
    END
  END rw0_rd_out[342]
  PIN rw0_rd_out[343]
    DIRECTION OUTPUT ;
    USE SIGNAL ;
    SHAPE ABUTMENT ;
    PORT
      LAYER met2 ;
      RECT 160.470 954.300 160.610 954.720 ;
    END
  END rw0_rd_out[343]
  PIN rw0_rd_out[344]
    DIRECTION OUTPUT ;
    USE SIGNAL ;
    SHAPE ABUTMENT ;
    PORT
      LAYER met2 ;
      RECT 160.930 954.300 161.070 954.720 ;
    END
  END rw0_rd_out[344]
  PIN rw0_rd_out[345]
    DIRECTION OUTPUT ;
    USE SIGNAL ;
    SHAPE ABUTMENT ;
    PORT
      LAYER met2 ;
      RECT 161.390 954.300 161.530 954.720 ;
    END
  END rw0_rd_out[345]
  PIN rw0_rd_out[346]
    DIRECTION OUTPUT ;
    USE SIGNAL ;
    SHAPE ABUTMENT ;
    PORT
      LAYER met2 ;
      RECT 161.850 954.300 161.990 954.720 ;
    END
  END rw0_rd_out[346]
  PIN rw0_rd_out[347]
    DIRECTION OUTPUT ;
    USE SIGNAL ;
    SHAPE ABUTMENT ;
    PORT
      LAYER met2 ;
      RECT 162.310 954.300 162.450 954.720 ;
    END
  END rw0_rd_out[347]
  PIN rw0_rd_out[348]
    DIRECTION OUTPUT ;
    USE SIGNAL ;
    SHAPE ABUTMENT ;
    PORT
      LAYER met2 ;
      RECT 162.770 954.300 162.910 954.720 ;
    END
  END rw0_rd_out[348]
  PIN rw0_rd_out[349]
    DIRECTION OUTPUT ;
    USE SIGNAL ;
    SHAPE ABUTMENT ;
    PORT
      LAYER met2 ;
      RECT 163.230 954.300 163.370 954.720 ;
    END
  END rw0_rd_out[349]
  PIN rw0_rd_out[350]
    DIRECTION OUTPUT ;
    USE SIGNAL ;
    SHAPE ABUTMENT ;
    PORT
      LAYER met2 ;
      RECT 163.690 954.300 163.830 954.720 ;
    END
  END rw0_rd_out[350]
  PIN rw0_rd_out[351]
    DIRECTION OUTPUT ;
    USE SIGNAL ;
    SHAPE ABUTMENT ;
    PORT
      LAYER met2 ;
      RECT 164.150 954.300 164.290 954.720 ;
    END
  END rw0_rd_out[351]
  PIN rw0_rd_out[352]
    DIRECTION OUTPUT ;
    USE SIGNAL ;
    SHAPE ABUTMENT ;
    PORT
      LAYER met2 ;
      RECT 164.610 954.300 164.750 954.720 ;
    END
  END rw0_rd_out[352]
  PIN rw0_rd_out[353]
    DIRECTION OUTPUT ;
    USE SIGNAL ;
    SHAPE ABUTMENT ;
    PORT
      LAYER met2 ;
      RECT 165.070 954.300 165.210 954.720 ;
    END
  END rw0_rd_out[353]
  PIN rw0_rd_out[354]
    DIRECTION OUTPUT ;
    USE SIGNAL ;
    SHAPE ABUTMENT ;
    PORT
      LAYER met2 ;
      RECT 165.530 954.300 165.670 954.720 ;
    END
  END rw0_rd_out[354]
  PIN rw0_rd_out[355]
    DIRECTION OUTPUT ;
    USE SIGNAL ;
    SHAPE ABUTMENT ;
    PORT
      LAYER met2 ;
      RECT 165.990 954.300 166.130 954.720 ;
    END
  END rw0_rd_out[355]
  PIN rw0_rd_out[356]
    DIRECTION OUTPUT ;
    USE SIGNAL ;
    SHAPE ABUTMENT ;
    PORT
      LAYER met2 ;
      RECT 166.450 954.300 166.590 954.720 ;
    END
  END rw0_rd_out[356]
  PIN rw0_rd_out[357]
    DIRECTION OUTPUT ;
    USE SIGNAL ;
    SHAPE ABUTMENT ;
    PORT
      LAYER met2 ;
      RECT 166.910 954.300 167.050 954.720 ;
    END
  END rw0_rd_out[357]
  PIN rw0_rd_out[358]
    DIRECTION OUTPUT ;
    USE SIGNAL ;
    SHAPE ABUTMENT ;
    PORT
      LAYER met2 ;
      RECT 167.370 954.300 167.510 954.720 ;
    END
  END rw0_rd_out[358]
  PIN rw0_rd_out[359]
    DIRECTION OUTPUT ;
    USE SIGNAL ;
    SHAPE ABUTMENT ;
    PORT
      LAYER met2 ;
      RECT 167.830 954.300 167.970 954.720 ;
    END
  END rw0_rd_out[359]
  PIN rw0_rd_out[360]
    DIRECTION OUTPUT ;
    USE SIGNAL ;
    SHAPE ABUTMENT ;
    PORT
      LAYER met2 ;
      RECT 168.290 954.300 168.430 954.720 ;
    END
  END rw0_rd_out[360]
  PIN rw0_rd_out[361]
    DIRECTION OUTPUT ;
    USE SIGNAL ;
    SHAPE ABUTMENT ;
    PORT
      LAYER met2 ;
      RECT 168.750 954.300 168.890 954.720 ;
    END
  END rw0_rd_out[361]
  PIN rw0_rd_out[362]
    DIRECTION OUTPUT ;
    USE SIGNAL ;
    SHAPE ABUTMENT ;
    PORT
      LAYER met2 ;
      RECT 169.210 954.300 169.350 954.720 ;
    END
  END rw0_rd_out[362]
  PIN rw0_rd_out[363]
    DIRECTION OUTPUT ;
    USE SIGNAL ;
    SHAPE ABUTMENT ;
    PORT
      LAYER met2 ;
      RECT 169.670 954.300 169.810 954.720 ;
    END
  END rw0_rd_out[363]
  PIN rw0_rd_out[364]
    DIRECTION OUTPUT ;
    USE SIGNAL ;
    SHAPE ABUTMENT ;
    PORT
      LAYER met2 ;
      RECT 170.130 954.300 170.270 954.720 ;
    END
  END rw0_rd_out[364]
  PIN rw0_rd_out[365]
    DIRECTION OUTPUT ;
    USE SIGNAL ;
    SHAPE ABUTMENT ;
    PORT
      LAYER met2 ;
      RECT 170.590 954.300 170.730 954.720 ;
    END
  END rw0_rd_out[365]
  PIN rw0_rd_out[366]
    DIRECTION OUTPUT ;
    USE SIGNAL ;
    SHAPE ABUTMENT ;
    PORT
      LAYER met2 ;
      RECT 171.050 954.300 171.190 954.720 ;
    END
  END rw0_rd_out[366]
  PIN rw0_rd_out[367]
    DIRECTION OUTPUT ;
    USE SIGNAL ;
    SHAPE ABUTMENT ;
    PORT
      LAYER met2 ;
      RECT 171.510 954.300 171.650 954.720 ;
    END
  END rw0_rd_out[367]
  PIN rw0_rd_out[368]
    DIRECTION OUTPUT ;
    USE SIGNAL ;
    SHAPE ABUTMENT ;
    PORT
      LAYER met2 ;
      RECT 171.970 954.300 172.110 954.720 ;
    END
  END rw0_rd_out[368]
  PIN rw0_rd_out[369]
    DIRECTION OUTPUT ;
    USE SIGNAL ;
    SHAPE ABUTMENT ;
    PORT
      LAYER met2 ;
      RECT 172.430 954.300 172.570 954.720 ;
    END
  END rw0_rd_out[369]
  PIN rw0_rd_out[370]
    DIRECTION OUTPUT ;
    USE SIGNAL ;
    SHAPE ABUTMENT ;
    PORT
      LAYER met2 ;
      RECT 172.890 954.300 173.030 954.720 ;
    END
  END rw0_rd_out[370]
  PIN rw0_rd_out[371]
    DIRECTION OUTPUT ;
    USE SIGNAL ;
    SHAPE ABUTMENT ;
    PORT
      LAYER met2 ;
      RECT 173.350 954.300 173.490 954.720 ;
    END
  END rw0_rd_out[371]
  PIN rw0_rd_out[372]
    DIRECTION OUTPUT ;
    USE SIGNAL ;
    SHAPE ABUTMENT ;
    PORT
      LAYER met2 ;
      RECT 173.810 954.300 173.950 954.720 ;
    END
  END rw0_rd_out[372]
  PIN rw0_rd_out[373]
    DIRECTION OUTPUT ;
    USE SIGNAL ;
    SHAPE ABUTMENT ;
    PORT
      LAYER met2 ;
      RECT 174.270 954.300 174.410 954.720 ;
    END
  END rw0_rd_out[373]
  PIN rw0_rd_out[374]
    DIRECTION OUTPUT ;
    USE SIGNAL ;
    SHAPE ABUTMENT ;
    PORT
      LAYER met2 ;
      RECT 174.730 954.300 174.870 954.720 ;
    END
  END rw0_rd_out[374]
  PIN rw0_rd_out[375]
    DIRECTION OUTPUT ;
    USE SIGNAL ;
    SHAPE ABUTMENT ;
    PORT
      LAYER met2 ;
      RECT 175.190 954.300 175.330 954.720 ;
    END
  END rw0_rd_out[375]
  PIN rw0_rd_out[376]
    DIRECTION OUTPUT ;
    USE SIGNAL ;
    SHAPE ABUTMENT ;
    PORT
      LAYER met2 ;
      RECT 175.650 954.300 175.790 954.720 ;
    END
  END rw0_rd_out[376]
  PIN rw0_rd_out[377]
    DIRECTION OUTPUT ;
    USE SIGNAL ;
    SHAPE ABUTMENT ;
    PORT
      LAYER met2 ;
      RECT 176.110 954.300 176.250 954.720 ;
    END
  END rw0_rd_out[377]
  PIN rw0_rd_out[378]
    DIRECTION OUTPUT ;
    USE SIGNAL ;
    SHAPE ABUTMENT ;
    PORT
      LAYER met2 ;
      RECT 176.570 954.300 176.710 954.720 ;
    END
  END rw0_rd_out[378]
  PIN rw0_rd_out[379]
    DIRECTION OUTPUT ;
    USE SIGNAL ;
    SHAPE ABUTMENT ;
    PORT
      LAYER met2 ;
      RECT 177.030 954.300 177.170 954.720 ;
    END
  END rw0_rd_out[379]
  PIN rw0_rd_out[380]
    DIRECTION OUTPUT ;
    USE SIGNAL ;
    SHAPE ABUTMENT ;
    PORT
      LAYER met2 ;
      RECT 177.490 954.300 177.630 954.720 ;
    END
  END rw0_rd_out[380]
  PIN rw0_rd_out[381]
    DIRECTION OUTPUT ;
    USE SIGNAL ;
    SHAPE ABUTMENT ;
    PORT
      LAYER met2 ;
      RECT 177.950 954.300 178.090 954.720 ;
    END
  END rw0_rd_out[381]
  PIN rw0_rd_out[382]
    DIRECTION OUTPUT ;
    USE SIGNAL ;
    SHAPE ABUTMENT ;
    PORT
      LAYER met2 ;
      RECT 178.410 954.300 178.550 954.720 ;
    END
  END rw0_rd_out[382]
  PIN rw0_rd_out[383]
    DIRECTION OUTPUT ;
    USE SIGNAL ;
    SHAPE ABUTMENT ;
    PORT
      LAYER met2 ;
      RECT 178.870 954.300 179.010 954.720 ;
    END
  END rw0_rd_out[383]
  PIN rw0_rd_out[384]
    DIRECTION OUTPUT ;
    USE SIGNAL ;
    SHAPE ABUTMENT ;
    PORT
      LAYER met2 ;
      RECT 179.330 954.300 179.470 954.720 ;
    END
  END rw0_rd_out[384]
  PIN rw0_rd_out[385]
    DIRECTION OUTPUT ;
    USE SIGNAL ;
    SHAPE ABUTMENT ;
    PORT
      LAYER met2 ;
      RECT 179.790 954.300 179.930 954.720 ;
    END
  END rw0_rd_out[385]
  PIN rw0_rd_out[386]
    DIRECTION OUTPUT ;
    USE SIGNAL ;
    SHAPE ABUTMENT ;
    PORT
      LAYER met2 ;
      RECT 180.250 954.300 180.390 954.720 ;
    END
  END rw0_rd_out[386]
  PIN rw0_rd_out[387]
    DIRECTION OUTPUT ;
    USE SIGNAL ;
    SHAPE ABUTMENT ;
    PORT
      LAYER met2 ;
      RECT 180.710 954.300 180.850 954.720 ;
    END
  END rw0_rd_out[387]
  PIN rw0_rd_out[388]
    DIRECTION OUTPUT ;
    USE SIGNAL ;
    SHAPE ABUTMENT ;
    PORT
      LAYER met2 ;
      RECT 181.170 954.300 181.310 954.720 ;
    END
  END rw0_rd_out[388]
  PIN rw0_rd_out[389]
    DIRECTION OUTPUT ;
    USE SIGNAL ;
    SHAPE ABUTMENT ;
    PORT
      LAYER met2 ;
      RECT 181.630 954.300 181.770 954.720 ;
    END
  END rw0_rd_out[389]
  PIN rw0_rd_out[390]
    DIRECTION OUTPUT ;
    USE SIGNAL ;
    SHAPE ABUTMENT ;
    PORT
      LAYER met2 ;
      RECT 182.090 954.300 182.230 954.720 ;
    END
  END rw0_rd_out[390]
  PIN rw0_rd_out[391]
    DIRECTION OUTPUT ;
    USE SIGNAL ;
    SHAPE ABUTMENT ;
    PORT
      LAYER met2 ;
      RECT 182.550 954.300 182.690 954.720 ;
    END
  END rw0_rd_out[391]
  PIN rw0_rd_out[392]
    DIRECTION OUTPUT ;
    USE SIGNAL ;
    SHAPE ABUTMENT ;
    PORT
      LAYER met2 ;
      RECT 183.010 954.300 183.150 954.720 ;
    END
  END rw0_rd_out[392]
  PIN rw0_rd_out[393]
    DIRECTION OUTPUT ;
    USE SIGNAL ;
    SHAPE ABUTMENT ;
    PORT
      LAYER met2 ;
      RECT 183.470 954.300 183.610 954.720 ;
    END
  END rw0_rd_out[393]
  PIN rw0_rd_out[394]
    DIRECTION OUTPUT ;
    USE SIGNAL ;
    SHAPE ABUTMENT ;
    PORT
      LAYER met2 ;
      RECT 183.930 954.300 184.070 954.720 ;
    END
  END rw0_rd_out[394]
  PIN rw0_rd_out[395]
    DIRECTION OUTPUT ;
    USE SIGNAL ;
    SHAPE ABUTMENT ;
    PORT
      LAYER met2 ;
      RECT 184.390 954.300 184.530 954.720 ;
    END
  END rw0_rd_out[395]
  PIN rw0_rd_out[396]
    DIRECTION OUTPUT ;
    USE SIGNAL ;
    SHAPE ABUTMENT ;
    PORT
      LAYER met2 ;
      RECT 184.850 954.300 184.990 954.720 ;
    END
  END rw0_rd_out[396]
  PIN rw0_rd_out[397]
    DIRECTION OUTPUT ;
    USE SIGNAL ;
    SHAPE ABUTMENT ;
    PORT
      LAYER met2 ;
      RECT 185.310 954.300 185.450 954.720 ;
    END
  END rw0_rd_out[397]
  PIN rw0_rd_out[398]
    DIRECTION OUTPUT ;
    USE SIGNAL ;
    SHAPE ABUTMENT ;
    PORT
      LAYER met2 ;
      RECT 185.770 954.300 185.910 954.720 ;
    END
  END rw0_rd_out[398]
  PIN rw0_rd_out[399]
    DIRECTION OUTPUT ;
    USE SIGNAL ;
    SHAPE ABUTMENT ;
    PORT
      LAYER met2 ;
      RECT 186.230 954.300 186.370 954.720 ;
    END
  END rw0_rd_out[399]
  PIN rw0_rd_out[400]
    DIRECTION OUTPUT ;
    USE SIGNAL ;
    SHAPE ABUTMENT ;
    PORT
      LAYER met2 ;
      RECT 186.690 954.300 186.830 954.720 ;
    END
  END rw0_rd_out[400]
  PIN rw0_rd_out[401]
    DIRECTION OUTPUT ;
    USE SIGNAL ;
    SHAPE ABUTMENT ;
    PORT
      LAYER met2 ;
      RECT 187.150 954.300 187.290 954.720 ;
    END
  END rw0_rd_out[401]
  PIN rw0_rd_out[402]
    DIRECTION OUTPUT ;
    USE SIGNAL ;
    SHAPE ABUTMENT ;
    PORT
      LAYER met2 ;
      RECT 187.610 954.300 187.750 954.720 ;
    END
  END rw0_rd_out[402]
  PIN rw0_rd_out[403]
    DIRECTION OUTPUT ;
    USE SIGNAL ;
    SHAPE ABUTMENT ;
    PORT
      LAYER met2 ;
      RECT 188.070 954.300 188.210 954.720 ;
    END
  END rw0_rd_out[403]
  PIN rw0_rd_out[404]
    DIRECTION OUTPUT ;
    USE SIGNAL ;
    SHAPE ABUTMENT ;
    PORT
      LAYER met2 ;
      RECT 188.530 954.300 188.670 954.720 ;
    END
  END rw0_rd_out[404]
  PIN rw0_rd_out[405]
    DIRECTION OUTPUT ;
    USE SIGNAL ;
    SHAPE ABUTMENT ;
    PORT
      LAYER met2 ;
      RECT 188.990 954.300 189.130 954.720 ;
    END
  END rw0_rd_out[405]
  PIN rw0_rd_out[406]
    DIRECTION OUTPUT ;
    USE SIGNAL ;
    SHAPE ABUTMENT ;
    PORT
      LAYER met2 ;
      RECT 189.450 954.300 189.590 954.720 ;
    END
  END rw0_rd_out[406]
  PIN rw0_rd_out[407]
    DIRECTION OUTPUT ;
    USE SIGNAL ;
    SHAPE ABUTMENT ;
    PORT
      LAYER met2 ;
      RECT 189.910 954.300 190.050 954.720 ;
    END
  END rw0_rd_out[407]
  PIN rw0_rd_out[408]
    DIRECTION OUTPUT ;
    USE SIGNAL ;
    SHAPE ABUTMENT ;
    PORT
      LAYER met2 ;
      RECT 190.370 954.300 190.510 954.720 ;
    END
  END rw0_rd_out[408]
  PIN rw0_rd_out[409]
    DIRECTION OUTPUT ;
    USE SIGNAL ;
    SHAPE ABUTMENT ;
    PORT
      LAYER met2 ;
      RECT 190.830 954.300 190.970 954.720 ;
    END
  END rw0_rd_out[409]
  PIN rw0_rd_out[410]
    DIRECTION OUTPUT ;
    USE SIGNAL ;
    SHAPE ABUTMENT ;
    PORT
      LAYER met2 ;
      RECT 191.290 954.300 191.430 954.720 ;
    END
  END rw0_rd_out[410]
  PIN rw0_rd_out[411]
    DIRECTION OUTPUT ;
    USE SIGNAL ;
    SHAPE ABUTMENT ;
    PORT
      LAYER met2 ;
      RECT 191.750 954.300 191.890 954.720 ;
    END
  END rw0_rd_out[411]
  PIN rw0_rd_out[412]
    DIRECTION OUTPUT ;
    USE SIGNAL ;
    SHAPE ABUTMENT ;
    PORT
      LAYER met2 ;
      RECT 192.210 954.300 192.350 954.720 ;
    END
  END rw0_rd_out[412]
  PIN rw0_rd_out[413]
    DIRECTION OUTPUT ;
    USE SIGNAL ;
    SHAPE ABUTMENT ;
    PORT
      LAYER met2 ;
      RECT 192.670 954.300 192.810 954.720 ;
    END
  END rw0_rd_out[413]
  PIN rw0_rd_out[414]
    DIRECTION OUTPUT ;
    USE SIGNAL ;
    SHAPE ABUTMENT ;
    PORT
      LAYER met2 ;
      RECT 193.130 954.300 193.270 954.720 ;
    END
  END rw0_rd_out[414]
  PIN rw0_rd_out[415]
    DIRECTION OUTPUT ;
    USE SIGNAL ;
    SHAPE ABUTMENT ;
    PORT
      LAYER met2 ;
      RECT 193.590 954.300 193.730 954.720 ;
    END
  END rw0_rd_out[415]
  PIN rw0_rd_out[416]
    DIRECTION OUTPUT ;
    USE SIGNAL ;
    SHAPE ABUTMENT ;
    PORT
      LAYER met2 ;
      RECT 194.050 954.300 194.190 954.720 ;
    END
  END rw0_rd_out[416]
  PIN rw0_rd_out[417]
    DIRECTION OUTPUT ;
    USE SIGNAL ;
    SHAPE ABUTMENT ;
    PORT
      LAYER met2 ;
      RECT 194.510 954.300 194.650 954.720 ;
    END
  END rw0_rd_out[417]
  PIN rw0_rd_out[418]
    DIRECTION OUTPUT ;
    USE SIGNAL ;
    SHAPE ABUTMENT ;
    PORT
      LAYER met2 ;
      RECT 194.970 954.300 195.110 954.720 ;
    END
  END rw0_rd_out[418]
  PIN rw0_rd_out[419]
    DIRECTION OUTPUT ;
    USE SIGNAL ;
    SHAPE ABUTMENT ;
    PORT
      LAYER met2 ;
      RECT 195.430 954.300 195.570 954.720 ;
    END
  END rw0_rd_out[419]
  PIN rw0_rd_out[420]
    DIRECTION OUTPUT ;
    USE SIGNAL ;
    SHAPE ABUTMENT ;
    PORT
      LAYER met2 ;
      RECT 195.890 954.300 196.030 954.720 ;
    END
  END rw0_rd_out[420]
  PIN rw0_rd_out[421]
    DIRECTION OUTPUT ;
    USE SIGNAL ;
    SHAPE ABUTMENT ;
    PORT
      LAYER met2 ;
      RECT 196.350 954.300 196.490 954.720 ;
    END
  END rw0_rd_out[421]
  PIN rw0_rd_out[422]
    DIRECTION OUTPUT ;
    USE SIGNAL ;
    SHAPE ABUTMENT ;
    PORT
      LAYER met2 ;
      RECT 196.810 954.300 196.950 954.720 ;
    END
  END rw0_rd_out[422]
  PIN rw0_rd_out[423]
    DIRECTION OUTPUT ;
    USE SIGNAL ;
    SHAPE ABUTMENT ;
    PORT
      LAYER met2 ;
      RECT 197.270 954.300 197.410 954.720 ;
    END
  END rw0_rd_out[423]
  PIN rw0_rd_out[424]
    DIRECTION OUTPUT ;
    USE SIGNAL ;
    SHAPE ABUTMENT ;
    PORT
      LAYER met2 ;
      RECT 197.730 954.300 197.870 954.720 ;
    END
  END rw0_rd_out[424]
  PIN rw0_rd_out[425]
    DIRECTION OUTPUT ;
    USE SIGNAL ;
    SHAPE ABUTMENT ;
    PORT
      LAYER met2 ;
      RECT 198.190 954.300 198.330 954.720 ;
    END
  END rw0_rd_out[425]
  PIN rw0_rd_out[426]
    DIRECTION OUTPUT ;
    USE SIGNAL ;
    SHAPE ABUTMENT ;
    PORT
      LAYER met2 ;
      RECT 198.650 954.300 198.790 954.720 ;
    END
  END rw0_rd_out[426]
  PIN rw0_rd_out[427]
    DIRECTION OUTPUT ;
    USE SIGNAL ;
    SHAPE ABUTMENT ;
    PORT
      LAYER met2 ;
      RECT 199.110 954.300 199.250 954.720 ;
    END
  END rw0_rd_out[427]
  PIN rw0_rd_out[428]
    DIRECTION OUTPUT ;
    USE SIGNAL ;
    SHAPE ABUTMENT ;
    PORT
      LAYER met2 ;
      RECT 199.570 954.300 199.710 954.720 ;
    END
  END rw0_rd_out[428]
  PIN rw0_rd_out[429]
    DIRECTION OUTPUT ;
    USE SIGNAL ;
    SHAPE ABUTMENT ;
    PORT
      LAYER met2 ;
      RECT 200.030 954.300 200.170 954.720 ;
    END
  END rw0_rd_out[429]
  PIN rw0_rd_out[430]
    DIRECTION OUTPUT ;
    USE SIGNAL ;
    SHAPE ABUTMENT ;
    PORT
      LAYER met2 ;
      RECT 200.490 954.300 200.630 954.720 ;
    END
  END rw0_rd_out[430]
  PIN rw0_rd_out[431]
    DIRECTION OUTPUT ;
    USE SIGNAL ;
    SHAPE ABUTMENT ;
    PORT
      LAYER met2 ;
      RECT 200.950 954.300 201.090 954.720 ;
    END
  END rw0_rd_out[431]
  PIN rw0_rd_out[432]
    DIRECTION OUTPUT ;
    USE SIGNAL ;
    SHAPE ABUTMENT ;
    PORT
      LAYER met2 ;
      RECT 201.410 954.300 201.550 954.720 ;
    END
  END rw0_rd_out[432]
  PIN rw0_rd_out[433]
    DIRECTION OUTPUT ;
    USE SIGNAL ;
    SHAPE ABUTMENT ;
    PORT
      LAYER met2 ;
      RECT 201.870 954.300 202.010 954.720 ;
    END
  END rw0_rd_out[433]
  PIN rw0_rd_out[434]
    DIRECTION OUTPUT ;
    USE SIGNAL ;
    SHAPE ABUTMENT ;
    PORT
      LAYER met2 ;
      RECT 202.330 954.300 202.470 954.720 ;
    END
  END rw0_rd_out[434]
  PIN rw0_rd_out[435]
    DIRECTION OUTPUT ;
    USE SIGNAL ;
    SHAPE ABUTMENT ;
    PORT
      LAYER met2 ;
      RECT 202.790 954.300 202.930 954.720 ;
    END
  END rw0_rd_out[435]
  PIN rw0_rd_out[436]
    DIRECTION OUTPUT ;
    USE SIGNAL ;
    SHAPE ABUTMENT ;
    PORT
      LAYER met2 ;
      RECT 203.250 954.300 203.390 954.720 ;
    END
  END rw0_rd_out[436]
  PIN rw0_rd_out[437]
    DIRECTION OUTPUT ;
    USE SIGNAL ;
    SHAPE ABUTMENT ;
    PORT
      LAYER met2 ;
      RECT 203.710 954.300 203.850 954.720 ;
    END
  END rw0_rd_out[437]
  PIN rw0_rd_out[438]
    DIRECTION OUTPUT ;
    USE SIGNAL ;
    SHAPE ABUTMENT ;
    PORT
      LAYER met2 ;
      RECT 204.170 954.300 204.310 954.720 ;
    END
  END rw0_rd_out[438]
  PIN rw0_rd_out[439]
    DIRECTION OUTPUT ;
    USE SIGNAL ;
    SHAPE ABUTMENT ;
    PORT
      LAYER met2 ;
      RECT 204.630 954.300 204.770 954.720 ;
    END
  END rw0_rd_out[439]
  PIN rw0_rd_out[440]
    DIRECTION OUTPUT ;
    USE SIGNAL ;
    SHAPE ABUTMENT ;
    PORT
      LAYER met2 ;
      RECT 205.090 954.300 205.230 954.720 ;
    END
  END rw0_rd_out[440]
  PIN rw0_rd_out[441]
    DIRECTION OUTPUT ;
    USE SIGNAL ;
    SHAPE ABUTMENT ;
    PORT
      LAYER met2 ;
      RECT 205.550 954.300 205.690 954.720 ;
    END
  END rw0_rd_out[441]
  PIN rw0_rd_out[442]
    DIRECTION OUTPUT ;
    USE SIGNAL ;
    SHAPE ABUTMENT ;
    PORT
      LAYER met2 ;
      RECT 206.010 954.300 206.150 954.720 ;
    END
  END rw0_rd_out[442]
  PIN rw0_rd_out[443]
    DIRECTION OUTPUT ;
    USE SIGNAL ;
    SHAPE ABUTMENT ;
    PORT
      LAYER met2 ;
      RECT 206.470 954.300 206.610 954.720 ;
    END
  END rw0_rd_out[443]
  PIN rw0_rd_out[444]
    DIRECTION OUTPUT ;
    USE SIGNAL ;
    SHAPE ABUTMENT ;
    PORT
      LAYER met2 ;
      RECT 206.930 954.300 207.070 954.720 ;
    END
  END rw0_rd_out[444]
  PIN rw0_rd_out[445]
    DIRECTION OUTPUT ;
    USE SIGNAL ;
    SHAPE ABUTMENT ;
    PORT
      LAYER met2 ;
      RECT 207.390 954.300 207.530 954.720 ;
    END
  END rw0_rd_out[445]
  PIN rw0_rd_out[446]
    DIRECTION OUTPUT ;
    USE SIGNAL ;
    SHAPE ABUTMENT ;
    PORT
      LAYER met2 ;
      RECT 207.850 954.300 207.990 954.720 ;
    END
  END rw0_rd_out[446]
  PIN rw0_rd_out[447]
    DIRECTION OUTPUT ;
    USE SIGNAL ;
    SHAPE ABUTMENT ;
    PORT
      LAYER met2 ;
      RECT 208.310 954.300 208.450 954.720 ;
    END
  END rw0_rd_out[447]
  PIN rw0_rd_out[448]
    DIRECTION OUTPUT ;
    USE SIGNAL ;
    SHAPE ABUTMENT ;
    PORT
      LAYER met2 ;
      RECT 208.770 954.300 208.910 954.720 ;
    END
  END rw0_rd_out[448]
  PIN rw0_rd_out[449]
    DIRECTION OUTPUT ;
    USE SIGNAL ;
    SHAPE ABUTMENT ;
    PORT
      LAYER met2 ;
      RECT 209.230 954.300 209.370 954.720 ;
    END
  END rw0_rd_out[449]
  PIN rw0_rd_out[450]
    DIRECTION OUTPUT ;
    USE SIGNAL ;
    SHAPE ABUTMENT ;
    PORT
      LAYER met2 ;
      RECT 209.690 954.300 209.830 954.720 ;
    END
  END rw0_rd_out[450]
  PIN rw0_rd_out[451]
    DIRECTION OUTPUT ;
    USE SIGNAL ;
    SHAPE ABUTMENT ;
    PORT
      LAYER met2 ;
      RECT 210.150 954.300 210.290 954.720 ;
    END
  END rw0_rd_out[451]
  PIN rw0_rd_out[452]
    DIRECTION OUTPUT ;
    USE SIGNAL ;
    SHAPE ABUTMENT ;
    PORT
      LAYER met2 ;
      RECT 210.610 954.300 210.750 954.720 ;
    END
  END rw0_rd_out[452]
  PIN rw0_rd_out[453]
    DIRECTION OUTPUT ;
    USE SIGNAL ;
    SHAPE ABUTMENT ;
    PORT
      LAYER met2 ;
      RECT 211.070 954.300 211.210 954.720 ;
    END
  END rw0_rd_out[453]
  PIN rw0_rd_out[454]
    DIRECTION OUTPUT ;
    USE SIGNAL ;
    SHAPE ABUTMENT ;
    PORT
      LAYER met2 ;
      RECT 211.530 954.300 211.670 954.720 ;
    END
  END rw0_rd_out[454]
  PIN rw0_rd_out[455]
    DIRECTION OUTPUT ;
    USE SIGNAL ;
    SHAPE ABUTMENT ;
    PORT
      LAYER met2 ;
      RECT 211.990 954.300 212.130 954.720 ;
    END
  END rw0_rd_out[455]
  PIN rw0_rd_out[456]
    DIRECTION OUTPUT ;
    USE SIGNAL ;
    SHAPE ABUTMENT ;
    PORT
      LAYER met2 ;
      RECT 212.450 954.300 212.590 954.720 ;
    END
  END rw0_rd_out[456]
  PIN rw0_rd_out[457]
    DIRECTION OUTPUT ;
    USE SIGNAL ;
    SHAPE ABUTMENT ;
    PORT
      LAYER met2 ;
      RECT 212.910 954.300 213.050 954.720 ;
    END
  END rw0_rd_out[457]
  PIN rw0_rd_out[458]
    DIRECTION OUTPUT ;
    USE SIGNAL ;
    SHAPE ABUTMENT ;
    PORT
      LAYER met2 ;
      RECT 213.370 954.300 213.510 954.720 ;
    END
  END rw0_rd_out[458]
  PIN rw0_rd_out[459]
    DIRECTION OUTPUT ;
    USE SIGNAL ;
    SHAPE ABUTMENT ;
    PORT
      LAYER met2 ;
      RECT 213.830 954.300 213.970 954.720 ;
    END
  END rw0_rd_out[459]
  PIN rw0_rd_out[460]
    DIRECTION OUTPUT ;
    USE SIGNAL ;
    SHAPE ABUTMENT ;
    PORT
      LAYER met2 ;
      RECT 214.290 954.300 214.430 954.720 ;
    END
  END rw0_rd_out[460]
  PIN rw0_rd_out[461]
    DIRECTION OUTPUT ;
    USE SIGNAL ;
    SHAPE ABUTMENT ;
    PORT
      LAYER met2 ;
      RECT 214.750 954.300 214.890 954.720 ;
    END
  END rw0_rd_out[461]
  PIN rw0_rd_out[462]
    DIRECTION OUTPUT ;
    USE SIGNAL ;
    SHAPE ABUTMENT ;
    PORT
      LAYER met2 ;
      RECT 215.210 954.300 215.350 954.720 ;
    END
  END rw0_rd_out[462]
  PIN rw0_rd_out[463]
    DIRECTION OUTPUT ;
    USE SIGNAL ;
    SHAPE ABUTMENT ;
    PORT
      LAYER met2 ;
      RECT 215.670 954.300 215.810 954.720 ;
    END
  END rw0_rd_out[463]
  PIN rw0_rd_out[464]
    DIRECTION OUTPUT ;
    USE SIGNAL ;
    SHAPE ABUTMENT ;
    PORT
      LAYER met2 ;
      RECT 216.130 954.300 216.270 954.720 ;
    END
  END rw0_rd_out[464]
  PIN rw0_rd_out[465]
    DIRECTION OUTPUT ;
    USE SIGNAL ;
    SHAPE ABUTMENT ;
    PORT
      LAYER met2 ;
      RECT 216.590 954.300 216.730 954.720 ;
    END
  END rw0_rd_out[465]
  PIN rw0_rd_out[466]
    DIRECTION OUTPUT ;
    USE SIGNAL ;
    SHAPE ABUTMENT ;
    PORT
      LAYER met2 ;
      RECT 217.050 954.300 217.190 954.720 ;
    END
  END rw0_rd_out[466]
  PIN rw0_rd_out[467]
    DIRECTION OUTPUT ;
    USE SIGNAL ;
    SHAPE ABUTMENT ;
    PORT
      LAYER met2 ;
      RECT 217.510 954.300 217.650 954.720 ;
    END
  END rw0_rd_out[467]
  PIN rw0_rd_out[468]
    DIRECTION OUTPUT ;
    USE SIGNAL ;
    SHAPE ABUTMENT ;
    PORT
      LAYER met2 ;
      RECT 217.970 954.300 218.110 954.720 ;
    END
  END rw0_rd_out[468]
  PIN rw0_rd_out[469]
    DIRECTION OUTPUT ;
    USE SIGNAL ;
    SHAPE ABUTMENT ;
    PORT
      LAYER met2 ;
      RECT 218.430 954.300 218.570 954.720 ;
    END
  END rw0_rd_out[469]
  PIN rw0_rd_out[470]
    DIRECTION OUTPUT ;
    USE SIGNAL ;
    SHAPE ABUTMENT ;
    PORT
      LAYER met2 ;
      RECT 218.890 954.300 219.030 954.720 ;
    END
  END rw0_rd_out[470]
  PIN rw0_rd_out[471]
    DIRECTION OUTPUT ;
    USE SIGNAL ;
    SHAPE ABUTMENT ;
    PORT
      LAYER met2 ;
      RECT 219.350 954.300 219.490 954.720 ;
    END
  END rw0_rd_out[471]
  PIN rw0_rd_out[472]
    DIRECTION OUTPUT ;
    USE SIGNAL ;
    SHAPE ABUTMENT ;
    PORT
      LAYER met2 ;
      RECT 219.810 954.300 219.950 954.720 ;
    END
  END rw0_rd_out[472]
  PIN rw0_rd_out[473]
    DIRECTION OUTPUT ;
    USE SIGNAL ;
    SHAPE ABUTMENT ;
    PORT
      LAYER met2 ;
      RECT 220.270 954.300 220.410 954.720 ;
    END
  END rw0_rd_out[473]
  PIN rw0_rd_out[474]
    DIRECTION OUTPUT ;
    USE SIGNAL ;
    SHAPE ABUTMENT ;
    PORT
      LAYER met2 ;
      RECT 220.730 954.300 220.870 954.720 ;
    END
  END rw0_rd_out[474]
  PIN rw0_rd_out[475]
    DIRECTION OUTPUT ;
    USE SIGNAL ;
    SHAPE ABUTMENT ;
    PORT
      LAYER met2 ;
      RECT 221.190 954.300 221.330 954.720 ;
    END
  END rw0_rd_out[475]
  PIN rw0_rd_out[476]
    DIRECTION OUTPUT ;
    USE SIGNAL ;
    SHAPE ABUTMENT ;
    PORT
      LAYER met2 ;
      RECT 221.650 954.300 221.790 954.720 ;
    END
  END rw0_rd_out[476]
  PIN rw0_rd_out[477]
    DIRECTION OUTPUT ;
    USE SIGNAL ;
    SHAPE ABUTMENT ;
    PORT
      LAYER met2 ;
      RECT 222.110 954.300 222.250 954.720 ;
    END
  END rw0_rd_out[477]
  PIN rw0_rd_out[478]
    DIRECTION OUTPUT ;
    USE SIGNAL ;
    SHAPE ABUTMENT ;
    PORT
      LAYER met2 ;
      RECT 222.570 954.300 222.710 954.720 ;
    END
  END rw0_rd_out[478]
  PIN rw0_rd_out[479]
    DIRECTION OUTPUT ;
    USE SIGNAL ;
    SHAPE ABUTMENT ;
    PORT
      LAYER met2 ;
      RECT 223.030 954.300 223.170 954.720 ;
    END
  END rw0_rd_out[479]
  PIN rw0_rd_out[480]
    DIRECTION OUTPUT ;
    USE SIGNAL ;
    SHAPE ABUTMENT ;
    PORT
      LAYER met2 ;
      RECT 223.490 954.300 223.630 954.720 ;
    END
  END rw0_rd_out[480]
  PIN rw0_rd_out[481]
    DIRECTION OUTPUT ;
    USE SIGNAL ;
    SHAPE ABUTMENT ;
    PORT
      LAYER met2 ;
      RECT 223.950 954.300 224.090 954.720 ;
    END
  END rw0_rd_out[481]
  PIN rw0_rd_out[482]
    DIRECTION OUTPUT ;
    USE SIGNAL ;
    SHAPE ABUTMENT ;
    PORT
      LAYER met2 ;
      RECT 224.410 954.300 224.550 954.720 ;
    END
  END rw0_rd_out[482]
  PIN rw0_rd_out[483]
    DIRECTION OUTPUT ;
    USE SIGNAL ;
    SHAPE ABUTMENT ;
    PORT
      LAYER met2 ;
      RECT 224.870 954.300 225.010 954.720 ;
    END
  END rw0_rd_out[483]
  PIN rw0_rd_out[484]
    DIRECTION OUTPUT ;
    USE SIGNAL ;
    SHAPE ABUTMENT ;
    PORT
      LAYER met2 ;
      RECT 225.330 954.300 225.470 954.720 ;
    END
  END rw0_rd_out[484]
  PIN rw0_rd_out[485]
    DIRECTION OUTPUT ;
    USE SIGNAL ;
    SHAPE ABUTMENT ;
    PORT
      LAYER met2 ;
      RECT 225.790 954.300 225.930 954.720 ;
    END
  END rw0_rd_out[485]
  PIN rw0_rd_out[486]
    DIRECTION OUTPUT ;
    USE SIGNAL ;
    SHAPE ABUTMENT ;
    PORT
      LAYER met2 ;
      RECT 226.250 954.300 226.390 954.720 ;
    END
  END rw0_rd_out[486]
  PIN rw0_rd_out[487]
    DIRECTION OUTPUT ;
    USE SIGNAL ;
    SHAPE ABUTMENT ;
    PORT
      LAYER met2 ;
      RECT 226.710 954.300 226.850 954.720 ;
    END
  END rw0_rd_out[487]
  PIN rw0_rd_out[488]
    DIRECTION OUTPUT ;
    USE SIGNAL ;
    SHAPE ABUTMENT ;
    PORT
      LAYER met2 ;
      RECT 227.170 954.300 227.310 954.720 ;
    END
  END rw0_rd_out[488]
  PIN rw0_rd_out[489]
    DIRECTION OUTPUT ;
    USE SIGNAL ;
    SHAPE ABUTMENT ;
    PORT
      LAYER met2 ;
      RECT 227.630 954.300 227.770 954.720 ;
    END
  END rw0_rd_out[489]
  PIN rw0_rd_out[490]
    DIRECTION OUTPUT ;
    USE SIGNAL ;
    SHAPE ABUTMENT ;
    PORT
      LAYER met2 ;
      RECT 228.090 954.300 228.230 954.720 ;
    END
  END rw0_rd_out[490]
  PIN rw0_rd_out[491]
    DIRECTION OUTPUT ;
    USE SIGNAL ;
    SHAPE ABUTMENT ;
    PORT
      LAYER met2 ;
      RECT 228.550 954.300 228.690 954.720 ;
    END
  END rw0_rd_out[491]
  PIN rw0_rd_out[492]
    DIRECTION OUTPUT ;
    USE SIGNAL ;
    SHAPE ABUTMENT ;
    PORT
      LAYER met2 ;
      RECT 229.010 954.300 229.150 954.720 ;
    END
  END rw0_rd_out[492]
  PIN rw0_rd_out[493]
    DIRECTION OUTPUT ;
    USE SIGNAL ;
    SHAPE ABUTMENT ;
    PORT
      LAYER met2 ;
      RECT 229.470 954.300 229.610 954.720 ;
    END
  END rw0_rd_out[493]
  PIN rw0_rd_out[494]
    DIRECTION OUTPUT ;
    USE SIGNAL ;
    SHAPE ABUTMENT ;
    PORT
      LAYER met2 ;
      RECT 229.930 954.300 230.070 954.720 ;
    END
  END rw0_rd_out[494]
  PIN rw0_rd_out[495]
    DIRECTION OUTPUT ;
    USE SIGNAL ;
    SHAPE ABUTMENT ;
    PORT
      LAYER met2 ;
      RECT 230.390 954.300 230.530 954.720 ;
    END
  END rw0_rd_out[495]
  PIN rw0_rd_out[496]
    DIRECTION OUTPUT ;
    USE SIGNAL ;
    SHAPE ABUTMENT ;
    PORT
      LAYER met2 ;
      RECT 230.850 954.300 230.990 954.720 ;
    END
  END rw0_rd_out[496]
  PIN rw0_rd_out[497]
    DIRECTION OUTPUT ;
    USE SIGNAL ;
    SHAPE ABUTMENT ;
    PORT
      LAYER met2 ;
      RECT 231.310 954.300 231.450 954.720 ;
    END
  END rw0_rd_out[497]
  PIN rw0_rd_out[498]
    DIRECTION OUTPUT ;
    USE SIGNAL ;
    SHAPE ABUTMENT ;
    PORT
      LAYER met2 ;
      RECT 231.770 954.300 231.910 954.720 ;
    END
  END rw0_rd_out[498]
  PIN rw0_rd_out[499]
    DIRECTION OUTPUT ;
    USE SIGNAL ;
    SHAPE ABUTMENT ;
    PORT
      LAYER met2 ;
      RECT 232.230 954.300 232.370 954.720 ;
    END
  END rw0_rd_out[499]
  PIN rw0_rd_out[500]
    DIRECTION OUTPUT ;
    USE SIGNAL ;
    SHAPE ABUTMENT ;
    PORT
      LAYER met2 ;
      RECT 232.690 954.300 232.830 954.720 ;
    END
  END rw0_rd_out[500]
  PIN rw0_rd_out[501]
    DIRECTION OUTPUT ;
    USE SIGNAL ;
    SHAPE ABUTMENT ;
    PORT
      LAYER met2 ;
      RECT 233.150 954.300 233.290 954.720 ;
    END
  END rw0_rd_out[501]
  PIN rw0_rd_out[502]
    DIRECTION OUTPUT ;
    USE SIGNAL ;
    SHAPE ABUTMENT ;
    PORT
      LAYER met2 ;
      RECT 233.610 954.300 233.750 954.720 ;
    END
  END rw0_rd_out[502]
  PIN rw0_rd_out[503]
    DIRECTION OUTPUT ;
    USE SIGNAL ;
    SHAPE ABUTMENT ;
    PORT
      LAYER met2 ;
      RECT 234.070 954.300 234.210 954.720 ;
    END
  END rw0_rd_out[503]
  PIN rw0_rd_out[504]
    DIRECTION OUTPUT ;
    USE SIGNAL ;
    SHAPE ABUTMENT ;
    PORT
      LAYER met2 ;
      RECT 234.530 954.300 234.670 954.720 ;
    END
  END rw0_rd_out[504]
  PIN rw0_rd_out[505]
    DIRECTION OUTPUT ;
    USE SIGNAL ;
    SHAPE ABUTMENT ;
    PORT
      LAYER met2 ;
      RECT 234.990 954.300 235.130 954.720 ;
    END
  END rw0_rd_out[505]
  PIN rw0_rd_out[506]
    DIRECTION OUTPUT ;
    USE SIGNAL ;
    SHAPE ABUTMENT ;
    PORT
      LAYER met2 ;
      RECT 235.450 954.300 235.590 954.720 ;
    END
  END rw0_rd_out[506]
  PIN rw0_rd_out[507]
    DIRECTION OUTPUT ;
    USE SIGNAL ;
    SHAPE ABUTMENT ;
    PORT
      LAYER met2 ;
      RECT 235.910 954.300 236.050 954.720 ;
    END
  END rw0_rd_out[507]
  PIN rw0_rd_out[508]
    DIRECTION OUTPUT ;
    USE SIGNAL ;
    SHAPE ABUTMENT ;
    PORT
      LAYER met2 ;
      RECT 236.370 954.300 236.510 954.720 ;
    END
  END rw0_rd_out[508]
  PIN rw0_rd_out[509]
    DIRECTION OUTPUT ;
    USE SIGNAL ;
    SHAPE ABUTMENT ;
    PORT
      LAYER met2 ;
      RECT 236.830 954.300 236.970 954.720 ;
    END
  END rw0_rd_out[509]
  PIN rw0_rd_out[510]
    DIRECTION OUTPUT ;
    USE SIGNAL ;
    SHAPE ABUTMENT ;
    PORT
      LAYER met2 ;
      RECT 237.290 954.300 237.430 954.720 ;
    END
  END rw0_rd_out[510]
  PIN rw0_rd_out[511]
    DIRECTION OUTPUT ;
    USE SIGNAL ;
    SHAPE ABUTMENT ;
    PORT
      LAYER met2 ;
      RECT 237.750 954.300 237.890 954.720 ;
    END
  END rw0_rd_out[511]
  PIN rw0_addr_in[0]
    DIRECTION INPUT ;
    USE SIGNAL ;
    SHAPE ABUTMENT ;
    PORT
      LAYER met3 ;
      RECT 0.000 874.330 0.900 874.630 ;
    END
  END rw0_addr_in[0]
  PIN rw0_addr_in[1]
    DIRECTION INPUT ;
    USE SIGNAL ;
    SHAPE ABUTMENT ;
    PORT
      LAYER met3 ;
      RECT 0.000 877.730 0.900 878.030 ;
    END
  END rw0_addr_in[1]
  PIN rw0_addr_in[2]
    DIRECTION INPUT ;
    USE SIGNAL ;
    SHAPE ABUTMENT ;
    PORT
      LAYER met3 ;
      RECT 0.000 881.130 0.900 881.430 ;
    END
  END rw0_addr_in[2]
  PIN rw0_addr_in[3]
    DIRECTION INPUT ;
    USE SIGNAL ;
    SHAPE ABUTMENT ;
    PORT
      LAYER met3 ;
      RECT 468.300 874.330 469.200 874.630 ;
    END
  END rw0_addr_in[3]
  PIN rw0_addr_in[4]
    DIRECTION INPUT ;
    USE SIGNAL ;
    SHAPE ABUTMENT ;
    PORT
      LAYER met3 ;
      RECT 468.300 877.730 469.200 878.030 ;
    END
  END rw0_addr_in[4]
  PIN rw0_addr_in[5]
    DIRECTION INPUT ;
    USE SIGNAL ;
    SHAPE ABUTMENT ;
    PORT
      LAYER met3 ;
      RECT 468.300 881.130 469.200 881.430 ;
    END
  END rw0_addr_in[5]
  PIN rw0_we_in
    DIRECTION INPUT ;
    USE SIGNAL ;
    SHAPE ABUTMENT ;
    PORT
      LAYER met2 ;
      RECT 238.210 954.300 238.350 954.720 ;
    END
  END rw0_we_in
  PIN rw0_ce_in
    DIRECTION INPUT ;
    USE SIGNAL ;
    SHAPE ABUTMENT ;
    PORT
      LAYER met2 ;
      RECT 238.670 954.300 238.810 954.720 ;
    END
  END rw0_ce_in
  PIN rw0_clk
    DIRECTION INPUT ;
    USE SIGNAL ;
    SHAPE ABUTMENT ;
    PORT
      LAYER met2 ;
      RECT 239.130 954.300 239.270 954.720 ;
    END
  END rw0_clk
  PIN VSS
    DIRECTION INOUT ;
    USE GROUND ;
    PORT
      LAYER met4 ;
      RECT 2.160 4.080 3.360 950.640 ;
      RECT 13.040 4.080 14.240 950.640 ;
      RECT 23.920 4.080 25.120 950.640 ;
      RECT 34.800 4.080 36.000 950.640 ;
      RECT 45.680 4.080 46.880 950.640 ;
      RECT 56.560 4.080 57.760 950.640 ;
      RECT 67.440 4.080 68.640 950.640 ;
      RECT 78.320 4.080 79.520 950.640 ;
      RECT 89.200 4.080 90.400 950.640 ;
      RECT 100.080 4.080 101.280 950.640 ;
      RECT 110.960 4.080 112.160 950.640 ;
      RECT 121.840 4.080 123.040 950.640 ;
      RECT 132.720 4.080 133.920 950.640 ;
      RECT 143.600 4.080 144.800 950.640 ;
      RECT 154.480 4.080 155.680 950.640 ;
      RECT 165.360 4.080 166.560 950.640 ;
      RECT 176.240 4.080 177.440 950.640 ;
      RECT 187.120 4.080 188.320 950.640 ;
      RECT 198.000 4.080 199.200 950.640 ;
      RECT 208.880 4.080 210.080 950.640 ;
      RECT 219.760 4.080 220.960 950.640 ;
      RECT 230.640 4.080 231.840 950.640 ;
      RECT 241.520 4.080 242.720 950.640 ;
      RECT 252.400 4.080 253.600 950.640 ;
      RECT 263.280 4.080 264.480 950.640 ;
      RECT 274.160 4.080 275.360 950.640 ;
      RECT 285.040 4.080 286.240 950.640 ;
      RECT 295.920 4.080 297.120 950.640 ;
      RECT 306.800 4.080 308.000 950.640 ;
      RECT 317.680 4.080 318.880 950.640 ;
      RECT 328.560 4.080 329.760 950.640 ;
      RECT 339.440 4.080 340.640 950.640 ;
      RECT 350.320 4.080 351.520 950.640 ;
      RECT 361.200 4.080 362.400 950.640 ;
      RECT 372.080 4.080 373.280 950.640 ;
      RECT 382.960 4.080 384.160 950.640 ;
      RECT 393.840 4.080 395.040 950.640 ;
      RECT 404.720 4.080 405.920 950.640 ;
      RECT 415.600 4.080 416.800 950.640 ;
      RECT 426.480 4.080 427.680 950.640 ;
      RECT 437.360 4.080 438.560 950.640 ;
      RECT 448.240 4.080 449.440 950.640 ;
      RECT 459.120 4.080 460.320 950.640 ;
    END
  END VSS
  PIN VDD
    DIRECTION INOUT ;
    USE POWER ;
    PORT
      LAYER met4 ;
      RECT 2.160 4.080 3.360 950.640 ;
      RECT 13.040 4.080 14.240 950.640 ;
      RECT 23.920 4.080 25.120 950.640 ;
      RECT 34.800 4.080 36.000 950.640 ;
      RECT 45.680 4.080 46.880 950.640 ;
      RECT 56.560 4.080 57.760 950.640 ;
      RECT 67.440 4.080 68.640 950.640 ;
      RECT 78.320 4.080 79.520 950.640 ;
      RECT 89.200 4.080 90.400 950.640 ;
      RECT 100.080 4.080 101.280 950.640 ;
      RECT 110.960 4.080 112.160 950.640 ;
      RECT 121.840 4.080 123.040 950.640 ;
      RECT 132.720 4.080 133.920 950.640 ;
      RECT 143.600 4.080 144.800 950.640 ;
      RECT 154.480 4.080 155.680 950.640 ;
      RECT 165.360 4.080 166.560 950.640 ;
      RECT 176.240 4.080 177.440 950.640 ;
      RECT 187.120 4.080 188.320 950.640 ;
      RECT 198.000 4.080 199.200 950.640 ;
      RECT 208.880 4.080 210.080 950.640 ;
      RECT 219.760 4.080 220.960 950.640 ;
      RECT 230.640 4.080 231.840 950.640 ;
      RECT 241.520 4.080 242.720 950.640 ;
      RECT 252.400 4.080 253.600 950.640 ;
      RECT 263.280 4.080 264.480 950.640 ;
      RECT 274.160 4.080 275.360 950.640 ;
      RECT 285.040 4.080 286.240 950.640 ;
      RECT 295.920 4.080 297.120 950.640 ;
      RECT 306.800 4.080 308.000 950.640 ;
      RECT 317.680 4.080 318.880 950.640 ;
      RECT 328.560 4.080 329.760 950.640 ;
      RECT 339.440 4.080 340.640 950.640 ;
      RECT 350.320 4.080 351.520 950.640 ;
      RECT 361.200 4.080 362.400 950.640 ;
      RECT 372.080 4.080 373.280 950.640 ;
      RECT 382.960 4.080 384.160 950.640 ;
      RECT 393.840 4.080 395.040 950.640 ;
      RECT 404.720 4.080 405.920 950.640 ;
      RECT 415.600 4.080 416.800 950.640 ;
      RECT 426.480 4.080 427.680 950.640 ;
      RECT 437.360 4.080 438.560 950.640 ;
      RECT 448.240 4.080 449.440 950.640 ;
      RECT 459.120 4.080 460.320 950.640 ;
    END
  END VDD
  OBS
    LAYER met1 ;
    RECT 0 0 469.200 954.720 ;
    LAYER met2 ;
    RECT 0 0 469.200 954.720 ;
    LAYER met3 ;
    RECT 0 0 469.200 954.720 ;
    LAYER met4 ;
    RECT 0 0 469.200 954.720 ;
  END
END fakeram_512x64_1rw

END LIBRARY
